VERSION 5.8 ;
BUSBITCHARS "[]" ;
DIVIDERCHAR "/" ;
UNITS
    DATABASE MICRONS 1000 ;
END UNITS

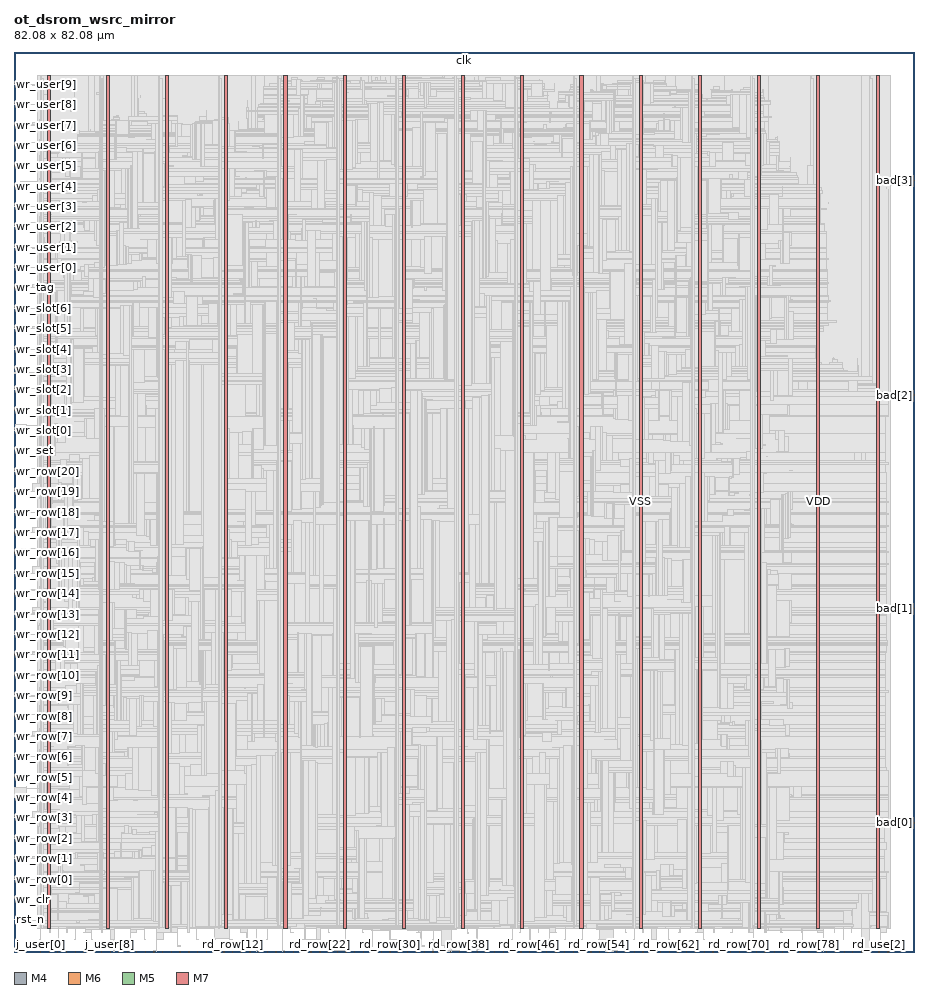
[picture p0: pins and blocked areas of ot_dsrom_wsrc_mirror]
MACRO ot_dsrom_wsrc_mirror
  FOREIGN ot_dsrom_wsrc_mirror 0 0 ;
  CLASS BLOCK ;
  SIZE 82.08 BY 82.08 ;
  PIN bad[0]
    DIRECTION OUTPUT ;
    USE SIGNAL ;
    PORT
      LAYER M4 ;
        RECT  81.996 11.76 82.08 11.784 ;
    END
  END bad[0]
  PIN bad[1]
    DIRECTION OUTPUT ;
    USE SIGNAL ;
    PORT
      LAYER M6 ;
        RECT  82.01 31.296 82.08 31.328 ;
    END
  END bad[1]
  PIN bad[2]
    DIRECTION OUTPUT ;
    USE SIGNAL ;
    PORT
      LAYER M4 ;
        RECT  81.996 50.784 82.08 50.808 ;
    END
  END bad[2]
  PIN bad[3]
    DIRECTION OUTPUT ;
    USE SIGNAL ;
    PORT
      LAYER M6 ;
        RECT  82.01 70.336 82.08 70.368 ;
    END
  END bad[3]
  PIN clk
    DIRECTION INPUT ;
    USE SIGNAL ;
    PORT
      LAYER M5 ;
        RECT  41.04 81.996 41.064 82.08 ;
    END
  END clk
  PIN j_user[0]
    DIRECTION INPUT ;
    USE SIGNAL ;
    PORT
      LAYER M5 ;
        RECT  2.4 0 2.424 0.084 ;
    END
  END j_user[0]
  PIN j_user[1]
    DIRECTION INPUT ;
    USE SIGNAL ;
    PORT
      LAYER M7 ;
        RECT  3.2 0 3.232 0.07 ;
    END
  END j_user[1]
  PIN j_user[2]
    DIRECTION INPUT ;
    USE SIGNAL ;
    PORT
      LAYER M5 ;
        RECT  3.984 0 4.008 0.084 ;
    END
  END j_user[2]
  PIN j_user[3]
    DIRECTION INPUT ;
    USE SIGNAL ;
    PORT
      LAYER M7 ;
        RECT  4.8 0 4.832 0.07 ;
    END
  END j_user[3]
  PIN j_user[4]
    DIRECTION INPUT ;
    USE SIGNAL ;
    PORT
      LAYER M5 ;
        RECT  5.568 0 5.592 0.084 ;
    END
  END j_user[4]
  PIN j_user[5]
    DIRECTION INPUT ;
    USE SIGNAL ;
    PORT
      LAYER M7 ;
        RECT  6.336 0 6.368 0.07 ;
    END
  END j_user[5]
  PIN j_user[6]
    DIRECTION INPUT ;
    USE SIGNAL ;
    PORT
      LAYER M5 ;
        RECT  7.152 0 7.176 0.084 ;
    END
  END j_user[6]
  PIN j_user[7]
    DIRECTION INPUT ;
    USE SIGNAL ;
    PORT
      LAYER M7 ;
        RECT  7.936 0 7.968 0.07 ;
    END
  END j_user[7]
  PIN j_user[8]
    DIRECTION INPUT ;
    USE SIGNAL ;
    PORT
      LAYER M5 ;
        RECT  8.784 0 8.808 0.084 ;
    END
  END j_user[8]
  PIN j_user[9]
    DIRECTION INPUT ;
    USE SIGNAL ;
    PORT
      LAYER M7 ;
        RECT  9.536 0 9.568 0.07 ;
    END
  END j_user[9]
  PIN rd_row[0]
    DIRECTION INPUT ;
    USE SIGNAL ;
    PORT
      LAYER M5 ;
        RECT  10.368 0 10.392 0.084 ;
    END
  END rd_row[0]
  PIN rd_row[10]
    DIRECTION INPUT ;
    USE SIGNAL ;
    PORT
      LAYER M5 ;
        RECT  18.336 0 18.36 0.084 ;
    END
  END rd_row[10]
  PIN rd_row[11]
    DIRECTION INPUT ;
    USE SIGNAL ;
    PORT
      LAYER M7 ;
        RECT  19.136 0 19.168 0.07 ;
    END
  END rd_row[11]
  PIN rd_row[12]
    DIRECTION INPUT ;
    USE SIGNAL ;
    PORT
      LAYER M5 ;
        RECT  19.92 0 19.944 0.084 ;
    END
  END rd_row[12]
  PIN rd_row[13]
    DIRECTION INPUT ;
    USE SIGNAL ;
    PORT
      LAYER M7 ;
        RECT  20.736 0 20.768 0.07 ;
    END
  END rd_row[13]
  PIN rd_row[14]
    DIRECTION INPUT ;
    USE SIGNAL ;
    PORT
      LAYER M5 ;
        RECT  21.504 0 21.528 0.084 ;
    END
  END rd_row[14]
  PIN rd_row[15]
    DIRECTION INPUT ;
    USE SIGNAL ;
    PORT
      LAYER M7 ;
        RECT  22.272 0 22.304 0.07 ;
    END
  END rd_row[15]
  PIN rd_row[16]
    DIRECTION INPUT ;
    USE SIGNAL ;
    PORT
      LAYER M5 ;
        RECT  23.088 0 23.112 0.084 ;
    END
  END rd_row[16]
  PIN rd_row[17]
    DIRECTION INPUT ;
    USE SIGNAL ;
    PORT
      LAYER M7 ;
        RECT  23.872 0 23.904 0.07 ;
    END
  END rd_row[17]
  PIN rd_row[18]
    DIRECTION INPUT ;
    USE SIGNAL ;
    PORT
      LAYER M5 ;
        RECT  24.672 0 24.696 0.084 ;
    END
  END rd_row[18]
  PIN rd_row[19]
    DIRECTION INPUT ;
    USE SIGNAL ;
    PORT
      LAYER M7 ;
        RECT  25.472 0 25.504 0.07 ;
    END
  END rd_row[19]
  PIN rd_row[1]
    DIRECTION INPUT ;
    USE SIGNAL ;
    PORT
      LAYER M7 ;
        RECT  11.136 0 11.168 0.07 ;
    END
  END rd_row[1]
  PIN rd_row[20]
    DIRECTION INPUT ;
    USE SIGNAL ;
    PORT
      LAYER M5 ;
        RECT  26.304 0 26.328 0.084 ;
    END
  END rd_row[20]
  PIN rd_row[21]
    DIRECTION INPUT ;
    USE SIGNAL ;
    PORT
      LAYER M7 ;
        RECT  27.072 0 27.104 0.07 ;
    END
  END rd_row[21]
  PIN rd_row[22]
    DIRECTION INPUT ;
    USE SIGNAL ;
    PORT
      LAYER M5 ;
        RECT  27.888 0 27.912 0.084 ;
    END
  END rd_row[22]
  PIN rd_row[23]
    DIRECTION INPUT ;
    USE SIGNAL ;
    PORT
      LAYER M7 ;
        RECT  28.672 0 28.704 0.07 ;
    END
  END rd_row[23]
  PIN rd_row[24]
    DIRECTION INPUT ;
    USE SIGNAL ;
    PORT
      LAYER M5 ;
        RECT  29.472 0 29.496 0.084 ;
    END
  END rd_row[24]
  PIN rd_row[25]
    DIRECTION INPUT ;
    USE SIGNAL ;
    PORT
      LAYER M7 ;
        RECT  30.272 0 30.304 0.07 ;
    END
  END rd_row[25]
  PIN rd_row[26]
    DIRECTION INPUT ;
    USE SIGNAL ;
    PORT
      LAYER M5 ;
        RECT  31.056 0 31.08 0.084 ;
    END
  END rd_row[26]
  PIN rd_row[27]
    DIRECTION INPUT ;
    USE SIGNAL ;
    PORT
      LAYER M7 ;
        RECT  31.872 0 31.904 0.07 ;
    END
  END rd_row[27]
  PIN rd_row[28]
    DIRECTION INPUT ;
    USE SIGNAL ;
    PORT
      LAYER M5 ;
        RECT  32.64 0 32.664 0.084 ;
    END
  END rd_row[28]
  PIN rd_row[29]
    DIRECTION INPUT ;
    USE SIGNAL ;
    PORT
      LAYER M7 ;
        RECT  33.472 0 33.504 0.07 ;
    END
  END rd_row[29]
  PIN rd_row[2]
    DIRECTION INPUT ;
    USE SIGNAL ;
    PORT
      LAYER M5 ;
        RECT  11.952 0 11.976 0.084 ;
    END
  END rd_row[2]
  PIN rd_row[30]
    DIRECTION INPUT ;
    USE SIGNAL ;
    PORT
      LAYER M5 ;
        RECT  34.272 0 34.296 0.084 ;
    END
  END rd_row[30]
  PIN rd_row[31]
    DIRECTION INPUT ;
    USE SIGNAL ;
    PORT
      LAYER M7 ;
        RECT  35.072 0 35.104 0.07 ;
    END
  END rd_row[31]
  PIN rd_row[32]
    DIRECTION INPUT ;
    USE SIGNAL ;
    PORT
      LAYER M5 ;
        RECT  35.856 0 35.88 0.084 ;
    END
  END rd_row[32]
  PIN rd_row[33]
    DIRECTION INPUT ;
    USE SIGNAL ;
    PORT
      LAYER M7 ;
        RECT  36.672 0 36.704 0.07 ;
    END
  END rd_row[33]
  PIN rd_row[34]
    DIRECTION INPUT ;
    USE SIGNAL ;
    PORT
      LAYER M5 ;
        RECT  37.44 0 37.464 0.084 ;
    END
  END rd_row[34]
  PIN rd_row[35]
    DIRECTION INPUT ;
    USE SIGNAL ;
    PORT
      LAYER M7 ;
        RECT  38.208 0 38.24 0.07 ;
    END
  END rd_row[35]
  PIN rd_row[36]
    DIRECTION INPUT ;
    USE SIGNAL ;
    PORT
      LAYER M5 ;
        RECT  39.024 0 39.048 0.084 ;
    END
  END rd_row[36]
  PIN rd_row[37]
    DIRECTION INPUT ;
    USE SIGNAL ;
    PORT
      LAYER M7 ;
        RECT  39.808 0 39.84 0.07 ;
    END
  END rd_row[37]
  PIN rd_row[38]
    DIRECTION INPUT ;
    USE SIGNAL ;
    PORT
      LAYER M5 ;
        RECT  40.608 0 40.632 0.084 ;
    END
  END rd_row[38]
  PIN rd_row[39]
    DIRECTION INPUT ;
    USE SIGNAL ;
    PORT
      LAYER M7 ;
        RECT  41.408 0 41.44 0.07 ;
    END
  END rd_row[39]
  PIN rd_row[3]
    DIRECTION INPUT ;
    USE SIGNAL ;
    PORT
      LAYER M7 ;
        RECT  12.736 0 12.768 0.07 ;
    END
  END rd_row[3]
  PIN rd_row[40]
    DIRECTION INPUT ;
    USE SIGNAL ;
    PORT
      LAYER M5 ;
        RECT  42.24 0 42.264 0.084 ;
    END
  END rd_row[40]
  PIN rd_row[41]
    DIRECTION INPUT ;
    USE SIGNAL ;
    PORT
      LAYER M7 ;
        RECT  43.008 0 43.04 0.07 ;
    END
  END rd_row[41]
  PIN rd_row[42]
    DIRECTION INPUT ;
    USE SIGNAL ;
    PORT
      LAYER M5 ;
        RECT  43.824 0 43.848 0.084 ;
    END
  END rd_row[42]
  PIN rd_row[43]
    DIRECTION INPUT ;
    USE SIGNAL ;
    PORT
      LAYER M7 ;
        RECT  44.608 0 44.64 0.07 ;
    END
  END rd_row[43]
  PIN rd_row[44]
    DIRECTION INPUT ;
    USE SIGNAL ;
    PORT
      LAYER M5 ;
        RECT  45.408 0 45.432 0.084 ;
    END
  END rd_row[44]
  PIN rd_row[45]
    DIRECTION INPUT ;
    USE SIGNAL ;
    PORT
      LAYER M7 ;
        RECT  46.208 0 46.24 0.07 ;
    END
  END rd_row[45]
  PIN rd_row[46]
    DIRECTION INPUT ;
    USE SIGNAL ;
    PORT
      LAYER M5 ;
        RECT  46.992 0 47.016 0.084 ;
    END
  END rd_row[46]
  PIN rd_row[47]
    DIRECTION INPUT ;
    USE SIGNAL ;
    PORT
      LAYER M7 ;
        RECT  47.808 0 47.84 0.07 ;
    END
  END rd_row[47]
  PIN rd_row[48]
    DIRECTION INPUT ;
    USE SIGNAL ;
    PORT
      LAYER M5 ;
        RECT  48.576 0 48.6 0.084 ;
    END
  END rd_row[48]
  PIN rd_row[49]
    DIRECTION INPUT ;
    USE SIGNAL ;
    PORT
      LAYER M7 ;
        RECT  49.408 0 49.44 0.07 ;
    END
  END rd_row[49]
  PIN rd_row[4]
    DIRECTION INPUT ;
    USE SIGNAL ;
    PORT
      LAYER M5 ;
        RECT  13.536 0 13.56 0.084 ;
    END
  END rd_row[4]
  PIN rd_row[50]
    DIRECTION INPUT ;
    USE SIGNAL ;
    PORT
      LAYER M5 ;
        RECT  50.208 0 50.232 0.084 ;
    END
  END rd_row[50]
  PIN rd_row[51]
    DIRECTION INPUT ;
    USE SIGNAL ;
    PORT
      LAYER M7 ;
        RECT  51.008 0 51.04 0.07 ;
    END
  END rd_row[51]
  PIN rd_row[52]
    DIRECTION INPUT ;
    USE SIGNAL ;
    PORT
      LAYER M5 ;
        RECT  51.792 0 51.816 0.084 ;
    END
  END rd_row[52]
  PIN rd_row[53]
    DIRECTION INPUT ;
    USE SIGNAL ;
    PORT
      LAYER M7 ;
        RECT  52.608 0 52.64 0.07 ;
    END
  END rd_row[53]
  PIN rd_row[54]
    DIRECTION INPUT ;
    USE SIGNAL ;
    PORT
      LAYER M5 ;
        RECT  53.376 0 53.4 0.084 ;
    END
  END rd_row[54]
  PIN rd_row[55]
    DIRECTION INPUT ;
    USE SIGNAL ;
    PORT
      LAYER M7 ;
        RECT  54.144 0 54.176 0.07 ;
    END
  END rd_row[55]
  PIN rd_row[56]
    DIRECTION INPUT ;
    USE SIGNAL ;
    PORT
      LAYER M5 ;
        RECT  54.96 0 54.984 0.084 ;
    END
  END rd_row[56]
  PIN rd_row[57]
    DIRECTION INPUT ;
    USE SIGNAL ;
    PORT
      LAYER M7 ;
        RECT  55.744 0 55.776 0.07 ;
    END
  END rd_row[57]
  PIN rd_row[58]
    DIRECTION INPUT ;
    USE SIGNAL ;
    PORT
      LAYER M5 ;
        RECT  56.544 0 56.568 0.084 ;
    END
  END rd_row[58]
  PIN rd_row[59]
    DIRECTION INPUT ;
    USE SIGNAL ;
    PORT
      LAYER M7 ;
        RECT  57.344 0 57.376 0.07 ;
    END
  END rd_row[59]
  PIN rd_row[5]
    DIRECTION INPUT ;
    USE SIGNAL ;
    PORT
      LAYER M7 ;
        RECT  14.336 0 14.368 0.07 ;
    END
  END rd_row[5]
  PIN rd_row[60]
    DIRECTION INPUT ;
    USE SIGNAL ;
    PORT
      LAYER M5 ;
        RECT  58.176 0 58.2 0.084 ;
    END
  END rd_row[60]
  PIN rd_row[61]
    DIRECTION INPUT ;
    USE SIGNAL ;
    PORT
      LAYER M7 ;
        RECT  58.944 0 58.976 0.07 ;
    END
  END rd_row[61]
  PIN rd_row[62]
    DIRECTION INPUT ;
    USE SIGNAL ;
    PORT
      LAYER M5 ;
        RECT  59.76 0 59.784 0.084 ;
    END
  END rd_row[62]
  PIN rd_row[63]
    DIRECTION INPUT ;
    USE SIGNAL ;
    PORT
      LAYER M7 ;
        RECT  60.544 0 60.576 0.07 ;
    END
  END rd_row[63]
  PIN rd_row[64]
    DIRECTION INPUT ;
    USE SIGNAL ;
    PORT
      LAYER M5 ;
        RECT  61.344 0 61.368 0.084 ;
    END
  END rd_row[64]
  PIN rd_row[65]
    DIRECTION INPUT ;
    USE SIGNAL ;
    PORT
      LAYER M7 ;
        RECT  62.144 0 62.176 0.07 ;
    END
  END rd_row[65]
  PIN rd_row[66]
    DIRECTION INPUT ;
    USE SIGNAL ;
    PORT
      LAYER M5 ;
        RECT  62.928 0 62.952 0.084 ;
    END
  END rd_row[66]
  PIN rd_row[67]
    DIRECTION INPUT ;
    USE SIGNAL ;
    PORT
      LAYER M7 ;
        RECT  63.744 0 63.776 0.07 ;
    END
  END rd_row[67]
  PIN rd_row[68]
    DIRECTION INPUT ;
    USE SIGNAL ;
    PORT
      LAYER M5 ;
        RECT  64.512 0 64.536 0.084 ;
    END
  END rd_row[68]
  PIN rd_row[69]
    DIRECTION INPUT ;
    USE SIGNAL ;
    PORT
      LAYER M7 ;
        RECT  65.344 0 65.376 0.07 ;
    END
  END rd_row[69]
  PIN rd_row[6]
    DIRECTION INPUT ;
    USE SIGNAL ;
    PORT
      LAYER M5 ;
        RECT  15.12 0 15.144 0.084 ;
    END
  END rd_row[6]
  PIN rd_row[70]
    DIRECTION INPUT ;
    USE SIGNAL ;
    PORT
      LAYER M5 ;
        RECT  66.144 0 66.168 0.084 ;
    END
  END rd_row[70]
  PIN rd_row[71]
    DIRECTION INPUT ;
    USE SIGNAL ;
    PORT
      LAYER M7 ;
        RECT  66.944 0 66.976 0.07 ;
    END
  END rd_row[71]
  PIN rd_row[72]
    DIRECTION INPUT ;
    USE SIGNAL ;
    PORT
      LAYER M5 ;
        RECT  67.728 0 67.752 0.084 ;
    END
  END rd_row[72]
  PIN rd_row[73]
    DIRECTION INPUT ;
    USE SIGNAL ;
    PORT
      LAYER M7 ;
        RECT  68.48 0 68.512 0.07 ;
    END
  END rd_row[73]
  PIN rd_row[74]
    DIRECTION INPUT ;
    USE SIGNAL ;
    PORT
      LAYER M5 ;
        RECT  69.312 0 69.336 0.084 ;
    END
  END rd_row[74]
  PIN rd_row[75]
    DIRECTION INPUT ;
    USE SIGNAL ;
    PORT
      LAYER M7 ;
        RECT  70.08 0 70.112 0.07 ;
    END
  END rd_row[75]
  PIN rd_row[76]
    DIRECTION INPUT ;
    USE SIGNAL ;
    PORT
      LAYER M5 ;
        RECT  70.896 0 70.92 0.084 ;
    END
  END rd_row[76]
  PIN rd_row[77]
    DIRECTION INPUT ;
    USE SIGNAL ;
    PORT
      LAYER M7 ;
        RECT  71.68 0 71.712 0.07 ;
    END
  END rd_row[77]
  PIN rd_row[78]
    DIRECTION INPUT ;
    USE SIGNAL ;
    PORT
      LAYER M5 ;
        RECT  72.48 0 72.504 0.084 ;
    END
  END rd_row[78]
  PIN rd_row[79]
    DIRECTION INPUT ;
    USE SIGNAL ;
    PORT
      LAYER M7 ;
        RECT  73.28 0 73.312 0.07 ;
    END
  END rd_row[79]
  PIN rd_row[7]
    DIRECTION INPUT ;
    USE SIGNAL ;
    PORT
      LAYER M7 ;
        RECT  15.936 0 15.968 0.07 ;
    END
  END rd_row[7]
  PIN rd_row[80]
    DIRECTION INPUT ;
    USE SIGNAL ;
    PORT
      LAYER M5 ;
        RECT  74.112 0 74.136 0.084 ;
    END
  END rd_row[80]
  PIN rd_row[81]
    DIRECTION INPUT ;
    USE SIGNAL ;
    PORT
      LAYER M7 ;
        RECT  74.88 0 74.912 0.07 ;
    END
  END rd_row[81]
  PIN rd_row[82]
    DIRECTION INPUT ;
    USE SIGNAL ;
    PORT
      LAYER M5 ;
        RECT  75.696 0 75.72 0.084 ;
    END
  END rd_row[82]
  PIN rd_row[83]
    DIRECTION INPUT ;
    USE SIGNAL ;
    PORT
      LAYER M7 ;
        RECT  76.48 0 76.512 0.07 ;
    END
  END rd_row[83]
  PIN rd_row[8]
    DIRECTION INPUT ;
    USE SIGNAL ;
    PORT
      LAYER M5 ;
        RECT  16.752 0 16.776 0.084 ;
    END
  END rd_row[8]
  PIN rd_row[9]
    DIRECTION INPUT ;
    USE SIGNAL ;
    PORT
      LAYER M7 ;
        RECT  17.536 0 17.568 0.07 ;
    END
  END rd_row[9]
  PIN rd_use[0]
    DIRECTION INPUT ;
    USE SIGNAL ;
    PORT
      LAYER M5 ;
        RECT  77.28 0 77.304 0.084 ;
    END
  END rd_use[0]
  PIN rd_use[1]
    DIRECTION INPUT ;
    USE SIGNAL ;
    PORT
      LAYER M7 ;
        RECT  78.08 0 78.112 0.07 ;
    END
  END rd_use[1]
  PIN rd_use[2]
    DIRECTION INPUT ;
    USE SIGNAL ;
    PORT
      LAYER M5 ;
        RECT  78.864 0 78.888 0.084 ;
    END
  END rd_use[2]
  PIN rd_use[3]
    DIRECTION INPUT ;
    USE SIGNAL ;
    PORT
      LAYER M7 ;
        RECT  79.68 0 79.712 0.07 ;
    END
  END rd_use[3]
  PIN rst_n
    DIRECTION INPUT ;
    USE SIGNAL ;
    PORT
      LAYER M4 ;
        RECT  0 2.928 0.084 2.952 ;
    END
  END rst_n
  PIN wr_clr
    DIRECTION INPUT ;
    USE SIGNAL ;
    PORT
      LAYER M6 ;
        RECT  0 4.8 0.07 4.832 ;
    END
  END wr_clr
  PIN wr_row[0]
    DIRECTION INPUT ;
    USE SIGNAL ;
    PORT
      LAYER M4 ;
        RECT  0 6.624 0.084 6.648 ;
    END
  END wr_row[0]
  PIN wr_row[10]
    DIRECTION INPUT ;
    USE SIGNAL ;
    PORT
      LAYER M4 ;
        RECT  0 25.248 0.084 25.272 ;
    END
  END wr_row[10]
  PIN wr_row[11]
    DIRECTION INPUT ;
    USE SIGNAL ;
    PORT
      LAYER M6 ;
        RECT  0 27.072 0.07 27.104 ;
    END
  END wr_row[11]
  PIN wr_row[12]
    DIRECTION INPUT ;
    USE SIGNAL ;
    PORT
      LAYER M4 ;
        RECT  0 28.944 0.084 28.968 ;
    END
  END wr_row[12]
  PIN wr_row[13]
    DIRECTION INPUT ;
    USE SIGNAL ;
    PORT
      LAYER M6 ;
        RECT  0 30.784 0.07 30.816 ;
    END
  END wr_row[13]
  PIN wr_row[14]
    DIRECTION INPUT ;
    USE SIGNAL ;
    PORT
      LAYER M4 ;
        RECT  0 32.64 0.084 32.664 ;
    END
  END wr_row[14]
  PIN wr_row[15]
    DIRECTION INPUT ;
    USE SIGNAL ;
    PORT
      LAYER M6 ;
        RECT  0 34.496 0.07 34.528 ;
    END
  END wr_row[15]
  PIN wr_row[16]
    DIRECTION INPUT ;
    USE SIGNAL ;
    PORT
      LAYER M4 ;
        RECT  0 36.384 0.084 36.408 ;
    END
  END wr_row[16]
  PIN wr_row[17]
    DIRECTION INPUT ;
    USE SIGNAL ;
    PORT
      LAYER M6 ;
        RECT  0 38.208 0.07 38.24 ;
    END
  END wr_row[17]
  PIN wr_row[18]
    DIRECTION INPUT ;
    USE SIGNAL ;
    PORT
      LAYER M4 ;
        RECT  0 40.08 0.084 40.104 ;
    END
  END wr_row[18]
  PIN wr_row[19]
    DIRECTION INPUT ;
    USE SIGNAL ;
    PORT
      LAYER M6 ;
        RECT  0 41.984 0.07 42.016 ;
    END
  END wr_row[19]
  PIN wr_row[1]
    DIRECTION INPUT ;
    USE SIGNAL ;
    PORT
      LAYER M6 ;
        RECT  0 8.512 0.07 8.544 ;
    END
  END wr_row[1]
  PIN wr_row[20]
    DIRECTION INPUT ;
    USE SIGNAL ;
    PORT
      LAYER M4 ;
        RECT  0 43.824 0.084 43.848 ;
    END
  END wr_row[20]
  PIN wr_row[2]
    DIRECTION INPUT ;
    USE SIGNAL ;
    PORT
      LAYER M4 ;
        RECT  0 10.368 0.084 10.392 ;
    END
  END wr_row[2]
  PIN wr_row[3]
    DIRECTION INPUT ;
    USE SIGNAL ;
    PORT
      LAYER M6 ;
        RECT  0 12.224 0.07 12.256 ;
    END
  END wr_row[3]
  PIN wr_row[4]
    DIRECTION INPUT ;
    USE SIGNAL ;
    PORT
      LAYER M4 ;
        RECT  0 14.064 0.084 14.088 ;
    END
  END wr_row[4]
  PIN wr_row[5]
    DIRECTION INPUT ;
    USE SIGNAL ;
    PORT
      LAYER M6 ;
        RECT  0 15.936 0.07 15.968 ;
    END
  END wr_row[5]
  PIN wr_row[6]
    DIRECTION INPUT ;
    USE SIGNAL ;
    PORT
      LAYER M4 ;
        RECT  0 17.808 0.084 17.832 ;
    END
  END wr_row[6]
  PIN wr_row[7]
    DIRECTION INPUT ;
    USE SIGNAL ;
    PORT
      LAYER M6 ;
        RECT  0 19.648 0.07 19.68 ;
    END
  END wr_row[7]
  PIN wr_row[8]
    DIRECTION INPUT ;
    USE SIGNAL ;
    PORT
      LAYER M4 ;
        RECT  0 21.504 0.084 21.528 ;
    END
  END wr_row[8]
  PIN wr_row[9]
    DIRECTION INPUT ;
    USE SIGNAL ;
    PORT
      LAYER M6 ;
        RECT  0 23.36 0.07 23.392 ;
    END
  END wr_row[9]
  PIN wr_set
    DIRECTION INPUT ;
    USE SIGNAL ;
    PORT
      LAYER M6 ;
        RECT  0 45.696 0.07 45.728 ;
    END
  END wr_set
  PIN wr_slot[0]
    DIRECTION INPUT ;
    USE SIGNAL ;
    PORT
      LAYER M4 ;
        RECT  0 47.52 0.084 47.544 ;
    END
  END wr_slot[0]
  PIN wr_slot[1]
    DIRECTION INPUT ;
    USE SIGNAL ;
    PORT
      LAYER M6 ;
        RECT  0 49.408 0.07 49.44 ;
    END
  END wr_slot[1]
  PIN wr_slot[2]
    DIRECTION INPUT ;
    USE SIGNAL ;
    PORT
      LAYER M4 ;
        RECT  0 51.264 0.084 51.288 ;
    END
  END wr_slot[2]
  PIN wr_slot[3]
    DIRECTION INPUT ;
    USE SIGNAL ;
    PORT
      LAYER M6 ;
        RECT  0 53.12 0.07 53.152 ;
    END
  END wr_slot[3]
  PIN wr_slot[4]
    DIRECTION INPUT ;
    USE SIGNAL ;
    PORT
      LAYER M4 ;
        RECT  0 54.96 0.084 54.984 ;
    END
  END wr_slot[4]
  PIN wr_slot[5]
    DIRECTION INPUT ;
    USE SIGNAL ;
    PORT
      LAYER M6 ;
        RECT  0 56.832 0.07 56.864 ;
    END
  END wr_slot[5]
  PIN wr_slot[6]
    DIRECTION INPUT ;
    USE SIGNAL ;
    PORT
      LAYER M4 ;
        RECT  0 58.704 0.084 58.728 ;
    END
  END wr_slot[6]
  PIN wr_tag
    DIRECTION INPUT ;
    USE SIGNAL ;
    PORT
      LAYER M6 ;
        RECT  0 60.544 0.07 60.576 ;
    END
  END wr_tag
  PIN wr_user[0]
    DIRECTION INPUT ;
    USE SIGNAL ;
    PORT
      LAYER M4 ;
        RECT  0 62.4 0.084 62.424 ;
    END
  END wr_user[0]
  PIN wr_user[1]
    DIRECTION INPUT ;
    USE SIGNAL ;
    PORT
      LAYER M6 ;
        RECT  0 64.256 0.07 64.288 ;
    END
  END wr_user[1]
  PIN wr_user[2]
    DIRECTION INPUT ;
    USE SIGNAL ;
    PORT
      LAYER M4 ;
        RECT  0 66.144 0.084 66.168 ;
    END
  END wr_user[2]
  PIN wr_user[3]
    DIRECTION INPUT ;
    USE SIGNAL ;
    PORT
      LAYER M6 ;
        RECT  0 67.968 0.07 68 ;
    END
  END wr_user[3]
  PIN wr_user[4]
    DIRECTION INPUT ;
    USE SIGNAL ;
    PORT
      LAYER M4 ;
        RECT  0 69.84 0.084 69.864 ;
    END
  END wr_user[4]
  PIN wr_user[5]
    DIRECTION INPUT ;
    USE SIGNAL ;
    PORT
      LAYER M6 ;
        RECT  0 71.68 0.07 71.712 ;
    END
  END wr_user[5]
  PIN wr_user[6]
    DIRECTION INPUT ;
    USE SIGNAL ;
    PORT
      LAYER M4 ;
        RECT  0 73.584 0.084 73.608 ;
    END
  END wr_user[6]
  PIN wr_user[7]
    DIRECTION INPUT ;
    USE SIGNAL ;
    PORT
      LAYER M6 ;
        RECT  0 75.392 0.07 75.424 ;
    END
  END wr_user[7]
  PIN wr_user[8]
    DIRECTION INPUT ;
    USE SIGNAL ;
    PORT
      LAYER M4 ;
        RECT  0 77.28 0.084 77.304 ;
    END
  END wr_user[8]
  PIN wr_user[9]
    DIRECTION INPUT ;
    USE SIGNAL ;
    PORT
      LAYER M6 ;
        RECT  0 79.104 0.07 79.136 ;
    END
  END wr_user[9]
  PIN VDD
    DIRECTION INOUT ;
    USE POWER ;
    PORT
      LAYER M7 ;
        RECT  73.216 2.151 73.504 79.929 ;
        RECT  62.416 2.151 62.704 79.929 ;
        RECT  51.616 2.151 51.904 79.929 ;
        RECT  40.816 2.151 41.104 79.929 ;
        RECT  30.016 2.151 30.304 79.929 ;
        RECT  19.216 2.151 19.504 79.929 ;
        RECT  8.416 2.151 8.704 79.929 ;
    END
  END VDD
  PIN VSS
    DIRECTION INOUT ;
    USE GROUND ;
    PORT
      LAYER M7 ;
        RECT  78.616 2.151 78.904 79.929 ;
        RECT  67.816 2.151 68.104 79.929 ;
        RECT  57.016 2.151 57.304 79.929 ;
        RECT  46.216 2.151 46.504 79.929 ;
        RECT  35.416 2.151 35.704 79.929 ;
        RECT  24.616 2.151 24.904 79.929 ;
        RECT  13.816 2.151 14.104 79.929 ;
        RECT  3.016 2.151 3.304 79.929 ;
    END
  END VSS
  OBS
    LAYER RVTN ;
     RECT  2.16 2.16 79.92 2.295 ;
     RECT  2.16 2.565 79.92 2.835 ;
     RECT  2.16 3.105 79.92 3.375 ;
     RECT  2.16 3.645 79.92 3.915 ;
     RECT  2.16 4.185 79.92 4.455 ;
     RECT  2.16 4.725 79.92 4.995 ;
     RECT  2.16 5.265 79.92 5.535 ;
     RECT  2.16 5.805 79.92 6.075 ;
     RECT  2.16 6.345 79.92 6.615 ;
     RECT  2.16 6.885 79.92 7.155 ;
     RECT  2.16 7.425 79.92 7.695 ;
     RECT  2.16 7.965 79.92 8.235 ;
     RECT  2.16 8.505 79.92 8.775 ;
     RECT  2.16 9.045 79.92 9.315 ;
     RECT  2.16 9.585 79.92 9.855 ;
     RECT  2.16 10.125 79.92 10.395 ;
     RECT  2.16 10.665 79.92 10.935 ;
     RECT  2.16 11.205 79.92 11.475 ;
     RECT  2.16 11.745 79.92 12.015 ;
     RECT  2.16 12.285 79.92 12.555 ;
     RECT  2.16 12.825 79.92 13.095 ;
     RECT  2.16 13.365 79.92 13.635 ;
     RECT  2.16 13.905 79.92 14.175 ;
     RECT  2.16 14.445 79.92 14.715 ;
     RECT  2.16 14.985 79.92 15.255 ;
     RECT  2.16 15.525 79.92 15.795 ;
     RECT  2.16 16.065 79.92 16.335 ;
     RECT  2.16 16.605 79.92 16.875 ;
     RECT  2.16 17.145 79.92 17.415 ;
     RECT  2.16 17.685 79.92 17.955 ;
     RECT  2.16 18.225 79.92 18.495 ;
     RECT  2.16 18.765 79.92 19.035 ;
     RECT  2.16 19.305 79.92 19.575 ;
     RECT  2.16 19.845 79.92 20.115 ;
     RECT  2.16 20.385 79.92 20.655 ;
     RECT  2.16 20.925 79.92 21.195 ;
     RECT  2.16 21.465 79.92 21.735 ;
     RECT  2.16 22.005 79.92 22.275 ;
     RECT  2.16 22.545 79.92 22.815 ;
     RECT  2.16 23.085 79.92 23.355 ;
     RECT  2.16 23.625 79.92 23.895 ;
     RECT  2.16 24.165 79.92 24.435 ;
     RECT  2.16 24.705 79.92 24.975 ;
     RECT  2.16 25.245 79.92 25.515 ;
     RECT  2.16 25.785 79.92 26.055 ;
     RECT  2.16 26.325 79.92 26.595 ;
     RECT  2.16 26.865 79.92 27.135 ;
     RECT  2.16 27.405 79.92 27.675 ;
     RECT  2.16 27.945 79.92 28.215 ;
     RECT  2.16 28.485 79.92 28.755 ;
     RECT  2.16 29.025 79.92 29.295 ;
     RECT  2.16 29.565 79.92 29.835 ;
     RECT  2.16 30.105 79.92 30.375 ;
     RECT  2.16 30.645 79.92 30.915 ;
     RECT  2.16 31.185 79.92 31.455 ;
     RECT  2.16 31.725 79.92 31.995 ;
     RECT  2.16 32.265 79.92 32.535 ;
     RECT  2.16 32.805 79.92 33.075 ;
     RECT  2.16 33.345 79.92 33.615 ;
     RECT  2.16 33.885 79.92 34.155 ;
     RECT  2.16 34.425 79.92 34.695 ;
     RECT  2.16 34.965 79.92 35.235 ;
     RECT  2.16 35.505 79.92 35.775 ;
     RECT  2.16 36.045 79.92 36.315 ;
     RECT  2.16 36.585 79.92 36.855 ;
     RECT  2.16 37.125 79.92 37.395 ;
     RECT  2.16 37.665 79.92 37.935 ;
     RECT  2.16 38.205 79.92 38.475 ;
     RECT  2.16 38.745 79.92 39.015 ;
     RECT  2.16 39.285 79.92 39.555 ;
     RECT  2.16 39.825 79.92 40.095 ;
     RECT  2.16 40.365 79.92 40.635 ;
     RECT  2.16 40.905 79.92 41.175 ;
     RECT  2.16 41.445 79.92 41.715 ;
     RECT  2.16 41.985 79.92 42.255 ;
     RECT  2.16 42.525 79.92 42.795 ;
     RECT  2.16 43.065 79.92 43.335 ;
     RECT  2.16 43.605 79.92 43.875 ;
     RECT  2.16 44.145 79.92 44.415 ;
     RECT  2.16 44.685 79.92 44.955 ;
     RECT  2.16 45.225 79.92 45.495 ;
     RECT  2.16 45.765 79.92 46.035 ;
     RECT  2.16 46.305 79.92 46.575 ;
     RECT  2.16 46.845 79.92 47.115 ;
     RECT  2.16 47.385 79.92 47.655 ;
     RECT  2.16 47.925 79.92 48.195 ;
     RECT  2.16 48.465 79.92 48.735 ;
     RECT  2.16 49.005 79.92 49.275 ;
     RECT  2.16 49.545 79.92 49.815 ;
     RECT  2.16 50.085 79.92 50.355 ;
     RECT  2.16 50.625 79.92 50.895 ;
     RECT  2.16 51.165 79.92 51.435 ;
     RECT  2.16 51.705 79.92 51.975 ;
     RECT  2.16 52.245 79.92 52.515 ;
     RECT  2.16 52.785 79.92 53.055 ;
     RECT  2.16 53.325 79.92 53.595 ;
     RECT  2.16 53.865 79.92 54.135 ;
     RECT  2.16 54.405 79.92 54.675 ;
     RECT  2.16 54.945 79.92 55.215 ;
     RECT  2.16 55.485 79.92 55.755 ;
     RECT  2.16 56.025 79.92 56.295 ;
     RECT  2.16 56.565 79.92 56.835 ;
     RECT  2.16 57.105 79.92 57.375 ;
     RECT  2.16 57.645 79.92 57.915 ;
     RECT  2.16 58.185 79.92 58.455 ;
     RECT  2.16 58.725 79.92 58.995 ;
     RECT  2.16 59.265 79.92 59.535 ;
     RECT  2.16 59.805 79.92 60.075 ;
     RECT  2.16 60.345 79.92 60.615 ;
     RECT  2.16 60.885 79.92 61.155 ;
     RECT  2.16 61.425 79.92 61.695 ;
     RECT  2.16 61.965 79.92 62.235 ;
     RECT  2.16 62.505 79.92 62.775 ;
     RECT  2.16 63.045 79.92 63.315 ;
     RECT  2.16 63.585 79.92 63.855 ;
     RECT  2.16 64.125 79.92 64.395 ;
     RECT  2.16 64.665 79.92 64.935 ;
     RECT  2.16 65.205 79.92 65.475 ;
     RECT  2.16 65.745 79.92 66.015 ;
     RECT  2.16 66.285 79.92 66.555 ;
     RECT  2.16 66.825 79.92 67.095 ;
     RECT  2.16 67.365 79.92 67.635 ;
     RECT  2.16 67.905 79.92 68.175 ;
     RECT  2.16 68.445 79.92 68.715 ;
     RECT  2.16 68.985 79.92 69.255 ;
     RECT  2.16 69.525 79.92 69.795 ;
     RECT  2.16 70.065 79.92 70.335 ;
     RECT  2.16 70.605 79.92 70.875 ;
     RECT  2.16 71.145 79.92 71.415 ;
     RECT  2.16 71.685 79.92 71.955 ;
     RECT  2.16 72.225 79.92 72.495 ;
     RECT  2.16 72.765 79.92 73.035 ;
     RECT  2.16 73.305 79.92 73.575 ;
     RECT  2.16 73.845 79.92 74.115 ;
     RECT  2.16 74.385 79.92 74.655 ;
     RECT  2.16 74.925 79.92 75.195 ;
     RECT  2.16 75.465 79.92 75.735 ;
     RECT  2.16 76.005 79.92 76.275 ;
     RECT  2.16 76.545 79.92 76.815 ;
     RECT  2.16 77.085 79.92 77.355 ;
     RECT  2.16 77.625 79.92 77.895 ;
     RECT  2.16 78.165 79.92 78.435 ;
     RECT  2.16 78.705 79.92 78.975 ;
     RECT  2.16 79.245 79.92 79.515 ;
     RECT  2.16 79.785 79.92 79.92 ;
    LAYER RVTP ;
     RECT  2.16 2.295 79.92 2.565 ;
     RECT  2.16 2.835 79.92 3.105 ;
     RECT  2.16 3.375 79.92 3.645 ;
     RECT  2.16 3.915 79.92 4.185 ;
     RECT  2.16 4.455 79.92 4.725 ;
     RECT  2.16 4.995 79.92 5.265 ;
     RECT  2.16 5.535 79.92 5.805 ;
     RECT  2.16 6.075 79.92 6.345 ;
     RECT  2.16 6.615 79.92 6.885 ;
     RECT  2.16 7.155 79.92 7.425 ;
     RECT  2.16 7.695 79.92 7.965 ;
     RECT  2.16 8.235 79.92 8.505 ;
     RECT  2.16 8.775 79.92 9.045 ;
     RECT  2.16 9.315 79.92 9.585 ;
     RECT  2.16 9.855 79.92 10.125 ;
     RECT  2.16 10.395 79.92 10.665 ;
     RECT  2.16 10.935 79.92 11.205 ;
     RECT  2.16 11.475 79.92 11.745 ;
     RECT  2.16 12.015 79.92 12.285 ;
     RECT  2.16 12.555 79.92 12.825 ;
     RECT  2.16 13.095 79.92 13.365 ;
     RECT  2.16 13.635 79.92 13.905 ;
     RECT  2.16 14.175 79.92 14.445 ;
     RECT  2.16 14.715 79.92 14.985 ;
     RECT  2.16 15.255 79.92 15.525 ;
     RECT  2.16 15.795 79.92 16.065 ;
     RECT  2.16 16.335 79.92 16.605 ;
     RECT  2.16 16.875 79.92 17.145 ;
     RECT  2.16 17.415 79.92 17.685 ;
     RECT  2.16 17.955 79.92 18.225 ;
     RECT  2.16 18.495 79.92 18.765 ;
     RECT  2.16 19.035 79.92 19.305 ;
     RECT  2.16 19.575 79.92 19.845 ;
     RECT  2.16 20.115 79.92 20.385 ;
     RECT  2.16 20.655 79.92 20.925 ;
     RECT  2.16 21.195 79.92 21.465 ;
     RECT  2.16 21.735 79.92 22.005 ;
     RECT  2.16 22.275 79.92 22.545 ;
     RECT  2.16 22.815 79.92 23.085 ;
     RECT  2.16 23.355 79.92 23.625 ;
     RECT  2.16 23.895 79.92 24.165 ;
     RECT  2.16 24.435 79.92 24.705 ;
     RECT  2.16 24.975 79.92 25.245 ;
     RECT  2.16 25.515 79.92 25.785 ;
     RECT  2.16 26.055 79.92 26.325 ;
     RECT  2.16 26.595 79.92 26.865 ;
     RECT  2.16 27.135 79.92 27.405 ;
     RECT  2.16 27.675 79.92 27.945 ;
     RECT  2.16 28.215 79.92 28.485 ;
     RECT  2.16 28.755 79.92 29.025 ;
     RECT  2.16 29.295 79.92 29.565 ;
     RECT  2.16 29.835 79.92 30.105 ;
     RECT  2.16 30.375 79.92 30.645 ;
     RECT  2.16 30.915 79.92 31.185 ;
     RECT  2.16 31.455 79.92 31.725 ;
     RECT  2.16 31.995 79.92 32.265 ;
     RECT  2.16 32.535 79.92 32.805 ;
     RECT  2.16 33.075 79.92 33.345 ;
     RECT  2.16 33.615 79.92 33.885 ;
     RECT  2.16 34.155 79.92 34.425 ;
     RECT  2.16 34.695 79.92 34.965 ;
     RECT  2.16 35.235 79.92 35.505 ;
     RECT  2.16 35.775 79.92 36.045 ;
     RECT  2.16 36.315 79.92 36.585 ;
     RECT  2.16 36.855 79.92 37.125 ;
     RECT  2.16 37.395 79.92 37.665 ;
     RECT  2.16 37.935 79.92 38.205 ;
     RECT  2.16 38.475 79.92 38.745 ;
     RECT  2.16 39.015 79.92 39.285 ;
     RECT  2.16 39.555 79.92 39.825 ;
     RECT  2.16 40.095 79.92 40.365 ;
     RECT  2.16 40.635 79.92 40.905 ;
     RECT  2.16 41.175 79.92 41.445 ;
     RECT  2.16 41.715 79.92 41.985 ;
     RECT  2.16 42.255 79.92 42.525 ;
     RECT  2.16 42.795 79.92 43.065 ;
     RECT  2.16 43.335 79.92 43.605 ;
     RECT  2.16 43.875 79.92 44.145 ;
     RECT  2.16 44.415 79.92 44.685 ;
     RECT  2.16 44.955 79.92 45.225 ;
     RECT  2.16 45.495 79.92 45.765 ;
     RECT  2.16 46.035 79.92 46.305 ;
     RECT  2.16 46.575 79.92 46.845 ;
     RECT  2.16 47.115 79.92 47.385 ;
     RECT  2.16 47.655 79.92 47.925 ;
     RECT  2.16 48.195 79.92 48.465 ;
     RECT  2.16 48.735 79.92 49.005 ;
     RECT  2.16 49.275 79.92 49.545 ;
     RECT  2.16 49.815 79.92 50.085 ;
     RECT  2.16 50.355 79.92 50.625 ;
     RECT  2.16 50.895 79.92 51.165 ;
     RECT  2.16 51.435 79.92 51.705 ;
     RECT  2.16 51.975 79.92 52.245 ;
     RECT  2.16 52.515 79.92 52.785 ;
     RECT  2.16 53.055 79.92 53.325 ;
     RECT  2.16 53.595 79.92 53.865 ;
     RECT  2.16 54.135 79.92 54.405 ;
     RECT  2.16 54.675 79.92 54.945 ;
     RECT  2.16 55.215 79.92 55.485 ;
     RECT  2.16 55.755 79.92 56.025 ;
     RECT  2.16 56.295 79.92 56.565 ;
     RECT  2.16 56.835 79.92 57.105 ;
     RECT  2.16 57.375 79.92 57.645 ;
     RECT  2.16 57.915 79.92 58.185 ;
     RECT  2.16 58.455 79.92 58.725 ;
     RECT  2.16 58.995 79.92 59.265 ;
     RECT  2.16 59.535 79.92 59.805 ;
     RECT  2.16 60.075 79.92 60.345 ;
     RECT  2.16 60.615 79.92 60.885 ;
     RECT  2.16 61.155 79.92 61.425 ;
     RECT  2.16 61.695 79.92 61.965 ;
     RECT  2.16 62.235 79.92 62.505 ;
     RECT  2.16 62.775 79.92 63.045 ;
     RECT  2.16 63.315 79.92 63.585 ;
     RECT  2.16 63.855 79.92 64.125 ;
     RECT  2.16 64.395 79.92 64.665 ;
     RECT  2.16 64.935 79.92 65.205 ;
     RECT  2.16 65.475 79.92 65.745 ;
     RECT  2.16 66.015 79.92 66.285 ;
     RECT  2.16 66.555 79.92 66.825 ;
     RECT  2.16 67.095 79.92 67.365 ;
     RECT  2.16 67.635 79.92 67.905 ;
     RECT  2.16 68.175 79.92 68.445 ;
     RECT  2.16 68.715 79.92 68.985 ;
     RECT  2.16 69.255 79.92 69.525 ;
     RECT  2.16 69.795 79.92 70.065 ;
     RECT  2.16 70.335 79.92 70.605 ;
     RECT  2.16 70.875 79.92 71.145 ;
     RECT  2.16 71.415 79.92 71.685 ;
     RECT  2.16 71.955 79.92 72.225 ;
     RECT  2.16 72.495 79.92 72.765 ;
     RECT  2.16 73.035 79.92 73.305 ;
     RECT  2.16 73.575 79.92 73.845 ;
     RECT  2.16 74.115 79.92 74.385 ;
     RECT  2.16 74.655 79.92 74.925 ;
     RECT  2.16 75.195 79.92 75.465 ;
     RECT  2.16 75.735 79.92 76.005 ;
     RECT  2.16 76.275 79.92 76.545 ;
     RECT  2.16 76.815 79.92 77.085 ;
     RECT  2.16 77.355 79.92 77.625 ;
     RECT  2.16 77.895 79.92 78.165 ;
     RECT  2.16 78.435 79.92 78.705 ;
     RECT  2.16 78.975 79.92 79.245 ;
     RECT  2.16 79.515 79.92 79.785 ;
    LAYER M1 ;
     RECT  2.16 2.151 79.92 79.929 ;
    LAYER M2 ;
     RECT  0.103 48.096 1.147 48.114 ;
     RECT  1.147 48.006 1.175 48.114 ;
     RECT  0.103 2.844 2.16 2.862 ;
     RECT  1.723 8.712 2.16 8.73 ;
     RECT  1.723 12.762 2.16 12.78 ;
     RECT  1.147 14.112 2.16 14.13 ;
     RECT  1.723 20.052 2.16 20.07 ;
     RECT  0.571 21.672 2.16 21.69 ;
     RECT  1.687 25.29 2.16 25.308 ;
     RECT  1.723 27.342 2.16 27.36 ;
     RECT  1.723 31.392 2.16 31.41 ;
     RECT  1.147 33.012 2.16 33.03 ;
     RECT  1.723 35.172 2.16 35.19 ;
     RECT  0.571 36.792 2.16 36.81 ;
     RECT  1.723 38.682 2.16 38.7 ;
     RECT  1.723 42.732 2.16 42.75 ;
     RECT  0.571 44.082 2.16 44.1 ;
     RECT  1.175 48.006 2.16 48.024 ;
     RECT  0.571 51.372 2.16 51.39 ;
     RECT  1.723 57.042 2.16 57.06 ;
     RECT  1.723 60.822 2.16 60.84 ;
     RECT  1.147 62.442 2.16 62.46 ;
     RECT  1.723 64.17 2.16 64.188 ;
     RECT  1.147 66.492 2.16 66.51 ;
     RECT  0.571 70.272 2.16 70.29 ;
     RECT  1.147 73.782 2.16 73.8 ;
     RECT  1.723 75.672 2.16 75.69 ;
     RECT  1.147 77.292 2.16 77.31 ;
     RECT  1.723 79.02 2.16 79.038 ;
     RECT  2.16 2.151 6.835 79.929 ;
     RECT  6.835 2.106 7.375 79.929 ;
     RECT  7.375 2.034 8.123 79.929 ;
     RECT  8.123 2.151 10.759 79.929 ;
     RECT  10.759 2.106 11.011 79.929 ;
     RECT  11.011 2.07 11.291 79.929 ;
     RECT  11.291 2.106 13.163 79.929 ;
     RECT  13.163 2.151 21.667 79.929 ;
     RECT  21.667 2.106 21.983 79.929 ;
     RECT  21.983 2.151 22.819 79.929 ;
     RECT  22.819 2.106 24.431 79.929 ;
     RECT  24.431 2.151 32.323 79.929 ;
     RECT  32.323 2.034 32.575 79.929 ;
     RECT  32.575 1.998 33.439 79.929 ;
     RECT  33.439 1.926 34.295 79.929 ;
     RECT  34.295 2.034 35.887 79.929 ;
     RECT  38.191 1.152 38.291 1.17 ;
     RECT  35.887 1.962 39.055 79.929 ;
     RECT  39.055 1.728 39.299 79.929 ;
     RECT  39.299 2.034 40.379 79.929 ;
     RECT  40.379 2.106 42.359 79.929 ;
     RECT  42.359 2.151 51.547 79.929 ;
     RECT  51.547 2.106 53.167 79.929 ;
     RECT  53.167 2.07 53.519 79.929 ;
     RECT  53.519 2.106 56.399 79.929 ;
     RECT  56.399 2.151 57.631 79.929 ;
     RECT  57.631 2.106 59.459 79.929 ;
     RECT  59.459 2.151 60.295 79.929 ;
     RECT  60.295 2.106 64.823 79.929 ;
     RECT  64.823 2.151 68.827 79.929 ;
     RECT  68.827 1.998 73.247 79.929 ;
     RECT  73.247 2.106 77.279 79.929 ;
     RECT  77.279 2.151 79.92 79.929 ;
     RECT  79.92 30.996 80.879 31.014 ;
     RECT  79.92 50.796 80.951 50.814 ;
     RECT  79.92 69.876 81.455 69.894 ;
    LAYER M3 ;
     RECT  42.228 0.091 42.246 0.187 ;
     RECT  39.276 0.091 39.942 0.571 ;
     RECT  9.108 0.091 9.126 1.147 ;
     RECT  12.96 0.091 12.978 1.147 ;
     RECT  34.272 0.571 34.29 1.147 ;
     RECT  38.196 0.091 38.214 1.147 ;
     RECT  53.964 0.091 54.702 1.147 ;
     RECT  58.572 0.091 58.59 1.147 ;
     RECT  38.196 1.147 38.286 1.175 ;
     RECT  18.288 1.147 18.306 1.195 ;
     RECT  19.62 1.147 19.638 1.195 ;
     RECT  7.092 1.147 7.11 1.771 ;
     RECT  10.62 1.147 10.638 1.771 ;
     RECT  12.96 1.147 13.59 1.771 ;
     RECT  14.904 0.523 14.922 1.771 ;
     RECT  21.24 1.147 21.258 1.771 ;
     RECT  37.116 0.523 37.134 1.771 ;
     RECT  48.852 1.147 48.87 1.771 ;
     RECT  62.892 1.147 62.91 1.771 ;
     RECT  67.464 1.147 67.482 1.771 ;
     RECT  71.892 1.147 71.91 1.771 ;
     RECT  73.8 0.091 73.818 1.771 ;
     RECT  79.02 1.147 79.038 1.771 ;
     RECT  36.9 1.771 37.134 1.957 ;
     RECT  38.268 1.175 38.286 1.957 ;
     RECT  32.652 0.523 32.67 1.993 ;
     RECT  33.444 1.921 33.462 1.993 ;
     RECT  34.272 1.147 34.326 1.993 ;
     RECT  68.58 1.771 68.598 1.993 ;
     RECT  73.26 1.771 73.818 1.993 ;
     RECT  6.552 1.771 7.11 2.029 ;
     RECT  7.956 1.771 7.974 2.029 ;
     RECT  8.82 1.147 9.126 2.029 ;
     RECT  31.788 1.771 31.806 2.029 ;
     RECT  32.58 1.993 32.67 2.029 ;
     RECT  33.444 1.993 34.326 2.029 ;
     RECT  35.892 1.957 35.91 2.029 ;
     RECT  36.9 1.957 38.286 2.029 ;
     RECT  39.024 0.571 39.942 2.029 ;
     RECT  10.62 1.771 11.178 2.065 ;
     RECT  11.916 1.147 11.934 2.065 ;
     RECT  53.388 1.147 54.702 2.065 ;
     RECT  20.7 1.771 21.258 2.101 ;
     RECT  22.104 0.091 22.122 2.101 ;
     RECT  23.076 1.147 23.094 2.101 ;
     RECT  24.48 0.091 24.498 2.101 ;
     RECT  31.788 2.029 32.67 2.101 ;
     RECT  33.444 2.029 34.974 2.101 ;
     RECT  35.892 2.029 40.374 2.101 ;
     RECT  41.364 1.723 41.382 2.101 ;
     RECT  42.192 0.187 42.246 2.101 ;
     RECT  51.804 1.147 51.822 2.101 ;
     RECT  53.172 2.065 54.702 2.101 ;
     RECT  55.764 1.771 55.782 2.101 ;
     RECT  56.556 1.147 56.574 2.101 ;
     RECT  57.348 1.771 57.366 2.101 ;
     RECT  58.14 1.147 58.59 2.101 ;
     RECT  59.688 1.147 59.706 2.101 ;
     RECT  60.732 1.771 60.75 2.101 ;
     RECT  65.484 1.771 65.502 2.101 ;
     RECT  73.224 1.993 73.818 2.101 ;
     RECT  77.256 0.091 77.994 2.129 ;
     RECT  2.376 1.147 2.394 2.143 ;
     RECT  20.7 2.101 23.382 2.143 ;
     RECT  24.408 2.101 24.498 2.143 ;
     RECT  28.692 1.771 28.71 2.143 ;
     RECT  45.432 1.147 45.45 2.143 ;
     RECT  46.188 1.771 46.206 2.143 ;
     RECT  51.552 2.101 52.254 2.143 ;
     RECT  62.352 1.771 62.91 2.143 ;
     RECT  71.784 1.771 71.91 2.143 ;
     RECT  73.08 2.101 73.818 2.143 ;
     RECT  77.976 2.129 77.994 2.143 ;
     RECT  5.58 1.147 5.598 2.191 ;
     RECT  6.552 2.029 9.126 2.191 ;
     RECT  10.62 2.065 11.934 2.191 ;
     RECT  15.876 1.771 15.894 2.191 ;
     RECT  18.288 1.195 19.638 2.191 ;
     RECT  20.7 2.143 24.498 2.191 ;
     RECT  25.236 1.771 25.254 2.191 ;
     RECT  28.692 2.143 29.505 2.191 ;
     RECT  30.24 0.091 30.258 2.191 ;
     RECT  31.788 2.101 40.374 2.191 ;
     RECT  45.432 2.143 46.206 2.191 ;
     RECT  47.052 1.147 47.07 2.191 ;
     RECT  47.844 1.771 47.862 2.191 ;
     RECT  48.852 1.771 49.41 2.191 ;
     RECT  57.348 2.101 58.59 2.191 ;
     RECT  61.815 2.143 62.91 2.191 ;
     RECT  63.828 1.771 63.846 2.191 ;
     RECT  64.8 2.101 65.502 2.191 ;
     RECT  66.96 1.771 67.482 2.191 ;
     RECT  68.58 1.993 68.85 2.191 ;
     RECT  71.784 2.143 73.818 2.191 ;
     RECT  79.02 1.771 79.578 2.191 ;
     RECT  4.824 1.771 4.842 2.227 ;
     RECT  5.58 2.191 5.742 2.227 ;
     RECT  6.552 2.191 9.81 2.227 ;
     RECT  10.62 2.191 12.114 2.227 ;
     RECT  12.96 1.771 14.922 2.227 ;
     RECT  15.696 2.191 15.894 2.227 ;
     RECT  16.668 1.147 16.686 2.227 ;
     RECT  18.288 2.191 25.254 2.227 ;
     RECT  27.576 1.147 27.918 2.227 ;
     RECT  28.692 2.191 40.374 2.227 ;
     RECT  64.8 2.191 66.222 2.227 ;
     RECT  66.96 2.191 68.994 2.227 ;
     RECT  69.948 1.771 69.966 2.227 ;
     RECT  71.136 2.191 73.998 2.227 ;
     RECT  74.808 1.771 74.826 2.227 ;
     RECT  27.576 2.227 40.374 2.251 ;
     RECT  41.364 2.101 42.354 2.251 ;
     RECT  2.376 2.143 2.505 2.255 ;
     RECT  77.976 2.143 78.105 2.255 ;
     RECT  2.415 2.255 2.505 2.263 ;
     RECT  3.276 1.771 3.294 2.263 ;
     RECT  4.824 2.227 9.81 2.263 ;
     RECT  10.62 2.227 14.922 2.263 ;
     RECT  15.696 2.227 17.118 2.263 ;
     RECT  18.216 2.227 25.254 2.263 ;
     RECT  43.812 2.227 43.83 2.263 ;
     RECT  53.172 2.101 54.918 2.263 ;
     RECT  55.764 2.101 56.574 2.263 ;
     RECT  57.348 2.191 58.698 2.263 ;
     RECT  61.815 2.191 63.846 2.263 ;
     RECT  64.8 2.227 70.182 2.263 ;
     RECT  70.956 2.227 74.826 2.263 ;
     RECT  76.392 1.771 76.41 2.263 ;
     RECT  79.02 2.191 79.722 2.291 ;
     RECT  4.032 1.147 4.05 2.299 ;
     RECT  4.824 2.263 14.922 2.299 ;
     RECT  43.74 2.263 43.83 2.299 ;
     RECT  46.944 2.191 49.41 2.299 ;
     RECT  50.256 1.147 50.274 2.299 ;
     RECT  26.532 1.147 26.55 2.335 ;
     RECT  27.576 2.251 42.354 2.335 ;
     RECT  59.436 2.101 60.75 2.335 ;
     RECT  61.704 2.263 63.846 2.335 ;
     RECT  64.62 2.263 74.826 2.335 ;
     RECT  75.636 1.147 75.654 2.335 ;
     RECT  76.392 2.263 76.446 2.335 ;
     RECT  2.415 2.263 3.294 2.371 ;
     RECT  4.032 2.299 14.922 2.371 ;
     RECT  15.696 2.263 25.254 2.371 ;
     RECT  26.532 2.335 42.354 2.371 ;
     RECT  43.164 2.299 43.83 2.371 ;
     RECT  45.324 2.191 46.206 2.371 ;
     RECT  46.944 2.299 50.274 2.371 ;
     RECT  51.015 2.143 52.254 2.371 ;
     RECT  53.172 2.263 58.698 2.371 ;
     RECT  59.436 2.335 75.654 2.371 ;
     RECT  76.392 2.335 76.518 2.371 ;
     RECT  78.015 2.255 78.105 2.371 ;
     RECT  78.015 2.371 78.174 2.413 ;
     RECT  78.912 2.371 78.966 2.413 ;
     RECT  26.496 2.371 44.37 2.461 ;
     RECT  45.324 2.371 52.254 2.461 ;
     RECT  53.172 2.371 76.518 2.489 ;
     RECT  26.496 2.461 52.254 2.569 ;
     RECT  53.172 2.489 76.446 2.569 ;
     RECT  26.496 2.569 76.446 2.597 ;
     RECT  2.415 2.371 25.758 2.641 ;
     RECT  26.496 2.597 75.654 2.641 ;
     RECT  2.415 2.641 75.654 2.831 ;
     RECT  0.108 2.839 0.126 2.957 ;
     RECT  78.015 2.413 78.966 3.343 ;
     RECT  79.704 2.291 79.722 3.343 ;
     RECT  76.428 2.597 76.446 3.37 ;
     RECT  2.415 2.831 20.502 3.605 ;
     RECT  78.015 3.343 79.722 3.605 ;
     RECT  3.42 3.605 20.502 3.721 ;
     RECT  21.276 2.831 75.654 3.721 ;
     RECT  78.015 3.605 79.578 3.721 ;
     RECT  77.904 3.721 79.578 3.725 ;
     RECT  3.42 3.721 75.654 3.811 ;
     RECT  76.392 3.37 76.446 3.811 ;
     RECT  3.42 3.811 76.446 3.955 ;
     RECT  3.42 3.955 76.806 3.983 ;
     RECT  3.996 3.983 76.806 4.415 ;
     RECT  28.44 4.415 76.806 4.531 ;
     RECT  28.44 4.531 76.986 4.685 ;
     RECT  4.968 4.415 27.63 5.233 ;
     RECT  3.996 4.415 4.05 5.269 ;
     RECT  3.456 5.269 4.05 5.305 ;
     RECT  4.968 5.233 27.882 5.305 ;
     RECT  28.692 4.685 76.986 5.341 ;
     RECT  77.904 3.725 78.297 5.341 ;
     RECT  28.692 5.341 78.297 5.357 ;
     RECT  41.976 5.357 78.297 5.567 ;
     RECT  3.456 5.305 27.882 5.701 ;
     RECT  28.692 5.357 41.166 5.701 ;
     RECT  2.415 3.605 2.697 5.881 ;
     RECT  3.456 5.701 41.166 5.881 ;
     RECT  2.376 5.881 41.166 6.385 ;
     RECT  42.012 5.567 78.297 6.385 ;
     RECT  2.376 6.385 78.297 6.619 ;
     RECT  2.34 6.619 78.297 6.691 ;
     RECT  79.02 3.725 79.578 6.691 ;
     RECT  2.34 6.691 79.578 6.925 ;
     RECT  2.304 6.925 79.578 7.231 ;
     RECT  2.304 7.231 79.722 7.385 ;
     RECT  2.304 7.385 79.362 8.491 ;
     RECT  1.728 8.491 79.362 8.735 ;
     RECT  2.304 8.735 79.362 9.391 ;
     RECT  2.304 9.391 79.578 9.959 ;
     RECT  2.304 9.959 79.362 10.363 ;
     RECT  2.268 10.363 79.362 11.435 ;
     RECT  2.304 11.435 79.362 11.755 ;
     RECT  2.304 11.755 79.758 12.235 ;
     RECT  1.728 12.235 79.758 12.785 ;
     RECT  2.34 12.785 79.758 13.873 ;
     RECT  2.304 13.873 79.758 14.099 ;
     RECT  1.152 14.059 1.17 14.135 ;
     RECT  71.856 14.099 79.758 14.251 ;
     RECT  71.856 14.251 79.794 14.369 ;
     RECT  1.152 14.923 1.17 15.053 ;
     RECT  2.304 14.099 71.082 15.061 ;
     RECT  71.856 14.369 79.758 15.061 ;
     RECT  2.304 15.061 79.758 16.529 ;
     RECT  2.304 16.529 79.578 16.799 ;
     RECT  2.304 16.799 79.47 17.617 ;
     RECT  2.268 17.617 79.47 17.837 ;
     RECT  2.304 17.837 79.47 18.455 ;
     RECT  2.415 18.455 79.47 19.675 ;
     RECT  1.728 19.675 79.47 20.075 ;
     RECT  2.304 20.075 79.47 20.345 ;
     RECT  2.415 20.345 79.47 20.723 ;
     RECT  2.415 20.723 64.566 21.541 ;
     RECT  65.304 20.723 79.47 21.541 ;
     RECT  0.576 21.499 0.594 21.695 ;
     RECT  2.415 21.541 79.47 21.811 ;
     RECT  2.304 21.811 79.47 22.505 ;
     RECT  2.376 22.505 79.47 23.287 ;
     RECT  2.304 23.287 79.47 23.701 ;
     RECT  2.304 23.701 79.794 23.819 ;
     RECT  2.304 23.819 79.47 24.125 ;
     RECT  2.415 24.125 79.47 25.015 ;
     RECT  2.412 25.015 79.47 25.051 ;
     RECT  2.304 25.051 79.47 25.243 ;
     RECT  1.692 25.243 79.47 25.313 ;
     RECT  2.304 25.313 79.47 25.745 ;
     RECT  2.412 25.745 79.47 26.393 ;
     RECT  2.415 26.393 79.47 26.587 ;
     RECT  2.415 26.587 79.506 27.115 ;
     RECT  1.728 27.115 79.506 27.301 ;
     RECT  1.728 27.301 79.578 27.365 ;
     RECT  2.415 27.365 79.578 27.985 ;
     RECT  2.415 27.985 79.65 28.021 ;
     RECT  2.415 28.021 79.686 28.139 ;
     RECT  2.415 28.139 79.65 28.255 ;
     RECT  2.376 28.255 79.65 28.409 ;
     RECT  2.376 28.409 79.578 28.445 ;
     RECT  2.376 28.445 79.542 28.687 ;
     RECT  2.304 28.687 79.542 28.939 ;
     RECT  2.268 28.939 79.542 29.795 ;
     RECT  2.304 29.795 79.542 29.939 ;
     RECT  2.415 29.939 79.542 30.721 ;
     RECT  2.415 30.721 79.578 30.811 ;
     RECT  1.728 30.811 79.578 30.955 ;
     RECT  1.728 30.955 79.65 31.109 ;
     RECT  80.856 30.991 80.874 31.325 ;
     RECT  1.728 31.109 79.578 31.415 ;
     RECT  2.415 31.415 79.542 32.575 ;
     RECT  2.412 32.575 79.542 32.845 ;
     RECT  1.152 32.635 1.17 33.035 ;
     RECT  2.376 32.845 79.542 33.151 ;
     RECT  2.304 33.151 79.542 33.305 ;
     RECT  2.415 33.305 79.542 33.421 ;
     RECT  2.415 33.421 79.578 33.539 ;
     RECT  2.415 33.539 79.542 34.465 ;
     RECT  2.304 34.465 79.542 34.507 ;
     RECT  1.728 34.507 79.542 35.159 ;
     RECT  1.728 35.159 48.798 35.195 ;
     RECT  49.536 35.159 79.542 35.311 ;
     RECT  49.536 35.311 79.794 35.429 ;
     RECT  2.304 35.195 48.798 35.885 ;
     RECT  2.304 35.885 48.726 35.969 ;
     RECT  49.536 35.429 79.542 36.391 ;
     RECT  49.536 36.391 79.794 36.509 ;
     RECT  49.536 36.509 79.578 36.625 ;
     RECT  0.576 36.379 0.594 36.815 ;
     RECT  2.376 35.969 48.51 36.931 ;
     RECT  49.248 36.625 79.578 36.931 ;
     RECT  2.304 36.931 79.578 37.319 ;
     RECT  2.304 37.319 79.542 38.251 ;
     RECT  1.728 38.251 79.542 38.705 ;
     RECT  2.304 38.705 79.542 38.821 ;
     RECT  2.304 38.821 79.794 38.939 ;
     RECT  2.304 38.939 79.542 39.865 ;
     RECT  2.304 39.865 79.794 40.019 ;
     RECT  2.304 40.019 79.542 40.109 ;
     RECT  2.376 40.109 79.542 40.981 ;
     RECT  2.376 40.981 79.794 41.099 ;
     RECT  2.376 41.099 79.542 41.377 ;
     RECT  2.304 41.377 79.542 41.995 ;
     RECT  1.728 41.995 79.542 42.755 ;
     RECT  2.304 42.755 79.542 43.709 ;
     RECT  0.576 43.819 0.594 44.105 ;
     RECT  2.304 43.709 79.47 44.491 ;
     RECT  2.304 44.491 79.794 44.609 ;
     RECT  2.304 44.609 79.47 44.645 ;
     RECT  2.34 44.645 79.47 44.813 ;
     RECT  2.34 44.813 76.698 45.535 ;
     RECT  77.616 44.813 79.47 45.535 ;
     RECT  2.34 45.535 79.47 47.281 ;
     RECT  0.108 47.515 0.126 48.119 ;
     RECT  1.152 48.001 1.17 48.119 ;
     RECT  2.304 47.281 79.47 48.811 ;
     RECT  2.304 48.811 79.794 48.929 ;
     RECT  2.34 48.929 48.114 49.109 ;
     RECT  2.34 49.109 48.078 49.199 ;
     RECT  2.34 49.199 48.042 49.469 ;
     RECT  42.12 49.469 48.042 49.541 ;
     RECT  42.156 49.541 48.042 49.577 ;
     RECT  42.192 49.577 48.042 49.739 ;
     RECT  48.96 48.929 79.794 49.891 ;
     RECT  2.34 49.469 41.166 50.323 ;
     RECT  42.192 49.739 47.934 50.323 ;
     RECT  2.34 50.323 47.934 50.665 ;
     RECT  48.816 49.891 79.794 50.665 ;
     RECT  80.928 50.779 80.946 50.819 ;
     RECT  2.34 50.665 79.794 51.089 ;
     RECT  76.932 51.089 79.794 51.125 ;
     RECT  2.34 51.089 76.194 51.161 ;
     RECT  2.34 51.161 76.122 51.269 ;
     RECT  76.932 51.125 78.966 51.359 ;
     RECT  0.576 51.259 0.594 51.395 ;
     RECT  76.932 51.359 78.858 51.629 ;
     RECT  76.932 51.629 78.678 51.773 ;
     RECT  76.932 51.773 78.606 51.809 ;
     RECT  58.896 51.269 71.586 52.015 ;
     RECT  72.36 51.269 76.122 52.015 ;
     RECT  2.34 51.269 58.158 52.051 ;
     RECT  58.896 52.015 76.122 52.051 ;
     RECT  2.34 52.051 76.122 52.141 ;
     RECT  76.932 51.809 78.297 52.141 ;
     RECT  2.34 52.141 78.297 52.462 ;
     RECT  2.34 52.462 76.986 52.789 ;
     RECT  2.304 52.789 76.986 52.979 ;
     RECT  2.304 52.979 75.978 53.021 ;
     RECT  2.304 53.021 75.69 53.249 ;
     RECT  76.932 52.979 76.986 53.519 ;
     RECT  2.304 53.249 75.582 53.591 ;
     RECT  2.304 53.591 73.602 53.789 ;
     RECT  74.376 53.591 75.582 53.789 ;
     RECT  74.628 53.789 75.078 54.059 ;
     RECT  74.628 54.059 74.79 54.095 ;
     RECT  2.304 53.789 73.35 54.131 ;
     RECT  76.932 53.519 76.95 54.131 ;
     RECT  74.7 54.095 74.718 54.203 ;
     RECT  2.304 54.131 73.062 54.715 ;
     RECT  2.232 54.715 73.062 55.139 ;
     RECT  2.268 55.139 73.062 55.255 ;
     RECT  2.268 55.255 73.35 55.283 ;
     RECT  2.304 55.283 73.35 55.957 ;
     RECT  2.304 55.957 73.422 56.129 ;
     RECT  2.34 56.129 73.422 56.569 ;
     RECT  2.34 56.569 73.854 56.875 ;
     RECT  1.728 56.875 73.854 57.065 ;
     RECT  2.34 57.065 73.854 57.145 ;
     RECT  2.34 57.145 73.926 57.181 ;
     RECT  2.34 57.181 74.286 57.299 ;
     RECT  2.376 57.299 74.286 57.451 ;
     RECT  75.024 57.415 75.042 57.451 ;
     RECT  2.376 57.451 75.042 57.569 ;
     RECT  2.376 57.569 74.214 58.225 ;
     RECT  2.304 58.225 74.214 58.733 ;
     RECT  2.34 58.733 74.214 59.233 ;
     RECT  2.34 59.233 74.322 59.305 ;
     RECT  2.34 59.305 74.466 59.459 ;
     RECT  2.34 59.459 74.25 59.765 ;
     RECT  2.415 59.765 74.25 59.837 ;
     RECT  2.415 59.837 74.214 60.571 ;
     RECT  1.728 60.571 74.214 60.845 ;
     RECT  2.34 60.845 74.214 60.925 ;
     RECT  2.34 60.925 74.286 61.079 ;
     RECT  2.34 61.079 74.214 61.259 ;
     RECT  6.156 61.259 74.214 61.385 ;
     RECT  2.34 61.259 5.382 62.005 ;
     RECT  2.304 62.005 5.382 62.041 ;
     RECT  6.156 61.385 41.094 62.041 ;
     RECT  2.304 62.041 41.094 62.107 ;
     RECT  41.832 61.385 74.214 62.107 ;
     RECT  2.304 62.107 74.214 62.159 ;
     RECT  2.304 62.159 74.178 62.231 ;
     RECT  1.152 62.395 1.17 62.465 ;
     RECT  2.304 62.231 74.106 63.121 ;
     RECT  2.304 63.121 74.25 63.239 ;
     RECT  2.304 63.239 74.106 63.779 ;
     RECT  2.304 63.779 74.07 64.165 ;
     RECT  1.728 64.165 74.07 64.253 ;
     RECT  2.34 64.253 74.07 65.515 ;
     RECT  2.34 65.515 74.142 65.669 ;
     RECT  2.34 65.669 73.962 66.325 ;
     RECT  2.304 66.325 73.962 66.479 ;
     RECT  1.152 66.139 1.17 66.515 ;
     RECT  2.304 66.479 73.566 66.659 ;
     RECT  2.304 66.659 73.53 66.929 ;
     RECT  2.34 66.929 73.53 67.055 ;
     RECT  2.415 67.055 73.53 67.711 ;
     RECT  2.415 67.711 74.07 67.801 ;
     RECT  2.304 67.801 74.07 67.829 ;
     RECT  2.304 67.829 73.566 67.945 ;
     RECT  2.268 67.945 73.566 67.997 ;
     RECT  74.304 68.251 74.322 68.369 ;
     RECT  2.304 67.997 73.566 68.675 ;
     RECT  2.34 68.675 73.566 69.187 ;
     RECT  2.34 69.187 73.71 69.215 ;
     RECT  2.415 69.215 73.71 69.449 ;
     RECT  79.776 51.125 79.794 69.521 ;
     RECT  2.415 69.449 73.638 69.719 ;
     RECT  79.56 69.601 79.578 69.755 ;
     RECT  2.415 69.719 73.494 70.025 ;
     RECT  2.415 70.025 71.514 70.105 ;
     RECT  0.576 69.835 0.594 70.295 ;
     RECT  81.432 69.871 81.45 70.349 ;
     RECT  2.376 70.105 71.514 70.411 ;
     RECT  2.304 70.411 71.514 70.445 ;
     RECT  2.304 70.445 66.042 70.565 ;
     RECT  66.852 70.445 71.514 70.601 ;
     RECT  66.852 70.601 71.478 70.799 ;
     RECT  66.852 70.799 71.37 71.069 ;
     RECT  2.415 70.565 66.042 71.221 ;
     RECT  66.852 71.069 70.794 71.221 ;
     RECT  2.415 71.221 70.794 71.455 ;
     RECT  72.36 70.025 72.897 71.717 ;
     RECT  2.304 71.455 70.794 72.059 ;
     RECT  2.304 72.059 69.822 72.419 ;
     RECT  70.776 72.059 70.794 72.419 ;
     RECT  2.304 72.419 3.258 72.599 ;
     RECT  3.996 72.419 69.822 72.869 ;
     RECT  2.415 72.599 3.258 72.959 ;
     RECT  3.996 72.869 4.014 72.959 ;
     RECT  2.415 72.959 2.97 72.989 ;
     RECT  2.415 72.989 2.934 73.229 ;
     RECT  4.824 72.869 69.822 73.265 ;
     RECT  2.415 73.229 2.79 73.345 ;
     RECT  5.076 73.265 69.822 73.571 ;
     RECT  2.376 73.345 2.79 73.769 ;
     RECT  5.076 73.571 53.046 73.769 ;
     RECT  1.152 73.579 1.17 73.805 ;
     RECT  2.376 73.769 2.754 73.913 ;
     RECT  2.376 73.913 2.697 73.921 ;
     RECT  54.18 73.571 69.822 73.949 ;
     RECT  2.304 73.921 2.697 74.075 ;
     RECT  54.18 73.949 69.642 74.111 ;
     RECT  54.18 74.111 68.67 74.183 ;
     RECT  69.48 74.111 69.642 74.309 ;
     RECT  69.624 74.309 69.642 74.345 ;
     RECT  5.796 73.769 53.046 74.353 ;
     RECT  5.796 74.353 53.118 74.461 ;
     RECT  5.796 74.461 53.262 74.579 ;
     RECT  5.976 74.579 53.262 74.623 ;
     RECT  54.18 74.183 68.598 74.623 ;
     RECT  5.976 74.623 68.598 74.669 ;
     RECT  5.976 74.669 68.562 74.849 ;
     RECT  5.976 74.849 5.994 74.885 ;
     RECT  7.776 74.849 68.526 74.921 ;
     RECT  7.776 74.921 68.49 74.957 ;
     RECT  6.984 74.849 7.002 75.029 ;
     RECT  20.448 74.957 68.49 75.029 ;
     RECT  3.888 75.067 3.906 75.119 ;
     RECT  4.824 75.001 4.842 75.119 ;
     RECT  7.776 74.957 19.674 75.119 ;
     RECT  21.276 75.029 68.49 75.119 ;
     RECT  2.415 74.075 2.697 75.199 ;
     RECT  4.032 75.271 4.05 75.389 ;
     RECT  7.815 75.119 19.602 75.389 ;
     RECT  2.415 75.199 3.006 75.403 ;
     RECT  1.728 75.403 3.006 75.425 ;
     RECT  7.815 75.389 15.39 75.533 ;
     RECT  16.308 75.389 19.602 75.569 ;
     RECT  7.815 75.533 15.21 75.581 ;
     RECT  16.488 75.569 19.566 75.659 ;
     RECT  1.728 75.425 2.697 75.695 ;
     RECT  16.524 75.659 19.566 75.695 ;
     RECT  16.596 75.695 19.566 75.731 ;
     RECT  20.448 75.029 20.466 75.767 ;
     RECT  22.248 75.119 68.49 75.775 ;
     RECT  7.815 75.581 14.886 75.821 ;
     RECT  16.884 75.731 19.566 75.821 ;
     RECT  18.324 75.821 19.566 75.929 ;
     RECT  2.304 75.695 2.697 75.965 ;
     RECT  8.892 75.821 9.594 75.965 ;
     RECT  21.276 75.119 21.366 76.045 ;
     RECT  22.248 75.775 68.814 76.081 ;
     RECT  9.036 75.965 9.594 76.109 ;
     RECT  18.615 75.929 19.566 76.109 ;
     RECT  9.036 76.109 9.486 76.199 ;
     RECT  10.476 75.821 14.886 76.199 ;
     RECT  16.884 75.821 17.55 76.199 ;
     RECT  22.248 76.081 69.066 76.199 ;
     RECT  10.692 76.199 14.886 76.235 ;
     RECT  22.248 76.199 68.67 76.235 ;
     RECT  9.324 76.199 9.486 76.271 ;
     RECT  13.215 76.235 14.886 76.271 ;
     RECT  22.248 76.235 68.31 76.279 ;
     RECT  13.215 76.271 14.742 76.307 ;
     RECT  22.176 76.279 68.31 76.379 ;
     RECT  11.376 76.235 12.114 76.505 ;
     RECT  11.376 76.505 11.934 76.613 ;
     RECT  33.48 76.379 68.31 76.613 ;
     RECT  21.24 76.045 21.366 76.621 ;
     RECT  22.176 76.379 32.634 76.621 ;
     RECT  17.532 76.199 17.55 76.739 ;
     RECT  21.24 76.621 32.634 76.739 ;
     RECT  4.356 76.855 4.374 76.891 ;
     RECT  5.184 76.699 5.202 76.891 ;
     RECT  33.48 76.613 52.038 76.919 ;
     RECT  4.356 76.891 5.346 77.009 ;
     RECT  21.24 76.739 21.402 77.009 ;
     RECT  4.68 77.009 4.95 77.045 ;
     RECT  22.176 76.739 32.634 77.045 ;
     RECT  4.932 77.045 4.95 77.081 ;
     RECT  2.415 75.965 2.697 77.125 ;
     RECT  22.32 77.045 32.634 77.125 ;
     RECT  33.48 76.919 48.87 77.125 ;
     RECT  52.776 76.613 68.31 77.161 ;
     RECT  52.776 77.161 68.346 77.251 ;
     RECT  2.376 77.125 2.697 77.279 ;
     RECT  22.32 77.125 48.87 77.279 ;
     RECT  52.776 77.251 68.958 77.287 ;
     RECT  1.152 77.275 1.17 77.315 ;
     RECT  22.464 77.279 26.766 77.351 ;
     RECT  49.608 76.919 52.038 77.521 ;
     RECT  52.776 77.287 68.994 77.521 ;
     RECT  27.504 77.279 48.87 77.549 ;
     RECT  49.608 77.521 68.994 77.549 ;
     RECT  27.504 77.549 48.69 77.585 ;
     RECT  21.312 77.009 21.33 77.621 ;
     RECT  49.644 77.549 68.994 77.693 ;
     RECT  13.215 76.307 13.878 77.819 ;
     RECT  22.716 77.351 26.766 77.819 ;
     RECT  27.612 77.585 48.69 77.819 ;
     RECT  11.376 76.613 11.394 77.855 ;
     RECT  49.68 77.693 68.454 77.855 ;
     RECT  63.576 77.855 68.454 77.891 ;
     RECT  11.52 77.971 11.538 78.089 ;
     RECT  22.752 77.819 26.766 78.089 ;
     RECT  63.576 77.891 68.382 78.089 ;
     RECT  49.68 77.855 62.802 78.161 ;
     RECT  2.415 77.279 2.697 78.205 ;
     RECT  7.815 75.821 8.097 78.205 ;
     RECT  22.788 78.089 26.766 78.241 ;
     RECT  7.524 78.205 8.097 78.359 ;
     RECT  49.68 78.161 62.73 78.359 ;
     RECT  63.576 78.089 68.31 78.359 ;
     RECT  5.544 78.061 5.562 78.395 ;
     RECT  49.68 78.359 51.642 78.467 ;
     RECT  52.56 78.359 62.73 78.503 ;
     RECT  63.576 78.359 67.497 78.503 ;
     RECT  36.9 77.819 48.69 78.511 ;
     RECT  52.56 78.503 52.866 78.539 ;
     RECT  53.604 78.503 62.73 78.539 ;
     RECT  63.576 78.503 65.502 78.539 ;
     RECT  63.576 78.539 64.386 78.619 ;
     RECT  2.415 78.205 3.33 78.629 ;
     RECT  36.9 78.511 49.338 78.629 ;
     RECT  53.604 78.539 62.55 78.629 ;
     RECT  65.412 78.539 65.502 78.629 ;
     RECT  68.292 78.359 68.31 78.629 ;
     RECT  22.788 78.241 26.874 78.637 ;
     RECT  27.612 77.819 36.018 78.637 ;
     RECT  36.9 78.629 48.438 78.665 ;
     RECT  50.688 78.467 51.642 78.665 ;
     RECT  52.56 78.539 52.794 78.665 ;
     RECT  61.74 78.629 62.55 78.665 ;
     RECT  63.54 78.619 64.386 78.665 ;
     RECT  66.276 78.503 67.497 78.665 ;
     RECT  52.704 78.665 52.794 78.701 ;
     RECT  36.9 78.665 48.402 78.709 ;
     RECT  2.415 78.629 2.697 78.745 ;
     RECT  22.788 78.637 36.018 78.781 ;
     RECT  36.864 78.709 48.402 78.781 ;
     RECT  50.724 78.665 51.642 78.809 ;
     RECT  66.528 78.665 67.497 78.809 ;
     RECT  53.604 78.629 60.462 78.899 ;
     RECT  22.788 78.781 48.402 78.935 ;
     RECT  53.604 78.899 59.778 78.935 ;
     RECT  63.756 78.665 64.386 78.935 ;
     RECT  50.796 78.809 51.642 78.971 ;
     RECT  63.828 78.935 64.386 78.971 ;
     RECT  49.248 78.629 49.338 79.007 ;
     RECT  2.376 78.745 2.697 79.015 ;
     RECT  50.796 78.971 51.297 79.079 ;
     RECT  53.604 78.935 59.49 79.079 ;
     RECT  61.815 78.665 62.55 79.079 ;
     RECT  1.728 79.015 2.697 79.133 ;
     RECT  23.292 78.935 48.366 79.169 ;
     RECT  49.248 79.007 49.266 79.169 ;
     RECT  53.604 79.079 53.73 79.169 ;
     RECT  54.54 79.079 59.49 79.169 ;
     RECT  53.604 79.169 53.622 79.205 ;
     RECT  55.008 79.169 59.49 79.205 ;
     RECT  23.292 79.169 33.93 79.241 ;
     RECT  31.5 79.241 33.93 79.277 ;
     RECT  55.008 79.205 59.31 79.313 ;
     RECT  24.015 79.241 30.726 79.349 ;
     RECT  24.015 79.349 26.298 79.439 ;
     RECT  27.072 79.349 30.726 79.439 ;
     RECT  31.5 79.277 31.806 79.439 ;
     RECT  32.724 79.277 33.93 79.439 ;
     RECT  34.815 79.169 48.186 79.439 ;
     RECT  55.008 79.313 57.366 79.439 ;
     RECT  58.32 79.313 59.31 79.439 ;
     RECT  27.612 79.439 30.582 79.469 ;
     RECT  43.02 79.439 44.694 79.475 ;
     RECT  55.008 79.439 55.026 79.475 ;
     RECT  27.612 79.469 30.33 79.511 ;
     RECT  34.815 79.439 42.03 79.511 ;
     RECT  47.268 79.439 48.15 79.511 ;
     RECT  56.415 79.439 57.366 79.511 ;
     RECT  27.612 79.511 28.35 79.547 ;
     RECT  47.916 79.511 47.934 79.583 ;
     RECT  25.308 79.439 26.118 79.613 ;
     RECT  34.815 79.511 41.202 79.619 ;
     RECT  45.615 79.439 46.386 79.619 ;
     RECT  56.415 79.511 57.042 79.619 ;
     RECT  2.415 79.133 2.697 79.667 ;
     RECT  7.815 78.359 8.097 79.667 ;
     RECT  13.215 77.819 13.497 79.667 ;
     RECT  18.615 76.109 18.897 79.667 ;
     RECT  24.015 79.439 24.297 79.667 ;
     RECT  29.088 79.511 30.33 79.667 ;
     RECT  34.815 79.619 37.134 79.667 ;
     RECT  39.96 79.619 41.202 79.667 ;
     RECT  51.015 79.079 51.297 79.667 ;
     RECT  56.415 79.619 56.697 79.667 ;
     RECT  61.815 79.079 62.097 79.667 ;
     RECT  67.215 78.809 67.497 79.667 ;
     RECT  72.615 71.717 72.897 79.667 ;
     RECT  78.015 52.462 78.297 79.667 ;
     RECT  25.308 79.613 25.83 79.709 ;
     RECT  27.684 79.547 28.35 79.709 ;
     RECT  29.088 79.667 29.574 79.709 ;
     RECT  30.312 79.667 30.33 79.709 ;
     RECT  31.644 79.439 31.662 79.709 ;
     RECT  32.976 79.439 33.138 79.709 ;
     RECT  33.876 79.439 33.894 79.709 ;
     RECT  35.748 79.667 37.134 79.709 ;
     RECT  37.98 79.619 39.186 79.709 ;
     RECT  39.96 79.667 40.305 79.709 ;
     RECT  41.076 79.667 41.202 79.709 ;
     RECT  42.012 79.511 42.03 79.709 ;
     RECT  43.02 79.475 44.406 79.709 ;
     RECT  25.308 79.709 25.326 79.745 ;
     RECT  27.684 79.709 27.702 79.745 ;
     RECT  32.976 79.709 32.994 79.745 ;
     RECT  41.076 79.709 41.094 79.745 ;
     RECT  43.02 79.709 43.038 79.745 ;
     RECT  44.28 79.709 44.298 79.745 ;
     RECT  37.116 79.709 37.134 79.781 ;
     RECT  38.52 79.709 38.538 79.781 ;
     RECT  45.615 79.619 46.134 79.781 ;
     RECT  2.415 79.667 2.505 79.937 ;
     RECT  7.815 79.667 7.905 79.937 ;
     RECT  13.215 79.667 13.305 79.937 ;
     RECT  18.615 79.667 18.705 79.937 ;
     RECT  24.015 79.667 24.105 79.937 ;
     RECT  29.415 79.709 29.505 79.937 ;
     RECT  34.815 79.667 34.905 79.937 ;
     RECT  40.215 79.709 40.305 79.937 ;
     RECT  45.615 79.781 45.705 79.937 ;
     RECT  51.015 79.667 51.105 79.937 ;
     RECT  56.415 79.667 56.505 79.937 ;
     RECT  61.815 79.667 61.905 79.937 ;
     RECT  67.215 79.667 67.305 79.937 ;
     RECT  72.615 79.667 72.705 79.937 ;
     RECT  78.015 79.667 78.105 79.937 ;
    LAYER M4 ;
     RECT  0.037 15.024 0.06 15.048 ;
     RECT  0.06 2.928 0.137 2.952 ;
     RECT  0.06 47.52 0.137 47.544 ;
     RECT  0.06 21.504 0.605 21.528 ;
     RECT  0.06 36.384 0.605 36.408 ;
     RECT  0.06 43.824 0.605 43.848 ;
     RECT  0.06 51.264 0.605 51.288 ;
     RECT  0.06 69.84 0.605 69.864 ;
     RECT  0.06 14.064 1.181 15.048 ;
     RECT  0.06 32.64 1.181 32.664 ;
     RECT  0.06 62.4 1.181 62.424 ;
     RECT  0.06 66.144 1.181 66.168 ;
     RECT  0.06 73.584 1.181 73.608 ;
     RECT  0.06 77.28 1.181 77.304 ;
     RECT  0.085 60.576 2.293 60.6 ;
     RECT  0.085 64.224 2.293 64.248 ;
     RECT  2.293 16.368 2.329 16.392 ;
     RECT  0.06 58.704 2.329 58.728 ;
     RECT  2.293 59.76 2.329 60.6 ;
     RECT  1.181 14.928 2.365 14.952 ;
     RECT  2.329 16.272 2.365 16.392 ;
     RECT  0.06 28.944 2.365 28.968 ;
     RECT  0.06 40.08 2.365 40.104 ;
     RECT  0.06 54.96 2.365 54.984 ;
     RECT  2.365 54.72 2.401 54.984 ;
     RECT  0.06 6.624 2.408 6.648 ;
     RECT  0.085 8.496 2.408 8.52 ;
     RECT  0.06 10.368 2.408 10.392 ;
     RECT  0.085 12.24 2.408 12.264 ;
     RECT  2.365 14.928 2.408 16.392 ;
     RECT  0.06 17.808 2.408 17.832 ;
     RECT  0.085 19.68 2.408 19.704 ;
     RECT  0.085 23.328 2.408 23.352 ;
     RECT  0.06 25.248 2.408 25.272 ;
     RECT  0.085 27.12 2.408 27.144 ;
     RECT  2.365 28.8 2.408 28.968 ;
     RECT  0.085 30.816 2.408 30.84 ;
     RECT  0.085 34.512 2.408 34.536 ;
     RECT  0.085 38.256 2.408 38.28 ;
     RECT  2.365 39.6 2.408 40.44 ;
     RECT  0.085 42 2.408 42.024 ;
     RECT  2.365 43.296 2.408 43.32 ;
     RECT  2.365 49.584 2.408 49.608 ;
     RECT  0.085 52.8 2.408 52.824 ;
     RECT  2.401 54.72 2.408 55.704 ;
     RECT  0.085 56.88 2.408 56.904 ;
     RECT  2.329 58.704 2.408 60.6 ;
     RECT  2.293 64.224 2.408 64.392 ;
     RECT  0.085 67.968 2.408 67.992 ;
     RECT  2.285 71.904 2.408 71.928 ;
     RECT  0.085 75.408 2.408 75.432 ;
     RECT  0.085 79.104 2.408 79.128 ;
     RECT  2.365 1.152 2.449 1.176 ;
     RECT  2.408 2.148 2.512 79.932 ;
     RECT  2.512 2.148 2.704 79.662 ;
     RECT  2.704 12.96 2.765 16.296 ;
     RECT  2.704 61.92 2.819 62.136 ;
     RECT  2.704 64.368 2.819 65.16 ;
     RECT  2.819 64.368 2.867 64.68 ;
     RECT  2.704 31.92 2.873 31.944 ;
     RECT  2.704 37.632 2.873 41.688 ;
     RECT  2.765 12.96 2.963 15.96 ;
     RECT  2.704 42.72 2.981 44.136 ;
     RECT  2.704 72.384 2.981 72.984 ;
     RECT  2.963 12.96 3.004 13.848 ;
     RECT  2.981 72.384 3.004 72.888 ;
     RECT  3.205 1.776 3.305 1.8 ;
     RECT  2.704 49.584 3.413 51.432 ;
     RECT  2.873 38.736 3.443 41.688 ;
     RECT  2.704 69.936 3.443 71.352 ;
     RECT  3.443 38.832 3.449 41.688 ;
     RECT  2.704 67.248 3.449 67.272 ;
     RECT  3.449 40.944 3.521 41.688 ;
     RECT  2.704 52.704 3.58 55.704 ;
     RECT  2.704 18.72 3.593 18.744 ;
     RECT  2.704 28.8 3.629 30.936 ;
     RECT  3.629 30.576 3.635 30.936 ;
     RECT  2.704 24.816 3.665 25.224 ;
     RECT  2.704 45.312 3.697 48.024 ;
     RECT  3.697 45.312 3.773 48.168 ;
     RECT  3.58 54.672 3.781 55.704 ;
     RECT  2.704 57.024 3.781 60.168 ;
     RECT  3.665 25.056 3.805 25.224 ;
     RECT  2.704 26.64 3.805 26.664 ;
     RECT  2.704 63.216 3.829 63.288 ;
     RECT  2.867 64.368 3.829 64.584 ;
     RECT  2.704 36.624 3.841 36.648 ;
     RECT  3.781 54.672 3.841 60.168 ;
     RECT  3.443 69.936 3.877 69.96 ;
     RECT  3.841 35.808 3.913 36.648 ;
     RECT  2.873 37.632 3.913 37.752 ;
     RECT  3.877 69.504 3.917 69.96 ;
     RECT  3.836 75.072 3.923 75.096 ;
     RECT  2.704 9.84 3.949 9.864 ;
     RECT  2.963 15.936 3.971 15.96 ;
     RECT  3.841 54.672 3.971 60.312 ;
     RECT  3.949 2.88 3.973 2.904 ;
     RECT  2.704 3.936 3.973 3.96 ;
     RECT  2.819 62.112 3.973 62.136 ;
     RECT  3.829 63.216 3.973 64.584 ;
     RECT  3.773 46.464 3.989 48.168 ;
     RECT  3.973 62.112 4.012 64.584 ;
     RECT  3.985 6.864 4.021 6.888 ;
     RECT  3.733 8.208 4.021 8.232 ;
     RECT  2.963 14.88 4.021 14.952 ;
     RECT  2.704 11.28 4.025 11.736 ;
     RECT  3.004 72.864 4.025 72.888 ;
     RECT  2.704 33.12 4.057 34.2 ;
     RECT  3.913 35.472 4.057 37.752 ;
     RECT  3.973 1.152 4.061 1.176 ;
     RECT  3.949 9.696 4.061 9.864 ;
     RECT  4.025 11.28 4.061 11.544 ;
     RECT  3.629 28.8 4.061 29.544 ;
     RECT  2.981 42.72 4.067 43.896 ;
     RECT  3.521 41.136 4.093 41.688 ;
     RECT  4.067 42.72 4.093 42.792 ;
     RECT  3.973 2.88 4.097 4.584 ;
     RECT  2.704 22.56 4.097 23.592 ;
     RECT  4.061 11.28 4.129 11.448 ;
     RECT  4.057 33.12 4.129 37.752 ;
     RECT  4.012 64.368 4.129 64.584 ;
     RECT  2.704 68.496 4.165 68.52 ;
     RECT  3.004 12.96 4.169 12.984 ;
     RECT  4.067 43.872 4.201 43.896 ;
     RECT  4.129 64.368 4.201 64.824 ;
     RECT  4.093 66.048 4.201 66.072 ;
     RECT  4.061 9.696 4.205 9.72 ;
     RECT  4.021 6.864 4.237 8.232 ;
     RECT  4.165 67.872 4.259 68.52 ;
     RECT  3.805 25.056 4.277 26.664 ;
     RECT  4.012 62.112 4.313 63.24 ;
     RECT  4.129 32.448 4.349 37.752 ;
     RECT  4.093 41.136 4.349 42.792 ;
     RECT  4.237 6.864 4.385 8.568 ;
     RECT  3.443 71.136 4.417 71.352 ;
     RECT  3.769 17.664 4.421 17.688 ;
     RECT  4.385 8.544 4.489 8.568 ;
     RECT  4.349 37.632 4.489 37.752 ;
     RECT  3.449 38.832 4.489 39.912 ;
     RECT  4.313 62.112 4.489 62.664 ;
     RECT  4.061 28.8 4.525 29.304 ;
     RECT  4.259 68.4 4.529 68.52 ;
     RECT  4.385 6.864 4.547 7.464 ;
     RECT  4.349 32.448 4.561 36.648 ;
     RECT  4.489 37.632 4.561 39.912 ;
     RECT  4.349 41.136 4.561 42.648 ;
     RECT  3.58 52.704 4.561 53.016 ;
     RECT  3.971 56.544 4.561 60.312 ;
     RECT  4.201 64.368 4.561 66.072 ;
     RECT  4.277 25.584 4.565 26.664 ;
     RECT  4.561 56.544 4.597 60.36 ;
     RECT  4.489 61.536 4.597 62.664 ;
     RECT  3.635 30.576 4.633 30.6 ;
     RECT  3.413 49.968 4.633 51.432 ;
     RECT  4.417 71.136 4.669 72.456 ;
     RECT  3.989 46.464 4.673 47.4 ;
     RECT  4.097 23.568 4.705 23.592 ;
     RECT  4.129 10.848 4.709 11.448 ;
     RECT  4.633 19.92 4.741 19.944 ;
     RECT  4.525 27.888 4.741 29.304 ;
     RECT  4.097 3.936 4.745 4.584 ;
     RECT  4.489 15.984 4.745 16.536 ;
     RECT  4.201 43.872 4.745 44.952 ;
     RECT  4.633 30.576 4.777 30.84 ;
     RECT  4.633 49.968 4.777 51.624 ;
     RECT  4.777 49.488 4.813 51.624 ;
     RECT  4.561 52.704 4.813 53.4 ;
     RECT  3.971 54.672 4.813 55.32 ;
     RECT  4.769 1.776 4.853 1.8 ;
     RECT  4.597 56.544 4.853 62.664 ;
     RECT  4.849 18.72 4.885 18.744 ;
     RECT  4.097 22.56 4.885 22.584 ;
     RECT  4.561 37.632 4.889 42.648 ;
     RECT  3.917 69.504 4.925 69.576 ;
     RECT  4.709 10.848 4.957 10.872 ;
     RECT  3.985 21.312 4.957 21.336 ;
     RECT  4.885 22.32 4.957 22.584 ;
     RECT  4.885 17.04 4.969 17.4 ;
     RECT  4.885 18.384 4.972 18.744 ;
     RECT  4.777 30.288 4.993 30.84 ;
     RECT  4.561 31.968 4.993 36.648 ;
     RECT  4.94 4.848 5.027 4.872 ;
     RECT  4.021 14.784 5.029 14.952 ;
     RECT  4.745 15.984 5.029 16.008 ;
     RECT  4.561 64.368 5.065 66.648 ;
     RECT  4.669 70.704 5.075 72.456 ;
     RECT  4.741 19.92 5.101 20.136 ;
     RECT  4.745 44.688 5.101 44.952 ;
     RECT  4.853 56.544 5.105 62.232 ;
     RECT  5.105 56.832 5.123 62.232 ;
     RECT  4.813 49.488 5.125 55.32 ;
     RECT  5.065 64.368 5.141 66.696 ;
     RECT  5.075 70.704 5.173 71.64 ;
     RECT  4.565 25.584 5.177 26.328 ;
     RECT  5.123 60 5.177 62.232 ;
     RECT  5.141 64.368 5.177 64.92 ;
     RECT  5.177 60 5.213 61.08 ;
     RECT  5.141 66.048 5.213 66.696 ;
     RECT  5.132 76.704 5.219 76.728 ;
     RECT  5.101 12.432 5.245 12.456 ;
     RECT  4.547 6.864 5.249 6.888 ;
     RECT  5.125 49.488 5.249 55.848 ;
     RECT  5.201 48.48 5.285 48.504 ;
     RECT  5.177 64.752 5.285 64.92 ;
     RECT  4.889 39.888 5.353 42.648 ;
     RECT  4.993 30.288 5.357 36.648 ;
     RECT  5.353 39.888 5.393 43.416 ;
     RECT  5.101 19.92 5.413 20.184 ;
     RECT  4.957 21.312 5.413 22.584 ;
     RECT  5.249 50.16 5.465 55.848 ;
     RECT  4.489 8.544 5.569 9 ;
     RECT  5.245 12.432 5.573 12.504 ;
     RECT  5.525 1.152 5.609 1.176 ;
     RECT  4.972 18.624 5.641 18.744 ;
     RECT  4.097 2.88 5.677 2.904 ;
     RECT  4.705 23.568 5.677 24.312 ;
     RECT  5.357 30.288 5.681 32.04 ;
     RECT  4.957 10.8 5.713 10.872 ;
     RECT  5.573 12.432 5.713 12.456 ;
     RECT  5.413 19.92 5.749 22.584 ;
     RECT  5.569 8.544 5.753 9.096 ;
     RECT  5.393 41.136 5.753 43.416 ;
     RECT  4.925 69.552 5.753 69.576 ;
     RECT  5.357 33.12 5.785 36.648 ;
     RECT  4.889 37.632 5.785 38.76 ;
     RECT  5.285 64.752 5.788 64.776 ;
     RECT  5.177 25.584 5.825 26.28 ;
     RECT  4.741 27.408 5.893 29.304 ;
     RECT  5.681 30.816 5.897 32.04 ;
     RECT  5.677 2.736 5.933 2.904 ;
     RECT  5.785 33.12 5.933 38.76 ;
     RECT  5.101 44.688 5.933 45.336 ;
     RECT  5.649 5.424 5.965 5.448 ;
     RECT  5.029 14.784 6.001 16.008 ;
     RECT  5.965 5.424 6.005 6.312 ;
     RECT  5.897 30.816 6.005 31.992 ;
     RECT  5.933 33.408 6.005 38.76 ;
     RECT  5.177 62.112 6.037 62.232 ;
     RECT  5.123 56.832 6.049 58.824 ;
     RECT  6.049 56.832 6.073 58.728 ;
     RECT  6.005 33.408 6.077 35.544 ;
     RECT  5.749 19.872 6.109 22.584 ;
     RECT  5.677 23.568 6.109 24.456 ;
     RECT  5.173 70.656 6.109 71.64 ;
     RECT  5.713 10.8 6.181 12.456 ;
     RECT  4.969 17.088 6.181 17.4 ;
     RECT  5.641 18.624 6.181 18.792 ;
     RECT  6.109 70.608 6.181 71.64 ;
     RECT  5.281 72.912 6.181 72.936 ;
     RECT  5.753 41.28 6.185 43.416 ;
     RECT  6.001 14.208 6.217 16.008 ;
     RECT  6.181 17.088 6.217 18.792 ;
     RECT  6.109 19.872 6.217 24.456 ;
     RECT  6.217 14.208 6.221 18.792 ;
     RECT  6.181 70.608 6.221 72.936 ;
     RECT  6.221 14.208 6.229 15.096 ;
     RECT  4.529 68.4 6.253 68.424 ;
     RECT  6.185 41.376 6.289 43.416 ;
     RECT  5.933 44.688 6.289 45.048 ;
     RECT  6.217 19.872 6.293 24.504 ;
     RECT  5.465 50.16 6.293 55.032 ;
     RECT  6.073 56.592 6.293 58.728 ;
     RECT  5.213 60 6.293 60.312 ;
     RECT  5.213 66.528 6.361 66.696 ;
     RECT  5.893 27.312 6.365 29.784 ;
     RECT  6.077 33.408 6.365 34.104 ;
     RECT  6.005 37.056 6.365 38.76 ;
     RECT  5.393 39.888 6.365 39.912 ;
     RECT  4.673 47.04 6.428 47.4 ;
     RECT  5.533 48.384 6.428 48.408 ;
     RECT  6.073 7.92 6.433 7.944 ;
     RECT  6.037 62.112 6.433 62.52 ;
     RECT  6.361 66.096 6.433 66.696 ;
     RECT  6.181 10.08 6.437 12.456 ;
     RECT  6.221 16.56 6.437 18.792 ;
     RECT  6.428 47.04 6.469 48.408 ;
     RECT  6.433 61.632 6.469 62.52 ;
     RECT  6.293 50.688 6.473 55.032 ;
     RECT  6.373 1.776 6.581 1.8 ;
     RECT  6.253 68.352 6.581 68.424 ;
     RECT  6.229 13.44 6.611 15.096 ;
     RECT  6.469 47.04 6.613 48.696 ;
     RECT  6.611 13.44 6.653 15.048 ;
     RECT  6.293 60.24 6.757 60.312 ;
     RECT  6.469 61.632 6.757 62.712 ;
     RECT  6.365 37.056 6.761 38.328 ;
     RECT  6.373 5.088 6.793 5.112 ;
     RECT  6.757 60.24 6.797 62.712 ;
     RECT  5.933 2.88 6.829 2.904 ;
     RECT  6.289 41.376 6.901 45.048 ;
     RECT  6.433 65.76 6.901 66.696 ;
     RECT  6.761 37.056 7.009 37.656 ;
     RECT  6.437 11.616 7.117 12.456 ;
     RECT  6.365 33.792 7.117 34.104 ;
     RECT  6.473 54.72 7.117 55.032 ;
     RECT  7.081 1.152 7.187 1.176 ;
     RECT  6.581 68.4 7.189 68.424 ;
     RECT  6.293 19.872 7.261 20.376 ;
     RECT  6.293 21.504 7.261 23.352 ;
     RECT  6.797 60.24 7.261 61.416 ;
     RECT  6.901 65.712 7.297 66.696 ;
     RECT  7.117 33.792 7.333 34.152 ;
     RECT  6.721 39.312 7.333 39.336 ;
     RECT  6.613 46.8 7.333 48.696 ;
     RECT  6.797 62.448 7.333 62.712 ;
     RECT  7.297 64.992 7.333 66.696 ;
     RECT  6.365 27.744 7.368 29.784 ;
     RECT  6.793 4.464 7.369 5.112 ;
     RECT  7.333 33.792 7.369 34.488 ;
     RECT  6.077 35.52 7.369 35.544 ;
     RECT  6.437 16.56 7.441 18.696 ;
     RECT  6.293 24.336 7.441 24.504 ;
     RECT  5.825 25.584 7.441 25.608 ;
     RECT  7.369 33.792 7.441 35.544 ;
     RECT  7.009 37.008 7.441 37.656 ;
     RECT  6.293 56.928 7.441 58.728 ;
     RECT  6.221 71.472 7.441 72.36 ;
     RECT  7.441 71.472 7.477 72.84 ;
     RECT  6.437 10.08 7.513 10.344 ;
     RECT  7.117 11.616 7.513 12.552 ;
     RECT  7.261 19.872 7.513 23.352 ;
     RECT  7.441 24.336 7.513 25.608 ;
     RECT  7.333 64.896 7.549 66.696 ;
     RECT  6.433 7.392 7.58 7.944 ;
     RECT  5.753 8.976 7.58 9.096 ;
     RECT  7.513 19.872 7.585 25.608 ;
     RECT  7.189 68.4 7.585 69 ;
     RECT  7.117 54.72 7.621 55.224 ;
     RECT  7.441 56.256 7.621 58.728 ;
     RECT  7.513 10.08 7.669 12.552 ;
     RECT  6.653 13.536 7.669 15.048 ;
     RECT  7.441 16.32 7.669 18.696 ;
     RECT  7.368 27.12 7.669 29.784 ;
     RECT  6.005 30.816 7.669 31.224 ;
     RECT  7.441 33.792 7.693 37.656 ;
     RECT  7.477 71.472 7.693 72.936 ;
     RECT  6.829 2.88 7.765 3 ;
     RECT  7.369 4.464 7.765 5.304 ;
     RECT  6.473 50.688 7.765 53.592 ;
     RECT  7.585 19.872 7.801 26.136 ;
     RECT  7.669 27.12 7.801 31.224 ;
     RECT  7.765 2.88 7.808 5.304 ;
     RECT  6.005 6.288 7.808 6.312 ;
     RECT  7.58 7.392 7.808 9.096 ;
     RECT  7.669 10.08 7.808 18.696 ;
     RECT  7.801 19.872 7.808 31.224 ;
     RECT  7.693 33.024 7.808 37.656 ;
     RECT  7.333 39.312 7.808 39.768 ;
     RECT  6.901 41.376 7.808 45.288 ;
     RECT  7.333 46.8 7.808 49.56 ;
     RECT  7.765 50.592 7.808 53.592 ;
     RECT  7.621 54.72 7.808 58.728 ;
     RECT  7.261 59.712 7.808 61.416 ;
     RECT  7.333 62.448 7.808 62.856 ;
     RECT  7.549 64.416 7.808 66.696 ;
     RECT  7.585 68.4 7.808 69.576 ;
     RECT  7.693 71.472 7.808 72.984 ;
     RECT  7.429 74.736 7.808 74.76 ;
     RECT  7.808 2.148 7.912 79.932 ;
     RECT  7.912 2.148 7.945 79.662 ;
     RECT  7.945 1.776 8.029 79.662 ;
     RECT  8.029 2.418 8.104 79.662 ;
     RECT  8.104 8.592 8.201 9.096 ;
     RECT  8.104 62.448 8.243 71.256 ;
     RECT  8.104 7.056 8.273 7.464 ;
     RECT  8.104 39.264 8.273 49.56 ;
     RECT  8.273 7.056 8.291 7.08 ;
     RECT  8.104 22.464 8.332 27.096 ;
     RECT  8.104 16.08 8.345 17.16 ;
     RECT  8.243 62.592 8.38 71.256 ;
     RECT  8.104 60.048 8.381 61.368 ;
     RECT  8.38 66.288 8.381 71.256 ;
     RECT  8.345 17.088 8.387 17.16 ;
     RECT  8.387 17.136 8.453 17.16 ;
     RECT  8.104 72.24 8.453 73.032 ;
     RECT  8.104 33.024 8.489 38.28 ;
     RECT  8.381 60.048 8.489 61.224 ;
     RECT  8.381 66.288 8.525 66.408 ;
     RECT  8.104 13.104 8.597 15.048 ;
     RECT  8.104 10.704 8.633 11.448 ;
     RECT  8.489 60.048 8.633 61.176 ;
     RECT  8.38 62.592 8.633 65.304 ;
     RECT  8.104 54.528 8.675 58.728 ;
     RECT  8.381 67.536 8.716 71.256 ;
     RECT  8.765 1.152 8.849 1.176 ;
     RECT  8.104 18.192 8.957 20.088 ;
     RECT  8.104 28.368 8.993 31.896 ;
     RECT  8.489 37.008 9.029 38.28 ;
     RECT  8.597 13.824 9.065 15.048 ;
     RECT  8.332 22.464 9.097 23.352 ;
     RECT  9.029 37.056 9.097 38.28 ;
     RECT  8.273 39.264 9.097 47.88 ;
     RECT  8.633 11.424 9.107 11.448 ;
     RECT  8.104 21.168 9.133 21.192 ;
     RECT  9.097 22.272 9.133 23.352 ;
     RECT  8.332 24.432 9.133 27.096 ;
     RECT  8.993 28.368 9.133 28.44 ;
     RECT  9.053 0.096 9.137 0.12 ;
     RECT  8.957 18.24 9.137 20.088 ;
     RECT  8.716 67.872 9.137 71.256 ;
     RECT  8.993 29.52 9.155 31.896 ;
     RECT  8.453 72.288 9.169 73.032 ;
     RECT  8.104 74.4 9.169 74.424 ;
     RECT  8.201 8.592 9.205 9 ;
     RECT  9.133 21.168 9.205 23.352 ;
     RECT  8.489 33.024 9.209 35.64 ;
     RECT  9.097 37.056 9.209 47.88 ;
     RECT  8.273 48.912 9.241 49.56 ;
     RECT  8.104 50.592 9.241 53.448 ;
     RECT  9.133 24.432 9.245 28.44 ;
     RECT  9.169 72.288 9.277 74.424 ;
     RECT  8.104 75.504 9.277 75.816 ;
     RECT  9.209 37.056 9.281 37.608 ;
     RECT  9.277 72.288 9.353 75.816 ;
     RECT  9.205 21.12 9.385 23.352 ;
     RECT  9.245 24.432 9.385 26.568 ;
     RECT  8.633 62.64 9.385 65.304 ;
     RECT  9.353 72.96 9.389 75.816 ;
     RECT  9.065 15.024 9.421 15.048 ;
     RECT  8.345 16.08 9.421 16.104 ;
     RECT  8.104 2.88 9.425 5.832 ;
     RECT  9.065 13.824 9.425 13.848 ;
     RECT  9.385 21.12 9.46 26.568 ;
     RECT  9.137 19.392 9.461 20.088 ;
     RECT  9.385 62.64 9.461 65.784 ;
     RECT  9.461 62.688 9.596 65.784 ;
     RECT  9.209 33.024 9.641 35.496 ;
     RECT  8.675 54.624 9.673 58.728 ;
     RECT  9.241 48.912 9.709 53.448 ;
     RECT  9.137 67.872 9.709 68.184 ;
     RECT  9.46 21.072 9.713 26.568 ;
     RECT  9.205 8.592 9.74 9.144 ;
     RECT  9.74 8.592 9.781 9.96 ;
     RECT  9.713 21.072 9.785 25.128 ;
     RECT  9.137 69.168 9.817 71.256 ;
     RECT  9.781 8.592 9.827 10.872 ;
     RECT  9.673 54.624 9.973 58.92 ;
     RECT  9.596 62.688 10.001 66.504 ;
     RECT  9.785 21.072 10.019 23.304 ;
     RECT  9.137 18.24 10.033 18.264 ;
     RECT  9.641 33.6 10.037 35.496 ;
     RECT  9.827 10.848 10.069 10.872 ;
     RECT  9.245 27.648 10.069 28.44 ;
     RECT  9.155 29.52 10.069 31.224 ;
     RECT  9.421 15.024 10.177 16.104 ;
     RECT  10.001 62.688 10.181 64.44 ;
     RECT  10.069 27.648 10.213 31.224 ;
     RECT  9.709 67.776 10.213 68.184 ;
     RECT  9.817 69.168 10.213 71.448 ;
     RECT  10.213 27.6 10.217 31.224 ;
     RECT  9.281 37.152 10.217 37.608 ;
     RECT  10.019 21.072 10.253 23.208 ;
     RECT  10.181 62.688 10.253 64.296 ;
     RECT  9.389 72.96 10.259 73.416 ;
     RECT  10.217 37.152 10.285 37.464 ;
     RECT  10.037 33.6 10.289 35.352 ;
     RECT  10.033 17.856 10.364 18.264 ;
     RECT  10.001 65.952 10.393 66.504 ;
     RECT  10.213 67.776 10.393 71.448 ;
     RECT  10.285 36.576 10.429 37.464 ;
     RECT  9.209 39.072 10.429 47.88 ;
     RECT  9.709 48.864 10.429 53.448 ;
     RECT  10.069 10.848 10.433 11.544 ;
     RECT  10.253 62.784 10.433 64.296 ;
     RECT  9.713 26.112 10.453 26.568 ;
     RECT  10.217 27.6 10.453 29.112 ;
     RECT  9.389 74.544 10.453 75.816 ;
     RECT  10.364 17.856 10.46 18.696 ;
     RECT  10.393 65.952 10.465 71.448 ;
     RECT  10.453 74.304 10.505 75.816 ;
     RECT  10.429 39.072 10.537 53.448 ;
     RECT  9.973 54.432 10.537 58.92 ;
     RECT  9.461 19.776 10.573 20.088 ;
     RECT  10.253 21.072 10.573 23.112 ;
     RECT  10.465 65.952 10.609 71.496 ;
     RECT  10.357 1.152 10.649 1.176 ;
     RECT  10.289 33.6 10.649 35.208 ;
     RECT  9.425 2.88 10.681 5.688 ;
     RECT  10.069 6.816 10.681 6.84 ;
     RECT  10.609 65.952 10.681 71.688 ;
     RECT  10.453 26.112 10.685 29.112 ;
     RECT  10.537 39.072 10.721 58.92 ;
     RECT  10.505 75.408 10.721 75.816 ;
     RECT  10.433 10.848 10.757 11.448 ;
     RECT  10.433 62.784 10.757 63.576 ;
     RECT  10.757 10.848 10.789 11.208 ;
     RECT  10.721 56.112 10.796 58.92 ;
     RECT  10.177 14.832 10.825 16.248 ;
     RECT  10.46 17.616 10.825 18.696 ;
     RECT  10.645 32.592 10.825 32.616 ;
     RECT  10.681 65.952 10.825 71.736 ;
     RECT  10.259 72.96 10.825 73.032 ;
     RECT  9.827 8.592 10.837 9.144 ;
     RECT  10.721 39.072 10.865 54.984 ;
     RECT  10.796 56.112 10.865 59.208 ;
     RECT  8.633 60.336 10.865 61.176 ;
     RECT  10.865 39.072 10.901 50.904 ;
     RECT  10.681 2.88 10.937 6.84 ;
     RECT  10.837 8.496 10.972 9.144 ;
     RECT  9.785 24.72 11.009 25.128 ;
     RECT  10.649 33.6 11.009 33.624 ;
     RECT  10.429 36.528 11.009 37.464 ;
     RECT  10.505 74.304 11.009 74.328 ;
     RECT  10.825 32.304 11.149 32.616 ;
     RECT  10.573 19.776 11.153 23.112 ;
     RECT  10.901 39.072 11.185 43.608 ;
     RECT  11.105 1.776 11.189 1.8 ;
     RECT  10.789 10.704 11.189 11.208 ;
     RECT  10.217 30.384 11.189 31.224 ;
     RECT  10.865 60.432 11.225 61.176 ;
     RECT  10.933 13.824 11.261 13.848 ;
     RECT  10.825 65.952 11.261 73.032 ;
     RECT  10.685 26.112 11.297 29.064 ;
     RECT  10.901 44.736 11.297 50.904 ;
     RECT  10.972 8.496 11.329 9.192 ;
     RECT  10.825 14.832 11.329 18.696 ;
     RECT  11.261 65.952 11.333 67.224 ;
     RECT  10.937 3.024 11.365 6.84 ;
     RECT  10.649 34.896 11.401 35.208 ;
     RECT  11.009 36.528 11.401 36.6 ;
     RECT  11.329 8.496 11.405 9.24 ;
     RECT  11.153 20.592 11.413 23.112 ;
     RECT  11.009 25.104 11.437 25.128 ;
     RECT  11.297 26.112 11.437 26.568 ;
     RECT  11.149 32.208 11.437 32.616 ;
     RECT  10.865 57.024 11.441 59.208 ;
     RECT  11.365 3.024 11.473 7.368 ;
     RECT  10.757 63.024 11.473 63.576 ;
     RECT  11.333 65.952 11.477 65.976 ;
     RECT  11.401 34.896 11.549 36.6 ;
     RECT  11.333 67.056 11.549 67.224 ;
     RECT  11.225 60.624 11.581 61.176 ;
     RECT  11.405 8.592 11.621 9.24 ;
     RECT  11.413 20.592 11.657 23.4 ;
     RECT  11.473 63.024 11.657 63.672 ;
     RECT  11.581 60.624 11.689 61.224 ;
     RECT  11.549 36.576 11.693 36.6 ;
     RECT  11.549 34.896 11.725 35.208 ;
     RECT  11.657 63.312 11.729 63.672 ;
     RECT  11.261 68.352 11.749 73.032 ;
     RECT  11.621 8.832 11.761 9.24 ;
     RECT  11.689 60.624 11.761 61.272 ;
     RECT  11.657 21.12 11.765 23.4 ;
     RECT  11.725 34.8 11.765 35.208 ;
     RECT  11.437 32.208 11.797 33.096 ;
     RECT  11.189 30.384 11.837 30.648 ;
     RECT  11.749 68.352 11.837 73.272 ;
     RECT  10.865 51.936 11.873 54.984 ;
     RECT  11.185 38.016 11.945 43.608 ;
     RECT  11.761 60.624 11.987 61.56 ;
     RECT  11.905 1.152 11.989 1.176 ;
     RECT  11.297 44.736 12.013 47.832 ;
     RECT  11.297 48.912 12.017 50.904 ;
     RECT  11.945 38.016 12.085 39.48 ;
     RECT  12.017 48.912 12.125 49.8 ;
     RECT  11.297 27.6 12.157 29.064 ;
     RECT  11.729 63.36 12.157 63.672 ;
     RECT  11.545 64.944 12.157 64.968 ;
     RECT  10.721 75.408 12.197 75.768 ;
     RECT  11.441 57.024 12.229 58.776 ;
     RECT  11.837 30.576 12.265 30.648 ;
     RECT  11.189 10.704 12.337 10.92 ;
     RECT  12.085 37.92 12.337 39.48 ;
     RECT  12.265 30.576 12.445 30.984 ;
     RECT  11.797 31.968 12.445 33.096 ;
     RECT  12.337 37.632 12.445 39.48 ;
     RECT  11.473 3.024 12.517 7.416 ;
     RECT  11.761 8.832 12.553 9.576 ;
     RECT  11.329 14.688 12.553 18.696 ;
     RECT  12.085 74.112 12.553 74.136 ;
     RECT  12.197 75.408 12.553 75.528 ;
     RECT  11.765 34.8 12.589 35.016 ;
     RECT  12.517 2.88 12.733 7.416 ;
     RECT  11.765 21.12 12.733 22.872 ;
     RECT  11.437 25.104 12.769 26.568 ;
     RECT  11.221 12.528 12.805 12.552 ;
     RECT  11.837 68.352 12.805 72.84 ;
     RECT  12.733 2.784 12.901 7.416 ;
     RECT  12.553 8.832 12.901 9.72 ;
     RECT  12.013 44.688 12.913 47.832 ;
     RECT  12.125 48.912 12.913 49.56 ;
     RECT  12.805 68.352 12.913 72.984 ;
     RECT  12.553 74.112 12.913 75.528 ;
     RECT  12.901 2.784 12.949 9.72 ;
     RECT  12.337 10.704 12.949 10.968 ;
     RECT  12.445 37.056 12.985 39.48 ;
     RECT  12.157 63.36 12.985 64.968 ;
     RECT  12.757 0.096 12.989 0.12 ;
     RECT  12.985 37.056 12.997 39.816 ;
     RECT  11.945 40.992 12.997 43.608 ;
     RECT  12.589 34.656 13.021 35.016 ;
     RECT  11.873 52.464 13.021 54.984 ;
     RECT  12.229 56.064 13.021 58.776 ;
     RECT  12.769 24.192 13.045 26.568 ;
     RECT  12.157 27.6 13.045 29.352 ;
     RECT  12.805 12.528 13.057 12.744 ;
     RECT  12.553 14.256 13.057 18.696 ;
     RECT  12.733 20.592 13.057 22.872 ;
     RECT  13.057 14.256 13.093 22.872 ;
     RECT  13.021 34.656 13.093 35.544 ;
     RECT  12.997 37.056 13.093 43.608 ;
     RECT  13.021 52.464 13.093 58.776 ;
     RECT  13.057 12.528 13.129 12.84 ;
     RECT  11.987 60.624 13.165 61.368 ;
     RECT  12.913 44.688 13.201 49.56 ;
     RECT  12.017 50.832 13.201 50.904 ;
     RECT  12.949 2.784 13.208 10.968 ;
     RECT  13.129 12.24 13.208 12.84 ;
     RECT  13.093 14.112 13.208 22.872 ;
     RECT  13.045 24.192 13.208 29.352 ;
     RECT  12.445 30.576 13.208 33.096 ;
     RECT  13.093 34.656 13.208 36.072 ;
     RECT  13.093 37.056 13.208 43.656 ;
     RECT  13.201 44.688 13.208 50.904 ;
     RECT  13.093 52.416 13.208 58.776 ;
     RECT  13.165 60.384 13.208 61.368 ;
     RECT  12.985 62.832 13.208 64.968 ;
     RECT  11.549 67.104 13.208 67.224 ;
     RECT  12.913 68.352 13.208 75.528 ;
     RECT  13.208 2.148 13.312 79.932 ;
     RECT  13.312 2.256 13.504 79.662 ;
     RECT  13.504 8.592 13.529 54.984 ;
     RECT  13.504 69.84 13.565 73.512 ;
     RECT  13.517 1.152 13.601 1.176 ;
     RECT  13.529 14.208 13.619 28.968 ;
     RECT  13.619 14.208 13.637 22.872 ;
     RECT  13.504 2.256 13.708 6.312 ;
     RECT  13.619 23.952 13.708 28.392 ;
     RECT  13.529 30.24 13.709 54.984 ;
     RECT  13.565 69.84 13.709 71.928 ;
     RECT  13.709 30.24 13.715 53.592 ;
     RECT  13.504 56.352 13.715 57.864 ;
     RECT  13.709 69.84 13.745 70.68 ;
     RECT  13.637 14.4 13.781 22.872 ;
     RECT  13.715 30.24 13.853 33.096 ;
     RECT  13.709 71.664 14.033 71.928 ;
     RECT  13.781 14.4 14.069 22.776 ;
     RECT  13.565 72.96 14.141 73.512 ;
     RECT  13.708 2.256 14.281 6.024 ;
     RECT  14.069 18.144 14.321 22.776 ;
     RECT  13.715 56.976 14.321 57.864 ;
     RECT  13.504 59.712 14.321 65.16 ;
     RECT  13.504 74.736 14.321 75.864 ;
     RECT  14.321 59.712 14.332 61.512 ;
     RECT  14.321 62.736 14.357 65.16 ;
     RECT  14.281 1.776 14.365 6.024 ;
     RECT  13.715 34.32 14.387 53.592 ;
     RECT  13.853 30.24 14.429 33.048 ;
     RECT  14.357 62.832 14.429 65.16 ;
     RECT  14.033 71.664 14.537 71.688 ;
     RECT  14.332 59.712 14.569 60.216 ;
     RECT  13.708 23.952 14.573 27.912 ;
     RECT  14.321 21.072 14.609 22.776 ;
     RECT  14.429 30.768 14.681 33.048 ;
     RECT  13.709 54.672 14.681 54.984 ;
     RECT  13.504 7.392 14.713 7.464 ;
     RECT  13.529 8.592 14.713 13.176 ;
     RECT  14.141 73.488 14.713 73.512 ;
     RECT  14.321 74.736 14.713 75.576 ;
     RECT  14.387 37.2 14.749 53.592 ;
     RECT  14.681 54.96 14.749 54.984 ;
     RECT  14.332 61.344 14.819 61.512 ;
     RECT  14.429 63.216 14.819 65.16 ;
     RECT  14.713 7.392 14.825 13.176 ;
     RECT  14.573 23.952 14.861 27.72 ;
     RECT  14.825 7.392 14.867 10.872 ;
     RECT  14.713 73.488 14.897 75.576 ;
     RECT  14.069 14.4 15.077 17.16 ;
     RECT  14.321 18.144 15.077 19.848 ;
     RECT  14.321 57.072 15.109 57.864 ;
     RECT  14.365 2.544 15.145 6.024 ;
     RECT  14.893 0.528 15.155 0.552 ;
     RECT  14.897 74.4 15.251 75.576 ;
     RECT  15.145 2.544 15.253 6.36 ;
     RECT  14.819 63.456 15.325 65.16 ;
     RECT  13.504 66.528 15.325 68.52 ;
     RECT  15.253 28.8 15.433 28.824 ;
     RECT  14.749 37.2 15.437 53.976 ;
     RECT  15.109 57.072 15.437 57.96 ;
     RECT  15.077 14.4 15.509 16.92 ;
     RECT  13.745 69.984 15.509 70.68 ;
     RECT  14.569 59.184 15.545 60.216 ;
     RECT  14.387 34.32 15.613 36.072 ;
     RECT  15.077 18.192 15.617 19.848 ;
     RECT  14.681 30.768 15.649 32.328 ;
     RECT  15.325 63.456 15.653 68.52 ;
     RECT  15.653 66.096 15.685 68.52 ;
     RECT  15.613 34.32 15.721 36.792 ;
     RECT  15.437 40.176 15.721 53.976 ;
     RECT  14.749 54.96 15.721 55.704 ;
     RECT  14.609 21.072 15.725 22.68 ;
     RECT  14.861 24.096 15.731 27.72 ;
     RECT  15.731 24.672 15.757 27.72 ;
     RECT  15.433 28.8 15.757 29.688 ;
     RECT  15.437 57.168 15.757 57.96 ;
     RECT  15.545 59.184 15.757 59.784 ;
     RECT  15.725 21.168 15.761 22.68 ;
     RECT  14.825 12.288 15.797 13.176 ;
     RECT  15.509 14.4 15.833 14.424 ;
     RECT  15.253 2.544 15.865 6.408 ;
     RECT  14.867 7.392 15.865 7.848 ;
     RECT  14.867 8.832 15.865 10.872 ;
     RECT  15.829 62.448 15.865 62.472 ;
     RECT  15.653 63.456 15.865 63.624 ;
     RECT  15.397 72.576 15.865 72.6 ;
     RECT  15.649 30.672 15.869 32.328 ;
     RECT  15.721 40.176 15.869 55.704 ;
     RECT  15.865 7.392 15.901 10.872 ;
     RECT  15.797 12.288 15.901 13.128 ;
     RECT  15.761 21.936 15.937 22.68 ;
     RECT  14.819 61.344 15.937 61.368 ;
     RECT  15.865 62.448 15.937 63.624 ;
     RECT  15.865 1.776 15.971 6.408 ;
     RECT  15.971 2.256 15.973 6.408 ;
     RECT  15.901 7.392 15.973 13.128 ;
     RECT  15.721 33.936 15.973 36.792 ;
     RECT  15.869 54.96 15.973 55.704 ;
     RECT  15.973 2.256 16.013 13.128 ;
     RECT  15.869 40.176 16.013 53.976 ;
     RECT  15.509 16.08 16.081 16.92 ;
     RECT  15.937 61.344 16.117 63.624 ;
     RECT  15.865 72.576 16.117 72.936 ;
     RECT  15.251 74.4 16.117 75.48 ;
     RECT  16.117 60.912 16.157 63.624 ;
     RECT  15.685 66.096 16.157 68.616 ;
     RECT  15.757 24.672 16.189 29.688 ;
     RECT  15.869 30.672 16.189 31.992 ;
     RECT  16.117 72.576 16.261 75.48 ;
     RECT  16.157 60.912 16.265 63.48 ;
     RECT  16.261 72.24 16.297 75.48 ;
     RECT  16.013 2.256 16.301 13.08 ;
     RECT  16.297 72.24 16.477 75.528 ;
     RECT  16.477 72.24 16.541 75.576 ;
     RECT  16.301 2.256 16.547 13.032 ;
     RECT  16.157 66.096 16.553 67.896 ;
     RECT  15.509 70.128 16.553 70.68 ;
     RECT  16.541 72.24 16.625 75.624 ;
     RECT  15.617 18.24 16.693 19.848 ;
     RECT  15.757 57.168 16.697 59.784 ;
     RECT  16.693 69.024 16.729 69.048 ;
     RECT  16.657 1.152 16.787 1.176 ;
     RECT  16.189 24.672 16.841 31.992 ;
     RECT  16.841 24.672 16.909 27.48 ;
     RECT  16.729 69.024 16.913 69.144 ;
     RECT  16.553 66.672 16.949 67.896 ;
     RECT  16.841 28.464 16.981 31.992 ;
     RECT  15.973 32.976 16.981 36.792 ;
     RECT  16.949 66.768 16.985 67.896 ;
     RECT  16.625 72.24 17.017 75.576 ;
     RECT  16.909 24.432 17.053 27.48 ;
     RECT  17.017 71.664 17.057 75.576 ;
     RECT  17.053 24.384 17.077 27.48 ;
     RECT  15.937 21.936 17.089 22.776 ;
     RECT  17.077 23.856 17.089 27.48 ;
     RECT  15.437 37.968 17.089 39 ;
     RECT  16.013 40.176 17.089 53.592 ;
     RECT  16.265 61.392 17.093 63.48 ;
     RECT  16.697 57.168 17.129 58.056 ;
     RECT  17.093 61.392 17.129 63.24 ;
     RECT  16.081 16.08 17.132 17.112 ;
     RECT  16.693 18.24 17.132 20.616 ;
     RECT  16.981 28.464 17.161 36.792 ;
     RECT  17.089 21.936 17.201 27.48 ;
     RECT  16.697 59.088 17.201 59.784 ;
     RECT  16.913 69.024 17.201 69.048 ;
     RECT  15.653 64.944 17.233 65.064 ;
     RECT  17.201 23.856 17.237 27.48 ;
     RECT  17.161 28.464 17.237 36.984 ;
     RECT  16.985 67.2 17.237 67.896 ;
     RECT  16.553 70.272 17.237 70.68 ;
     RECT  17.233 64.368 17.305 65.064 ;
     RECT  17.237 34.176 17.317 36.984 ;
     RECT  17.089 37.968 17.317 53.592 ;
     RECT  17.237 28.464 17.363 33.096 ;
     RECT  17.132 16.08 17.377 20.616 ;
     RECT  17.201 21.936 17.377 22.824 ;
     RECT  17.305 64.368 17.381 65.16 ;
     RECT  17.057 71.664 17.381 75.528 ;
     RECT  17.237 24.048 17.453 27.48 ;
     RECT  17.377 16.08 17.561 22.824 ;
     RECT  16.547 2.304 17.701 13.032 ;
     RECT  17.129 57.312 17.701 58.056 ;
     RECT  17.201 59.088 17.701 59.112 ;
     RECT  17.701 2.304 17.845 13.176 ;
     RECT  17.233 14.208 17.845 14.232 ;
     RECT  17.453 24.384 18.025 27.48 ;
     RECT  17.363 28.464 18.025 29.112 ;
     RECT  17.381 73.632 18.061 75.528 ;
     RECT  15.973 54.96 18.097 55.896 ;
     RECT  17.129 61.536 18.169 63.24 ;
     RECT  17.237 67.2 18.205 67.848 ;
     RECT  18.205 67.2 18.313 68.52 ;
     RECT  18.025 24.384 18.349 29.112 ;
     RECT  17.363 30.24 18.349 33.096 ;
     RECT  18.277 1.152 18.371 1.176 ;
     RECT  18.313 66.48 18.385 68.712 ;
     RECT  17.845 2.304 18.421 14.232 ;
     RECT  17.381 64.944 18.421 65.16 ;
     RECT  18.385 66.48 18.421 68.76 ;
     RECT  17.701 57.312 18.601 59.112 ;
     RECT  18.421 2.304 18.608 14.76 ;
     RECT  17.561 16.272 18.608 22.824 ;
     RECT  18.349 24.384 18.608 33.096 ;
     RECT  17.317 34.176 18.608 53.592 ;
     RECT  18.097 54.672 18.608 55.896 ;
     RECT  18.601 57.12 18.608 59.112 ;
     RECT  18.169 61.536 18.608 63.384 ;
     RECT  18.421 64.944 18.608 68.76 ;
     RECT  17.237 70.56 18.608 70.68 ;
     RECT  17.381 71.664 18.608 72.264 ;
     RECT  18.061 73.632 18.608 75.816 ;
     RECT  18.608 2.148 18.712 79.932 ;
     RECT  18.712 2.418 18.904 79.662 ;
     RECT  18.904 23.808 19.091 29.112 ;
     RECT  19.091 23.808 19.109 27.48 ;
     RECT  18.925 1.2 19.139 1.224 ;
     RECT  18.904 3.408 19.145 13.176 ;
     RECT  19.109 25.008 19.181 27.48 ;
     RECT  18.904 73.488 19.181 75.912 ;
     RECT  18.904 36 19.225 51.768 ;
     RECT  19.181 25.008 19.253 27.144 ;
     RECT  18.904 52.8 19.325 59.064 ;
     RECT  18.904 61.008 19.325 61.032 ;
     RECT  19.325 54.336 19.361 59.064 ;
     RECT  18.904 62.16 19.361 71.496 ;
     RECT  19.225 36 19.397 39.24 ;
     RECT  19.225 40.32 19.397 51.768 ;
     RECT  18.904 30.144 19.433 33.096 ;
     RECT  19.361 62.592 19.433 71.496 ;
     RECT  19.397 43.152 19.613 47.736 ;
     RECT  19.181 73.488 19.613 75.528 ;
     RECT  19.397 36 19.649 38.52 ;
     RECT  19.433 68.496 19.649 71.496 ;
     RECT  19.361 56.208 19.721 59.064 ;
     RECT  19.253 25.632 19.793 27.144 ;
     RECT  19.433 30.576 19.793 33.096 ;
     RECT  19.649 36 19.793 37.608 ;
     RECT  19.109 23.808 19.811 23.832 ;
     RECT  19.145 3.408 19.897 13.08 ;
     RECT  19.793 25.968 19.937 27.144 ;
     RECT  19.609 1.152 19.955 1.176 ;
     RECT  19.897 2.928 19.973 13.08 ;
     RECT  19.649 68.88 20.117 71.496 ;
     RECT  19.613 73.488 20.149 74.904 ;
     RECT  20.117 70.704 20.189 71.496 ;
     RECT  20.149 72.96 20.189 74.904 ;
     RECT  18.904 16.512 20.225 22.632 ;
     RECT  20.225 17.952 20.293 22.632 ;
     RECT  19.721 56.208 20.297 59.016 ;
     RECT  19.973 11.808 20.3 13.08 ;
     RECT  18.904 14.208 20.3 15.288 ;
     RECT  19.325 52.8 20.329 53.352 ;
     RECT  19.361 54.336 20.329 55.032 ;
     RECT  20.293 17.952 20.333 22.92 ;
     RECT  20.329 52.8 20.365 55.032 ;
     RECT  20.297 56.208 20.365 56.28 ;
     RECT  19.091 28.464 20.401 29.112 ;
     RECT  19.793 36 20.405 37.464 ;
     RECT  19.613 43.152 20.441 47.4 ;
     RECT  19.973 2.928 20.477 10.824 ;
     RECT  20.477 2.928 20.549 5.304 ;
     RECT  20.401 33.888 20.581 33.912 ;
     RECT  18.904 34.896 20.581 35.016 ;
     RECT  20.405 36 20.581 36.12 ;
     RECT  20.189 70.704 20.585 70.728 ;
     RECT  20.545 61.344 20.653 61.368 ;
     RECT  19.793 30.576 20.725 32.904 ;
     RECT  20.653 61.104 20.725 61.368 ;
     RECT  20.117 68.88 20.729 69.624 ;
     RECT  20.689 1.776 20.773 1.8 ;
     RECT  20.441 46.272 20.797 47.4 ;
     RECT  19.433 62.592 20.801 67.272 ;
     RECT  20.005 60 20.833 60.024 ;
     RECT  20.725 61.104 20.833 61.416 ;
     RECT  20.189 74.4 20.909 74.424 ;
     RECT  20.401 39.264 20.941 39.288 ;
     RECT  20.833 60 20.941 61.416 ;
     RECT  20.801 62.592 20.941 66.552 ;
     RECT  20.725 30.096 20.977 32.904 ;
     RECT  20.581 33.888 20.977 36.12 ;
     RECT  20.297 57.312 20.977 59.016 ;
     RECT  20.941 60 20.977 66.552 ;
     RECT  20.477 6.288 21.013 10.824 ;
     RECT  20.3 11.808 21.013 15.288 ;
     RECT  20.225 16.512 21.049 16.968 ;
     RECT  20.401 28.416 21.085 29.112 ;
     RECT  20.977 30.096 21.085 36.12 ;
     RECT  20.405 37.104 21.085 37.464 ;
     RECT  20.941 38.928 21.085 39.288 ;
     RECT  19.397 40.32 21.085 42.168 ;
     RECT  19.397 48.816 21.089 51.768 ;
     RECT  21.013 24.048 21.1 24.072 ;
     RECT  21.085 37.104 21.121 37.656 ;
     RECT  21.085 38.928 21.121 42.168 ;
     RECT  20.549 2.928 21.125 5.208 ;
     RECT  21.121 37.104 21.125 42.168 ;
     RECT  20.977 57.312 21.125 66.552 ;
     RECT  21.013 6.288 21.193 15.288 ;
     RECT  21.049 16.272 21.193 16.968 ;
     RECT  20.189 72.96 21.197 72.984 ;
     RECT  20.729 69.312 21.233 69.624 ;
     RECT  21.157 70.608 21.244 70.632 ;
     RECT  20.333 18.48 21.269 19.752 ;
     RECT  20.333 21.12 21.337 22.92 ;
     RECT  21.125 60.576 21.377 66.552 ;
     RECT  21.377 60.576 21.521 64.968 ;
     RECT  21.229 1.152 21.539 1.176 ;
     RECT  21.125 57.312 21.593 59.304 ;
     RECT  21.125 37.104 21.629 41.976 ;
     RECT  21.193 6.288 21.661 16.968 ;
     RECT  21.629 37.104 21.665 37.848 ;
     RECT  21.269 19.2 21.692 19.752 ;
     RECT  21.337 21.12 21.692 23.592 ;
     RECT  20.441 43.152 21.697 45.288 ;
     RECT  20.797 46.272 21.697 47.496 ;
     RECT  21.521 60.576 21.701 63 ;
     RECT  21.697 43.152 21.733 47.496 ;
     RECT  20.365 52.8 21.733 56.28 ;
     RECT  21.593 57.312 21.733 59.064 ;
     RECT  21.377 66.048 21.769 66.552 ;
     RECT  21.692 19.2 21.779 23.592 ;
     RECT  21.013 67.92 21.845 67.944 ;
     RECT  21.733 43.152 21.881 47.736 ;
     RECT  21.779 19.2 21.971 19.944 ;
     RECT  21.769 66.048 22.021 66.648 ;
     RECT  21.629 38.928 22.025 41.976 ;
     RECT  21.661 6.288 22.093 17.112 ;
     RECT  22.021 66.048 22.115 66.744 ;
     RECT  21.089 49.2 22.129 51.768 ;
     RECT  21.233 69.552 22.129 69.624 ;
     RECT  21.085 28.416 22.133 36.12 ;
     RECT  21.779 21.072 22.165 23.592 ;
     RECT  21.701 60.672 22.205 63 ;
     RECT  22.093 0.096 22.211 0.12 ;
     RECT  19.937 26.304 22.237 27.144 ;
     RECT  22.133 28.416 22.237 32.04 ;
     RECT  21.665 37.2 22.277 37.848 ;
     RECT  22.237 26.304 22.381 32.04 ;
     RECT  22.129 69.552 22.381 69.96 ;
     RECT  22.205 60.672 22.385 61.464 ;
     RECT  22.129 48.912 22.417 51.768 ;
     RECT  21.733 73.488 22.417 73.56 ;
     RECT  22.115 66.048 22.421 66.648 ;
     RECT  22.421 66.624 22.457 66.648 ;
     RECT  22.093 6.288 22.499 17.928 ;
     RECT  21.881 43.152 22.529 44.376 ;
     RECT  22.529 43.152 22.601 44.328 ;
     RECT  22.417 48.864 22.633 51.768 ;
     RECT  22.417 73.344 22.633 73.56 ;
     RECT  22.633 73.344 22.7 73.608 ;
     RECT  22.633 48.864 22.705 51.816 ;
     RECT  21.733 52.8 22.705 59.064 ;
     RECT  22.381 68.928 22.733 69.96 ;
     RECT  21.913 71.232 22.733 71.256 ;
     RECT  22.705 75.936 22.733 75.96 ;
     RECT  22.601 43.152 22.745 44.088 ;
     RECT  21.881 45.84 22.745 47.736 ;
     RECT  22.745 46.08 22.777 47.736 ;
     RECT  22.705 48.864 22.777 59.064 ;
     RECT  22.733 75.888 22.777 75.96 ;
     RECT  22.777 46.08 22.781 59.064 ;
     RECT  22.7 72.384 22.787 73.608 ;
     RECT  21.971 19.536 22.789 19.944 ;
     RECT  22.165 21.072 22.789 24.408 ;
     RECT  22.781 46.224 22.813 59.064 ;
     RECT  22.733 68.928 22.813 71.256 ;
     RECT  22.813 68.784 22.817 71.256 ;
     RECT  22.813 74.64 22.837 74.664 ;
     RECT  22.777 75.888 22.837 76.392 ;
     RECT  22.789 19.536 22.885 24.408 ;
     RECT  22.381 25.44 22.885 32.04 ;
     RECT  21.125 2.928 22.889 5.064 ;
     RECT  22.885 19.536 22.889 32.04 ;
     RECT  22.133 33.024 22.889 36.12 ;
     RECT  22.889 33.024 22.925 33.912 ;
     RECT  22.813 46.224 22.925 59.304 ;
     RECT  22.844 67.728 22.931 67.752 ;
     RECT  21.521 64.32 22.961 64.968 ;
     RECT  22.817 68.784 22.993 69.624 ;
     RECT  22.889 34.944 22.997 36.12 ;
     RECT  22.817 70.656 22.997 71.256 ;
     RECT  22.277 37.824 23.029 37.848 ;
     RECT  22.025 38.928 23.029 38.952 ;
     RECT  22.961 64.944 23.029 64.968 ;
     RECT  22.025 40.272 23.065 41.976 ;
     RECT  22.745 43.152 23.065 43.944 ;
     RECT  22.205 62.544 23.065 63 ;
     RECT  22.889 3.024 23.101 5.064 ;
     RECT  22.499 6.288 23.101 6.84 ;
     RECT  23.065 1.152 23.149 1.176 ;
     RECT  22.997 34.992 23.269 36.12 ;
     RECT  23.029 37.824 23.269 38.952 ;
     RECT  22.499 8.16 23.615 17.928 ;
     RECT  23.029 64.944 23.653 65.544 ;
     RECT  23.281 66.672 23.653 66.696 ;
     RECT  23.269 34.992 23.708 38.952 ;
     RECT  23.065 40.272 23.708 43.944 ;
     RECT  22.993 67.872 23.821 69.624 ;
     RECT  22.997 70.656 23.821 70.68 ;
     RECT  23.615 7.92 23.857 17.928 ;
     RECT  22.889 19.536 23.885 19.944 ;
     RECT  23.101 3.024 23.929 6.84 ;
     RECT  23.708 34.992 23.929 43.944 ;
     RECT  22.925 46.224 23.965 56.376 ;
     RECT  22.925 57.36 23.965 59.304 ;
     RECT  23.965 46.224 24.001 59.304 ;
     RECT  23.929 2.784 24.008 6.84 ;
     RECT  23.857 7.92 24.008 18.216 ;
     RECT  23.885 19.2 24.008 19.944 ;
     RECT  22.889 21.072 24.008 32.04 ;
     RECT  22.925 33.024 24.008 33.816 ;
     RECT  23.929 34.992 24.008 44.712 ;
     RECT  24.001 45.744 24.008 59.304 ;
     RECT  22.385 60.672 24.008 61.416 ;
     RECT  23.065 62.544 24.008 63.816 ;
     RECT  23.653 64.944 24.008 66.696 ;
     RECT  23.821 67.872 24.008 70.68 ;
     RECT  22.787 73.344 24.008 73.608 ;
     RECT  22.837 74.64 24.008 76.392 ;
     RECT  24.008 2.148 24.112 79.932 ;
     RECT  24.112 2.418 24.304 79.662 ;
     RECT  24.304 71.664 24.401 76.344 ;
     RECT  24.304 2.784 24.419 18.168 ;
     RECT  24.419 2.784 24.473 6.36 ;
     RECT  24.304 64.944 24.509 70.584 ;
     RECT  24.419 7.584 24.581 18.168 ;
     RECT  24.304 63.072 24.581 63.816 ;
     RECT  24.304 20.736 24.653 36.552 ;
     RECT  24.469 0.096 24.707 0.12 ;
     RECT  24.653 25.488 24.761 36.552 ;
     RECT  24.653 20.736 24.797 24.504 ;
     RECT  24.761 25.488 24.869 33.624 ;
     RECT  24.473 3.024 24.905 6.36 ;
     RECT  24.304 49.536 24.941 57.384 ;
     RECT  24.509 64.944 24.995 67.272 ;
     RECT  24.995 64.944 25.036 65.976 ;
     RECT  24.941 49.536 25.043 53.784 ;
     RECT  24.304 77.568 25.091 77.64 ;
     RECT  24.797 20.736 25.121 23.4 ;
     RECT  24.304 45.744 25.157 48.504 ;
     RECT  24.581 7.92 25.193 18.168 ;
     RECT  25.036 64.944 25.229 65.736 ;
     RECT  24.304 40.128 25.265 44.712 ;
     RECT  24.761 34.656 25.297 36.552 ;
     RECT  24.304 37.584 25.297 38.952 ;
     RECT  24.304 78.912 25.297 78.936 ;
     RECT  24.905 3.024 25.324 6.312 ;
     RECT  25.265 40.368 25.369 44.712 ;
     RECT  25.157 45.744 25.369 46.392 ;
     RECT  24.797 24.48 25.373 24.504 ;
     RECT  25.157 47.376 25.405 48.504 ;
     RECT  25.043 49.536 25.405 53.352 ;
     RECT  24.304 60.672 25.405 61.608 ;
     RECT  24.401 74.304 25.468 76.344 ;
     RECT  25.225 1.776 25.475 1.8 ;
     RECT  25.297 34.656 25.513 38.952 ;
     RECT  24.869 30.048 25.564 33.624 ;
     RECT  25.121 20.736 25.585 22.872 ;
     RECT  24.509 68.448 25.621 70.584 ;
     RECT  24.401 71.664 25.621 73.224 ;
     RECT  24.941 54.864 25.625 57.384 ;
     RECT  25.405 60.576 25.669 61.608 ;
     RECT  24.581 63.072 25.669 63.288 ;
     RECT  25.229 64.944 25.717 65.448 ;
     RECT  25.669 60.576 25.729 63.288 ;
     RECT  25.729 60.576 25.769 63.816 ;
     RECT  25.297 78.912 25.801 79.608 ;
     RECT  24.995 67.248 25.805 67.272 ;
     RECT  24.869 25.488 25.873 28.488 ;
     RECT  25.625 57.024 25.909 57.384 ;
     RECT  24.304 58.368 25.909 59.208 ;
     RECT  25.468 74.352 25.909 76.344 ;
     RECT  25.585 19.92 25.945 22.872 ;
     RECT  25.625 54.864 25.945 55.848 ;
     RECT  25.873 25.488 25.957 29.112 ;
     RECT  25.324 6.288 26.053 6.312 ;
     RECT  25.621 7.584 26.053 7.608 ;
     RECT  25.193 9.072 26.089 18.168 ;
     RECT  25.945 19.536 26.089 22.872 ;
     RECT  25.909 74.352 26.089 76.92 ;
     RECT  25.801 78.096 26.089 79.608 ;
     RECT  25.369 40.368 26.129 46.392 ;
     RECT  25.621 68.448 26.14 73.224 ;
     RECT  26.089 74.352 26.147 79.608 ;
     RECT  25.909 57.024 26.161 59.208 ;
     RECT  25.769 60.576 26.161 61.608 ;
     RECT  26.147 79.584 26.193 79.608 ;
     RECT  26.089 9.072 26.195 22.872 ;
     RECT  25.405 47.376 26.197 53.352 ;
     RECT  25.945 54.576 26.197 55.848 ;
     RECT  25.717 64.896 26.197 65.448 ;
     RECT  25.513 34.656 26.201 39.384 ;
     RECT  26.129 40.368 26.201 41.976 ;
     RECT  26.161 57.024 26.201 61.608 ;
     RECT  26.053 6.288 26.233 7.608 ;
     RECT  26.195 9.072 26.233 17.496 ;
     RECT  26.201 58.656 26.245 61.608 ;
     RECT  26.129 43.056 26.269 46.392 ;
     RECT  26.197 47.376 26.269 55.848 ;
     RECT  26.245 58.656 26.273 59.16 ;
     RECT  26.197 64.896 26.305 65.976 ;
     RECT  25.324 3.024 26.341 5.208 ;
     RECT  26.233 6.288 26.341 17.496 ;
     RECT  26.273 58.656 26.345 58.68 ;
     RECT  26.14 70.56 26.345 73.224 ;
     RECT  26.341 3.024 26.417 17.496 ;
     RECT  26.147 74.352 26.417 78.12 ;
     RECT  26.245 60.576 26.489 61.608 ;
     RECT  26.417 75.12 26.489 78.12 ;
     RECT  26.197 23.904 26.521 23.928 ;
     RECT  25.957 25.488 26.521 29.064 ;
     RECT  26.489 78.096 26.531 78.12 ;
     RECT  25.564 30.096 26.557 33.624 ;
     RECT  26.201 34.656 26.557 39.192 ;
     RECT  26.269 43.056 26.597 55.848 ;
     RECT  26.305 64.896 26.597 66.84 ;
     RECT  26.489 75.12 26.633 76.344 ;
     RECT  26.195 18.816 26.665 22.872 ;
     RECT  26.521 23.904 26.665 29.064 ;
     RECT  25.769 62.688 26.737 63.816 ;
     RECT  26.597 64.896 26.737 65.784 ;
     RECT  26.489 60.672 26.809 61.608 ;
     RECT  26.737 62.688 26.809 65.784 ;
     RECT  26.417 3.312 26.849 17.496 ;
     RECT  26.849 4.8 26.885 17.496 ;
     RECT  26.557 30.096 26.915 39.192 ;
     RECT  26.597 43.152 26.989 55.848 ;
     RECT  26.201 57.024 27.029 57.576 ;
     RECT  26.14 68.448 27.133 69.576 ;
     RECT  26.665 18.816 27.137 29.064 ;
     RECT  26.633 75.12 27.137 76.2 ;
     RECT  26.989 43.152 27.169 55.992 ;
     RECT  27.029 57.024 27.169 57.384 ;
     RECT  27.137 18.816 27.245 28.824 ;
     RECT  27.169 43.152 27.251 57.384 ;
     RECT  27.245 18.816 27.349 20.712 ;
     RECT  26.915 34.368 27.349 39.192 ;
     RECT  26.201 40.464 27.349 41.976 ;
     RECT  26.485 73.632 27.385 73.896 ;
     RECT  27.137 75.12 27.385 75.672 ;
     RECT  27.349 18.768 27.421 20.712 ;
     RECT  26.885 4.848 27.461 17.496 ;
     RECT  26.809 60.672 27.461 65.784 ;
     RECT  27.349 34.368 27.493 41.976 ;
     RECT  27.461 5.136 27.497 7.272 ;
     RECT  27.493 34.368 27.497 42.024 ;
     RECT  27.421 18.72 27.529 20.712 ;
     RECT  27.461 8.976 27.533 17.496 ;
     RECT  27.349 59.616 27.565 59.64 ;
     RECT  27.565 58.656 27.569 59.64 ;
     RECT  27.133 67.824 27.637 69.576 ;
     RECT  26.345 70.56 27.637 72.168 ;
     RECT  27.493 78.768 27.637 78.792 ;
     RECT  27.497 5.184 27.641 7.272 ;
     RECT  27.529 18.672 27.641 20.712 ;
     RECT  27.673 77.568 27.709 77.592 ;
     RECT  27.533 8.976 27.713 17.304 ;
     RECT  27.461 60.672 27.875 63.768 ;
     RECT  26.915 30.096 27.889 33.192 ;
     RECT  27.497 34.368 27.889 38.952 ;
     RECT  27.637 78.768 27.889 79.224 ;
     RECT  27.497 40.512 27.893 42.024 ;
     RECT  26.849 3.312 27.925 3.336 ;
     RECT  27.893 40.56 27.925 42.024 ;
     RECT  26.293 1.152 27.929 1.176 ;
     RECT  27.641 18.72 27.965 20.712 ;
     RECT  27.925 40.56 27.965 42.072 ;
     RECT  27.461 64.944 27.965 65.784 ;
     RECT  27.925 3.312 27.971 4.104 ;
     RECT  27.965 40.704 27.997 42.072 ;
     RECT  27.251 43.152 27.997 56.28 ;
     RECT  27.709 77.568 27.997 77.688 ;
     RECT  27.889 78.72 28.001 79.224 ;
     RECT  27.971 4.08 28.012 4.104 ;
     RECT  27.245 21.936 28.037 28.824 ;
     RECT  27.997 40.704 28.073 56.28 ;
     RECT  26.597 66.816 28.141 66.84 ;
     RECT  28.073 40.848 28.145 56.28 ;
     RECT  27.997 77.04 28.156 77.688 ;
     RECT  27.641 5.184 28.217 6.792 ;
     RECT  27.889 30.096 28.253 38.952 ;
     RECT  28.145 40.848 28.253 56.088 ;
     RECT  27.965 18.768 28.285 20.712 ;
     RECT  27.637 67.824 28.297 72.168 ;
     RECT  28.297 67.824 28.397 68.472 ;
     RECT  28.297 69.456 28.465 72.168 ;
     RECT  27.385 73.632 28.501 75.672 ;
     RECT  27.569 58.656 28.537 58.728 ;
     RECT  28.285 18.768 28.573 20.808 ;
     RECT  28.501 73.344 28.645 75.672 ;
     RECT  28.573 18.768 28.681 20.952 ;
     RECT  28.037 21.936 28.681 24.168 ;
     RECT  28.681 1.776 28.765 1.8 ;
     RECT  27.713 12.528 29.005 17.16 ;
     RECT  29.005 12.528 29.041 17.64 ;
     RECT  28.681 18.768 29.041 24.168 ;
     RECT  27.875 63.024 29.041 63.768 ;
     RECT  27.965 64.944 29.041 65.544 ;
     RECT  28.037 25.2 29.077 28.824 ;
     RECT  28.645 73.344 29.077 75.72 ;
     RECT  28.156 77.568 29.077 77.688 ;
     RECT  28.001 78.768 29.077 79.224 ;
     RECT  29.077 25.2 29.113 29.064 ;
     RECT  28.253 30.096 29.113 33.192 ;
     RECT  28.537 58.512 29.113 58.728 ;
     RECT  29.077 73.344 29.185 76.152 ;
     RECT  29.077 77.568 29.185 79.272 ;
     RECT  27.875 60.672 29.221 61.944 ;
     RECT  28.217 5.184 29.257 6.744 ;
     RECT  29.221 60.624 29.257 61.944 ;
     RECT  29.249 2.88 29.408 2.904 ;
     RECT  29.257 4.752 29.408 6.744 ;
     RECT  27.713 8.976 29.408 11.16 ;
     RECT  29.041 12.528 29.408 24.168 ;
     RECT  29.113 25.2 29.408 33.192 ;
     RECT  28.253 34.368 29.408 38.952 ;
     RECT  28.253 41.04 29.408 56.088 ;
     RECT  27.251 57.36 29.408 57.384 ;
     RECT  29.113 58.512 29.408 59.208 ;
     RECT  29.257 60.624 29.408 62.04 ;
     RECT  29.041 63.024 29.408 65.544 ;
     RECT  28.141 66.528 29.408 66.84 ;
     RECT  28.397 68.208 29.408 68.472 ;
     RECT  28.465 69.456 29.408 72.264 ;
     RECT  29.185 73.344 29.408 79.272 ;
     RECT  29.408 2.148 29.512 79.932 ;
     RECT  29.512 2.418 29.704 79.662 ;
     RECT  29.704 4.752 29.801 4.776 ;
     RECT  29.704 5.76 29.843 6.696 ;
     RECT  29.704 19.632 29.843 23.256 ;
     RECT  29.704 71.328 29.873 79.464 ;
     RECT  29.704 46.272 29.981 65.256 ;
     RECT  29.981 46.272 30.053 65.208 ;
     RECT  29.873 77.28 30.089 79.464 ;
     RECT  29.704 12.432 30.125 18.168 ;
     RECT  30.053 46.32 30.125 65.208 ;
     RECT  29.704 26.304 30.161 39.768 ;
     RECT  29.704 41.088 30.269 42.216 ;
     RECT  30.125 59.04 30.269 65.208 ;
     RECT  29.704 68.208 30.269 70.104 ;
     RECT  30.125 12.432 30.275 17.784 ;
     RECT  30.089 77.28 30.305 78.408 ;
     RECT  29.269 0.096 30.313 0.12 ;
     RECT  30.269 59.04 30.313 59.88 ;
     RECT  30.313 59.04 30.377 59.4 ;
     RECT  30.269 61.2 30.413 65.208 ;
     RECT  30.125 46.32 30.467 57.96 ;
     RECT  30.305 78.384 30.485 78.408 ;
     RECT  29.704 24.96 30.697 24.984 ;
     RECT  29.704 66.528 30.716 67.032 ;
     RECT  30.697 24.96 30.733 25.128 ;
     RECT  30.161 26.304 30.733 39.384 ;
     RECT  30.716 66.528 30.803 67.224 ;
     RECT  29.704 8.16 30.812 8.424 ;
     RECT  30.733 3.936 30.841 3.96 ;
     RECT  29.873 71.328 30.845 75.816 ;
     RECT  29.843 5.808 30.877 6.696 ;
     RECT  30.467 46.32 30.881 51.288 ;
     RECT  30.881 46.32 30.917 47.976 ;
     RECT  30.917 46.32 30.989 47.832 ;
     RECT  30.377 59.184 30.989 59.4 ;
     RECT  30.841 3.072 31.021 3.96 ;
     RECT  29.704 9.552 31.061 11.448 ;
     RECT  30.733 24.96 31.097 39.384 ;
     RECT  31.021 2.88 31.105 3.96 ;
     RECT  31.097 24.96 31.129 29.064 ;
     RECT  31.097 30.096 31.133 39.384 ;
     RECT  30.845 71.52 31.133 75.816 ;
     RECT  30.413 62.448 31.141 65.208 ;
     RECT  30.269 68.208 31.148 69.864 ;
     RECT  31.133 71.904 31.165 75.816 ;
     RECT  30.275 12.432 31.169 17.736 ;
     RECT  30.467 52.272 31.169 57.96 ;
     RECT  30.812 8.16 31.201 8.472 ;
     RECT  31.061 9.552 31.201 11.064 ;
     RECT  31.148 68.064 31.235 69.864 ;
     RECT  31.105 3.024 31.309 3.96 ;
     RECT  30.877 5.472 31.309 6.696 ;
     RECT  31.235 68.448 31.313 69.864 ;
     RECT  31.169 53.04 31.349 57.96 ;
     RECT  31.165 71.904 31.349 75.96 ;
     RECT  31.309 3.024 31.381 6.696 ;
     RECT  31.201 8.16 31.381 11.064 ;
     RECT  31.381 3.024 31.385 11.064 ;
     RECT  31.129 24.624 31.385 29.064 ;
     RECT  30.881 49.056 31.385 51.288 ;
     RECT  31.385 49.056 31.457 51.24 ;
     RECT  30.269 41.136 31.489 42.216 ;
     RECT  29.704 43.44 31.489 44.184 ;
     RECT  31.385 3.024 31.493 10.392 ;
     RECT  30.413 61.2 31.525 61.224 ;
     RECT  31.141 62.448 31.525 65.496 ;
     RECT  29.843 19.632 31.532 23.208 ;
     RECT  31.532 19.584 31.561 23.208 ;
     RECT  31.385 24.624 31.561 27.864 ;
     RECT  30.089 79.44 31.561 79.464 ;
     RECT  31.489 41.136 31.597 44.184 ;
     RECT  31.349 71.904 31.601 72.888 ;
     RECT  31.561 19.584 31.619 27.864 ;
     RECT  30.989 46.32 31.669 47.736 ;
     RECT  31.525 61.2 31.705 65.496 ;
     RECT  30.803 66.528 31.705 66.6 ;
     RECT  30.305 77.28 31.777 77.304 ;
     RECT  31.561 78.624 31.777 79.464 ;
     RECT  31.313 68.448 31.817 69.528 ;
     RECT  31.597 41.136 31.849 44.232 ;
     RECT  31.849 40.752 31.885 44.232 ;
     RECT  31.349 53.376 31.885 57.96 ;
     RECT  30.989 59.184 31.885 59.256 ;
     RECT  31.777 1.776 31.907 1.8 ;
     RECT  31.457 49.056 31.907 51.192 ;
     RECT  31.169 12.624 31.921 17.736 ;
     RECT  31.669 46.032 31.921 47.736 ;
     RECT  31.777 77.28 31.955 79.464 ;
     RECT  31.705 61.2 31.957 66.6 ;
     RECT  31.493 3.072 31.997 10.392 ;
     RECT  31.133 30.096 32.137 33.672 ;
     RECT  31.885 53.376 32.137 59.256 ;
     RECT  31.957 60.288 32.137 66.6 ;
     RECT  31.997 4.896 32.141 10.392 ;
     RECT  31.955 77.28 32.141 77.688 ;
     RECT  32.137 30.048 32.173 33.672 ;
     RECT  31.385 28.944 32.177 29.064 ;
     RECT  32.137 53.376 32.243 66.6 ;
     RECT  31.885 40.656 32.245 44.232 ;
     RECT  32.141 77.28 32.245 77.4 ;
     RECT  31.997 3.072 32.249 3.48 ;
     RECT  32.243 56.976 32.249 66.6 ;
     RECT  32.249 3.072 32.285 3.192 ;
     RECT  32.173 30.048 32.293 33.864 ;
     RECT  31.133 34.896 32.293 39.384 ;
     RECT  31.349 73.872 32.353 75.96 ;
     RECT  32.245 77.136 32.353 77.4 ;
     RECT  31.921 12.624 32.357 17.784 ;
     RECT  32.245 40.656 32.389 44.616 ;
     RECT  31.921 45.792 32.389 47.736 ;
     RECT  32.249 59.712 32.389 66.6 ;
     RECT  31.817 68.448 32.389 69.288 ;
     RECT  32.293 30.048 32.39 39.384 ;
     RECT  32.357 12.768 32.465 17.784 ;
     RECT  32.243 53.376 32.465 55.944 ;
     RECT  32.389 59.712 32.465 69.288 ;
     RECT  31.907 49.104 32.473 51.192 ;
     RECT  31.601 72.048 32.492 72.888 ;
     RECT  32.353 73.872 32.492 77.4 ;
     RECT  32.39 34.896 32.497 39.384 ;
     RECT  32.389 40.656 32.497 47.736 ;
     RECT  32.497 34.896 32.581 47.736 ;
     RECT  32.39 30.048 32.609 33.864 ;
     RECT  32.177 29.04 32.645 29.064 ;
     RECT  31.955 78.864 32.645 78.888 ;
     RECT  31.619 19.632 32.681 27.864 ;
     RECT  32.465 59.712 32.681 65.208 ;
     RECT  32.629 0.528 32.716 0.552 ;
     RECT  32.681 19.632 32.753 19.8 ;
     RECT  32.581 40.176 32.773 47.736 ;
     RECT  32.753 19.632 32.789 19.656 ;
     RECT  32.681 20.88 32.789 27.864 ;
     RECT  32.465 66.288 32.825 69.288 ;
     RECT  32.789 26.208 32.857 27.864 ;
     RECT  32.609 30.048 32.857 33.576 ;
     RECT  32.773 40.176 32.86 47.88 ;
     RECT  32.789 20.88 32.861 25.224 ;
     RECT  32.861 24.624 32.969 25.224 ;
     RECT  32.861 20.88 33.011 23.16 ;
     RECT  32.581 34.896 33.077 38.952 ;
     RECT  32.473 49.872 33.077 51.192 ;
     RECT  32.492 72.048 33.109 77.4 ;
     RECT  32.465 13.248 33.145 17.784 ;
     RECT  32.281 70.512 33.145 70.536 ;
     RECT  33.109 71.664 33.145 77.4 ;
     RECT  32.857 29.616 33.149 33.576 ;
     RECT  33.145 70.512 33.181 77.4 ;
     RECT  33.077 34.944 33.185 38.952 ;
     RECT  32.465 54.192 33.217 55.944 ;
     RECT  32.249 56.976 33.217 58.728 ;
     RECT  32.681 59.712 33.221 64.968 ;
     RECT  33.077 50.112 33.325 51.192 ;
     RECT  33.181 70.512 33.329 77.496 ;
     RECT  32.141 8.256 33.365 10.392 ;
     RECT  33.217 54.192 33.401 58.728 ;
     RECT  33.145 13.248 33.433 18.216 ;
     RECT  33.329 70.512 33.437 70.536 ;
     RECT  33.073 11.472 33.505 11.496 ;
     RECT  33.433 12.768 33.505 18.216 ;
     RECT  33.011 21.024 33.545 23.16 ;
     RECT  32.825 66.288 33.545 68.952 ;
     RECT  33.149 30.096 33.581 33.576 ;
     RECT  32.141 4.896 33.589 7.224 ;
     RECT  33.365 8.256 33.589 10.344 ;
     RECT  33.581 31.248 33.617 33.576 ;
     RECT  32.569 2.88 33.649 2.904 ;
     RECT  32.86 40.176 33.653 47.736 ;
     RECT  33.589 48.96 33.676 48.984 ;
     RECT  33.185 34.992 33.692 38.952 ;
     RECT  33.329 72.144 33.725 77.496 ;
     RECT  33.617 31.344 33.757 33.576 ;
     RECT  33.653 40.704 33.761 47.736 ;
     RECT  33.545 66.288 33.761 67.8 ;
     RECT  33.692 34.992 33.779 39.576 ;
     RECT  33.761 66.288 33.829 67.272 ;
     RECT  33.545 21.648 33.833 23.16 ;
     RECT  33.829 66.24 33.901 67.272 ;
     RECT  33.505 11.472 34.076 18.216 ;
     RECT  33.649 2.88 34.189 2.952 ;
     RECT  33.545 68.88 34.213 68.952 ;
     RECT  34.261 0.576 34.297 0.6 ;
     RECT  34.297 0.576 34.345 1.176 ;
     RECT  33.725 72.144 34.412 76.392 ;
     RECT  33.325 50.112 34.46 51.432 ;
     RECT  33.589 4.896 34.477 10.344 ;
     RECT  33.221 59.808 34.513 64.968 ;
     RECT  33.901 66.192 34.513 67.272 ;
     RECT  33.401 54.192 34.549 55.944 ;
     RECT  33.401 56.976 34.549 58.728 ;
     RECT  32.857 26.208 34.621 27.912 ;
     RECT  34.412 71.856 34.657 76.392 ;
     RECT  34.076 11.472 34.685 18.696 ;
     RECT  34.477 4.752 34.693 10.344 ;
     RECT  34.549 54.192 34.693 58.728 ;
     RECT  34.513 59.808 34.693 67.272 ;
     RECT  33.757 31.344 34.801 33.96 ;
     RECT  34.189 2.88 34.808 3.096 ;
     RECT  34.693 4.752 34.808 10.44 ;
     RECT  34.685 11.424 34.808 18.696 ;
     RECT  33.833 21.648 34.808 22.872 ;
     RECT  32.969 25.2 34.808 25.224 ;
     RECT  34.621 26.208 34.808 28.44 ;
     RECT  33.581 30.096 34.808 30.12 ;
     RECT  34.801 31.2 34.808 33.96 ;
     RECT  33.779 34.992 34.808 38.952 ;
     RECT  33.761 41.664 34.808 47.736 ;
     RECT  34.46 50.112 34.808 51.528 ;
     RECT  34.153 53.04 34.808 53.064 ;
     RECT  34.693 54.192 34.808 67.272 ;
     RECT  34.213 68.88 34.808 70.104 ;
     RECT  34.657 71.664 34.808 76.392 ;
     RECT  34.069 78.048 34.808 78.072 ;
     RECT  34.808 2.148 34.912 79.932 ;
     RECT  34.345 1.152 35.075 1.176 ;
     RECT  34.912 2.418 35.104 79.662 ;
     RECT  35.104 58.704 35.165 67.848 ;
     RECT  35.104 14.448 35.219 20.136 ;
     RECT  35.104 76.224 35.309 76.632 ;
     RECT  35.104 25.296 35.315 39.336 ;
     RECT  35.309 76.368 35.353 76.632 ;
     RECT  35.104 50.16 35.417 53.016 ;
     RECT  35.219 16.08 35.633 20.136 ;
     RECT  35.104 54.144 35.633 57.384 ;
     RECT  35.165 58.704 35.633 64.968 ;
     RECT  35.633 62.448 35.669 64.968 ;
     RECT  35.104 78.048 35.821 78.696 ;
     RECT  35.104 68.928 35.849 70.056 ;
     RECT  35.104 2.88 35.891 3.768 ;
     RECT  35.633 57.312 35.957 57.384 ;
     RECT  35.821 78.048 35.957 78.072 ;
     RECT  35.104 4.752 36.029 13.464 ;
     RECT  35.219 14.448 36.065 15 ;
     RECT  35.315 29.808 36.085 39.336 ;
     RECT  35.104 40.416 36.085 49.128 ;
     RECT  35.104 21.744 36.133 23.976 ;
     RECT  35.165 66.288 36.133 67.848 ;
     RECT  35.417 52.32 36.169 53.016 ;
     RECT  35.633 54.144 36.169 55.512 ;
     RECT  36.085 29.808 36.173 49.128 ;
     RECT  36.173 34.992 36.205 49.128 ;
     RECT  35.417 50.16 36.205 51.24 ;
     RECT  36.133 66.288 36.229 68.52 ;
     RECT  35.633 18.864 36.277 20.136 ;
     RECT  35.669 62.544 36.277 64.968 ;
     RECT  36.173 29.808 36.278 34.008 ;
     RECT  36.029 13.44 36.313 13.464 ;
     RECT  35.957 57.36 36.313 57.384 ;
     RECT  35.633 58.704 36.313 61.368 ;
     RECT  36.229 66.048 36.316 68.52 ;
     RECT  36.313 57.36 36.323 61.368 ;
     RECT  35.315 25.296 36.349 28.584 ;
     RECT  35.104 71.664 36.349 74.904 ;
     RECT  36.277 18.864 36.353 20.376 ;
     RECT  36.323 57.36 36.364 59.496 ;
     RECT  36.353 20.064 36.385 20.376 ;
     RECT  35.891 3.024 36.421 3.768 ;
     RECT  36.029 4.752 36.421 12.36 ;
     RECT  36.323 60.528 36.461 61.368 ;
     RECT  36.461 60.672 36.497 61.368 ;
     RECT  36.133 21.504 36.569 23.976 ;
     RECT  36.349 25.248 36.601 28.584 ;
     RECT  36.169 52.32 36.601 55.512 ;
     RECT  36.601 52.272 36.677 55.752 ;
     RECT  36.601 25.248 36.709 29.064 ;
     RECT  36.065 14.832 36.781 15 ;
     RECT  35.633 16.08 36.781 17.64 ;
     RECT  36.205 34.992 36.785 51.24 ;
     RECT  35.849 69.552 36.821 70.056 ;
     RECT  36.421 3.024 36.853 12.36 ;
     RECT  36.781 14.832 36.889 17.64 ;
     RECT  36.353 18.864 36.889 18.888 ;
     RECT  36.853 79.248 36.889 79.272 ;
     RECT  36.709 1.776 36.929 1.8 ;
     RECT  36.677 54.192 36.961 55.752 ;
     RECT  36.364 57.36 36.961 58.296 ;
     RECT  36.364 59.472 37.001 59.496 ;
     RECT  36.853 2.976 37.033 12.36 ;
     RECT  36.313 13.44 37.033 13.608 ;
     RECT  36.349 71.664 37.033 75.192 ;
     RECT  35.353 76.608 37.033 76.632 ;
     RECT  36.889 78.624 37.033 79.272 ;
     RECT  36.785 34.992 37.043 40.632 ;
     RECT  36.277 62.544 37.061 65.016 ;
     RECT  36.316 66.288 37.073 68.52 ;
     RECT  37.043 34.992 37.091 39.768 ;
     RECT  36.889 14.832 37.109 18.888 ;
     RECT  36.785 41.712 37.181 51.24 ;
     RECT  37.033 70.656 37.213 70.68 ;
     RECT  37.033 71.664 37.213 76.632 ;
     RECT  37.181 41.712 37.253 50.952 ;
     RECT  37.213 70.656 37.289 76.632 ;
     RECT  37.033 78.096 37.321 79.272 ;
     RECT  37.289 70.656 37.325 75.672 ;
     RECT  37.073 66.48 37.357 68.52 ;
     RECT  36.821 69.552 37.357 69.576 ;
     RECT  36.278 30.096 37.381 34.008 ;
     RECT  37.091 34.992 37.381 39.432 ;
     RECT  36.709 25.152 37.393 29.064 ;
     RECT  37.061 62.448 37.393 65.016 ;
     RECT  37.253 41.712 37.397 50.52 ;
     RECT  37.033 2.976 37.465 13.608 ;
     RECT  37.109 14.832 37.465 18.792 ;
     RECT  36.497 60.672 37.465 60.696 ;
     RECT  37.393 62.448 37.465 65.256 ;
     RECT  37.321 77.904 37.465 79.272 ;
     RECT  37.105 0.528 37.475 0.552 ;
     RECT  37.393 25.104 37.501 29.064 ;
     RECT  37.397 42.048 37.541 50.52 ;
     RECT  37.325 70.8 37.571 75.672 ;
     RECT  37.465 2.976 37.577 18.792 ;
     RECT  36.385 20.064 37.577 20.52 ;
     RECT  36.569 21.504 37.577 23.352 ;
     RECT  37.465 76.992 37.577 79.272 ;
     RECT  37.465 60.288 37.619 60.696 ;
     RECT  37.577 6.384 37.649 18.792 ;
     RECT  37.541 42.048 37.649 50.376 ;
     RECT  37.649 42.048 37.721 49.224 ;
     RECT  37.577 77.328 37.829 79.272 ;
     RECT  37.577 20.112 37.901 20.52 ;
     RECT  37.577 2.976 37.933 5.16 ;
     RECT  36.677 52.272 37.933 53.208 ;
     RECT  36.961 54.192 37.933 58.296 ;
     RECT  37.829 78 38.009 79.272 ;
     RECT  37.577 21.504 38.077 23.16 ;
     RECT  37.381 30.096 38.081 39.432 ;
     RECT  37.465 61.92 38.081 65.256 ;
     RECT  37.933 52.272 38.113 58.296 ;
     RECT  38.081 30.096 38.149 39.384 ;
     RECT  37.501 25.056 38.156 29.064 ;
     RECT  38.149 30.048 38.156 39.384 ;
     RECT  37.721 42.048 38.189 49.128 ;
     RECT  37.649 50.352 38.189 50.376 ;
     RECT  38.077 20.976 38.195 23.16 ;
     RECT  38.156 25.056 38.243 39.384 ;
     RECT  38.113 52.272 38.257 58.728 ;
     RECT  37.649 6.384 38.261 11.64 ;
     RECT  38.185 0.096 38.269 0.12 ;
     RECT  38.243 28.704 38.477 39.384 ;
     RECT  37.571 71.184 38.477 75.672 ;
     RECT  37.649 12.912 38.509 18.792 ;
     RECT  37.933 2.736 38.513 5.16 ;
     RECT  38.009 78 38.524 78.648 ;
     RECT  38.509 12.912 38.545 18.84 ;
     RECT  38.477 71.184 38.581 74.664 ;
     RECT  37.357 66.48 38.617 69.576 ;
     RECT  38.581 70.656 38.617 74.664 ;
     RECT  38.545 12.912 38.621 19.656 ;
     RECT  38.195 21.024 38.725 23.16 ;
     RECT  38.243 25.056 38.725 27.432 ;
     RECT  38.653 40.416 38.761 40.44 ;
     RECT  37.619 60.672 38.761 60.696 ;
     RECT  38.513 3.12 38.797 5.16 ;
     RECT  38.477 31.392 38.837 39.384 ;
     RECT  38.189 43.152 38.869 49.128 ;
     RECT  38.761 60.576 39.049 60.696 ;
     RECT  38.081 62.352 39.049 65.256 ;
     RECT  38.621 13.056 39.053 19.656 ;
     RECT  39.013 0.576 39.097 0.6 ;
     RECT  39.049 60.576 39.109 65.256 ;
     RECT  38.257 52.272 39.157 58.824 ;
     RECT  38.797 3.12 39.265 5.256 ;
     RECT  39.157 52.272 39.265 58.968 ;
     RECT  38.477 75.648 39.265 75.672 ;
     RECT  39.265 3.12 39.301 5.592 ;
     RECT  38.261 7.2 39.301 11.64 ;
     RECT  39.265 52.176 39.337 59.064 ;
     RECT  39.109 60.288 39.337 65.256 ;
     RECT  38.725 21.024 39.409 27.432 ;
     RECT  38.477 28.704 39.409 30.216 ;
     RECT  38.189 42.048 39.409 42.072 ;
     RECT  38.869 43.152 39.409 49.608 ;
     RECT  39.337 52.176 39.481 65.256 ;
     RECT  38.617 66.48 39.481 74.664 ;
     RECT  38.761 40.416 39.517 40.68 ;
     RECT  39.409 42.048 39.517 49.608 ;
     RECT  39.481 52.176 39.517 74.664 ;
     RECT  39.265 75.648 39.517 76.056 ;
     RECT  39.301 3.12 39.769 11.64 ;
     RECT  39.409 21.024 39.913 30.216 ;
     RECT  39.769 2.64 40.069 11.64 ;
     RECT  39.053 13.056 40.069 17.304 ;
     RECT  40.069 2.64 40.208 17.304 ;
     RECT  39.053 18.432 40.208 19.656 ;
     RECT  39.913 21.024 40.208 30.36 ;
     RECT  38.837 31.392 40.208 39.288 ;
     RECT  39.517 40.416 40.208 49.608 ;
     RECT  39.517 52.176 40.208 76.056 ;
     RECT  38.524 78.432 40.208 78.648 ;
     RECT  40.208 2.148 40.312 79.932 ;
     RECT  40.312 2.256 40.504 79.662 ;
     RECT  39.265 0.096 40.643 0.12 ;
     RECT  40.504 2.256 40.643 5.352 ;
     RECT  40.504 26.304 40.643 33.672 ;
     RECT  40.504 66.288 40.745 69.048 ;
     RECT  40.504 6.384 40.781 11.496 ;
     RECT  40.504 70.128 40.889 74.664 ;
     RECT  40.643 2.256 40.925 2.28 ;
     RECT  40.504 13.104 40.997 17.4 ;
     RECT  40.745 67.68 41.033 69.048 ;
     RECT  40.504 20.304 41.219 25.32 ;
     RECT  40.643 3.36 41.285 5.352 ;
     RECT  41.033 68.4 41.285 69.048 ;
     RECT  40.504 18.72 41.357 18.744 ;
     RECT  40.504 34.656 41.429 49.608 ;
     RECT  41.353 1.728 41.437 1.752 ;
     RECT  40.643 31.44 41.497 33.672 ;
     RECT  41.429 34.656 41.497 38.952 ;
     RECT  40.889 71.232 41.603 74.664 ;
     RECT  40.504 77.76 41.603 77.928 ;
     RECT  40.504 75.792 41.605 76.056 ;
     RECT  41.603 77.904 41.645 77.928 ;
     RECT  40.504 51.696 41.749 65.256 ;
     RECT  40.745 66.288 41.749 66.6 ;
     RECT  41.749 51.696 41.753 66.6 ;
     RECT  40.781 6.624 41.785 11.496 ;
     RECT  41.429 39.936 41.785 49.608 ;
     RECT  41.753 51.888 41.857 66.6 ;
     RECT  40.889 70.128 41.857 70.152 ;
     RECT  41.603 71.232 41.857 73.944 ;
     RECT  41.219 20.304 41.893 24.168 ;
     RECT  41.785 6.624 41.929 12.072 ;
     RECT  41.285 3.888 41.965 5.352 ;
     RECT  41.219 25.152 41.965 25.32 ;
     RECT  40.643 26.304 41.965 30.12 ;
     RECT  41.857 51.888 41.969 66.744 ;
     RECT  41.965 3.888 42.001 5.544 ;
     RECT  41.929 6.624 42.001 12.312 ;
     RECT  42.001 3.888 42.073 12.312 ;
     RECT  40.997 13.344 42.073 17.4 ;
     RECT  41.497 31.44 42.077 38.952 ;
     RECT  41.285 68.4 42.145 68.904 ;
     RECT  42.181 0.192 42.217 0.216 ;
     RECT  41.893 19.344 42.229 24.168 ;
     RECT  41.965 25.152 42.229 30.12 ;
     RECT  41.605 75.792 42.253 76.776 ;
     RECT  41.749 2.832 42.284 2.856 ;
     RECT  42.073 3.888 42.284 18.216 ;
     RECT  42.229 19.344 42.293 30.12 ;
     RECT  42.217 0.096 42.301 0.216 ;
     RECT  42.293 20.64 42.365 30.12 ;
     RECT  41.969 58.896 42.437 66.744 ;
     RECT  42.077 33.6 42.469 38.952 ;
     RECT  41.785 39.936 42.469 50.568 ;
     RECT  40.504 79.392 42.469 79.416 ;
     RECT  42.284 2.832 42.509 18.216 ;
     RECT  42.469 33.6 42.649 50.568 ;
     RECT  41.857 70.128 42.685 73.944 ;
     RECT  42.365 20.64 42.689 28.968 ;
     RECT  42.365 30.096 42.721 30.12 ;
     RECT  42.437 61.44 42.721 66.744 ;
     RECT  42.145 67.872 42.721 68.904 ;
     RECT  42.301 0.192 42.755 0.216 ;
     RECT  42.721 61.44 42.757 68.904 ;
     RECT  42.685 70.08 42.757 73.944 ;
     RECT  42.469 79.008 42.757 79.416 ;
     RECT  42.757 61.44 42.793 73.944 ;
     RECT  42.253 74.928 42.793 76.776 ;
     RECT  42.437 58.896 42.941 60.072 ;
     RECT  42.077 31.44 42.973 32.376 ;
     RECT  42.689 20.64 42.977 27.336 ;
     RECT  42.793 61.44 43.013 76.776 ;
     RECT  43.013 69.696 43.049 76.776 ;
     RECT  42.757 77.808 43.049 79.416 ;
     RECT  42.973 31.392 43.081 32.376 ;
     RECT  42.509 5.136 43.085 18.216 ;
     RECT  43.013 61.44 43.085 68.424 ;
     RECT  43.049 75.84 43.085 76.776 ;
     RECT  43.085 12.48 43.117 18.216 ;
     RECT  42.293 19.344 43.117 19.368 ;
     RECT  41.969 51.888 43.117 57.864 ;
     RECT  42.941 58.896 43.117 59.832 ;
     RECT  43.049 69.696 43.121 72.6 ;
     RECT  42.689 28.464 43.193 28.968 ;
     RECT  43.085 5.136 43.229 11.496 ;
     RECT  42.721 30.096 43.229 30.168 ;
     RECT  43.085 61.584 43.229 68.424 ;
     RECT  43.117 12.48 43.276 19.368 ;
     RECT  42.649 33.6 43.297 50.76 ;
     RECT  43.229 61.968 43.301 68.424 ;
     RECT  43.229 6 43.331 11.496 ;
     RECT  43.297 33.6 43.337 50.808 ;
     RECT  43.121 69.696 43.372 72.216 ;
     RECT  43.276 14.928 43.373 19.368 ;
     RECT  43.117 51.888 43.373 59.832 ;
     RECT  42.977 20.64 43.397 24.264 ;
     RECT  43.331 6.384 43.409 11.496 ;
     RECT  43.373 51.888 43.409 55.752 ;
     RECT  43.301 61.968 43.409 67.128 ;
     RECT  43.409 51.888 43.427 55.704 ;
     RECT  43.397 19.92 43.481 24.264 ;
     RECT  42.509 2.832 43.513 3.672 ;
     RECT  43.337 42.048 43.513 50.808 ;
     RECT  43.427 51.888 43.513 54.216 ;
     RECT  43.373 56.736 43.517 59.832 ;
     RECT  43.513 2.832 43.549 3.864 ;
     RECT  43.081 31.392 43.693 32.472 ;
     RECT  43.049 73.584 43.697 74.424 ;
     RECT  43.229 30.096 43.765 30.12 ;
     RECT  43.049 77.808 43.765 79.176 ;
     RECT  43.513 42.048 43.805 54.216 ;
     RECT  42.977 25.248 43.837 27.336 ;
     RECT  43.693 31.152 43.837 32.472 ;
     RECT  43.337 33.6 43.837 41.016 ;
     RECT  43.409 61.968 43.877 66.888 ;
     RECT  43.877 65.856 43.913 66.888 ;
     RECT  43.085 75.84 43.949 76.392 ;
     RECT  43.193 28.944 43.981 28.968 ;
     RECT  43.765 30.048 43.981 30.12 ;
     RECT  43.481 20.16 44.017 24.264 ;
     RECT  43.837 25.248 44.017 27.432 ;
     RECT  43.837 31.152 44.021 41.016 ;
     RECT  43.877 61.968 44.057 64.872 ;
     RECT  43.372 69.696 44.093 70.872 ;
     RECT  43.301 68.352 44.197 68.424 ;
     RECT  43.697 73.776 44.269 74.424 ;
     RECT  43.549 2.832 44.305 4.68 ;
     RECT  43.805 42.048 44.345 45.96 ;
     RECT  44.017 20.16 44.377 27.432 ;
     RECT  44.269 73.776 44.377 74.712 ;
     RECT  43.949 75.84 44.377 76.056 ;
     RECT  44.3 5.712 44.387 5.736 ;
     RECT  43.805 47.088 44.413 54.216 ;
     RECT  43.427 55.392 44.413 55.704 ;
     RECT  43.517 56.736 44.417 59.4 ;
     RECT  43.409 6.72 44.485 11.496 ;
     RECT  43.276 12.48 44.485 13.944 ;
     RECT  43.913 66.24 44.485 66.888 ;
     RECT  44.377 73.776 44.489 76.056 ;
     RECT  44.485 66.24 44.521 67.32 ;
     RECT  44.197 68.352 44.521 69.432 ;
     RECT  44.377 20.16 44.525 27.672 ;
     RECT  43.372 72.192 44.525 72.216 ;
     RECT  44.485 6.72 44.557 13.944 ;
     RECT  44.521 66.24 44.572 69.432 ;
     RECT  43.765 77.616 44.593 79.176 ;
     RECT  44.489 73.776 44.633 75.144 ;
     RECT  43.373 14.928 44.665 18.792 ;
     RECT  44.525 20.16 44.665 27.432 ;
     RECT  43.981 28.944 44.665 30.12 ;
     RECT  44.021 31.344 44.845 41.016 ;
     RECT  44.345 42.048 44.845 45.768 ;
     RECT  44.593 77.568 44.845 79.176 ;
     RECT  44.557 6.048 44.924 13.944 ;
     RECT  44.665 14.928 44.924 27.432 ;
     RECT  44.305 2.544 45.025 4.68 ;
     RECT  44.057 61.968 45.025 64.632 ;
     RECT  44.093 70.656 45.205 70.872 ;
     RECT  44.572 68.208 45.241 69.432 ;
     RECT  45.205 70.656 45.241 71.208 ;
     RECT  45.025 61.008 45.277 64.632 ;
     RECT  44.633 73.776 45.421 74.712 ;
     RECT  45.377 1.152 45.461 1.176 ;
     RECT  44.413 47.088 45.493 55.704 ;
     RECT  44.417 56.736 45.493 59.256 ;
     RECT  44.924 6.048 45.565 27.432 ;
     RECT  45.493 47.088 45.565 59.256 ;
     RECT  44.665 28.944 45.601 30.168 ;
     RECT  44.845 31.344 45.601 45.768 ;
     RECT  45.025 2.544 45.608 4.968 ;
     RECT  45.565 6 45.608 27.432 ;
     RECT  45.601 28.944 45.608 45.768 ;
     RECT  45.565 47.04 45.608 59.256 ;
     RECT  45.277 61.008 45.608 64.968 ;
     RECT  44.572 66.24 45.608 66.36 ;
     RECT  45.241 68.208 45.608 71.208 ;
     RECT  45.421 73.248 45.608 74.712 ;
     RECT  44.845 77.04 45.608 79.176 ;
     RECT  45.608 2.148 45.712 79.932 ;
     RECT  45.712 2.148 45.904 79.662 ;
     RECT  45.904 72.336 45.965 75.672 ;
     RECT  45.904 2.784 46.001 27.576 ;
     RECT  46.001 18.72 46.019 27.576 ;
     RECT  46.019 19.536 46.115 27.576 ;
     RECT  46.115 25.488 46.181 27.576 ;
     RECT  46.133 1.776 46.217 1.8 ;
     RECT  45.904 28.56 46.217 33.096 ;
     RECT  45.904 34.08 46.217 48.216 ;
     RECT  45.904 67.632 46.253 71.208 ;
     RECT  46.181 25.488 46.289 27.432 ;
     RECT  45.965 72.336 46.289 74.328 ;
     RECT  46.115 19.536 46.325 24.456 ;
     RECT  45.904 77.04 46.361 78.648 ;
     RECT  46.289 73.872 46.397 74.328 ;
     RECT  46.001 2.784 46.433 17.64 ;
     RECT  46.217 28.56 46.433 31.944 ;
     RECT  46.289 25.488 46.469 27.384 ;
     RECT  46.217 46.704 46.469 48.216 ;
     RECT  46.325 19.776 46.613 24.456 ;
     RECT  46.469 46.704 46.613 47.064 ;
     RECT  46.613 19.968 46.649 24.456 ;
     RECT  46.217 32.928 46.685 33.096 ;
     RECT  45.904 60.96 46.739 66.408 ;
     RECT  45.965 75.648 46.739 75.672 ;
     RECT  46.433 12.624 46.757 17.64 ;
     RECT  46.361 77.568 46.793 78.648 ;
     RECT  46.649 21.12 46.865 24.456 ;
     RECT  46.739 60.96 46.885 61.128 ;
     RECT  45.904 58.512 47.005 59.256 ;
     RECT  46.885 60.912 47.005 61.128 ;
     RECT  46.253 69.552 47.005 71.208 ;
     RECT  46.289 72.336 47.005 72.36 ;
     RECT  45.904 49.248 47.029 57.048 ;
     RECT  47.005 58.128 47.029 59.256 ;
     RECT  47.005 69.552 47.045 72.36 ;
     RECT  46.981 1.152 47.081 1.176 ;
     RECT  46.469 48.048 47.149 48.216 ;
     RECT  47.029 49.248 47.149 59.256 ;
     RECT  46.397 74.304 47.153 74.328 ;
     RECT  46.613 46.704 47.225 46.776 ;
     RECT  46.793 78.048 47.231 78.648 ;
     RECT  46.739 62.208 47.257 66.408 ;
     RECT  46.253 67.632 47.257 68.568 ;
     RECT  47.257 62.208 47.261 68.568 ;
     RECT  47.149 48.048 47.267 59.256 ;
     RECT  46.757 16.32 47.293 17.64 ;
     RECT  46.217 34.08 47.333 45.576 ;
     RECT  47.267 56.112 47.333 59.256 ;
     RECT  46.469 26.208 47.365 27.384 ;
     RECT  46.433 28.56 47.365 31.512 ;
     RECT  47.333 58.128 47.365 59.256 ;
     RECT  47.005 60.24 47.365 61.128 ;
     RECT  47.045 69.552 47.369 71.832 ;
     RECT  47.333 38.592 47.405 45.576 ;
     RECT  47.372 73.92 47.459 73.944 ;
     RECT  46.757 12.624 47.473 15.288 ;
     RECT  47.405 40.992 47.477 45.576 ;
     RECT  46.433 2.784 47.5 11.544 ;
     RECT  47.5 3.12 47.509 11.544 ;
     RECT  47.473 12.528 47.509 15.288 ;
     RECT  47.267 48.048 47.513 54.648 ;
     RECT  47.365 26.208 47.545 31.512 ;
     RECT  47.477 40.992 47.549 43.896 ;
     RECT  47.369 71.184 47.549 71.832 ;
     RECT  47.513 50.832 47.585 54.648 ;
     RECT  47.405 38.592 47.621 39.864 ;
     RECT  47.513 48.048 47.621 49.848 ;
     RECT  47.225 46.752 47.653 46.776 ;
     RECT  46.649 19.968 47.657 20.04 ;
     RECT  47.653 46.752 47.657 47.304 ;
     RECT  47.369 69.552 47.749 70.104 ;
     RECT  46.685 32.928 47.761 32.952 ;
     RECT  47.333 34.08 47.761 37.416 ;
     RECT  47.749 69.504 47.836 70.104 ;
     RECT  47.545 26.208 47.869 31.704 ;
     RECT  47.761 32.928 47.869 37.416 ;
     RECT  47.789 1.776 47.873 1.8 ;
     RECT  47.549 71.184 47.909 71.208 ;
     RECT  47.293 16.32 47.941 17.832 ;
     RECT  47.621 48.96 48.017 49.848 ;
     RECT  47.585 50.832 48.017 54.552 ;
     RECT  47.365 58.128 48.049 61.128 ;
     RECT  47.261 62.208 48.049 68.52 ;
     RECT  48.049 58.128 48.053 68.52 ;
     RECT  47.657 19.968 48.157 19.992 ;
     RECT  47.231 78.048 48.161 79.224 ;
     RECT  47.869 26.208 48.197 37.416 ;
     RECT  46.865 21.456 48.229 24.456 ;
     RECT  48.229 21.168 48.269 24.456 ;
     RECT  48.197 28.8 48.301 37.416 ;
     RECT  47.621 38.592 48.301 39.24 ;
     RECT  47.977 74.976 48.301 75 ;
     RECT  48.161 78.048 48.305 78.504 ;
     RECT  47.549 40.992 48.341 42.072 ;
     RECT  48.017 51.168 48.377 54.552 ;
     RECT  47.333 56.112 48.38 57.144 ;
     RECT  48.053 58.128 48.38 59.304 ;
     RECT  47.509 3.12 48.412 15.288 ;
     RECT  47.941 16.32 48.449 18.216 ;
     RECT  48.38 56.112 48.467 59.304 ;
     RECT  48.269 21.168 48.485 23.64 ;
     RECT  48.301 28.8 48.485 39.24 ;
     RECT  48.341 41.952 48.553 42.072 ;
     RECT  47.549 43.392 48.553 43.896 ;
     RECT  48.377 51.456 48.553 54.552 ;
     RECT  48.467 56.112 48.553 57.144 ;
     RECT  47.836 69.6 48.553 70.104 ;
     RECT  48.485 28.896 48.557 31.464 ;
     RECT  47.473 73.584 48.557 73.608 ;
     RECT  48.412 3.12 48.593 5.592 ;
     RECT  48.412 6.576 48.593 15.288 ;
     RECT  48.301 74.976 48.593 75.432 ;
     RECT  48.485 21.168 48.629 21.192 ;
     RECT  48.305 78.096 48.629 78.504 ;
     RECT  48.553 41.952 48.661 43.896 ;
     RECT  47.477 44.88 48.661 45.576 ;
     RECT  48.485 22.224 48.701 23.64 ;
     RECT  48.629 78.096 48.701 78.12 ;
     RECT  48.197 26.208 48.709 27.336 ;
     RECT  48.485 32.448 48.733 39.24 ;
     RECT  48.709 25.68 48.796 27.336 ;
     RECT  48.593 14.928 48.805 15.288 ;
     RECT  48.449 16.32 48.805 17.688 ;
     RECT  48.796 26.256 48.809 27.336 ;
     RECT  48.733 32.448 48.809 39.624 ;
     RECT  48.517 76.608 48.812 76.632 ;
     RECT  48.565 1.152 48.881 1.176 ;
     RECT  48.553 69.6 48.881 70.296 ;
     RECT  48.812 75.648 48.899 76.632 ;
     RECT  48.053 60.336 48.917 68.52 ;
     RECT  48.899 76.224 48.995 76.632 ;
     RECT  48.985 73.824 48.997 73.848 ;
     RECT  48.157 19.2 49.061 19.992 ;
     RECT  48.917 60.336 49.061 61.32 ;
     RECT  48.949 25.056 49.105 25.224 ;
     RECT  48.593 3.36 49.133 5.592 ;
     RECT  47.657 47.28 49.169 47.304 ;
     RECT  48.997 73.824 49.201 73.944 ;
     RECT  48.593 6.576 49.235 13.752 ;
     RECT  48.661 41.952 49.381 45.576 ;
     RECT  48.557 29.088 49.385 31.464 ;
     RECT  48.809 32.448 49.385 35.016 ;
     RECT  49.133 5.28 49.417 5.592 ;
     RECT  49.235 6.576 49.417 6.888 ;
     RECT  49.105 25.056 49.457 25.08 ;
     RECT  49.381 1.776 49.465 1.8 ;
     RECT  49.235 8.112 49.561 13.752 ;
     RECT  48.805 14.928 49.561 17.688 ;
     RECT  49.061 19.824 49.561 19.992 ;
     RECT  49.381 21.12 49.561 21.144 ;
     RECT  48.553 51.456 49.561 57.144 ;
     RECT  48.467 58.128 49.561 59.304 ;
     RECT  48.917 62.448 49.561 68.52 ;
     RECT  49.561 62.448 49.565 68.952 ;
     RECT  48.995 76.608 49.565 76.632 ;
     RECT  48.017 49.584 49.597 49.848 ;
     RECT  49.385 32.928 49.601 35.016 ;
     RECT  48.809 36.048 49.601 39.624 ;
     RECT  49.385 29.088 49.669 30.168 ;
     RECT  48.881 70.272 49.673 70.296 ;
     RECT  49.601 39.6 49.705 39.624 ;
     RECT  49.381 41.232 49.705 45.576 ;
     RECT  48.809 26.304 49.709 27.336 ;
     RECT  49.561 8.112 49.741 17.688 ;
     RECT  49.141 18.672 49.741 18.696 ;
     RECT  49.741 8.112 49.745 18.696 ;
     RECT  49.201 73.824 49.765 74.568 ;
     RECT  49.705 39.6 49.781 45.576 ;
     RECT  49.765 72.912 49.921 74.568 ;
     RECT  49.561 19.824 49.925 21.144 ;
     RECT  49.921 72.432 49.925 74.568 ;
     RECT  48.701 22.368 49.993 23.64 ;
     RECT  49.925 72.432 50.005 74.184 ;
     RECT  49.597 49.584 50.029 50.232 ;
     RECT  49.561 51.456 50.029 59.304 ;
     RECT  49.669 28.32 50.033 30.168 ;
     RECT  49.133 3.36 50.137 4.2 ;
     RECT  49.745 8.16 50.137 18.696 ;
     RECT  49.565 63.6 50.137 68.952 ;
     RECT  49.565 62.448 50.173 62.616 ;
     RECT  50.029 49.584 50.281 59.304 ;
     RECT  50.137 75.216 50.281 75.24 ;
     RECT  50.197 1.152 50.285 1.176 ;
     RECT  50.137 63.6 50.293 69 ;
     RECT  49.993 22.272 50.317 23.64 ;
     RECT  49.633 77.472 50.317 77.496 ;
     RECT  50.137 3.12 50.353 4.2 ;
     RECT  50.281 75.216 50.353 75.432 ;
     RECT  50.317 22.272 50.425 24.072 ;
     RECT  49.385 31.44 50.497 31.464 ;
     RECT  49.601 32.928 50.497 32.952 ;
     RECT  49.781 44.976 50.533 45.576 ;
     RECT  50.461 46.8 50.533 46.824 ;
     RECT  50.317 77.472 50.569 78.072 ;
     RECT  49.525 48.336 50.581 48.36 ;
     RECT  50.281 49.584 50.581 59.352 ;
     RECT  49.709 26.352 50.588 27.336 ;
     RECT  50.033 28.32 50.588 30.12 ;
     RECT  50.533 44.976 50.636 46.824 ;
     RECT  50.581 48.336 50.636 59.352 ;
     RECT  50.569 77.088 50.641 78.072 ;
     RECT  49.601 34.224 50.677 35.016 ;
     RECT  50.636 44.976 50.713 59.352 ;
     RECT  49.061 60.336 50.713 60.696 ;
     RECT  50.173 62.4 50.713 62.616 ;
     RECT  50.293 63.6 50.713 70.152 ;
     RECT  50.713 62.4 50.749 70.152 ;
     RECT  50.497 31.44 50.773 32.952 ;
     RECT  50.677 34.176 50.773 35.016 ;
     RECT  50.749 62.208 50.785 70.152 ;
     RECT  50.713 71.616 50.785 71.64 ;
     RECT  50.353 2.784 50.849 4.2 ;
     RECT  49.417 5.28 50.849 6.888 ;
     RECT  50.137 8.16 50.869 18.792 ;
     RECT  50.849 2.784 50.893 6.888 ;
     RECT  50.869 7.968 50.893 18.792 ;
     RECT  50.785 62.208 50.893 71.64 ;
     RECT  50.893 2.784 51.008 18.792 ;
     RECT  49.925 20.304 51.008 21.144 ;
     RECT  50.425 22.272 51.008 24.168 ;
     RECT  50.588 26.352 51.008 30.12 ;
     RECT  50.773 31.44 51.008 35.016 ;
     RECT  49.601 36.048 51.008 38.424 ;
     RECT  49.781 39.6 51.008 43.848 ;
     RECT  50.713 44.976 51.008 60.696 ;
     RECT  50.893 61.728 51.008 71.64 ;
     RECT  50.005 72.912 51.008 74.184 ;
     RECT  50.353 75.216 51.008 75.528 ;
     RECT  50.641 76.992 51.008 78.072 ;
     RECT  51.008 2.148 51.112 79.932 ;
     RECT  51.112 2.418 51.304 79.662 ;
     RECT  51.304 20.88 51.365 21.528 ;
     RECT  51.304 61.728 51.365 64.392 ;
     RECT  51.304 77.088 51.365 77.112 ;
     RECT  51.304 39.6 51.401 39.864 ;
     RECT  51.304 28.176 51.437 38.424 ;
     RECT  51.304 41.52 51.443 47.928 ;
     RECT  51.401 39.696 51.473 39.864 ;
     RECT  51.443 43.008 51.473 47.928 ;
     RECT  51.437 34.176 51.509 38.424 ;
     RECT  51.473 46.752 51.545 47.928 ;
     RECT  51.437 28.176 51.581 33.096 ;
     RECT  51.545 46.848 51.653 47.928 ;
     RECT  51.304 14.928 51.689 18.792 ;
     RECT  51.304 23.616 51.689 25.272 ;
     RECT  51.581 28.512 51.689 33.096 ;
     RECT  51.509 34.176 51.689 37.752 ;
     RECT  51.365 62.016 51.689 64.392 ;
     RECT  51.304 5.28 51.725 13.896 ;
     RECT  51.473 43.008 51.731 45.48 ;
     RECT  51.304 73.824 51.797 75.528 ;
     RECT  51.749 1.152 51.833 1.176 ;
     RECT  51.304 49.584 51.941 60.696 ;
     RECT  51.941 50.832 52.067 60.696 ;
     RECT  51.689 34.176 52.157 37.704 ;
     RECT  52.157 34.176 52.229 34.776 ;
     RECT  51.473 39.792 52.333 39.864 ;
     RECT  51.443 41.52 52.333 41.976 ;
     RECT  51.689 64.368 52.333 64.392 ;
     RECT  51.304 65.52 52.333 71.64 ;
     RECT  51.725 5.28 52.337 13.656 ;
     RECT  51.689 14.928 52.337 18.504 ;
     RECT  52.067 50.832 52.373 60.168 ;
     RECT  52.157 36.24 52.445 37.704 ;
     RECT  51.689 28.512 52.451 32.76 ;
     RECT  51.365 21.024 52.513 21.528 ;
     RECT  52.369 22.512 52.513 22.536 ;
     RECT  51.653 46.848 52.513 47.352 ;
     RECT  52.333 64.368 52.513 71.64 ;
     RECT  51.304 72.72 52.513 72.744 ;
     RECT  51.797 74.064 52.513 75.528 ;
     RECT  51.304 2.88 52.549 4.2 ;
     RECT  52.337 5.28 52.549 6.84 ;
     RECT  52.513 21.024 52.549 22.536 ;
     RECT  51.689 23.616 52.549 24.264 ;
     RECT  52.333 39.792 52.549 41.976 ;
     RECT  51.731 43.008 52.549 45.192 ;
     RECT  52.373 50.976 52.553 60.168 ;
     RECT  52.513 74.064 52.588 75.864 ;
     RECT  52.337 8.16 52.589 13.656 ;
     RECT  51.304 27.072 52.621 27.144 ;
     RECT  52.451 28.512 52.621 30.696 ;
     RECT  52.513 46.704 52.621 47.352 ;
     RECT  51.689 25.248 52.657 25.272 ;
     RECT  52.549 39.792 52.657 45.192 ;
     RECT  52.337 16.32 52.697 18.504 ;
     RECT  52.588 74.064 52.733 74.856 ;
     RECT  52.657 39.696 52.765 45.192 ;
     RECT  52.588 75.84 52.765 75.864 ;
     RECT  52.553 52.032 52.769 60.168 ;
     RECT  52.621 27.072 52.801 30.696 ;
     RECT  52.765 75.84 52.801 76.632 ;
     RECT  52.451 32.208 52.837 32.76 ;
     RECT  51.689 62.016 52.837 63.24 ;
     RECT  52.513 64.368 52.837 72.744 ;
     RECT  52.765 39.696 52.841 45.72 ;
     RECT  52.837 32.208 52.901 33.048 ;
     RECT  52.229 34.176 52.901 34.2 ;
     RECT  52.589 12.816 52.909 13.656 ;
     RECT  52.445 36.24 52.913 37.608 ;
     RECT  52.901 32.208 52.985 34.2 ;
     RECT  52.981 20.016 53.017 20.04 ;
     RECT  52.549 21.024 53.017 24.264 ;
     RECT  52.841 42 53.017 45.72 ;
     RECT  52.621 46.704 53.017 47.88 ;
     RECT  53.017 42 53.021 47.88 ;
     RECT  52.733 74.496 53.021 74.856 ;
     RECT  53.021 42 53.027 42.744 ;
     RECT  52.697 16.32 53.057 17.64 ;
     RECT  52.769 52.224 53.089 60.168 ;
     RECT  53.057 16.32 53.093 17.544 ;
     RECT  53.089 52.224 53.116 60.312 ;
     RECT  52.589 8.16 53.201 11.544 ;
     RECT  52.909 12.816 53.233 13.896 ;
     RECT  52.837 62.016 53.269 72.744 ;
     RECT  53.116 52.224 53.273 57.672 ;
     RECT  53.017 20.016 53.305 24.264 ;
     RECT  52.657 25.248 53.305 25.608 ;
     RECT  53.021 74.496 53.308 74.712 ;
     RECT  52.337 14.928 53.341 15.24 ;
     RECT  53.093 16.32 53.341 17.496 ;
     RECT  52.549 2.88 53.381 6.84 ;
     RECT  53.333 1.152 53.417 1.176 ;
     RECT  53.381 6.336 53.417 6.84 ;
     RECT  53.269 61.872 53.417 72.744 ;
     RECT  53.021 43.92 53.452 47.88 ;
     RECT  53.381 2.88 53.453 5.352 ;
     RECT  53.233 12.816 53.485 13.944 ;
     RECT  53.341 14.928 53.485 17.496 ;
     RECT  53.452 44.4 53.489 47.88 ;
     RECT  52.801 26.736 53.519 30.696 ;
     RECT  52.985 32.208 53.519 33.048 ;
     RECT  53.305 20.016 53.525 25.608 ;
     RECT  53.417 68.064 53.557 72.744 ;
     RECT  52.801 75.84 53.557 77.352 ;
     RECT  51.941 49.584 53.593 49.848 ;
     RECT  52.553 50.976 53.593 51 ;
     RECT  53.557 68.064 53.603 72.984 ;
     RECT  53.201 9.072 53.605 11.544 ;
     RECT  53.485 12.816 53.605 17.496 ;
     RECT  53.525 20.4 53.629 25.608 ;
     RECT  53.519 26.736 53.629 33.048 ;
     RECT  53.593 78.672 53.629 78.696 ;
     RECT  53.417 6.672 53.633 6.744 ;
     RECT  53.489 44.784 53.633 47.88 ;
     RECT  53.417 61.872 53.633 66.888 ;
     RECT  53.593 49.584 53.665 51 ;
     RECT  53.605 9.072 53.669 17.496 ;
     RECT  52.913 36.24 53.701 37.464 ;
     RECT  53.629 20.4 53.705 33.048 ;
     RECT  53.633 63.072 53.705 66.888 ;
     RECT  53.665 49.056 53.741 51 ;
     RECT  52.841 39.696 53.809 41.016 ;
     RECT  53.453 2.88 53.813 4.2 ;
     RECT  53.603 68.064 53.813 71.256 ;
     RECT  53.813 2.928 53.885 4.2 ;
     RECT  53.557 75.84 53.953 77.64 ;
     RECT  53.273 53.04 53.993 57.672 ;
     RECT  53.705 63.072 53.993 66.84 ;
     RECT  53.629 78.672 53.993 79.032 ;
     RECT  53.308 74.688 53.996 74.712 ;
     RECT  53.953 75.696 53.996 77.64 ;
     RECT  53.705 32.784 54.025 33.048 ;
     RECT  52.985 34.176 54.025 34.2 ;
     RECT  53.809 39.552 54.065 41.016 ;
     RECT  53.633 44.784 54.065 47.352 ;
     RECT  53.993 55.92 54.065 57.672 ;
     RECT  53.701 35.712 54.097 37.464 ;
     RECT  53.633 6.672 54.101 6.696 ;
     RECT  53.705 20.4 54.137 31.32 ;
     RECT  53.885 2.976 54.173 4.2 ;
     RECT  53.669 9.072 54.173 17.448 ;
     RECT  54.065 55.92 54.209 56.664 ;
     RECT  53.996 74.688 54.277 77.64 ;
     RECT  53.116 58.656 54.349 60.312 ;
     RECT  53.633 61.872 54.349 62.088 ;
     RECT  53.453 5.232 54.385 5.352 ;
     RECT  54.065 57.648 54.385 57.672 ;
     RECT  54.349 58.656 54.385 62.088 ;
     RECT  53.603 72.288 54.385 72.984 ;
     RECT  54.173 3.072 54.46 4.2 ;
     RECT  54.385 5.232 54.46 5.448 ;
     RECT  54.46 3.072 54.461 5.448 ;
     RECT  54.277 74.64 54.461 77.64 ;
     RECT  54.461 3.216 54.533 5.448 ;
     RECT  54.065 39.552 54.565 40.92 ;
     RECT  54.065 44.784 54.605 47.064 ;
     RECT  53.741 49.056 54.637 49.608 ;
     RECT  54.173 9.072 54.641 16.344 ;
     RECT  54.565 38.976 54.649 40.92 ;
     RECT  53.027 42 54.673 42.552 ;
     RECT  53.741 50.784 54.709 51 ;
     RECT  54.461 74.832 54.709 77.64 ;
     RECT  53.993 78.672 54.709 78.696 ;
     RECT  53.993 53.04 54.745 54.648 ;
     RECT  54.533 3.744 54.749 5.448 ;
     RECT  54.641 12.816 54.749 16.344 ;
     RECT  54.709 74.832 54.749 78.696 ;
     RECT  54.025 32.784 54.781 34.2 ;
     RECT  54.781 31.968 54.785 34.2 ;
     RECT  54.649 39.552 54.785 40.92 ;
     RECT  54.745 52.368 54.805 54.648 ;
     RECT  53.845 19.344 54.817 19.368 ;
     RECT  54.137 20.4 54.817 30.696 ;
     RECT  54.817 19.344 54.821 30.696 ;
     RECT  53.993 63.84 54.821 66.84 ;
     RECT  54.749 13.632 54.829 16.344 ;
     RECT  54.637 48.672 54.853 49.608 ;
     RECT  54.385 72.288 54.857 73.56 ;
     RECT  54.749 76.992 54.857 78.696 ;
     RECT  54.709 50.688 54.889 51.24 ;
     RECT  54.805 52.32 54.889 54.648 ;
     RECT  54.785 32.976 54.925 34.2 ;
     RECT  54.857 76.992 54.929 77.112 ;
     RECT  54.889 50.688 54.965 54.648 ;
     RECT  53.953 0.096 54.995 0.12 ;
     RECT  54.821 19.344 54.997 27.144 ;
     RECT  54.857 78.144 54.997 78.696 ;
     RECT  54.997 18.576 55.001 27.144 ;
     RECT  54.853 48.528 55.033 49.608 ;
     RECT  54.965 50.688 55.033 50.712 ;
     RECT  53.813 68.064 55.033 71.208 ;
     RECT  54.857 72.288 55.033 73.224 ;
     RECT  54.965 52.176 55.037 54.648 ;
     RECT  54.997 78.144 55.081 79.272 ;
     RECT  54.821 28.416 55.105 30.696 ;
     RECT  54.925 32.976 55.105 34.488 ;
     RECT  54.097 35.712 55.105 37.992 ;
     RECT  54.821 63.984 55.141 66.84 ;
     RECT  54.605 44.784 55.145 45.528 ;
     RECT  54.209 55.92 55.177 56.136 ;
     RECT  55.105 28.416 55.235 30.84 ;
     RECT  54.749 74.832 55.253 75.72 ;
     RECT  54.173 17.424 55.285 17.448 ;
     RECT  55.001 18.576 55.285 20.424 ;
     RECT  55.145 44.784 55.285 44.904 ;
     RECT  55.001 21.408 55.289 27.144 ;
     RECT  55.235 28.416 55.289 30.696 ;
     RECT  54.749 5.136 55.325 5.448 ;
     RECT  53.881 7.728 55.325 7.992 ;
     RECT  54.785 31.968 55.331 31.992 ;
     RECT  55.105 32.976 55.331 37.992 ;
     RECT  55.331 35.712 55.357 37.992 ;
     RECT  54.673 41.904 55.357 42.552 ;
     RECT  55.325 5.136 55.361 5.352 ;
     RECT  55.357 35.712 55.361 38.424 ;
     RECT  55.361 35.904 55.397 38.424 ;
     RECT  55.253 74.832 55.397 74.856 ;
     RECT  55.141 63.984 55.429 67.08 ;
     RECT  55.033 68.064 55.429 73.224 ;
     RECT  55.325 7.728 55.58 7.752 ;
     RECT  55.177 55.44 55.645 56.136 ;
     RECT  54.385 57.648 55.645 62.088 ;
     RECT  55.397 36.624 55.717 38.424 ;
     RECT  54.785 39.552 55.717 40.824 ;
     RECT  55.58 7.344 55.789 7.752 ;
     RECT  55.289 26.352 55.82 27.144 ;
     RECT  55.289 28.416 55.82 30.6 ;
     RECT  54.829 14.976 55.825 16.344 ;
     RECT  55.429 63.984 55.825 73.224 ;
     RECT  55.753 1.776 55.837 1.8 ;
     RECT  55.331 32.976 55.964 34.488 ;
     RECT  55.081 78.144 56.005 78.648 ;
     RECT  55.825 14.976 56.041 16.392 ;
     RECT  55.037 52.176 56.041 54.456 ;
     RECT  55.033 48.528 56.053 50.712 ;
     RECT  55.357 41.904 56.113 42.6 ;
     RECT  55.285 44.304 56.113 44.904 ;
     RECT  55.825 63.984 56.113 73.704 ;
     RECT  54.829 13.632 56.149 13.944 ;
     RECT  56.041 14.928 56.149 16.392 ;
     RECT  56.113 41.904 56.149 44.904 ;
     RECT  55.285 17.424 56.257 20.424 ;
     RECT  55.289 21.408 56.257 25.128 ;
     RECT  56.005 78.096 56.257 78.648 ;
     RECT  55.789 6.672 56.329 7.752 ;
     RECT  55.897 3.408 56.408 3.432 ;
     RECT  55.897 4.656 56.408 4.68 ;
     RECT  56.329 6.576 56.408 7.752 ;
     RECT  54.641 9.072 56.408 11.736 ;
     RECT  56.149 13.104 56.408 16.392 ;
     RECT  56.257 17.424 56.408 25.128 ;
     RECT  55.82 26.352 56.408 30.6 ;
     RECT  55.964 32.448 56.408 34.488 ;
     RECT  55.717 36.624 56.408 40.824 ;
     RECT  56.149 41.904 56.408 45 ;
     RECT  54.605 46.848 56.408 47.064 ;
     RECT  56.053 48.432 56.408 50.712 ;
     RECT  56.041 52.032 56.408 54.456 ;
     RECT  55.645 55.44 56.408 62.808 ;
     RECT  56.113 63.888 56.408 73.704 ;
     RECT  54.929 77.04 56.408 77.112 ;
     RECT  56.257 78.096 56.408 79.224 ;
     RECT  56.408 2.148 56.512 79.932 ;
     RECT  56.501 1.152 56.585 1.176 ;
     RECT  56.512 2.148 56.704 79.662 ;
     RECT  56.704 61.152 56.765 61.368 ;
     RECT  56.704 14.976 56.819 27.72 ;
     RECT  56.704 52.032 56.837 59.88 ;
     RECT  56.704 72.528 56.909 73.608 ;
     RECT  56.837 52.272 57.011 59.88 ;
     RECT  56.704 62.736 57.017 71.352 ;
     RECT  56.819 14.976 57.053 18.792 ;
     RECT  56.704 35.52 57.053 39.816 ;
     RECT  57.011 57.6 57.053 59.832 ;
     RECT  57.011 52.272 57.089 56.568 ;
     RECT  56.704 3.168 57.125 12.024 ;
     RECT  56.704 46.752 57.148 50.712 ;
     RECT  57.053 14.976 57.197 18.744 ;
     RECT  56.819 19.824 57.233 27.72 ;
     RECT  56.704 74.592 57.233 79.272 ;
     RECT  56.909 72.528 57.269 72.552 ;
     RECT  57.125 3.408 57.395 12.024 ;
     RECT  57.233 74.592 57.413 76.344 ;
     RECT  57.337 1.776 57.421 1.8 ;
     RECT  57.233 77.328 57.449 79.272 ;
     RECT  57.148 46.752 57.485 50.616 ;
     RECT  57.089 54.432 57.521 56.568 ;
     RECT  57.053 35.52 57.557 39.24 ;
     RECT  57.395 3.408 57.629 7.224 ;
     RECT  57.629 3.696 57.635 7.224 ;
     RECT  57.395 8.448 57.665 12.024 ;
     RECT  57.017 68.208 57.665 71.352 ;
     RECT  57.197 14.976 57.685 18.264 ;
     RECT  56.704 44.64 57.697 45 ;
     RECT  57.665 68.208 57.701 70.152 ;
     RECT  57.413 76.32 57.737 76.344 ;
     RECT  57.485 46.752 57.845 49.608 ;
     RECT  57.521 54.432 57.845 55.512 ;
     RECT  57.697 44.64 57.877 45.576 ;
     RECT  56.704 32.496 57.884 34.44 ;
     RECT  56.704 41.472 57.917 43.368 ;
     RECT  56.704 13.104 57.949 13.656 ;
     RECT  57.845 54.432 57.953 55.464 ;
     RECT  57.884 32.448 57.971 34.44 ;
     RECT  57.521 56.496 58.021 56.568 ;
     RECT  57.053 57.6 58.021 59.784 ;
     RECT  57.449 77.328 58.061 79.224 ;
     RECT  57.233 19.824 58.093 25.704 ;
     RECT  57.635 3.696 58.097 6.984 ;
     RECT  57.233 26.88 58.117 27.72 ;
     RECT  56.704 28.8 58.117 31.368 ;
     RECT  57.485 50.592 58.129 50.616 ;
     RECT  57.089 52.272 58.129 53.4 ;
     RECT  57.953 54.432 58.129 55.272 ;
     RECT  57.017 62.736 58.165 67.176 ;
     RECT  57.701 68.208 58.165 68.76 ;
     RECT  57.949 13.056 58.201 13.656 ;
     RECT  57.845 46.752 58.201 47.208 ;
     RECT  58.129 1.152 58.213 1.176 ;
     RECT  57.971 32.496 58.237 34.44 ;
     RECT  58.021 56.496 58.237 59.784 ;
     RECT  56.765 61.344 58.237 61.368 ;
     RECT  58.117 26.88 58.277 31.368 ;
     RECT  58.061 77.52 58.307 79.224 ;
     RECT  58.201 12.528 58.309 13.656 ;
     RECT  57.685 14.784 58.309 18.264 ;
     RECT  58.093 19.296 58.309 25.704 ;
     RECT  56.909 73.584 58.309 73.608 ;
     RECT  57.877 44.592 58.313 45.576 ;
     RECT  58.309 73.488 58.349 73.608 ;
     RECT  58.307 78.144 58.349 79.224 ;
     RECT  57.665 8.448 58.457 11.496 ;
     RECT  58.309 12.528 58.457 25.704 ;
     RECT  57.413 74.592 58.457 74.712 ;
     RECT  58.237 32.496 58.489 34.488 ;
     RECT  57.557 35.52 58.489 36.024 ;
     RECT  57.557 37.152 58.489 39.24 ;
     RECT  57.917 41.568 58.489 43.368 ;
     RECT  58.313 44.592 58.489 44.856 ;
     RECT  58.129 50.592 58.489 50.76 ;
     RECT  58.093 72.432 58.489 72.456 ;
     RECT  58.349 73.488 58.489 73.512 ;
     RECT  58.237 56.496 58.493 61.368 ;
     RECT  58.493 57.84 58.525 61.368 ;
     RECT  58.165 62.736 58.525 68.76 ;
     RECT  58.097 5.712 58.597 6.984 ;
     RECT  58.493 56.496 58.601 56.52 ;
     RECT  58.597 74.88 58.604 75.144 ;
     RECT  58.489 32.496 58.633 36.024 ;
     RECT  58.489 37.152 58.633 39.288 ;
     RECT  58.525 57.84 58.645 68.76 ;
     RECT  58.457 9.072 58.669 11.496 ;
     RECT  57.665 71.328 58.673 71.352 ;
     RECT  58.561 0.096 58.691 0.12 ;
     RECT  58.097 3.696 58.691 4.728 ;
     RECT  58.457 19.488 58.709 25.704 ;
     RECT  58.645 57.84 58.709 66.552 ;
     RECT  57.845 48.48 58.741 49.608 ;
     RECT  58.489 50.592 58.741 51.24 ;
     RECT  58.645 67.536 58.741 68.76 ;
     RECT  57.701 69.792 58.741 70.152 ;
     RECT  58.604 74.88 58.741 75.528 ;
     RECT  58.129 52.272 58.745 55.272 ;
     RECT  58.277 26.88 58.773 30.792 ;
     RECT  58.633 32.496 58.777 39.288 ;
     RECT  58.489 41.568 58.817 44.856 ;
     RECT  58.597 5.712 58.837 7.416 ;
     RECT  58.741 48.48 58.853 51.24 ;
     RECT  58.773 26.88 58.885 30.744 ;
     RECT  58.709 19.488 58.925 25.608 ;
     RECT  58.837 5.712 58.993 7.464 ;
     RECT  58.741 67.536 58.993 70.152 ;
     RECT  58.993 5.712 58.997 7.944 ;
     RECT  58.709 60.384 59.033 66.552 ;
     RECT  58.997 5.712 59.069 5.928 ;
     RECT  58.777 32.496 59.105 39.48 ;
     RECT  58.925 19.488 59.141 25.56 ;
     RECT  58.691 3.696 59.173 4.488 ;
     RECT  59.033 63.84 59.177 66.552 ;
     RECT  58.201 46.704 59.209 47.208 ;
     RECT  59.033 60.384 59.213 62.856 ;
     RECT  58.457 12.528 59.249 18.456 ;
     RECT  58.489 72.432 59.249 73.512 ;
     RECT  58.741 74.88 59.269 75.864 ;
     RECT  59.249 13.104 59.321 18.456 ;
     RECT  58.745 52.272 59.321 54.744 ;
     RECT  58.885 26.64 59.357 30.744 ;
     RECT  59.105 32.496 59.357 36.024 ;
     RECT  59.213 60.384 59.357 61.176 ;
     RECT  59.269 74.88 59.357 76.488 ;
     RECT  58.817 43.632 59.389 44.856 ;
     RECT  59.209 46.608 59.429 47.208 ;
     RECT  59.321 52.56 59.465 54.744 ;
     RECT  59.357 32.496 59.573 35.88 ;
     RECT  59.177 63.984 59.641 66.552 ;
     RECT  58.993 67.536 59.641 70.344 ;
     RECT  58.817 41.568 59.651 42.6 ;
     RECT  59.465 52.56 59.681 54.456 ;
     RECT  58.709 57.84 59.713 59.256 ;
     RECT  58.349 78.144 59.749 78.504 ;
     RECT  58.997 6.912 59.753 7.944 ;
     RECT  59.357 74.88 59.789 75.96 ;
     RECT  59.677 1.152 59.795 1.176 ;
     RECT  59.105 37.056 59.807 39.48 ;
     RECT  58.853 48.96 59.821 51.24 ;
     RECT  59.749 78.144 59.843 78.696 ;
     RECT  59.173 3.264 59.845 4.488 ;
     RECT  59.321 18.432 59.845 18.456 ;
     RECT  59.141 19.488 59.845 21.624 ;
     RECT  59.807 37.056 59.845 39.912 ;
     RECT  59.429 46.608 59.857 47.16 ;
     RECT  59.321 14.352 59.861 17.448 ;
     RECT  59.843 78.144 59.861 78.6 ;
     RECT  59.845 18.432 59.891 21.624 ;
     RECT  59.357 28.656 59.893 30.744 ;
     RECT  59.789 74.88 59.893 75.864 ;
     RECT  59.389 43.632 59.897 45.576 ;
     RECT  59.845 3.264 59.933 4.68 ;
     RECT  59.573 33.312 59.933 35.88 ;
     RECT  59.897 43.872 59.933 45.576 ;
     RECT  59.821 48.48 59.933 51.24 ;
     RECT  59.845 37.056 59.965 40.488 ;
     RECT  59.651 41.568 59.965 42.36 ;
     RECT  59.249 72.432 59.965 72.744 ;
     RECT  59.965 71.616 60.077 72.744 ;
     RECT  59.753 6.96 60.113 7.944 ;
     RECT  59.933 44.496 60.113 45.576 ;
     RECT  59.893 74.832 60.209 75.864 ;
     RECT  60.209 74.736 60.229 75.864 ;
     RECT  59.141 22.608 60.253 25.56 ;
     RECT  59.357 26.64 60.253 27.624 ;
     RECT  59.173 55.92 60.253 56.088 ;
     RECT  59.713 57.072 60.253 59.256 ;
     RECT  59.357 61.104 60.253 61.176 ;
     RECT  59.213 62.304 60.253 62.856 ;
     RECT  59.933 3.264 60.257 4.248 ;
     RECT  59.641 63.984 60.257 70.344 ;
     RECT  60.073 77.04 60.277 77.064 ;
     RECT  60.253 55.92 60.293 59.736 ;
     RECT  60.293 56.544 60.353 59.736 ;
     RECT  60.253 61.104 60.353 62.856 ;
     RECT  60.277 77.04 60.365 77.304 ;
     RECT  59.891 18.912 60.373 21.624 ;
     RECT  60.253 22.608 60.373 27.624 ;
     RECT  60.353 56.544 60.373 62.856 ;
     RECT  59.681 52.704 60.401 54.456 ;
     RECT  60.373 56.544 60.419 63.528 ;
     RECT  60.257 64.704 60.421 70.344 ;
     RECT  59.321 13.104 60.433 13.176 ;
     RECT  59.861 14.352 60.433 15 ;
     RECT  60.419 56.544 60.437 61.176 ;
     RECT  59.861 78.336 60.437 78.6 ;
     RECT  59.857 46.56 60.469 47.16 ;
     RECT  59.933 48.48 60.469 50.664 ;
     RECT  58.669 9.072 60.505 11.544 ;
     RECT  60.421 64.704 60.509 70.632 ;
     RECT  60.077 71.616 60.509 72.6 ;
     RECT  60.437 78.432 60.515 78.6 ;
     RECT  59.965 37.056 60.541 42.36 ;
     RECT  60.509 65.76 60.541 70.632 ;
     RECT  60.509 71.616 60.541 72.456 ;
     RECT  60.113 44.496 60.689 45.24 ;
     RECT  60.541 36.864 60.709 42.36 ;
     RECT  60.373 18.912 60.721 27.624 ;
     RECT  59.893 28.656 60.721 30.888 ;
     RECT  60.229 74.064 60.757 75.864 ;
     RECT  60.365 77.04 60.757 77.064 ;
     RECT  60.565 1.776 60.761 1.8 ;
     RECT  60.541 65.76 60.797 72.456 ;
     RECT  60.401 53.04 60.833 54.456 ;
     RECT  59.605 32.16 60.901 32.184 ;
     RECT  60.257 3.84 60.937 4.248 ;
     RECT  59.069 5.904 60.937 5.928 ;
     RECT  60.757 74.064 60.937 77.064 ;
     RECT  59.933 33.312 60.949 35.736 ;
     RECT  60.937 5.808 60.973 5.928 ;
     RECT  60.113 6.96 60.973 7.512 ;
     RECT  60.721 18.912 61.009 30.888 ;
     RECT  60.469 46.56 61.009 50.664 ;
     RECT  60.973 51.936 61.009 51.96 ;
     RECT  60.901 31.92 61.045 32.184 ;
     RECT  60.949 33.312 61.045 35.784 ;
     RECT  60.689 44.496 61.045 44.856 ;
     RECT  60.709 36.864 61.225 42.744 ;
     RECT  60.833 53.28 61.244 54.456 ;
     RECT  60.419 62.496 61.261 63.528 ;
     RECT  60.437 56.544 61.297 59.736 ;
     RECT  61.261 62.496 61.297 63.624 ;
     RECT  60.509 64.704 61.297 64.728 ;
     RECT  60.937 3.84 61.333 4.44 ;
     RECT  60.973 5.808 61.34 7.512 ;
     RECT  60.505 9.072 61.34 12.12 ;
     RECT  61.297 56.496 61.369 59.736 ;
     RECT  61.333 2.88 61.388 4.44 ;
     RECT  61.34 5.808 61.388 12.12 ;
     RECT  61.388 2.88 61.441 12.12 ;
     RECT  60.433 13.104 61.441 15 ;
     RECT  60.937 73.824 61.525 77.064 ;
     RECT  60.515 78.432 61.525 78.456 ;
     RECT  59.861 16.32 61.549 17.448 ;
     RECT  61.009 18.816 61.549 30.888 ;
     RECT  61.369 56.16 61.549 59.736 ;
     RECT  60.437 60.816 61.549 61.176 ;
     RECT  61.009 46.56 61.573 51.96 ;
     RECT  61.549 56.16 61.585 61.176 ;
     RECT  61.585 56.16 61.657 61.464 ;
     RECT  61.045 31.92 61.669 35.784 ;
     RECT  61.225 36.864 61.669 43.32 ;
     RECT  61.244 53.28 61.669 54.984 ;
     RECT  61.657 56.16 61.669 61.512 ;
     RECT  61.525 73.824 61.669 78.456 ;
     RECT  60.797 66.048 61.765 72.456 ;
     RECT  61.669 73.824 61.765 78.648 ;
     RECT  61.441 2.88 61.808 15 ;
     RECT  61.549 16.32 61.808 30.888 ;
     RECT  61.669 31.92 61.808 43.32 ;
     RECT  61.045 44.448 61.808 44.856 ;
     RECT  61.573 46.176 61.808 51.96 ;
     RECT  61.669 53.28 61.808 61.512 ;
     RECT  61.297 62.496 61.808 64.728 ;
     RECT  61.765 66.048 61.808 78.648 ;
     RECT  61.808 2.148 61.912 79.932 ;
     RECT  61.912 2.148 62.104 79.662 ;
     RECT  62.104 26.832 62.165 31.512 ;
     RECT  62.104 45.024 62.201 49.608 ;
     RECT  62.104 78.432 62.201 78.456 ;
     RECT  62.104 72.816 62.237 74.664 ;
     RECT  62.104 19.008 62.243 25.752 ;
     RECT  62.237 74.304 62.243 74.664 ;
     RECT  62.104 6.24 62.245 11.496 ;
     RECT  62.243 19.008 62.309 25.656 ;
     RECT  62.104 67.296 62.332 71.64 ;
     RECT  62.149 1.776 62.381 1.8 ;
     RECT  62.245 6.336 62.476 11.496 ;
     RECT  62.104 75.648 62.524 77.064 ;
     RECT  62.104 15.984 62.525 17.64 ;
     RECT  62.104 53.28 62.525 56.904 ;
     RECT  62.525 53.28 62.561 56.616 ;
     RECT  62.525 15.984 62.633 16.632 ;
     RECT  62.524 76.224 62.669 77.064 ;
     RECT  62.476 6.336 62.705 7.896 ;
     RECT  62.104 3.696 62.741 4.488 ;
     RECT  62.309 19.344 62.777 25.656 ;
     RECT  62.165 26.88 62.849 31.512 ;
     RECT  62.669 76.224 62.956 76.632 ;
     RECT  62.881 1.152 62.965 1.176 ;
     RECT  62.104 39.264 63.011 43.704 ;
     RECT  62.201 45.024 63.011 49.08 ;
     RECT  62.104 50.592 63.065 51.24 ;
     RECT  62.104 58.128 63.101 59.256 ;
     RECT  62.243 74.4 63.137 74.664 ;
     RECT  62.104 65.952 63.164 66.312 ;
     RECT  62.332 67.296 63.164 70.344 ;
     RECT  62.104 61.152 63.205 64.92 ;
     RECT  63.164 65.952 63.205 70.344 ;
     RECT  62.237 72.816 63.205 73.032 ;
     RECT  62.104 13.008 63.241 15 ;
     RECT  63.157 77.712 63.244 77.736 ;
     RECT  63.205 60.96 63.251 70.344 ;
     RECT  63.101 58.512 63.253 59.256 ;
     RECT  63.251 60.96 63.253 66.312 ;
     RECT  63.011 39.264 63.281 43.32 ;
     RECT  63.253 58.512 63.299 66.312 ;
     RECT  63.065 51.12 63.313 51.24 ;
     RECT  62.104 52.224 63.313 52.248 ;
     RECT  63.251 67.392 63.313 70.344 ;
     RECT  62.741 3.696 63.317 4.392 ;
     RECT  63.299 62.16 63.353 66.312 ;
     RECT  63.281 41.184 63.389 43.32 ;
     RECT  63.137 74.592 63.389 74.664 ;
     RECT  62.332 71.616 63.421 71.64 ;
     RECT  63.205 72.624 63.421 73.032 ;
     RECT  63.421 71.616 63.425 73.032 ;
     RECT  62.476 9.024 63.497 11.496 ;
     RECT  62.956 76.224 63.497 76.248 ;
     RECT  63.011 45.552 63.529 49.08 ;
     RECT  63.353 62.88 63.569 66.312 ;
     RECT  63.493 78.624 63.58 78.648 ;
     RECT  63.529 45.552 63.605 50.04 ;
     RECT  63.299 58.512 63.677 60.984 ;
     RECT  63.497 9.072 63.709 11.496 ;
     RECT  63.241 12.48 63.709 15 ;
     RECT  62.849 29.04 63.709 31.512 ;
     RECT  62.104 32.496 63.709 37.992 ;
     RECT  62.561 53.376 63.853 56.616 ;
     RECT  63.773 1.776 63.857 1.8 ;
     RECT  63.389 41.712 63.857 43.32 ;
     RECT  63.857 41.712 63.965 43.272 ;
     RECT  63.853 53.376 63.965 57.48 ;
     RECT  63.605 46.32 64.001 50.04 ;
     RECT  63.425 71.616 64.001 72.936 ;
     RECT  62.849 26.88 64.021 27.336 ;
     RECT  63.709 29.04 64.021 37.992 ;
     RECT  63.709 9.072 64.037 15 ;
     RECT  62.777 19.344 64.163 21.144 ;
     RECT  62.777 22.272 64.177 25.656 ;
     RECT  64.021 26.88 64.177 37.992 ;
     RECT  64.105 44.928 64.177 45.048 ;
     RECT  62.525 17.616 64.217 17.64 ;
     RECT  63.965 53.376 64.217 54.888 ;
     RECT  63.317 4.368 64.249 4.392 ;
     RECT  64.001 47.424 64.249 50.04 ;
     RECT  63.313 51.12 64.249 52.248 ;
     RECT  64.217 53.376 64.249 54.696 ;
     RECT  63.965 56.256 64.261 57.48 ;
     RECT  63.677 58.512 64.261 58.728 ;
     RECT  64.261 56.256 64.307 58.728 ;
     RECT  64.307 56.256 64.348 58.68 ;
     RECT  64.177 22.272 64.357 37.992 ;
     RECT  63.389 74.592 64.361 74.616 ;
     RECT  64.163 20.832 64.397 21.144 ;
     RECT  64.348 56.256 64.397 57.48 ;
     RECT  63.313 67.392 64.403 70.536 ;
     RECT  64.357 22.224 64.433 38.232 ;
     RECT  62.633 16.32 64.465 16.632 ;
     RECT  64.163 19.344 64.465 19.848 ;
     RECT  63.677 59.856 64.465 60.984 ;
     RECT  64.433 22.224 64.469 35.832 ;
     RECT  64.001 46.32 64.477 46.44 ;
     RECT  64.393 3.024 64.493 3.048 ;
     RECT  64.249 4.368 64.493 5.16 ;
     RECT  64.465 18.864 64.501 19.848 ;
     RECT  64.403 68.688 64.505 70.536 ;
     RECT  62.705 6.336 64.537 7.752 ;
     RECT  64.177 44.832 64.537 45.048 ;
     RECT  64.465 59.856 64.573 61.032 ;
     RECT  63.569 62.88 64.573 62.904 ;
     RECT  63.569 63.984 64.573 66.312 ;
     RECT  64.493 3.024 64.577 5.16 ;
     RECT  64.433 37.056 64.609 38.232 ;
     RECT  64.001 72.144 64.609 72.936 ;
     RECT  63.281 39.264 64.613 39.912 ;
     RECT  64.477 46.32 64.613 46.344 ;
     RECT  64.249 47.424 64.649 54.696 ;
     RECT  64.573 62.88 64.685 66.312 ;
     RECT  64.037 11.952 64.721 15 ;
     RECT  64.649 47.424 64.721 51.24 ;
     RECT  64.609 37.056 64.753 38.28 ;
     RECT  64.469 26.352 64.793 35.832 ;
     RECT  64.685 66.288 64.793 66.312 ;
     RECT  64.573 59.856 64.865 61.512 ;
     RECT  64.721 47.616 64.901 51.24 ;
     RECT  64.577 4.368 64.937 5.16 ;
     RECT  64.501 18.768 64.969 19.848 ;
     RECT  64.505 68.688 64.973 69.48 ;
     RECT  63.817 77.28 64.981 77.304 ;
     RECT  64.649 52.224 65.009 54.696 ;
     RECT  64.865 59.856 65.009 59.88 ;
     RECT  64.937 4.512 65.029 5.16 ;
     RECT  64.537 6.336 65.029 8.04 ;
     RECT  65.029 4.512 65.041 8.04 ;
     RECT  64.037 9.072 65.041 10.92 ;
     RECT  65.041 4.512 65.075 10.92 ;
     RECT  64.613 39.792 65.077 39.912 ;
     RECT  64.537 44.736 65.077 45.048 ;
     RECT  64.969 18.432 65.081 19.848 ;
     RECT  64.469 22.224 65.081 25.032 ;
     RECT  64.901 47.616 65.081 49.992 ;
     RECT  65.075 5.712 65.113 10.92 ;
     RECT  64.465 16.32 65.113 17.352 ;
     RECT  64.865 60.96 65.117 61.512 ;
     RECT  63.965 42.096 65.149 43.272 ;
     RECT  64.397 56.256 65.153 57.144 ;
     RECT  64.403 67.392 65.185 67.416 ;
     RECT  65.113 5.712 65.189 11.544 ;
     RECT  65.081 18.432 65.219 19.512 ;
     RECT  64.397 20.832 65.221 20.952 ;
     RECT  65.081 47.616 65.225 49.8 ;
     RECT  65.149 41.616 65.257 43.272 ;
     RECT  64.505 70.512 65.293 70.536 ;
     RECT  64.753 37.056 65.297 38.808 ;
     RECT  65.257 41.616 65.297 43.32 ;
     RECT  64.973 68.736 65.315 69.48 ;
     RECT  64.537 76.08 65.329 76.104 ;
     RECT  64.981 77.28 65.329 78.12 ;
     RECT  65.297 37.104 65.333 38.808 ;
     RECT  65.077 44.688 65.437 45.048 ;
     RECT  65.153 56.592 65.437 57.144 ;
     RECT  64.348 58.656 65.437 58.68 ;
     RECT  65.315 68.736 65.441 69.192 ;
     RECT  65.297 43.152 65.477 43.32 ;
     RECT  65.009 52.464 65.477 54.696 ;
     RECT  65.365 1.776 65.513 1.8 ;
     RECT  65.293 70.512 65.513 70.872 ;
     RECT  65.221 20.688 65.545 20.952 ;
     RECT  65.329 76.08 65.545 78.168 ;
     RECT  65.477 43.296 65.557 43.32 ;
     RECT  65.437 44.592 65.557 45.048 ;
     RECT  65.113 16.032 65.585 17.352 ;
     RECT  65.441 68.88 65.585 69.192 ;
     RECT  65.557 43.296 65.603 45.048 ;
     RECT  65.081 22.224 65.621 24.504 ;
     RECT  65.077 39.792 65.621 40.344 ;
     RECT  64.609 72.144 65.621 73.8 ;
     RECT  65.621 22.512 65.644 24.504 ;
     RECT  65.621 39.888 65.657 40.344 ;
     RECT  65.545 20.688 65.699 21.048 ;
     RECT  65.699 20.688 65.729 20.952 ;
     RECT  65.297 41.616 65.729 41.88 ;
     RECT  65.729 20.688 65.74 20.856 ;
     RECT  65.585 16.032 65.761 16.968 ;
     RECT  65.761 15.984 65.765 16.968 ;
     RECT  65.477 53.376 65.797 54.696 ;
     RECT  65.117 61.488 65.837 61.512 ;
     RECT  65.513 70.512 65.905 70.536 ;
     RECT  64.685 62.88 65.941 65.064 ;
     RECT  64.721 12.864 65.977 15 ;
     RECT  65.905 70.416 66.017 70.536 ;
     RECT  65.729 41.856 66.035 41.88 ;
     RECT  64.577 3.024 66.085 3.048 ;
     RECT  65.941 62.592 66.085 65.064 ;
     RECT  65.185 66.816 66.089 67.416 ;
     RECT  65.225 48.432 66.121 49.8 ;
     RECT  64.901 50.976 66.121 51.24 ;
     RECT  65.797 53.376 66.133 55.272 ;
     RECT  65.437 56.592 66.157 58.68 ;
     RECT  65.545 75.216 66.157 78.168 ;
     RECT  65.603 43.536 66.161 45.048 ;
     RECT  66.085 62.16 66.169 65.4 ;
     RECT  65.189 6.576 66.229 11.544 ;
     RECT  65.977 12.576 66.229 15 ;
     RECT  66.161 44.928 66.265 45.048 ;
     RECT  66.085 2.88 66.301 3.048 ;
     RECT  65.075 4.512 66.301 4.536 ;
     RECT  66.301 2.88 66.401 4.536 ;
     RECT  66.133 53.376 66.469 55.416 ;
     RECT  66.157 56.592 66.469 59.496 ;
     RECT  66.229 6.576 66.476 15 ;
     RECT  65.765 15.984 66.476 16.824 ;
     RECT  64.793 29.088 66.589 35.832 ;
     RECT  65.333 37.104 66.589 38.232 ;
     RECT  65.585 69.168 66.62 69.192 ;
     RECT  66.017 70.416 66.62 70.44 ;
     RECT  65.644 24.192 66.661 24.504 ;
     RECT  65.657 40.32 66.661 40.344 ;
     RECT  66.62 69.168 66.661 70.44 ;
     RECT  65.74 20.688 66.725 20.712 ;
     RECT  66.476 6.576 66.733 16.824 ;
     RECT  66.469 53.376 66.733 59.496 ;
     RECT  66.193 60.672 66.733 60.696 ;
     RECT  65.621 72.144 66.733 72.84 ;
     RECT  65.219 18.816 66.757 19.512 ;
     RECT  66.725 20.688 66.757 21.144 ;
     RECT  66.661 23.952 66.769 24.504 ;
     RECT  66.157 74.64 66.769 78.168 ;
     RECT  66.265 44.928 66.812 45.144 ;
     RECT  66.733 53.376 66.913 60.696 ;
     RECT  66.401 2.256 66.949 4.536 ;
     RECT  66.589 29.088 66.985 38.232 ;
     RECT  66.757 18.816 67.013 21.144 ;
     RECT  66.949 1.776 67.033 4.536 ;
     RECT  66.661 40.272 67.093 40.344 ;
     RECT  66.121 48.432 67.129 51.24 ;
     RECT  66.913 52.224 67.129 60.696 ;
     RECT  67.033 2.148 67.208 4.536 ;
     RECT  66.733 6.384 67.208 16.824 ;
     RECT  67.013 17.856 67.208 21.144 ;
     RECT  65.644 22.512 67.208 22.776 ;
     RECT  66.769 23.952 67.208 25.224 ;
     RECT  64.793 26.352 67.208 27.96 ;
     RECT  66.985 29.088 67.208 38.808 ;
     RECT  67.093 40.272 67.208 40.44 ;
     RECT  67.093 41.664 67.208 41.688 ;
     RECT  66.812 44.928 67.208 45.672 ;
     RECT  65.869 46.8 67.208 46.824 ;
     RECT  67.129 48.432 67.208 60.696 ;
     RECT  66.169 62.16 67.208 65.208 ;
     RECT  66.089 66.816 67.208 66.888 ;
     RECT  66.661 68.928 67.208 70.44 ;
     RECT  66.733 71.712 67.208 72.84 ;
     RECT  66.769 74.304 67.208 78.168 ;
     RECT  67.208 2.148 67.312 79.932 ;
     RECT  67.312 2.418 67.504 79.662 ;
     RECT  67.504 6.288 67.529 20.184 ;
     RECT  67.529 6.288 67.565 10.632 ;
     RECT  67.504 70.752 67.565 76.488 ;
     RECT  67.504 45.936 67.619 59.784 ;
     RECT  67.619 51.12 67.745 59.784 ;
     RECT  67.453 1.152 67.763 1.176 ;
     RECT  67.504 21.168 67.763 25.08 ;
     RECT  67.745 51.12 67.781 56.568 ;
     RECT  67.504 61.584 67.853 67.8 ;
     RECT  67.619 45.936 67.889 49.8 ;
     RECT  67.565 70.752 67.961 74.664 ;
     RECT  67.745 57.552 68.033 59.784 ;
     RECT  67.853 63.12 68.033 67.8 ;
     RECT  67.529 11.664 68.099 20.184 ;
     RECT  67.781 51.12 68.105 55.8 ;
     RECT  68.099 11.664 68.14 19.32 ;
     RECT  67.763 21.168 68.14 22.824 ;
     RECT  68.14 22.56 68.141 22.824 ;
     RECT  67.504 26.304 68.141 40.44 ;
     RECT  67.961 70.848 68.141 74.664 ;
     RECT  68.14 19.296 68.177 19.32 ;
     RECT  67.889 45.936 68.243 48.984 ;
     RECT  67.504 41.904 68.321 43.704 ;
     RECT  68.141 71.712 68.321 74.664 ;
     RECT  67.565 76.08 68.321 76.488 ;
     RECT  68.321 41.904 68.332 41.928 ;
     RECT  67.763 23.952 68.357 25.08 ;
     RECT  68.141 36.48 68.429 40.44 ;
     RECT  68.357 24.096 68.465 25.08 ;
     RECT  67.504 2.592 68.485 3.672 ;
     RECT  68.243 46.224 68.501 46.248 ;
     RECT  68.105 54.336 68.501 55.8 ;
     RECT  68.033 63.12 68.537 64.632 ;
     RECT  68.485 1.776 68.573 3.672 ;
     RECT  67.504 77.568 68.573 77.592 ;
     RECT  67.504 4.848 68.581 5.016 ;
     RECT  67.565 6.288 68.581 10.44 ;
     RECT  68.573 1.776 68.609 3.432 ;
     RECT  68.141 26.304 68.609 35.496 ;
     RECT  68.429 38.976 68.609 40.44 ;
     RECT  68.321 71.808 68.609 74.664 ;
     RECT  68.14 11.664 68.627 18.168 ;
     RECT  68.581 4.848 68.641 10.44 ;
     RECT  68.627 11.664 68.641 16.344 ;
     RECT  68.321 43.68 68.645 43.704 ;
     RECT  68.588 45.168 68.675 45.192 ;
     RECT  68.321 76.08 68.681 76.104 ;
     RECT  67.853 61.584 68.713 61.608 ;
     RECT  68.033 65.904 68.716 67.8 ;
     RECT  68.609 26.304 68.753 34.92 ;
     RECT  68.641 4.848 68.761 16.344 ;
     RECT  68.753 26.304 68.764 33.384 ;
     RECT  68.465 24.24 68.821 25.08 ;
     RECT  68.764 26.304 68.821 27.624 ;
     RECT  68.033 57.552 68.861 59.736 ;
     RECT  68.243 47.328 68.867 48.984 ;
     RECT  68.713 60.816 68.876 61.608 ;
     RECT  68.716 66.336 68.893 67.8 ;
     RECT  67.504 68.88 68.893 69.048 ;
     RECT  68.761 4.848 68.897 15 ;
     RECT  68.867 48.768 68.897 48.984 ;
     RECT  68.876 60.816 68.917 62.136 ;
     RECT  68.14 21.168 68.929 21.192 ;
     RECT  68.609 2.592 68.933 3.432 ;
     RECT  68.867 47.328 68.933 47.736 ;
     RECT  68.609 71.808 68.933 73.896 ;
     RECT  68.105 51.12 68.965 53.016 ;
     RECT  68.501 55.488 68.965 55.8 ;
     RECT  68.753 34.416 68.969 34.92 ;
     RECT  68.609 39.024 69.037 40.44 ;
     RECT  68.861 57.744 69.077 59.736 ;
     RECT  68.917 60.816 69.149 62.568 ;
     RECT  68.141 22.704 69.293 22.824 ;
     RECT  68.965 50.304 69.293 53.016 ;
     RECT  68.627 17.76 69.433 18.168 ;
     RECT  69.149 62.544 69.437 62.568 ;
     RECT  68.821 24.24 69.443 27.624 ;
     RECT  68.933 47.328 69.469 47.592 ;
     RECT  68.933 71.808 69.505 72.6 ;
     RECT  68.933 2.88 69.509 3.432 ;
     RECT  68.897 8.448 69.509 15 ;
     RECT  69.443 24.24 69.577 24.936 ;
     RECT  68.764 28.8 69.581 33.384 ;
     RECT  68.965 55.488 69.581 56.76 ;
     RECT  69.293 50.736 69.617 53.016 ;
     RECT  68.761 16.32 69.649 16.344 ;
     RECT  69.433 17.76 69.649 18.6 ;
     RECT  68.969 34.416 69.653 34.824 ;
     RECT  69.505 71.232 69.683 72.6 ;
     RECT  68.537 64.128 69.685 64.632 ;
     RECT  68.893 66.336 69.689 69.048 ;
     RECT  68.933 73.872 69.689 73.896 ;
     RECT  69.541 45.648 69.721 45.672 ;
     RECT  69.469 46.752 69.721 47.592 ;
     RECT  69.683 72.576 69.725 72.6 ;
     RECT  69.509 3.024 69.757 3.432 ;
     RECT  68.897 4.848 69.757 7.368 ;
     RECT  69.581 33.072 69.757 33.384 ;
     RECT  69.653 34.416 69.757 34.488 ;
     RECT  69.689 68.88 69.757 69.048 ;
     RECT  68.429 36.576 69.829 37.848 ;
     RECT  69.037 39.024 69.829 41.256 ;
     RECT  69.757 3.024 69.833 7.368 ;
     RECT  69.149 60.816 69.869 60.84 ;
     RECT  69.833 3.024 69.875 3.336 ;
     RECT  69.649 16.32 69.875 18.6 ;
     RECT  69.685 64.128 69.901 64.92 ;
     RECT  69.829 36.576 69.973 41.256 ;
     RECT  69.901 62.784 70.045 64.92 ;
     RECT  69.689 66.336 70.045 67.8 ;
     RECT  69.833 4.368 70.085 7.368 ;
     RECT  69.937 1.776 70.115 1.8 ;
     RECT  70.081 35.52 70.117 35.544 ;
     RECT  69.973 36.576 70.117 41.736 ;
     RECT  69.757 68.88 70.117 69.192 ;
     RECT  70.117 68.88 70.121 69.768 ;
     RECT  70.085 4.368 70.157 5.88 ;
     RECT  69.509 8.448 70.157 10.872 ;
     RECT  68.929 20.688 70.157 21.192 ;
     RECT  70.117 35.52 70.157 41.736 ;
     RECT  70.045 62.784 70.157 67.8 ;
     RECT  69.683 71.232 70.157 71.256 ;
     RECT  69.577 23.712 70.193 24.936 ;
     RECT  69.581 55.824 70.225 56.76 ;
     RECT  69.077 57.84 70.225 59.736 ;
     RECT  69.721 45.648 70.265 47.592 ;
     RECT  70.153 61.008 70.265 61.032 ;
     RECT  69.443 25.968 70.297 27.624 ;
     RECT  70.157 10.032 70.3 10.872 ;
     RECT  69.875 3.024 70.307 3.048 ;
     RECT  70.157 37.68 70.333 41.736 ;
     RECT  70.157 20.688 70.344 20.712 ;
     RECT  70.297 25.968 70.373 27.72 ;
     RECT  70.225 55.824 70.441 59.736 ;
     RECT  69.937 22.56 70.477 22.584 ;
     RECT  70.193 23.712 70.477 24.888 ;
     RECT  70.333 37.68 70.549 41.784 ;
     RECT  68.897 48.912 70.549 48.984 ;
     RECT  68.501 54.336 70.553 54.36 ;
     RECT  70.477 22.56 70.585 24.888 ;
     RECT  70.3 10.704 70.589 10.872 ;
     RECT  69.617 50.784 70.621 53.016 ;
     RECT  70.441 55.824 70.625 59.88 ;
     RECT  70.265 45.648 70.657 46.968 ;
     RECT  69.875 17.76 70.661 18.6 ;
     RECT  70.549 37.68 70.661 42.024 ;
     RECT  69.509 12 70.691 15 ;
     RECT  70.691 14.208 70.697 15 ;
     RECT  70.373 26.064 70.697 27.72 ;
     RECT  70.157 62.784 70.697 65.592 ;
     RECT  70.661 17.76 70.733 18.072 ;
     RECT  70.344 19.728 70.733 20.712 ;
     RECT  70.585 22.176 70.733 24.888 ;
     RECT  69.581 28.8 70.733 32.04 ;
     RECT  70.549 48.912 70.733 49.8 ;
     RECT  70.697 26.784 70.765 27.72 ;
     RECT  70.733 28.8 70.765 29.112 ;
     RECT  70.661 37.824 70.805 42.024 ;
     RECT  70.157 67.056 70.805 67.8 ;
     RECT  70.721 71.616 70.805 71.64 ;
     RECT  70.625 59.424 70.835 59.88 ;
     RECT  70.805 67.44 70.841 67.8 ;
     RECT  70.157 35.52 70.877 36.456 ;
     RECT  70.697 64.416 70.877 65.592 ;
     RECT  70.697 14.208 70.931 14.376 ;
     RECT  70.733 30.096 70.945 32.04 ;
     RECT  69.757 33.072 70.945 34.488 ;
     RECT  70.805 38.784 70.949 39.048 ;
     RECT  70.621 50.784 70.957 54.12 ;
     RECT  70.949 38.784 70.985 38.952 ;
     RECT  70.931 14.208 71.021 14.232 ;
     RECT  70.733 22.176 71.021 22.776 ;
     RECT  70.835 59.424 71.027 59.496 ;
     RECT  70.805 40.368 71.036 42.024 ;
     RECT  70.765 43.872 71.036 43.896 ;
     RECT  70.985 38.928 71.057 38.952 ;
     RECT  70.625 55.824 71.068 58.44 ;
     RECT  70.121 69.168 71.089 69.768 ;
     RECT  71.036 40.368 71.123 43.896 ;
     RECT  69.875 16.32 71.125 16.776 ;
     RECT  70.697 62.784 71.161 63.288 ;
     RECT  70.085 6.912 71.197 7.368 ;
     RECT  70.157 8.448 71.197 9.048 ;
     RECT  70.945 30.096 71.197 34.488 ;
     RECT  70.877 35.52 71.197 35.976 ;
     RECT  70.657 45.024 71.237 46.968 ;
     RECT  70.733 49.632 71.269 49.8 ;
     RECT  70.957 50.784 71.269 52.632 ;
     RECT  71.068 55.824 71.305 57.912 ;
     RECT  70.733 23.904 71.309 24.888 ;
     RECT  71.305 55.296 71.345 57.912 ;
     RECT  71.197 30.096 71.363 35.976 ;
     RECT  71.345 56.352 71.363 57.912 ;
     RECT  70.157 4.368 71.377 5.688 ;
     RECT  71.197 6.912 71.377 9.048 ;
     RECT  71.363 30.096 71.404 35.832 ;
     RECT  71.125 16.32 71.449 17.64 ;
     RECT  70.549 61.584 71.521 61.608 ;
     RECT  71.161 62.688 71.521 63.288 ;
     RECT  71.089 69.168 71.521 69.864 ;
     RECT  71.237 45.024 71.561 45.72 ;
     RECT  70.837 3.264 71.612 3.288 ;
     RECT  71.377 4.368 71.612 9.048 ;
     RECT  71.521 68.928 71.633 69.864 ;
     RECT  71.612 3.264 71.637 9.048 ;
     RECT  71.521 61.584 71.665 63.288 ;
     RECT  71.637 2.64 71.701 9.048 ;
     RECT  71.237 46.896 71.737 46.968 ;
     RECT  71.413 48.48 71.737 48.504 ;
     RECT  71.449 15.36 71.773 17.64 ;
     RECT  71.665 61.44 71.773 63.288 ;
     RECT  70.877 64.416 71.773 64.44 ;
     RECT  71.123 40.368 71.804 42.744 ;
     RECT  71.701 1.776 71.813 9.048 ;
     RECT  70.691 12 71.845 13.176 ;
     RECT  70.733 19.728 71.845 19.752 ;
     RECT  71.309 24.144 71.845 24.888 ;
     RECT  71.021 22.752 71.881 22.776 ;
     RECT  71.773 15.36 71.893 18.072 ;
     RECT  71.269 49.632 71.953 52.632 ;
     RECT  70.957 53.76 71.953 54.12 ;
     RECT  70.589 10.704 72.025 10.728 ;
     RECT  71.893 15.36 72.025 18.12 ;
     RECT  71.773 61.44 72.044 64.44 ;
     RECT  72.044 60.672 72.061 64.44 ;
     RECT  70.877 65.568 72.061 65.592 ;
     RECT  71.123 43.872 72.097 43.896 ;
     RECT  71.561 45.024 72.097 45.672 ;
     RECT  72.061 60.672 72.097 65.592 ;
     RECT  72.097 43.872 72.14 45.672 ;
     RECT  71.027 59.472 72.205 59.496 ;
     RECT  71.881 22.752 72.236 22.824 ;
     RECT  71.845 19.632 72.277 19.752 ;
     RECT  72.236 22.08 72.313 22.824 ;
     RECT  72.313 22.032 72.385 22.824 ;
     RECT  71.845 24.144 72.385 25.224 ;
     RECT  71.404 35.28 72.385 35.832 ;
     RECT  71.363 56.976 72.421 57.912 ;
     RECT  72.205 58.944 72.421 59.496 ;
     RECT  71.953 49.632 72.457 54.12 ;
     RECT  71.404 30.096 72.469 33.912 ;
     RECT  72.385 34.896 72.469 35.832 ;
     RECT  72.469 30.096 72.493 35.832 ;
     RECT  71.881 1.152 72.515 1.176 ;
     RECT  71.813 2.148 72.608 9.048 ;
     RECT  72.025 10.704 72.608 10.92 ;
     RECT  71.845 12 72.608 13.656 ;
     RECT  72.025 14.736 72.608 18.12 ;
     RECT  72.277 19.632 72.608 20.04 ;
     RECT  72.385 22.032 72.608 25.224 ;
     RECT  70.765 26.784 72.608 29.112 ;
     RECT  72.493 30.096 72.608 36.12 ;
     RECT  72.025 37.584 72.608 37.608 ;
     RECT  72.349 39.072 72.608 39.096 ;
     RECT  71.804 40.224 72.608 42.744 ;
     RECT  72.14 43.824 72.608 45.672 ;
     RECT  71.737 46.896 72.608 48.504 ;
     RECT  72.457 49.584 72.608 54.12 ;
     RECT  71.345 55.296 72.608 55.32 ;
     RECT  72.421 56.976 72.608 59.496 ;
     RECT  72.097 60.672 72.608 65.976 ;
     RECT  70.841 67.44 72.608 67.704 ;
     RECT  71.633 69.84 72.608 69.864 ;
     RECT  72.608 2.148 72.712 79.932 ;
     RECT  72.712 2.148 72.904 79.662 ;
     RECT  72.904 57.312 72.965 58.248 ;
     RECT  72.904 4.224 73.037 9.24 ;
     RECT  72.904 20.976 73.037 27.72 ;
     RECT  72.904 30.096 73.037 36.552 ;
     RECT  72.904 37.584 73.037 37.896 ;
     RECT  72.904 10.848 73.073 19.656 ;
     RECT  73.037 21.168 73.073 27.72 ;
     RECT  72.904 39.072 73.073 39.096 ;
     RECT  73.073 14.4 73.109 15.576 ;
     RECT  73.073 16.656 73.109 19.656 ;
     RECT  72.904 56.256 73.109 56.28 ;
     RECT  73.109 17.664 73.181 19.656 ;
     RECT  73.037 33.072 73.181 36.552 ;
     RECT  73.073 21.744 73.217 27.72 ;
     RECT  72.904 65.904 73.217 66.216 ;
     RECT  72.904 2.88 73.253 2.904 ;
     RECT  73.205 1.776 73.289 1.8 ;
     RECT  72.904 59.568 73.289 59.592 ;
     RECT  72.904 28.992 73.325 29.016 ;
     RECT  72.904 44.736 73.325 44.76 ;
     RECT  73.037 4.224 73.361 7.224 ;
     RECT  73.181 33.072 73.361 33.096 ;
     RECT  73.037 37.632 73.361 37.896 ;
     RECT  72.904 45.744 73.427 48.504 ;
     RECT  73.217 22.08 73.505 27.72 ;
     RECT  73.037 30.096 73.541 32.04 ;
     RECT  72.904 68.928 73.541 68.952 ;
     RECT  73.181 34.368 73.577 35.304 ;
     RECT  73.427 45.744 73.577 45.864 ;
     RECT  73.217 65.952 73.577 66.216 ;
     RECT  73.505 22.08 73.685 27.096 ;
     RECT  73.109 15.216 73.721 15.576 ;
     RECT  72.904 41.184 73.721 43.176 ;
     RECT  72.904 61.44 73.721 61.464 ;
     RECT  73.721 42.576 73.756 43.176 ;
     RECT  73.577 66.192 73.793 66.216 ;
     RECT  73.361 37.632 73.901 37.656 ;
     RECT  72.965 57.312 73.937 57.912 ;
     RECT  73.361 4.848 73.948 7.224 ;
     RECT  73.868 39.984 73.955 40.008 ;
     RECT  73.937 57.888 73.969 57.912 ;
     RECT  73.181 17.664 73.973 18.84 ;
     RECT  72.904 49.584 74.009 53.304 ;
     RECT  73.948 5.184 74.041 7.224 ;
     RECT  73.037 8.208 74.041 9.24 ;
     RECT  73.721 15.552 74.045 15.576 ;
     RECT  73.969 57.888 74.045 58.152 ;
     RECT  73.541 30.096 74.085 31.464 ;
     RECT  74.041 5.184 74.113 9.24 ;
     RECT  74.045 58.128 74.113 58.152 ;
     RECT  74.009 49.584 74.117 53.016 ;
     RECT  73.789 0.096 74.147 0.12 ;
     RECT  73.577 34.608 74.149 35.304 ;
     RECT  73.685 24.144 74.153 27.096 ;
     RECT  74.113 58.128 74.153 59.304 ;
     RECT  74.069 60.72 74.153 60.744 ;
     RECT  74.113 5.184 74.189 9.288 ;
     RECT  73.756 42.576 74.189 42.6 ;
     RECT  74.149 34.608 74.197 35.64 ;
     RECT  73.073 10.848 74.225 13.08 ;
     RECT  74.117 49.728 74.225 53.016 ;
     RECT  73.685 22.08 74.257 22.92 ;
     RECT  74.225 10.848 74.261 11.88 ;
     RECT  73.721 41.184 74.291 41.4 ;
     RECT  74.153 58.656 74.291 59.304 ;
     RECT  74.291 59.28 74.305 59.304 ;
     RECT  74.225 12.864 74.365 13.08 ;
     RECT  74.3 39.072 74.387 39.096 ;
     RECT  74.189 8.208 74.401 9.288 ;
     RECT  74.261 10.848 74.401 10.92 ;
     RECT  74.365 12.864 74.437 13.656 ;
     RECT  73.109 16.656 74.437 16.68 ;
     RECT  74.189 5.184 74.441 6.84 ;
     RECT  74.085 30 74.473 31.464 ;
     RECT  74.473 29.664 74.509 31.464 ;
     RECT  74.509 29.232 74.533 31.464 ;
     RECT  74.401 8.208 74.549 10.92 ;
     RECT  74.437 12.864 74.549 14.232 ;
     RECT  73.577 45.84 74.581 45.864 ;
     RECT  74.441 6.816 74.585 6.84 ;
     RECT  73.973 18.816 74.585 18.84 ;
     RECT  74.153 25.344 74.617 27.096 ;
     RECT  74.077 28.176 74.617 28.2 ;
     RECT  74.533 29.232 74.617 33.096 ;
     RECT  74.197 34.608 74.617 35.688 ;
     RECT  74.617 25.344 74.645 28.2 ;
     RECT  74.617 29.232 74.645 35.688 ;
     RECT  74.291 41.184 74.653 41.208 ;
     RECT  74.581 45.84 74.653 46.344 ;
     RECT  74.653 40.56 74.657 41.208 ;
     RECT  74.225 50.064 74.675 53.016 ;
     RECT  73.973 17.664 74.693 17.688 ;
     RECT  74.645 25.344 74.723 35.688 ;
     RECT  74.723 30.096 74.729 35.688 ;
     RECT  74.653 45.84 74.761 46.392 ;
     RECT  73.427 47.424 74.761 48.504 ;
     RECT  74.549 8.208 74.765 10.584 ;
     RECT  74.761 45.84 74.765 48.504 ;
     RECT  74.437 15.984 74.869 16.68 ;
     RECT  74.617 19.296 74.869 19.32 ;
     RECT  74.723 25.344 74.873 28.824 ;
     RECT  74.675 50.064 74.909 51.624 ;
     RECT  74.797 1.776 74.915 1.8 ;
     RECT  74.441 5.184 74.945 5.832 ;
     RECT  74.869 19.296 74.945 20.184 ;
     RECT  74.257 21.792 75.013 22.92 ;
     RECT  74.675 52.704 75.017 53.016 ;
     RECT  74.945 19.632 75.049 20.184 ;
     RECT  74.869 15.984 75.089 17.64 ;
     RECT  74.765 46.32 75.089 48.504 ;
     RECT  74.657 40.56 75.109 40.584 ;
     RECT  74.729 31.104 75.161 35.688 ;
     RECT  75.089 15.984 75.205 16.008 ;
     RECT  75.161 31.152 75.233 35.688 ;
     RECT  75.205 15.696 75.251 16.008 ;
     RECT  74.873 25.344 75.269 28.2 ;
     RECT  75.089 17.616 75.341 17.64 ;
     RECT  75.269 25.344 75.341 28.056 ;
     RECT  75.233 31.68 75.341 35.688 ;
     RECT  75.26 42.192 75.347 42.216 ;
     RECT  74.977 4.56 75.409 4.584 ;
     RECT  74.153 24.144 75.409 24.168 ;
     RECT  75.341 25.344 75.409 27.096 ;
     RECT  75.013 21.648 75.481 22.92 ;
     RECT  74.909 50.064 75.485 51.144 ;
     RECT  75.481 21.408 75.517 22.92 ;
     RECT  75.409 24.144 75.557 27.096 ;
     RECT  75.109 39.984 75.589 40.584 ;
     RECT  75.251 15.696 75.637 15.72 ;
     RECT  74.689 37.728 75.637 38.808 ;
     RECT  75.589 39.936 75.637 40.584 ;
     RECT  74.945 5.568 75.665 5.832 ;
     RECT  75.637 37.728 75.665 40.584 ;
     RECT  74.549 13.008 75.701 13.656 ;
     RECT  75.625 1.152 75.731 1.176 ;
     RECT  75.517 21.408 75.737 22.968 ;
     RECT  75.557 25.104 75.737 27.096 ;
     RECT  75.637 15.648 75.779 15.72 ;
     RECT  75.049 19.632 75.781 20.328 ;
     RECT  75.737 21.408 75.781 22.92 ;
     RECT  75.409 3.696 75.827 4.584 ;
     RECT  75.781 19.632 75.827 22.92 ;
     RECT  75.701 13.008 75.829 13.128 ;
     RECT  75.485 50.064 75.829 50.664 ;
     RECT  75.829 12.528 75.841 13.128 ;
     RECT  75.827 4.56 75.845 4.584 ;
     RECT  74.765 8.304 75.845 10.584 ;
     RECT  75.737 25.104 75.845 26.808 ;
     RECT  75.845 8.304 75.877 8.328 ;
     RECT  75.845 9.648 75.881 10.584 ;
     RECT  75.481 45.12 75.913 45.144 ;
     RECT  75.829 50.016 75.917 50.664 ;
     RECT  74.729 30.096 75.925 30.12 ;
     RECT  75.665 38.064 75.949 40.584 ;
     RECT  75.827 20.688 75.989 22.92 ;
     RECT  75.017 52.944 75.989 53.016 ;
     RECT  75.925 29.328 76.012 30.12 ;
     RECT  75.877 7.344 76.025 8.328 ;
     RECT  75.845 25.2 76.025 26.808 ;
     RECT  75.877 17.712 76.061 17.736 ;
     RECT  75.989 52.944 76.067 52.968 ;
     RECT  75.949 38.064 76.108 41.4 ;
     RECT  75.089 48.48 76.133 48.504 ;
     RECT  75.341 34.608 76.169 35.688 ;
     RECT  76.025 25.344 76.205 26.808 ;
     RECT  75.913 45.12 76.237 45.336 ;
     RECT  75.089 46.32 76.237 47.448 ;
     RECT  75.341 31.68 76.241 33.096 ;
     RECT  76.025 7.344 76.345 7.464 ;
     RECT  76.237 45.12 76.357 47.448 ;
     RECT  76.345 7.296 76.403 7.464 ;
     RECT  76.108 38.064 76.403 40.488 ;
     RECT  75.881 9.744 76.421 10.584 ;
     RECT  76.169 34.608 76.421 35.64 ;
     RECT  76.403 38.064 76.421 39.96 ;
     RECT  76.357 44.784 76.421 47.448 ;
     RECT  76.421 38.64 76.493 39.96 ;
     RECT  76.381 1.776 76.499 1.8 ;
     RECT  76.241 31.68 76.601 32.232 ;
     RECT  76.421 34.608 76.601 35.064 ;
     RECT  75.665 5.808 76.645 5.832 ;
     RECT  76.601 32.208 76.709 32.232 ;
     RECT  76.601 34.656 76.709 35.064 ;
     RECT  76.645 5.808 76.745 6.264 ;
     RECT  76.403 7.296 76.745 7.416 ;
     RECT  75.989 22.08 76.745 22.92 ;
     RECT  76.421 44.784 76.781 46.728 ;
     RECT  76.781 44.784 76.853 46.344 ;
     RECT  76.493 39.936 76.889 39.96 ;
     RECT  76.205 26.208 76.921 26.808 ;
     RECT  76.012 30.096 76.921 30.12 ;
     RECT  76.853 44.784 76.925 46.296 ;
     RECT  76.745 22.08 76.931 22.488 ;
     RECT  75.827 19.632 76.933 19.656 ;
     RECT  76.421 9.744 76.961 9.816 ;
     RECT  76.525 17.088 77.029 17.64 ;
     RECT  75.917 50.544 77.029 50.664 ;
     RECT  75.841 11.904 77.033 13.128 ;
     RECT  76.921 26.208 77.101 26.856 ;
     RECT  76.633 14.832 77.132 14.952 ;
     RECT  77.029 16.512 77.132 17.64 ;
     RECT  75.989 20.688 77.173 20.76 ;
     RECT  77.029 50.544 77.317 51.432 ;
     RECT  76.933 52.416 77.317 52.44 ;
     RECT  76.933 19.2 77.461 19.656 ;
     RECT  77.173 20.688 77.461 21 ;
     RECT  77.101 26.208 77.461 26.904 ;
     RECT  77.461 25.728 77.489 26.904 ;
     RECT  77.029 27.888 77.489 27.912 ;
     RECT  77.132 14.832 77.497 17.64 ;
     RECT  76.777 49.248 77.497 49.272 ;
     RECT  76.237 37.056 77.509 37.08 ;
     RECT  76.493 38.64 77.509 38.808 ;
     RECT  77.461 19.2 77.569 21 ;
     RECT  76.961 9.792 77.605 9.816 ;
     RECT  76.777 10.848 77.605 10.872 ;
     RECT  77.497 49.248 77.605 49.464 ;
     RECT  77.516 28.944 77.677 28.968 ;
     RECT  76.921 30.096 77.677 30.216 ;
     RECT  76.709 34.656 77.677 34.68 ;
     RECT  77.509 37.056 77.677 38.808 ;
     RECT  76.931 22.464 77.749 22.488 ;
     RECT  77.461 23.664 77.749 23.688 ;
     RECT  76.745 6.24 77.965 6.264 ;
     RECT  77.509 7.584 77.965 7.608 ;
     RECT  77.497 14.832 77.965 18.168 ;
     RECT  77.965 6.24 78.008 7.608 ;
     RECT  77.605 9.792 78.008 10.872 ;
     RECT  77.033 12.528 78.008 13.128 ;
     RECT  77.965 14.832 78.008 18.216 ;
     RECT  77.569 19.2 78.008 21.096 ;
     RECT  77.749 22.464 78.008 23.688 ;
     RECT  77.489 25.728 78.008 27.912 ;
     RECT  77.677 28.944 78.008 30.216 ;
     RECT  77.317 32.496 78.008 32.808 ;
     RECT  77.677 34.656 78.008 35.448 ;
     RECT  77.677 36.816 78.008 39.624 ;
     RECT  76.705 42.576 78.008 42.6 ;
     RECT  76.925 44.88 78.008 46.296 ;
     RECT  77.641 47.712 78.008 47.736 ;
     RECT  77.605 48.912 78.008 49.464 ;
     RECT  77.317 50.544 78.008 52.44 ;
     RECT  77.245 0.096 78.083 0.12 ;
     RECT  78.008 2.148 78.112 79.932 ;
     RECT  78.112 2.418 78.304 79.662 ;
     RECT  78.304 15.216 78.365 15.768 ;
     RECT  78.304 18.192 78.365 18.216 ;
     RECT  78.304 45.696 78.365 46.296 ;
     RECT  78.304 12.528 78.401 12.552 ;
     RECT  78.304 47.712 78.401 48.264 ;
     RECT  78.304 43.728 78.419 43.8 ;
     RECT  78.304 42.576 78.437 42.6 ;
     RECT  78.401 47.712 78.437 47.88 ;
     RECT  78.304 3.696 78.508 3.72 ;
     RECT  78.304 23.856 78.545 24.504 ;
     RECT  78.304 20.4 78.581 20.424 ;
     RECT  78.304 10.272 78.611 10.296 ;
     RECT  78.545 23.856 78.617 23.88 ;
     RECT  78.304 9.12 78.652 9.144 ;
     RECT  78.365 45.696 78.653 45.768 ;
     RECT  78.419 43.728 78.659 43.752 ;
     RECT  78.304 50.016 78.659 50.04 ;
     RECT  78.304 51.744 78.689 51.768 ;
     RECT  78.304 28.272 78.733 29.208 ;
     RECT  78.733 28.272 78.748 28.296 ;
     RECT  78.304 34.656 78.761 35.448 ;
     RECT  78.365 15.744 78.797 15.768 ;
     RECT  78.761 34.656 78.805 34.728 ;
     RECT  78.304 6.816 78.833 6.84 ;
     RECT  78.304 22.08 78.844 22.104 ;
     RECT  78.304 33.6 78.844 33.624 ;
     RECT  78.304 39.888 78.869 39.912 ;
     RECT  78.653 45.696 78.869 45.72 ;
     RECT  78.437 47.712 78.869 47.736 ;
     RECT  78.304 37.584 78.899 38.808 ;
     RECT  78.899 38.016 78.913 38.808 ;
     RECT  78.805 34.656 78.941 34.68 ;
     RECT  78.853 1.152 79.049 1.176 ;
     RECT  78.913 38.016 79.265 38.04 ;
     RECT  78.304 26.592 79.517 26.616 ;
     RECT  79.549 1.776 79.715 1.8 ;
     RECT  80.845 31.296 80.929 31.32 ;
     RECT  81.421 70.32 81.505 70.344 ;
     RECT  79.729 11.76 82.044 11.784 ;
     RECT  80.917 50.784 82.044 50.808 ;
    LAYER M5 ;
     RECT  8.784 0.016 8.808 0.047 ;
     RECT  11.952 0.016 11.976 0.047 ;
     RECT  13.536 0.016 13.56 0.047 ;
     RECT  21.504 0.016 21.528 0.047 ;
     RECT  23.088 0.016 23.112 0.047 ;
     RECT  29.472 0.016 29.496 0.047 ;
     RECT  31.056 0.016 31.08 0.047 ;
     RECT  37.44 0.016 37.464 0.047 ;
     RECT  39.024 0.016 39.048 0.047 ;
     RECT  53.376 0.016 53.4 0.047 ;
     RECT  54.96 0.016 54.984 0.047 ;
     RECT  58.176 0.016 58.2 0.047 ;
     RECT  77.28 0.016 77.304 0.047 ;
     RECT  78.864 0.016 78.888 0.047 ;
     RECT  34.272 0.016 34.296 0.053 ;
     RECT  42.24 0.016 42.264 0.053 ;
     RECT  29.472 0.047 31.08 0.085 ;
     RECT  8.784 0.047 9.096 0.131 ;
     RECT  11.952 0.047 13.56 0.131 ;
     RECT  21.504 0.047 23.112 0.131 ;
     RECT  24.672 0.016 24.696 0.131 ;
     RECT  29.28 0.085 31.08 0.131 ;
     RECT  37.44 0.047 39.336 0.131 ;
     RECT  40.608 0.016 40.632 0.131 ;
     RECT  42.24 0.053 42.744 0.131 ;
     RECT  53.376 0.047 54.984 0.131 ;
     RECT  58.176 0.047 58.68 0.131 ;
     RECT  74.112 0.016 74.136 0.131 ;
     RECT  77.28 0.047 78.888 0.131 ;
     RECT  43.824 0.016 43.848 0.171 ;
     RECT  42.72 0.131 42.744 0.227 ;
     RECT  15.12 0.016 15.144 0.563 ;
     RECT  32.64 0.016 32.664 0.563 ;
     RECT  37.44 0.131 37.464 0.563 ;
     RECT  26.304 0.016 26.328 0.565 ;
     RECT  27.888 0.016 27.912 0.565 ;
     RECT  33.648 0.053 34.296 0.565 ;
     RECT  35.856 0.016 35.88 0.565 ;
     RECT  33.648 0.565 35.88 0.611 ;
     RECT  39.024 0.131 39.048 0.611 ;
     RECT  18.336 0.016 18.36 1.141 ;
     RECT  19.92 0.016 19.944 1.141 ;
     RECT  3.984 0.016 4.008 1.187 ;
     RECT  5.568 0.016 5.592 1.187 ;
     RECT  7.152 0.016 7.176 1.187 ;
     RECT  8.784 0.131 8.808 1.187 ;
     RECT  10.368 0.016 10.392 1.187 ;
     RECT  11.952 0.131 11.976 1.187 ;
     RECT  13.536 0.131 13.56 1.187 ;
     RECT  16.752 0.016 16.776 1.187 ;
     RECT  18.336 1.141 19.944 1.187 ;
     RECT  21.504 0.131 21.528 1.187 ;
     RECT  23.088 0.131 23.112 1.187 ;
     RECT  26.304 0.565 27.912 1.187 ;
     RECT  45.408 0.016 45.432 1.187 ;
     RECT  46.992 0.016 47.016 1.187 ;
     RECT  48.576 0.016 48.6 1.187 ;
     RECT  50.208 0.016 50.232 1.187 ;
     RECT  51.792 0.016 51.816 1.187 ;
     RECT  53.376 0.131 53.4 1.187 ;
     RECT  58.176 0.131 58.2 1.187 ;
     RECT  59.76 0.016 59.784 1.187 ;
     RECT  62.928 0.016 62.952 1.187 ;
     RECT  67.728 0.016 67.752 1.187 ;
     RECT  75.696 0.016 75.72 1.187 ;
     RECT  78.864 0.131 78.888 1.187 ;
     RECT  18.6 1.187 19.128 1.235 ;
     RECT  2.4 0.016 2.424 1.717 ;
     RECT  29.28 0.131 29.304 1.717 ;
     RECT  31.056 0.131 31.08 1.717 ;
     RECT  35.04 0.611 35.88 1.717 ;
     RECT  56.544 0.016 56.568 1.717 ;
     RECT  61.344 0.016 61.368 1.717 ;
     RECT  64.512 0.016 64.536 1.717 ;
     RECT  66.144 0.016 66.168 1.717 ;
     RECT  69.312 0.016 69.336 1.717 ;
     RECT  70.896 0.016 70.92 1.717 ;
     RECT  72.48 0.016 72.504 1.717 ;
     RECT  41.376 1.141 41.4 1.763 ;
     RECT  2.4 1.717 3.24 1.811 ;
     RECT  4.8 1.717 4.824 1.811 ;
     RECT  6.384 1.717 6.408 1.811 ;
     RECT  11.136 1.717 11.16 1.811 ;
     RECT  14.304 1.717 14.328 1.811 ;
     RECT  15.936 1.717 15.96 1.811 ;
     RECT  20.736 1.717 20.76 1.811 ;
     RECT  25.44 1.717 25.464 1.811 ;
     RECT  28.704 1.717 29.304 1.811 ;
     RECT  31.056 1.717 31.896 1.811 ;
     RECT  35.04 1.717 36.744 1.811 ;
     RECT  45.6 1.717 46.2 1.811 ;
     RECT  47.808 1.717 47.832 1.811 ;
     RECT  49.392 1.717 49.416 1.811 ;
     RECT  55.776 1.717 57.384 1.811 ;
     RECT  60.576 1.717 62.184 1.811 ;
     RECT  63.792 1.717 67.32 1.811 ;
     RECT  68.496 1.717 73.272 1.811 ;
     RECT  74.88 1.717 74.904 1.811 ;
     RECT  76.464 1.717 76.488 1.811 ;
     RECT  79.68 1.717 79.704 1.811 ;
     RECT  29.28 1.811 29.304 2.137 ;
     RECT  35.04 1.811 35.88 2.137 ;
     RECT  18.6 1.235 18.72 2.229 ;
     RECT  13.2 2.137 13.32 2.245 ;
     RECT  40.2 2.137 40.32 2.245 ;
     RECT  16.512 2.207 16.536 2.291 ;
     RECT  7.8 1.717 7.992 2.407 ;
     RECT  17.76 2.229 18.72 2.407 ;
     RECT  24 2.137 24.12 2.407 ;
     RECT  29.28 2.137 29.52 2.407 ;
     RECT  51 2.137 51.12 2.407 ;
     RECT  66.144 1.811 67.32 2.407 ;
     RECT  78 2.137 78.12 2.407 ;
     RECT  13.2 2.245 13.848 2.485 ;
     RECT  40.2 2.245 40.632 2.629 ;
     RECT  51 2.407 51.312 2.773 ;
     RECT  13.056 2.485 13.848 2.915 ;
     RECT  29.28 2.407 29.712 2.915 ;
     RECT  31.056 1.811 31.08 2.915 ;
     RECT  33.648 0.611 33.672 2.915 ;
     RECT  34.8 2.137 35.88 2.915 ;
     RECT  61.344 1.811 62.112 2.915 ;
     RECT  66.144 2.407 67.512 2.963 ;
     RECT  50.88 2.773 51.312 2.997 ;
     RECT  69.312 1.811 69.336 2.997 ;
     RECT  70.896 1.811 72.912 2.997 ;
     RECT  50.88 2.997 52.296 3.051 ;
     RECT  39.888 2.629 40.632 3.059 ;
     RECT  51 3.051 52.296 3.085 ;
     RECT  69.312 2.997 72.912 3.085 ;
     RECT  47.424 2.773 47.448 3.155 ;
     RECT  69.312 3.085 69.864 3.155 ;
     RECT  56.4 1.811 56.712 3.157 ;
     RECT  24 2.407 24.312 3.349 ;
     RECT  42.336 2.821 42.36 3.539 ;
     RECT  23.232 3.349 24.312 3.551 ;
     RECT  70.896 3.085 72.912 3.587 ;
     RECT  22.752 3.551 24.312 3.635 ;
     RECT  78 2.407 78.312 3.667 ;
     RECT  43.92 3.573 43.944 3.701 ;
     RECT  45.6 1.811 45.912 3.701 ;
     RECT  17.76 2.407 18.912 3.731 ;
     RECT  47.184 3.667 47.208 3.755 ;
     RECT  78 3.667 78.456 3.755 ;
     RECT  75.792 3.685 75.816 3.769 ;
     RECT  66.432 2.963 67.512 3.827 ;
     RECT  43.872 3.701 43.944 3.875 ;
     RECT  45.408 3.701 45.912 3.875 ;
     RECT  25.536 3.397 25.56 3.877 ;
     RECT  47.088 3.795 47.112 3.883 ;
     RECT  25.536 3.877 26.52 4.011 ;
     RECT  64.512 1.811 64.536 4.019 ;
     RECT  17.568 4.021 17.592 4.115 ;
     RECT  27.936 3.301 27.96 4.115 ;
     RECT  40.2 3.059 40.632 4.115 ;
     RECT  20.544 3.973 20.568 4.163 ;
     RECT  18.6 3.731 18.912 4.165 ;
     RECT  13.2 2.915 13.848 4.341 ;
     RECT  25.536 4.011 26.424 4.355 ;
     RECT  9.888 4.341 9.912 4.429 ;
     RECT  13.2 4.341 14.184 4.429 ;
     RECT  72.48 3.587 72.912 4.451 ;
     RECT  18.6 4.165 19.416 4.501 ;
     RECT  51 3.085 51.312 4.511 ;
     RECT  23.232 3.635 24.312 4.549 ;
     RECT  38.928 4.501 38.952 4.587 ;
     RECT  3.984 3.349 4.008 4.595 ;
     RECT  50.88 4.511 51.312 4.595 ;
     RECT  52.608 4.511 52.632 4.595 ;
     RECT  70.896 3.587 70.92 4.595 ;
     RECT  45.6 3.875 45.912 4.645 ;
     RECT  56.4 3.157 56.904 4.645 ;
     RECT  59.856 4.627 59.88 4.715 ;
     RECT  58.656 3.829 58.68 4.739 ;
     RECT  72.6 4.451 72.912 4.819 ;
     RECT  4.992 4.819 5.016 4.853 ;
     RECT  4.992 4.853 5.736 4.907 ;
     RECT  72.6 4.819 73.896 4.907 ;
     RECT  0.144 4.789 0.168 4.917 ;
     RECT  0.048 4.917 0.168 4.971 ;
     RECT  5.712 4.907 5.736 5.045 ;
     RECT  23.232 4.549 25.272 5.075 ;
     RECT  61.68 2.915 62.112 5.125 ;
     RECT  5.712 5.045 6.408 5.133 ;
     RECT  15.936 4.309 15.96 5.171 ;
     RECT  26.4 4.355 26.424 5.171 ;
     RECT  13.2 4.429 13.512 5.173 ;
     RECT  18.6 4.501 19.608 5.173 ;
     RECT  56.4 4.645 57.048 5.173 ;
     RECT  56.4 5.173 57.624 5.257 ;
     RECT  40.2 4.115 40.512 5.317 ;
     RECT  40.2 5.317 41.448 5.419 ;
     RECT  5.712 5.133 5.736 5.459 ;
     RECT  13.008 5.173 13.512 5.459 ;
     RECT  24 5.075 25.272 5.459 ;
     RECT  36.816 5.423 36.84 5.507 ;
     RECT  33.072 5.429 33.096 5.517 ;
     RECT  13.104 5.459 13.512 5.653 ;
     RECT  70.944 5.125 70.968 5.699 ;
     RECT  29.4 2.915 29.712 5.715 ;
     RECT  16.992 4.981 17.016 5.747 ;
     RECT  44.352 3.925 44.376 5.747 ;
     RECT  65.04 5.125 65.064 5.747 ;
     RECT  29.4 5.715 29.832 5.803 ;
     RECT  61.44 5.125 62.112 5.891 ;
     RECT  45.6 4.645 46.92 5.941 ;
     RECT  61.632 5.891 62.112 6.229 ;
     RECT  33.36 6.197 33.384 6.285 ;
     RECT  76.656 5.685 76.68 6.285 ;
     RECT  13.104 5.653 13.656 6.323 ;
     RECT  44.592 6.239 44.616 6.323 ;
     RECT  68.592 5.605 68.616 6.323 ;
     RECT  26.352 5.317 26.376 6.371 ;
     RECT  53.328 6.197 53.352 6.379 ;
     RECT  45.6 5.941 46.968 6.645 ;
     RECT  48.336 5.845 48.36 6.645 ;
     RECT  48.336 6.645 48.792 6.699 ;
     RECT  48.768 6.699 48.792 6.733 ;
     RECT  24 5.459 24.312 6.739 ;
     RECT  43.296 5.989 43.32 6.739 ;
     RECT  34.8 2.915 35.112 6.757 ;
     RECT  34.704 6.757 35.112 6.773 ;
     RECT  23.616 6.739 24.312 6.827 ;
     RECT  43.104 6.739 43.32 6.827 ;
     RECT  41.616 6.767 41.64 6.851 ;
     RECT  61.632 6.229 62.232 6.851 ;
     RECT  13.104 6.323 13.512 6.899 ;
     RECT  7.8 2.407 8.112 7.029 ;
     RECT  24 6.827 24.312 7.045 ;
     RECT  10.08 6.805 10.104 7.083 ;
     RECT  34.704 6.773 35.736 7.091 ;
     RECT  7.8 7.029 8.28 7.117 ;
     RECT  24 7.045 24.408 7.147 ;
     RECT  18.6 5.173 19.896 7.189 ;
     RECT  56.4 5.257 57.048 7.189 ;
     RECT  56.4 7.189 57.624 7.315 ;
     RECT  51 4.595 51.312 7.333 ;
     RECT  15.984 6.805 16.008 7.381 ;
     RECT  34.704 7.091 35.112 7.381 ;
     RECT  67.2 3.827 67.512 7.381 ;
     RECT  55.632 7.315 57.624 7.403 ;
     RECT  43.92 6.901 43.944 7.413 ;
     RECT  14.832 7.381 16.008 7.467 ;
     RECT  4.512 7.391 4.536 7.475 ;
     RECT  58.848 7.349 58.872 7.475 ;
     RECT  76.368 7.391 76.392 7.475 ;
     RECT  43.92 7.413 44.376 7.523 ;
     RECT  78 3.755 78.312 7.573 ;
     RECT  49.2 6.805 49.224 7.619 ;
     RECT  66.576 7.381 67.512 7.621 ;
     RECT  68.544 7.605 68.568 7.621 ;
     RECT  77.52 7.573 78.312 7.659 ;
     RECT  66.576 7.621 68.568 7.693 ;
     RECT  71.424 7.605 71.448 7.693 ;
     RECT  15.984 7.467 16.008 7.859 ;
     RECT  13.2 6.899 13.512 7.861 ;
     RECT  24 7.147 24.312 7.861 ;
     RECT  61.632 6.851 62.112 7.861 ;
     RECT  33.936 7.381 35.112 7.909 ;
     RECT  45.6 6.645 47.112 7.915 ;
     RECT  23.664 7.861 24.312 7.955 ;
     RECT  45.6 7.915 46.104 7.955 ;
     RECT  51 7.333 51.96 7.957 ;
     RECT  50.88 7.957 51.96 8.147 ;
     RECT  40.2 5.419 40.512 8.293 ;
     RECT  61.632 7.861 62.424 8.293 ;
     RECT  22.464 7.237 22.488 8.339 ;
     RECT  7.8 7.117 8.112 8.341 ;
     RECT  13.104 7.861 13.608 8.341 ;
     RECT  40.2 8.293 41.352 8.427 ;
     RECT  61.392 8.293 62.424 8.427 ;
     RECT  14.832 7.467 14.856 8.435 ;
     RECT  18.6 7.189 20.568 8.435 ;
     RECT  33.6 7.909 35.112 8.437 ;
     RECT  0.048 4.971 0.072 8.485 ;
     RECT  30.864 8.403 30.888 8.491 ;
     RECT  74.352 8.403 74.376 8.491 ;
     RECT  66.576 7.693 68.28 8.531 ;
     RECT  0.048 8.485 0.12 8.569 ;
     RECT  43.584 7.909 43.608 8.579 ;
     RECT  61.632 8.427 62.424 8.675 ;
     RECT  56.4 7.403 57.384 8.723 ;
     RECT  32.832 8.437 35.88 8.963 ;
     RECT  45.6 7.955 45.912 8.979 ;
     RECT  47.376 8.149 47.4 8.979 ;
     RECT  31.632 8.869 31.656 9.003 ;
     RECT  12.912 8.341 13.608 9.024 ;
     RECT  7.632 8.341 8.112 9.061 ;
     RECT  16.944 8.917 16.968 9.061 ;
     RECT  29.4 5.803 29.712 9.061 ;
     RECT  50.88 8.147 51.432 9.061 ;
     RECT  45.6 8.979 47.4 9.067 ;
     RECT  24 7.955 24.312 9.109 ;
     RECT  78 7.659 78.312 9.109 ;
     RECT  32.832 8.963 32.856 9.131 ;
     RECT  69.84 3.155 69.864 9.141 ;
     RECT  10.848 8.485 10.872 9.155 ;
     RECT  66.768 8.531 67.512 9.155 ;
     RECT  64.56 9.061 64.584 9.157 ;
     RECT  50.832 9.061 51.432 9.171 ;
     RECT  16.944 9.061 17.112 9.195 ;
     RECT  39.12 9.077 39.144 9.203 ;
     RECT  15.696 9.141 15.72 9.229 ;
     RECT  12.912 9.024 13.512 9.395 ;
     RECT  16.944 9.195 16.968 9.445 ;
     RECT  41.616 9.461 41.64 9.549 ;
     RECT  49.296 9.205 49.32 9.643 ;
     RECT  67.056 9.155 67.512 9.717 ;
     RECT  13.056 9.395 13.512 9.731 ;
     RECT  63.504 9.717 63.528 9.733 ;
     RECT  64.56 9.157 64.68 9.733 ;
     RECT  25.68 9.695 25.704 9.779 ;
     RECT  24 9.109 24.648 9.781 ;
     RECT  63.504 9.733 64.68 9.805 ;
     RECT  63.552 9.805 64.68 9.835 ;
     RECT  67.056 9.717 68.232 9.925 ;
     RECT  69.312 9.141 69.864 9.925 ;
     RECT  67.056 9.925 69.864 9.973 ;
     RECT  50.832 9.171 52.056 10.003 ;
     RECT  56.4 8.723 56.904 10.021 ;
     RECT  67.056 9.973 70.248 10.027 ;
     RECT  50.832 10.003 52.152 10.091 ;
     RECT  53.328 9.909 53.352 10.091 ;
     RECT  56.4 10.021 57.048 10.105 ;
     RECT  67.056 10.027 68.184 10.115 ;
     RECT  24 9.781 25.224 10.163 ;
     RECT  42.288 10.021 42.312 10.163 ;
     RECT  16.896 9.445 16.968 10.213 ;
     RECT  18.6 8.435 19.848 10.213 ;
     RECT  60.432 10.131 60.456 10.219 ;
     RECT  67.056 10.115 67.944 10.219 ;
     RECT  74.592 10.131 74.616 10.219 ;
     RECT  78 9.109 78.6 10.307 ;
     RECT  6.864 9.061 8.112 10.355 ;
     RECT  33.936 8.963 35.88 10.595 ;
     RECT  75.792 9.637 75.816 10.595 ;
     RECT  13.104 9.731 13.512 10.741 ;
     RECT  40.2 8.427 40.512 10.789 ;
     RECT  13.104 10.741 14.232 10.799 ;
     RECT  45.6 9.067 45.912 10.799 ;
     RECT  72.6 4.907 72.912 10.799 ;
     RECT  13.104 10.799 14.904 10.883 ;
     RECT  45.6 10.799 46.152 10.883 ;
     RECT  69.84 10.027 70.248 10.883 ;
     RECT  72.6 10.799 73.128 10.883 ;
     RECT  5.616 10.805 5.64 10.893 ;
     RECT  28.464 9.061 29.712 11.171 ;
     RECT  7.632 10.355 8.112 11.375 ;
     RECT  9.792 9.925 9.816 11.375 ;
     RECT  38.784 11.029 38.808 11.375 ;
     RECT  39.936 10.789 40.512 11.411 ;
     RECT  63.552 9.835 63.576 11.411 ;
     RECT  7.632 11.375 9.816 11.435 ;
     RECT  38.16 11.375 38.808 11.435 ;
     RECT  7.632 11.435 9.096 11.459 ;
     RECT  13.104 10.883 14.232 11.459 ;
     RECT  38.16 11.435 38.184 11.459 ;
     RECT  60.384 11.375 60.408 11.459 ;
     RECT  61.632 8.675 62.112 11.459 ;
     RECT  6.288 11.029 6.312 11.699 ;
     RECT  45.6 10.883 45.912 11.845 ;
     RECT  24 10.163 24.312 11.941 ;
     RECT  44.688 11.845 45.912 11.947 ;
     RECT  0.048 8.569 0.072 12.191 ;
     RECT  45.6 11.947 45.912 12.243 ;
     RECT  0.048 12.191 0.12 12.275 ;
     RECT  53.616 12.243 53.64 12.331 ;
     RECT  45.6 12.243 46.008 12.469 ;
     RECT  7.632 11.459 8.112 12.517 ;
     RECT  16.896 10.213 19.848 12.517 ;
     RECT  72.6 10.883 72.912 12.517 ;
     RECT  52.416 10.213 52.44 12.563 ;
     RECT  16.896 12.517 20.232 12.853 ;
     RECT  67.056 10.219 67.704 12.901 ;
     RECT  45.6 12.469 46.248 12.947 ;
     RECT  2.4 1.811 2.712 12.949 ;
     RECT  61.68 11.459 62.112 12.995 ;
     RECT  61.8 12.995 62.112 12.997 ;
     RECT  16.896 12.853 20.808 13.043 ;
     RECT  40.08 11.411 40.512 13.045 ;
     RECT  30.768 12.853 30.792 13.091 ;
     RECT  61.8 12.997 62.328 13.099 ;
     RECT  67.056 12.901 68.616 13.139 ;
     RECT  75.84 12.517 75.864 13.139 ;
     RECT  54.048 13.103 54.072 13.187 ;
     RECT  71.856 12.517 72.912 13.235 ;
     RECT  7.536 12.517 8.112 13.285 ;
     RECT  24 11.941 24.408 13.285 ;
     RECT  29.4 11.171 29.712 13.285 ;
     RECT  26.352 13.267 26.376 13.355 ;
     RECT  7.536 13.285 8.28 13.369 ;
     RECT  24 13.285 25.08 13.369 ;
     RECT  28.992 13.285 29.712 13.369 ;
     RECT  47.376 9.067 47.4 13.381 ;
     RECT  69.84 10.883 69.864 13.429 ;
     RECT  47.328 13.381 47.4 13.715 ;
     RECT  7.536 13.369 8.112 14.101 ;
     RECT  64.656 9.835 64.68 14.197 ;
     RECT  16.896 13.043 20.376 14.243 ;
     RECT  45.6 12.947 45.912 14.245 ;
     RECT  69.84 13.429 70.68 14.341 ;
     RECT  68.736 13.573 68.76 14.387 ;
     RECT  22.8 12.949 22.824 14.389 ;
     RECT  69.84 14.341 70.92 14.443 ;
     RECT  42.144 14.389 42.168 14.473 ;
     RECT  44.976 14.245 45.912 14.533 ;
     RECT  44.976 14.533 46.008 14.635 ;
     RECT  24 13.369 24.312 14.716 ;
     RECT  56.4 10.105 56.904 14.773 ;
     RECT  64.656 14.197 65.544 14.819 ;
     RECT  69.84 14.443 70.68 14.819 ;
     RECT  22.176 14.389 22.824 14.827 ;
     RECT  64.656 14.819 65.16 14.831 ;
     RECT  69.84 14.819 69.864 14.831 ;
     RECT  56.4 14.773 57.72 14.837 ;
     RECT  6.24 13.429 6.264 14.867 ;
     RECT  54.768 14.725 54.792 14.891 ;
     RECT  63.792 14.831 65.16 14.891 ;
     RECT  63.792 14.891 64.68 14.915 ;
     RECT  69.504 14.831 69.864 14.915 ;
     RECT  13.104 11.459 13.512 14.917 ;
     RECT  56.16 14.837 57.72 14.917 ;
     RECT  67.056 13.139 67.704 15.013 ;
     RECT  67.056 15.013 67.848 15.029 ;
     RECT  0.048 12.275 0.072 15.059 ;
     RECT  50.832 10.091 51.312 15.059 ;
     RECT  56.064 14.917 57.72 15.059 ;
     RECT  7.44 14.101 8.112 15.061 ;
     RECT  38.208 14.995 38.232 15.083 ;
     RECT  66.528 15.029 67.848 15.117 ;
     RECT  39.264 13.045 40.512 15.205 ;
     RECT  29.28 13.369 29.712 15.251 ;
     RECT  33.936 10.595 35.112 15.253 ;
     RECT  39.264 15.205 40.776 15.339 ;
     RECT  67.056 15.117 67.848 15.379 ;
     RECT  43.2 13.957 43.224 15.397 ;
     RECT  44.976 14.635 45.912 15.443 ;
     RECT  56.4 15.059 57.72 15.443 ;
     RECT  78 10.307 78.312 15.541 ;
     RECT  23.904 14.716 24.312 15.571 ;
     RECT  2.4 12.949 2.952 15.587 ;
     RECT  23.904 15.571 24.888 15.637 ;
     RECT  67.056 15.379 68.424 15.647 ;
     RECT  39.264 15.339 40.512 15.683 ;
     RECT  75.648 15.637 75.672 15.685 ;
     RECT  77.184 15.541 78.312 15.699 ;
     RECT  23.904 15.637 25.08 15.723 ;
     RECT  23.904 15.723 24.888 15.731 ;
     RECT  67.056 15.647 68.712 15.731 ;
     RECT  75.216 15.685 75.768 15.787 ;
     RECT  77.184 15.699 78.744 15.787 ;
     RECT  30.816 15.407 30.84 15.817 ;
     RECT  33.936 15.253 35.208 15.877 ;
     RECT  2.4 15.587 2.712 15.925 ;
     RECT  33.12 15.877 35.208 15.979 ;
     RECT  50.88 15.059 51.312 15.989 ;
     RECT  3.936 15.925 3.96 16.009 ;
     RECT  27.888 15.157 27.912 16.019 ;
     RECT  75.216 15.787 75.24 16.019 ;
     RECT  49.632 15.699 49.656 16.043 ;
     RECT  13.104 14.917 13.656 16.213 ;
     RECT  50.88 15.989 51.432 16.245 ;
     RECT  22.176 14.827 22.2 16.259 ;
     RECT  50.832 16.245 51.432 16.333 ;
     RECT  12.912 16.213 13.656 16.363 ;
     RECT  2.304 15.925 2.712 16.403 ;
     RECT  43.2 15.397 43.416 16.499 ;
     RECT  33.936 15.979 35.208 16.501 ;
     RECT  77.232 15.787 78.312 16.547 ;
     RECT  50.88 16.333 51.432 16.555 ;
     RECT  47.376 13.715 47.4 16.565 ;
     RECT  67.056 15.731 68.424 16.595 ;
     RECT  33.936 16.501 35.784 16.619 ;
     RECT  37.104 16.565 37.128 16.787 ;
     RECT  24 15.731 24.888 16.835 ;
     RECT  47.376 16.565 47.736 16.835 ;
     RECT  29.4 15.251 29.712 16.837 ;
     RECT  24 16.835 24.312 16.981 ;
     RECT  43.296 16.499 43.416 17.027 ;
     RECT  64.656 14.915 64.68 17.029 ;
     RECT  6.576 15.061 8.112 17.077 ;
     RECT  13.104 16.363 13.656 17.077 ;
     RECT  33.936 16.619 35.304 17.077 ;
     RECT  40.2 15.683 40.512 17.077 ;
     RECT  64.56 17.029 64.68 17.077 ;
     RECT  37.056 16.981 37.08 17.123 ;
     RECT  69.84 14.915 69.864 17.123 ;
     RECT  33.024 17.077 35.304 17.161 ;
     RECT  29.136 16.837 29.712 17.173 ;
     RECT  13.104 17.077 14.04 17.219 ;
     RECT  23.376 16.981 24.312 17.219 ;
     RECT  31.872 17.077 31.896 17.219 ;
     RECT  52.704 16.501 52.728 17.363 ;
     RECT  13.104 17.219 13.656 17.387 ;
     RECT  10.752 16.213 10.776 17.589 ;
     RECT  76.944 17.077 76.968 17.651 ;
     RECT  29.136 17.173 30.264 17.795 ;
     RECT  72.6 13.235 72.912 17.797 ;
     RECT  47.376 16.835 47.688 17.843 ;
     RECT  10.512 17.589 10.776 17.845 ;
     RECT  10.416 17.845 10.776 17.891 ;
     RECT  67.056 16.595 67.512 17.891 ;
     RECT  50.88 16.555 51.312 18.037 ;
     RECT  68.592 16.981 68.616 18.131 ;
     RECT  71.904 17.797 72.912 18.131 ;
     RECT  78 16.547 78.312 18.133 ;
     RECT  56.4 15.443 56.904 18.181 ;
     RECT  45.6 15.443 45.912 18.229 ;
     RECT  4.896 17.029 4.92 18.419 ;
     RECT  39.888 17.077 40.512 18.467 ;
     RECT  64.56 17.077 65.208 18.467 ;
     RECT  16.896 14.243 19.848 18.485 ;
     RECT  52.656 18.229 52.68 18.515 ;
     RECT  21.12 18.469 21.144 18.553 ;
     RECT  55.872 18.181 56.904 18.565 ;
     RECT  13.104 17.387 13.608 18.643 ;
     RECT  67.2 17.891 67.512 18.643 ;
     RECT  13.104 18.643 14.52 18.661 ;
     RECT  55.008 18.565 56.904 18.667 ;
     RECT  43.392 17.027 43.416 18.671 ;
     RECT  45.504 18.229 45.912 18.677 ;
     RECT  10.416 17.891 10.44 18.707 ;
     RECT  6.576 17.077 8.376 18.709 ;
     RECT  16.416 18.485 19.848 18.709 ;
     RECT  13.056 18.661 14.52 18.731 ;
     RECT  38.544 18.643 38.568 18.731 ;
     RECT  49.152 18.643 49.176 18.731 ;
     RECT  13.056 18.731 14.232 18.745 ;
     RECT  43.296 18.671 43.416 18.755 ;
     RECT  45.504 18.677 46.008 18.765 ;
     RECT  50.88 18.037 51.432 18.803 ;
     RECT  61.8 13.099 62.112 18.805 ;
     RECT  67.2 18.643 67.752 19.093 ;
     RECT  24 17.219 24.312 19.189 ;
     RECT  77.76 18.133 78.312 19.189 ;
     RECT  21.936 19.155 21.96 19.243 ;
     RECT  76.944 19.189 78.312 19.273 ;
     RECT  61.632 18.805 62.112 19.333 ;
     RECT  29.136 17.795 29.712 19.379 ;
     RECT  6.576 18.709 9.096 19.427 ;
     RECT  26.16 17.509 26.184 19.427 ;
     RECT  45.504 18.765 45.912 19.427 ;
     RECT  65.952 18.805 65.976 19.523 ;
     RECT  40.08 18.467 40.512 19.571 ;
     RECT  0.096 19.631 0.12 19.715 ;
     RECT  16.176 18.709 19.848 19.763 ;
     RECT  70.416 18.565 70.44 19.763 ;
     RECT  61.632 19.333 62.664 19.765 ;
     RECT  64.56 18.467 64.584 19.765 ;
     RECT  59.856 18.421 59.88 19.811 ;
     RECT  48.96 19.765 49.704 19.849 ;
     RECT  61.536 19.765 62.664 19.849 ;
     RECT  31.584 19.573 31.608 19.859 ;
     RECT  49.68 19.849 49.704 19.859 ;
     RECT  43.392 18.755 43.416 19.871 ;
     RECT  22.8 19.525 22.824 19.909 ;
     RECT  23.904 19.189 24.312 19.909 ;
     RECT  72.6 18.131 72.912 19.957 ;
     RECT  55.2 18.667 56.904 20.003 ;
     RECT  25.632 19.957 25.656 20.051 ;
     RECT  72.288 19.957 72.912 20.051 ;
     RECT  43.392 19.871 43.464 20.149 ;
     RECT  55.872 20.003 56.904 20.149 ;
     RECT  67.2 19.093 68.088 20.149 ;
     RECT  66.768 20.149 68.088 20.195 ;
     RECT  31.536 20.149 31.56 20.291 ;
     RECT  64.128 19.765 64.584 20.291 ;
     RECT  22.8 19.909 24.312 20.339 ;
     RECT  55.872 20.149 57.336 20.339 ;
     RECT  45.6 19.427 45.912 20.533 ;
     RECT  13.104 18.745 14.232 20.579 ;
     RECT  45.6 20.533 46.2 20.617 ;
     RECT  5.424 20.533 5.448 20.627 ;
     RECT  21.744 20.533 21.768 20.627 ;
     RECT  45.6 20.617 45.912 20.629 ;
     RECT  75.792 19.621 75.816 20.819 ;
     RECT  33.936 17.161 35.304 20.869 ;
     RECT  23.664 20.339 24.312 20.883 ;
     RECT  23.664 20.883 24.888 20.971 ;
     RECT  65.664 20.821 65.688 21.059 ;
     RECT  43.392 20.149 43.608 21.075 ;
     RECT  23.664 20.971 24.312 21.107 ;
     RECT  32.976 20.869 35.304 21.107 ;
     RECT  40.2 19.571 40.512 21.109 ;
     RECT  44.976 20.629 45.912 21.11 ;
     RECT  66.768 20.195 67.512 21.155 ;
     RECT  38.16 20.965 38.184 21.163 ;
     RECT  42.912 21.075 43.608 21.163 ;
     RECT  39.36 21.109 40.512 21.193 ;
     RECT  45.024 21.11 45.912 21.203 ;
     RECT  56.304 20.339 57.336 21.683 ;
     RECT  56.4 21.683 57.336 21.685 ;
     RECT  56.4 21.685 57.432 21.779 ;
     RECT  45.6 21.203 45.912 21.973 ;
     RECT  47.376 17.843 47.4 21.973 ;
     RECT  72.6 20.051 72.912 22.035 ;
     RECT  77.76 19.273 78.312 22.035 ;
     RECT  45.6 21.973 47.4 22.059 ;
     RECT  67.2 21.155 67.512 22.069 ;
     RECT  72.288 22.035 72.912 22.069 ;
     RECT  45.6 22.059 46.008 22.093 ;
     RECT  72.288 22.069 73.56 22.123 ;
     RECT  76.896 22.035 78.792 22.123 ;
     RECT  72.6 22.123 73.56 22.153 ;
     RECT  29.4 19.379 29.712 22.165 ;
     RECT  40.2 21.193 40.512 22.165 ;
     RECT  54.624 22.261 54.648 22.355 ;
     RECT  54.672 22.389 54.792 22.499 ;
     RECT  61.632 19.849 62.664 22.549 ;
     RECT  39.312 22.165 40.512 22.581 ;
     RECT  13.104 20.579 13.512 22.645 ;
     RECT  61.632 22.549 62.808 22.645 ;
     RECT  39.312 22.581 41.112 22.691 ;
     RECT  14.832 22.611 14.856 22.699 ;
     RECT  61.632 22.645 63.24 22.739 ;
     RECT  75.36 22.069 75.384 22.741 ;
     RECT  54.672 22.499 54.696 22.763 ;
     RECT  27.312 22.453 27.336 22.777 ;
     RECT  53.568 22.693 53.592 22.777 ;
     RECT  74.688 22.741 75.384 22.827 ;
     RECT  13.104 22.645 13.656 22.835 ;
     RECT  67.2 22.069 68.088 22.835 ;
     RECT  77.76 22.123 78.312 22.835 ;
     RECT  29.4 22.165 29.832 22.837 ;
     RECT  75.36 22.827 75.384 22.931 ;
     RECT  67.2 22.835 67.752 23.123 ;
     RECT  28.848 22.837 29.832 23.157 ;
     RECT  63.216 22.739 63.24 23.219 ;
     RECT  28.848 23.157 30.696 23.245 ;
     RECT  28.848 23.245 29.832 23.267 ;
     RECT  33.936 21.107 35.304 23.269 ;
     RECT  6.576 19.427 8.376 23.285 ;
     RECT  9.984 23.251 10.008 23.285 ;
     RECT  43.392 21.163 43.608 23.317 ;
     RECT  45.6 22.093 45.912 23.317 ;
     RECT  6.576 23.285 10.008 23.339 ;
     RECT  33.936 23.269 35.88 23.353 ;
     RECT  39.312 22.691 40.512 23.363 ;
     RECT  6.576 23.339 9.144 23.373 ;
     RECT  0.096 23.317 0.12 23.403 ;
     RECT  11.424 23.285 11.448 23.411 ;
     RECT  60.384 21.781 60.408 23.459 ;
     RECT  43.392 23.317 45.912 23.555 ;
     RECT  28.848 23.267 29.712 23.795 ;
     RECT  44.976 23.555 45.912 23.797 ;
     RECT  44.976 23.797 46.056 23.845 ;
     RECT  47.376 22.059 47.4 23.845 ;
     RECT  56.4 21.779 56.904 23.845 ;
     RECT  59.136 23.701 59.16 23.915 ;
     RECT  60.192 23.827 60.216 23.915 ;
     RECT  65.568 23.701 65.592 23.915 ;
     RECT  44.976 23.845 47.4 23.929 ;
     RECT  53.04 23.845 53.064 23.929 ;
     RECT  40.08 23.363 40.512 24.053 ;
     RECT  21.024 22.741 21.048 24.083 ;
     RECT  15.696 23.925 15.72 24.131 ;
     RECT  13.104 22.835 13.608 24.227 ;
     RECT  24 21.107 24.312 24.325 ;
     RECT  40.08 24.053 41.208 24.371 ;
     RECT  42.24 24.053 42.264 24.371 ;
     RECT  44.976 23.929 46.104 24.371 ;
     RECT  32.256 23.125 32.28 24.515 ;
     RECT  56.304 23.845 56.904 24.515 ;
     RECT  61.632 22.739 62.112 24.565 ;
     RECT  69.984 23.701 70.008 24.611 ;
     RECT  61.008 24.565 62.112 24.659 ;
     RECT  45.6 24.371 46.104 24.707 ;
     RECT  2.4 16.403 2.712 25.045 ;
     RECT  40.08 24.371 40.512 25.045 ;
     RECT  24 24.325 24.504 25.139 ;
     RECT  72.6 22.153 72.912 25.141 ;
     RECT  2.4 25.045 3.288 25.187 ;
     RECT  39.264 25.045 40.512 25.195 ;
     RECT  13.104 24.227 13.512 25.205 ;
     RECT  49.056 25.093 49.08 25.235 ;
     RECT  72.336 25.141 72.912 25.235 ;
     RECT  24 25.139 24.312 25.439 ;
     RECT  27.36 25.045 27.384 25.515 ;
     RECT  23.904 25.439 24.312 25.523 ;
     RECT  45.6 24.707 46.056 25.571 ;
     RECT  43.392 23.555 43.608 25.631 ;
     RECT  16.896 19.763 19.848 25.653 ;
     RECT  61.488 24.659 62.112 25.717 ;
     RECT  69.504 24.853 69.528 25.717 ;
     RECT  16.56 25.653 19.848 25.741 ;
     RECT  48.72 25.653 48.744 25.741 ;
     RECT  61.488 25.717 62.232 25.801 ;
     RECT  13.104 25.205 13.608 25.939 ;
     RECT  13.104 25.939 14.232 26.027 ;
     RECT  69.408 25.717 69.528 26.099 ;
     RECT  45.6 25.571 46.008 26.207 ;
     RECT  3.936 26.149 3.96 26.233 ;
     RECT  10.272 25.045 10.296 26.243 ;
     RECT  37.728 25.093 37.752 26.243 ;
     RECT  43.296 25.631 43.608 26.291 ;
     RECT  45.024 26.207 46.008 26.291 ;
     RECT  54.624 26.207 54.648 26.291 ;
     RECT  69.504 26.099 69.528 26.483 ;
     RECT  6.576 23.373 8.376 26.591 ;
     RECT  50.88 18.803 51.312 26.591 ;
     RECT  6.576 26.591 8.52 26.613 ;
     RECT  45.6 26.291 46.008 26.629 ;
     RECT  61.488 25.801 62.112 26.629 ;
     RECT  29.4 23.795 29.712 26.677 ;
     RECT  67.2 23.123 67.512 26.725 ;
     RECT  67.104 26.725 67.512 26.741 ;
     RECT  29.088 26.677 29.712 26.748 ;
     RECT  26.016 26.341 26.04 26.795 ;
     RECT  67.104 26.741 68.184 26.809 ;
     RECT  6.576 26.613 9.144 26.819 ;
     RECT  67.2 26.809 68.184 26.829 ;
     RECT  29.088 26.748 30.648 26.859 ;
     RECT  27.36 26.741 27.384 27.059 ;
     RECT  75.6 26.197 75.624 27.059 ;
     RECT  0.096 27.061 0.12 27.155 ;
     RECT  6.576 26.819 8.376 27.155 ;
     RECT  61.008 26.629 62.112 27.205 ;
     RECT  29.4 26.859 30.648 27.299 ;
     RECT  50.688 26.591 51.312 27.301 ;
     RECT  13.104 26.027 13.512 27.317 ;
     RECT  43.392 26.291 43.608 27.347 ;
     RECT  13.056 27.317 13.512 27.349 ;
     RECT  33.936 23.353 35.304 27.349 ;
     RECT  10.464 27.283 10.488 27.371 ;
     RECT  64.56 20.291 64.584 27.395 ;
     RECT  77.856 22.835 78.312 27.551 ;
     RECT  68.688 27.509 68.808 27.589 ;
     RECT  77.52 27.551 78.312 27.635 ;
     RECT  68.688 27.589 69.528 27.691 ;
     RECT  13.056 27.349 13.608 27.836 ;
     RECT  32.736 26.725 32.76 27.875 ;
     RECT  68.688 27.691 68.712 27.875 ;
     RECT  56.4 24.515 56.904 27.877 ;
     RECT  60.912 27.205 62.112 27.971 ;
     RECT  52.8 27.301 52.824 28.115 ;
     RECT  31.296 28.127 31.32 28.211 ;
     RECT  38.208 28.149 38.232 28.237 ;
     RECT  36.432 27.301 36.456 28.261 ;
     RECT  61.488 27.971 62.112 28.261 ;
     RECT  77.856 27.635 78.312 28.261 ;
     RECT  36.432 28.261 36.984 28.307 ;
     RECT  16.896 25.741 19.848 28.309 ;
     RECT  50.544 27.301 51.312 28.355 ;
     RECT  13.056 27.836 13.656 28.403 ;
     RECT  29.4 27.299 29.832 28.405 ;
     RECT  43.392 27.347 43.416 28.453 ;
     RECT  13.056 28.403 13.608 28.459 ;
     RECT  29.4 28.405 30.36 28.499 ;
     RECT  29.4 28.499 30.264 28.537 ;
     RECT  42.528 28.453 43.416 28.537 ;
     RECT  58.128 28.453 58.152 28.537 ;
     RECT  22.944 27.877 22.968 28.547 ;
     RECT  50.832 28.355 51.312 28.627 ;
     RECT  4.656 28.533 4.68 28.643 ;
     RECT  50.832 28.627 51.864 28.715 ;
     RECT  29.4 28.537 29.928 28.789 ;
     RECT  55.872 27.877 56.904 28.835 ;
     RECT  77.856 28.261 78.696 28.917 ;
     RECT  13.104 28.459 13.608 28.979 ;
     RECT  29.28 28.789 29.928 28.979 ;
     RECT  77.568 28.917 78.696 29.005 ;
     RECT  5.136 28.837 5.304 29.027 ;
     RECT  64.032 27.877 64.056 29.045 ;
     RECT  36.96 28.307 36.984 29.075 ;
     RECT  61.488 28.261 62.76 29.077 ;
     RECT  64.032 29.045 64.776 29.077 ;
     RECT  64.032 29.077 65.064 29.099 ;
     RECT  25.92 29.039 25.944 29.123 ;
     RECT  64.752 29.099 65.064 29.133 ;
     RECT  50.832 28.715 51.312 29.171 ;
     RECT  61.008 29.077 62.76 29.171 ;
     RECT  56.304 28.835 56.904 29.173 ;
     RECT  61.008 29.171 62.112 29.219 ;
     RECT  77.856 29.005 78.696 29.219 ;
     RECT  77.856 29.219 78.312 29.267 ;
     RECT  52.992 29.231 53.016 29.315 ;
     RECT  7.8 27.155 8.376 29.317 ;
     RECT  75.936 29.301 75.96 29.389 ;
     RECT  65.04 29.133 65.064 29.411 ;
     RECT  54.768 29.237 54.792 29.507 ;
     RECT  24 25.523 24.312 29.509 ;
     RECT  40.2 25.195 40.512 29.605 ;
     RECT  67.2 26.829 67.512 29.605 ;
     RECT  15.936 28.309 19.848 29.699 ;
     RECT  74.688 28.789 74.712 29.699 ;
     RECT  9.408 29.509 9.432 29.893 ;
     RECT  43.392 28.537 43.416 29.893 ;
     RECT  9.408 29.893 9.672 29.939 ;
     RECT  42.24 29.971 42.264 30.059 ;
     RECT  43.392 29.893 44.04 30.059 ;
     RECT  74.112 29.989 74.232 30.073 ;
     RECT  56.304 29.173 56.952 30.083 ;
     RECT  25.488 30.037 25.512 30.123 ;
     RECT  74.112 30.073 74.136 30.123 ;
     RECT  38.208 29.605 38.232 30.179 ;
     RECT  13.104 28.979 13.512 30.229 ;
     RECT  7.68 29.317 8.376 30.419 ;
     RECT  45.6 26.629 46.104 30.565 ;
     RECT  47.376 23.929 47.4 30.565 ;
     RECT  53.712 30.037 53.736 30.645 ;
     RECT  45.6 30.565 47.4 30.649 ;
     RECT  28.272 30.181 28.296 30.661 ;
     RECT  29.4 28.979 29.928 30.661 ;
     RECT  2.4 25.187 2.712 30.757 ;
     RECT  61.584 29.219 62.112 30.773 ;
     RECT  40.2 29.605 40.632 30.803 ;
     RECT  58.704 30.421 58.728 30.803 ;
     RECT  55.2 30.767 55.224 30.851 ;
     RECT  0.096 30.773 0.12 30.861 ;
     RECT  60.912 30.773 62.112 30.861 ;
     RECT  63.456 30.773 63.48 30.861 ;
     RECT  28.272 30.661 29.928 30.899 ;
     RECT  2.4 30.757 3.624 30.947 ;
     RECT  23.856 29.509 24.312 30.949 ;
     RECT  29.088 30.899 29.928 30.949 ;
     RECT  53.568 30.645 53.736 30.995 ;
     RECT  23.808 30.949 24.312 31.029 ;
     RECT  29.088 30.949 30.84 31.033 ;
     RECT  9.648 29.939 9.672 31.043 ;
     RECT  21.984 30.949 22.008 31.083 ;
     RECT  23.808 31.029 24.888 31.117 ;
     RECT  26.784 30.757 26.808 31.139 ;
     RECT  7.8 30.419 8.376 31.189 ;
     RECT  53.568 30.995 53.592 31.331 ;
     RECT  80.88 31.285 80.904 31.369 ;
     RECT  29.088 31.033 29.928 31.379 ;
     RECT  33.936 27.349 35.352 31.379 ;
     RECT  34.704 31.379 35.352 31.427 ;
     RECT  43.392 30.059 43.416 31.525 ;
     RECT  66.864 29.605 67.512 31.525 ;
     RECT  72.6 25.235 72.912 31.765 ;
     RECT  34.704 31.427 35.304 31.811 ;
     RECT  23.808 31.117 24.312 31.813 ;
     RECT  7.8 31.189 9.144 31.907 ;
     RECT  52.416 30.645 52.44 31.907 ;
     RECT  23.328 31.813 24.312 31.915 ;
     RECT  72.6 31.765 73.512 31.915 ;
     RECT  34.704 31.811 35.256 31.945 ;
     RECT  5.136 29.027 5.16 32.003 ;
     RECT  38.16 31.525 38.184 32.147 ;
     RECT  55.296 31.957 55.32 32.403 ;
     RECT  56.4 30.083 56.952 32.403 ;
     RECT  55.296 32.403 56.952 32.437 ;
     RECT  57.936 32.403 57.96 32.437 ;
     RECT  43.392 31.525 43.512 32.483 ;
     RECT  55.296 32.437 58.728 32.491 ;
     RECT  29.4 31.379 29.928 32.495 ;
     RECT  56.4 32.491 58.728 32.531 ;
     RECT  29.4 32.495 29.976 32.579 ;
     RECT  78 29.267 78.312 32.773 ;
     RECT  16.896 29.699 19.848 32.851 ;
     RECT  16.896 32.851 20.28 32.939 ;
     RECT  13.104 30.229 14.28 32.963 ;
     RECT  77.328 32.773 78.312 33.003 ;
     RECT  75.744 32.949 75.768 33.037 ;
     RECT  61.632 30.861 62.112 33.061 ;
     RECT  56.4 32.531 57.96 33.107 ;
     RECT  74.544 31.804 74.568 33.107 ;
     RECT  45.6 30.649 46.104 33.109 ;
     RECT  45.024 33.109 46.104 33.251 ;
     RECT  50.88 29.171 51.312 33.253 ;
     RECT  64.992 32.965 65.016 33.397 ;
     RECT  7.8 31.907 8.376 33.493 ;
     RECT  7.8 33.493 8.808 33.579 ;
     RECT  13.104 32.963 13.704 33.579 ;
     RECT  78 33.003 78.312 33.589 ;
     RECT  43.392 32.483 43.416 33.635 ;
     RECT  61.536 33.061 62.112 33.637 ;
     RECT  66.672 31.525 67.512 33.683 ;
     RECT  24 31.915 24.312 33.717 ;
     RECT  49.536 33.647 49.56 33.731 ;
     RECT  23.328 33.717 24.312 33.781 ;
     RECT  22.8 33.781 24.312 33.827 ;
     RECT  26.88 33.829 26.904 33.963 ;
     RECT  32.448 33.751 32.472 33.963 ;
     RECT  36.672 33.589 36.696 33.973 ;
     RECT  67.2 33.683 67.512 34.069 ;
     RECT  63.408 33.013 63.432 34.115 ;
     RECT  47.376 30.649 47.4 34.117 ;
     RECT  64.992 33.397 65.256 34.155 ;
     RECT  47.184 34.117 47.4 34.165 ;
     RECT  4.512 34.131 4.536 34.219 ;
     RECT  38.592 33.925 38.616 34.219 ;
     RECT  43.584 34.131 43.608 34.219 ;
     RECT  47.184 34.165 48.12 34.219 ;
     RECT  74.688 34.165 74.712 34.249 ;
     RECT  50.784 33.253 51.312 34.259 ;
     RECT  47.376 34.219 48.12 34.355 ;
     RECT  0.096 34.463 0.12 34.547 ;
     RECT  78 33.589 78.792 34.739 ;
     RECT  50.832 34.259 51.312 34.741 ;
     RECT  67.2 34.069 67.992 34.741 ;
     RECT  72.6 31.915 72.912 34.789 ;
     RECT  32.304 34.707 32.328 34.795 ;
     RECT  13.104 33.579 13.512 34.799 ;
     RECT  64.992 34.155 65.016 34.835 ;
     RECT  12.528 34.799 13.512 34.837 ;
     RECT  16.896 32.939 19.848 34.847 ;
     RECT  31.104 33.541 31.128 34.869 ;
     RECT  12.432 34.837 13.512 34.923 ;
     RECT  43.92 34.789 44.04 34.923 ;
     RECT  16.896 34.847 19.992 34.931 ;
     RECT  67.104 34.741 68.952 34.931 ;
     RECT  22.8 33.827 22.824 34.979 ;
     RECT  40.2 30.803 40.512 34.981 ;
     RECT  31.104 34.869 31.704 35.171 ;
     RECT  40.2 34.981 41.208 35.171 ;
     RECT  72.48 34.789 72.912 35.267 ;
     RECT  72.6 35.267 72.912 35.269 ;
     RECT  31.104 35.171 31.128 35.315 ;
     RECT  42.72 34.869 42.744 35.363 ;
     RECT  45.168 33.251 46.104 35.363 ;
     RECT  63.168 34.741 63.192 35.363 ;
     RECT  24 33.827 24.312 35.423 ;
     RECT  74.976 34.597 75 35.445 ;
     RECT  34.8 31.945 35.256 35.459 ;
     RECT  38.928 34.741 38.952 35.459 ;
     RECT  74.208 35.445 75 35.459 ;
     RECT  40.2 35.171 40.512 35.461 ;
     RECT  43.728 35.413 43.752 35.499 ;
     RECT  50.832 34.741 51.912 35.499 ;
     RECT  23.904 35.423 24.312 35.507 ;
     RECT  29.4 32.579 29.928 35.605 ;
     RECT  21.12 34.741 21.144 35.699 ;
     RECT  74.208 35.459 74.232 35.699 ;
     RECT  14.832 34.741 14.856 35.747 ;
     RECT  60.96 33.637 62.112 35.795 ;
     RECT  67.104 34.931 67.512 35.923 ;
     RECT  36.672 33.973 37.416 35.939 ;
     RECT  55.296 32.491 55.32 35.939 ;
     RECT  67.104 35.923 68.088 35.957 ;
     RECT  71.328 34.501 71.352 35.987 ;
     RECT  66.672 35.957 68.088 36.011 ;
     RECT  13.104 34.923 13.512 36.083 ;
     RECT  16.896 34.931 19.848 36.085 ;
     RECT  16.416 36.085 19.848 36.131 ;
     RECT  29.4 35.605 30.84 36.515 ;
     RECT  47.376 34.355 47.4 36.515 ;
     RECT  54.144 35.845 54.168 36.515 ;
     RECT  66.672 36.011 67.848 36.515 ;
     RECT  40.08 35.461 40.512 36.563 ;
     RECT  58.704 36.469 58.728 36.563 ;
     RECT  72.6 35.269 73.032 36.563 ;
     RECT  13.2 36.083 13.512 36.661 ;
     RECT  13.2 36.661 14.376 36.755 ;
     RECT  24 35.507 24.312 36.901 ;
     RECT  50.832 35.499 51.312 36.949 ;
     RECT  45.6 35.363 46.104 36.997 ;
     RECT  56.4 33.107 57 37.043 ;
     RECT  29.4 36.515 29.928 37.045 ;
     RECT  48.336 36.901 48.36 37.091 ;
     RECT  61.584 35.795 62.112 37.093 ;
     RECT  67.2 36.515 67.848 37.267 ;
     RECT  67.2 37.267 68.088 37.355 ;
     RECT  60.288 37.285 60.312 37.427 ;
     RECT  50.736 36.949 51.672 37.429 ;
     RECT  61.584 37.093 62.328 37.475 ;
     RECT  49.008 37.395 49.032 37.483 ;
     RECT  29.28 37.045 29.928 37.535 ;
     RECT  50.16 37.429 51.672 37.571 ;
     RECT  78 34.739 78.312 37.573 ;
     RECT  72.6 36.563 72.912 37.749 ;
     RECT  50.736 37.571 51.672 37.763 ;
     RECT  23.28 36.901 24.312 37.859 ;
     RECT  29.088 37.535 29.928 37.861 ;
     RECT  78 37.573 78.888 37.861 ;
     RECT  72.6 37.749 73.176 37.931 ;
     RECT  34.8 35.459 35.208 37.941 ;
     RECT  36.672 35.939 36.696 37.941 ;
     RECT  41.568 37.861 42.168 37.945 ;
     RECT  77.52 37.861 78.888 37.945 ;
     RECT  38.64 37.045 38.664 38.003 ;
     RECT  34.464 37.941 36.696 38.029 ;
     RECT  28.992 37.861 29.928 38.051 ;
     RECT  74.976 37.971 75 38.059 ;
     RECT  76.368 38.005 76.392 38.099 ;
     RECT  16.416 36.131 19.32 38.101 ;
     RECT  42.144 37.945 42.168 38.133 ;
     RECT  43.152 37.573 43.176 38.133 ;
     RECT  15.936 38.101 19.32 38.187 ;
     RECT  42.144 38.133 43.176 38.187 ;
     RECT  0.096 38.197 0.12 38.291 ;
     RECT  48.96 38.197 48.984 38.291 ;
     RECT  64.704 38.197 64.728 38.291 ;
     RECT  29.28 38.051 29.928 38.387 ;
     RECT  6.576 27.155 6.6 38.581 ;
     RECT  45.6 36.997 46.632 38.581 ;
     RECT  7.8 33.579 8.376 38.629 ;
     RECT  43.872 38.581 43.896 38.665 ;
     RECT  45.024 38.581 46.632 38.665 ;
     RECT  7.8 38.629 9.144 38.713 ;
     RECT  2.4 30.947 2.712 38.725 ;
     RECT  34.8 38.029 36.696 38.725 ;
     RECT  13.2 36.755 13.512 38.773 ;
     RECT  42.816 38.187 42.84 38.819 ;
     RECT  78 37.945 78.888 38.819 ;
     RECT  4.464 38.773 4.488 38.867 ;
     RECT  34.8 38.725 37.08 38.917 ;
     RECT  45.6 38.665 46.632 39.011 ;
     RECT  54.576 38.773 54.6 39.011 ;
     RECT  13.2 38.773 13.656 39.061 ;
     RECT  74.352 39.061 74.376 39.147 ;
     RECT  75.648 39.061 75.672 39.147 ;
     RECT  34.8 38.917 37.272 39.155 ;
     RECT  2.4 38.725 3.432 39.413 ;
     RECT  56.4 37.043 56.904 39.541 ;
     RECT  33.744 39.349 33.768 39.587 ;
     RECT  50.736 37.763 51.312 39.589 ;
     RECT  78 38.819 78.312 39.589 ;
     RECT  2.4 39.413 4.008 39.635 ;
     RECT  48.96 39.589 48.984 39.673 ;
     RECT  50.16 39.589 51.312 39.673 ;
     RECT  29.4 38.387 29.928 39.779 ;
     RECT  34.8 39.155 37.08 39.787 ;
     RECT  24 37.859 24.312 39.829 ;
     RECT  77.904 39.589 78.312 39.839 ;
     RECT  77.904 39.839 78.696 39.915 ;
     RECT  3.984 39.635 4.008 39.923 ;
     RECT  5.808 38.581 6.6 39.923 ;
     RECT  32.544 38.725 32.568 39.923 ;
     RECT  78 39.915 78.696 39.923 ;
     RECT  72.6 37.931 72.912 39.925 ;
     RECT  73.92 39.925 73.944 40.019 ;
     RECT  75.12 39.925 75.144 40.019 ;
     RECT  45.6 39.011 46.2 40.067 ;
     RECT  44.208 39.877 44.232 40.165 ;
     RECT  71.856 39.925 72.912 40.259 ;
     RECT  23.76 39.829 24.312 40.355 ;
     RECT  27.36 38.197 27.384 40.499 ;
     RECT  43.344 40.165 44.232 40.499 ;
     RECT  59.856 39.877 59.88 40.499 ;
     RECT  76.368 39.861 76.392 40.499 ;
     RECT  13.104 39.061 13.656 40.597 ;
     RECT  7.8 38.713 8.376 40.837 ;
     RECT  34.8 39.787 37.032 40.875 ;
     RECT  25.632 40.799 25.656 40.883 ;
     RECT  7.8 40.837 9.144 40.979 ;
     RECT  43.344 40.499 43.368 41.027 ;
     RECT  40.2 36.563 40.512 41.077 ;
     RECT  24 40.355 24.312 41.365 ;
     RECT  76.032 41.365 76.056 41.397 ;
     RECT  7.8 40.979 8.376 41.411 ;
     RECT  29.4 39.779 29.712 41.413 ;
     RECT  40.2 41.077 41.304 41.451 ;
     RECT  74.256 41.365 74.28 41.451 ;
     RECT  75.312 41.397 76.056 41.451 ;
     RECT  45.6 40.067 46.104 41.567 ;
     RECT  67.2 37.355 67.512 41.619 ;
     RECT  44.88 41.567 46.104 41.651 ;
     RECT  47.856 41.221 47.88 41.651 ;
     RECT  67.104 41.619 67.512 41.653 ;
     RECT  67.104 41.653 68.28 41.707 ;
     RECT  61.584 37.475 62.112 41.749 ;
     RECT  66 41.653 66.024 41.891 ;
     RECT  24 41.365 24.504 41.893 ;
     RECT  23.904 41.893 25.128 41.977 ;
     RECT  28.464 41.413 29.712 41.989 ;
     RECT  56.064 39.541 56.904 41.989 ;
     RECT  0.096 41.951 0.12 42.035 ;
     RECT  10.176 37.573 10.2 42.037 ;
     RECT  47.76 41.941 47.784 42.083 ;
     RECT  56.064 41.989 57 42.227 ;
     RECT  75.312 41.451 75.336 42.227 ;
     RECT  50.352 39.673 51.312 42.277 ;
     RECT  33.072 41.461 33.096 42.421 ;
     RECT  34.8 40.875 35.208 42.565 ;
     RECT  36.576 40.875 37.032 42.565 ;
     RECT  7.8 41.411 8.112 42.677 ;
     RECT  61.536 41.749 62.112 42.677 ;
     RECT  10.08 42.037 10.2 42.709 ;
     RECT  52.944 33.589 52.968 42.709 ;
     RECT  72.6 40.259 72.912 42.709 ;
     RECT  59.616 42.565 59.64 42.731 ;
     RECT  28.416 41.989 29.712 42.739 ;
     RECT  13.008 40.597 13.656 42.755 ;
     RECT  34.8 42.565 37.032 42.757 ;
     RECT  7.8 42.677 8.232 42.765 ;
     RECT  60.72 42.677 62.112 42.765 ;
     RECT  52.56 42.709 53.016 42.795 ;
     RECT  33.072 42.421 33.672 42.805 ;
     RECT  40.2 41.451 40.512 42.805 ;
     RECT  28.464 42.739 29.712 42.851 ;
     RECT  32.448 42.805 33.672 42.889 ;
     RECT  32.88 42.889 33.672 42.899 ;
     RECT  61.536 42.765 62.112 42.899 ;
     RECT  67.2 41.707 68.28 42.899 ;
     RECT  71.856 42.709 72.912 42.933 ;
     RECT  71.088 42.933 72.912 42.987 ;
     RECT  71.088 42.987 71.112 43.021 ;
     RECT  13.056 42.755 13.656 43.043 ;
     RECT  72.192 42.987 72.912 43.141 ;
     RECT  24 41.977 24.504 43.237 ;
     RECT  56.064 42.227 56.904 43.237 ;
     RECT  26.16 43.155 26.184 43.243 ;
     RECT  27.36 43.189 27.384 43.283 ;
     RECT  64.944 42.709 64.968 43.285 ;
     RECT  28.896 42.851 29.712 43.307 ;
     RECT  64.944 43.285 65.592 43.307 ;
     RECT  67.2 42.899 68.136 43.307 ;
     RECT  72.192 43.141 73.704 43.307 ;
     RECT  23.904 43.237 24.504 43.321 ;
     RECT  56.064 43.237 57.624 43.321 ;
     RECT  34.8 42.757 37.512 43.347 ;
     RECT  6.576 39.923 6.6 43.379 ;
     RECT  34.8 43.347 37.656 43.435 ;
     RECT  16.416 38.187 19.32 43.571 ;
     RECT  32.88 42.899 32.904 43.571 ;
     RECT  34.8 43.435 37.032 43.571 ;
     RECT  61.584 42.899 62.112 43.669 ;
     RECT  50.352 42.277 51.432 43.717 ;
     RECT  52.56 42.795 52.968 43.717 ;
     RECT  78 39.923 78.312 43.717 ;
     RECT  48.096 43.573 48.12 43.763 ;
     RECT  17.856 43.571 19.32 43.859 ;
     RECT  4.032 43.285 4.056 43.907 ;
     RECT  24 43.321 24.504 43.907 ;
     RECT  7.8 42.765 8.112 43.909 ;
     RECT  10.08 42.709 10.248 43.909 ;
     RECT  11.424 38.005 11.448 43.909 ;
     RECT  43.344 43.381 43.368 43.909 ;
     RECT  50.352 43.717 52.968 43.909 ;
     RECT  40.08 42.805 40.512 43.955 ;
     RECT  40.2 43.955 40.512 44.005 ;
     RECT  22.416 43.333 22.44 44.099 ;
     RECT  26.352 44.053 26.376 44.101 ;
     RECT  45.6 41.651 46.104 44.149 ;
     RECT  39.12 44.053 39.144 44.195 ;
     RECT  40.2 44.005 41.4 44.195 ;
     RECT  13.104 43.043 13.656 44.245 ;
     RECT  26.352 44.101 26.808 44.291 ;
     RECT  13.104 44.245 13.944 44.331 ;
     RECT  10.08 43.909 11.448 44.389 ;
     RECT  65.568 43.307 65.592 44.469 ;
     RECT  64.704 44.469 65.592 44.523 ;
     RECT  7.152 43.909 8.112 44.629 ;
     RECT  24 43.907 24.456 44.723 ;
     RECT  64.704 44.523 64.728 44.867 ;
     RECT  7.152 44.629 8.376 44.915 ;
     RECT  40.2 44.195 41.016 44.915 ;
     RECT  48.288 44.853 48.312 44.941 ;
     RECT  42.72 43.909 43.368 44.963 ;
     RECT  50.352 43.909 53.4 44.965 ;
     RECT  45.6 44.149 46.44 45.011 ;
     RECT  36.576 43.571 37.032 45.013 ;
     RECT  42.72 44.963 42.744 45.107 ;
     RECT  2.4 39.635 2.712 45.301 ;
     RECT  45.6 45.011 46.104 45.301 ;
     RECT  9.696 44.389 11.448 45.347 ;
     RECT  43.776 45.253 43.8 45.355 ;
     RECT  45.024 45.301 46.104 45.395 ;
     RECT  50.352 44.965 53.592 45.491 ;
     RECT  18.6 43.859 19.32 45.599 ;
     RECT  68.64 45.157 68.664 45.599 ;
     RECT  72.192 43.307 72.912 45.599 ;
     RECT  2.4 45.301 3.48 45.611 ;
     RECT  67.2 43.307 67.512 45.621 ;
     RECT  68.64 45.599 69.576 45.621 ;
     RECT  39.024 44.485 39.048 45.635 ;
     RECT  66.864 45.621 69.576 45.675 ;
     RECT  18.6 45.599 19.416 45.683 ;
     RECT  52.656 45.491 53.592 45.683 ;
     RECT  69.552 45.675 69.576 45.683 ;
     RECT  71.808 45.599 72.912 45.683 ;
     RECT  7.8 44.915 8.376 45.685 ;
     RECT  76.368 44.773 76.392 45.685 ;
     RECT  78 43.717 78.648 45.685 ;
     RECT  66.864 45.675 68.232 45.709 ;
     RECT  76.368 45.685 78.696 45.739 ;
     RECT  7.8 45.685 8.568 45.769 ;
     RECT  77.232 45.739 78.696 45.769 ;
     RECT  24 44.723 24.312 45.781 ;
     RECT  77.232 45.769 78.648 45.923 ;
     RECT  26.784 44.291 26.808 46.069 ;
     RECT  28.272 45.013 28.296 46.069 ;
     RECT  32.784 43.909 32.808 46.069 ;
     RECT  24 45.781 24.408 46.197 ;
     RECT  61.584 43.669 63 46.211 ;
     RECT  72.6 45.683 72.912 46.261 ;
     RECT  23.04 46.197 24.408 46.285 ;
     RECT  74.688 46.117 74.712 46.315 ;
     RECT  26.784 46.069 28.296 46.355 ;
     RECT  36.576 45.013 37.56 46.355 ;
     RECT  29.4 43.307 29.712 46.357 ;
     RECT  64.416 46.261 64.44 46.451 ;
     RECT  72.6 46.261 73.416 46.499 ;
     RECT  26.784 46.355 28.2 46.547 ;
     RECT  52.656 45.683 53.4 46.645 ;
     RECT  40.2 44.915 40.512 46.728 ;
     RECT  24 46.285 24.408 46.835 ;
     RECT  34.8 43.571 35.208 46.835 ;
     RECT  36.576 46.355 37.224 46.861 ;
     RECT  16.416 43.571 16.44 46.933 ;
     RECT  29.4 46.357 29.832 47.029 ;
     RECT  52.656 46.645 53.592 47.075 ;
     RECT  27.408 46.547 28.2 47.083 ;
     RECT  10.08 45.347 11.448 47.221 ;
     RECT  13.104 44.331 13.656 47.221 ;
     RECT  10.08 47.221 11.592 47.315 ;
     RECT  10.08 47.315 10.248 47.317 ;
     RECT  29.28 47.029 29.832 47.339 ;
     RECT  52.944 47.075 53.592 47.363 ;
     RECT  30.816 47.285 30.84 47.373 ;
     RECT  29.28 47.339 29.712 47.443 ;
     RECT  67.2 45.709 68.232 47.555 ;
     RECT  13.104 47.221 13.944 47.659 ;
     RECT  32.064 46.069 32.808 47.747 ;
     RECT  13.104 47.659 13.704 47.749 ;
     RECT  39.312 46.728 40.512 47.795 ;
     RECT  74.064 47.733 74.952 47.821 ;
     RECT  74.928 47.821 74.952 47.843 ;
     RECT  12.768 47.749 13.704 47.851 ;
     RECT  43.92 47.461 43.944 47.855 ;
     RECT  61.632 46.211 63 47.855 ;
     RECT  29.04 47.443 29.712 47.881 ;
     RECT  9.36 47.317 10.248 47.891 ;
     RECT  32.784 47.747 32.808 47.891 ;
     RECT  7.8 45.769 8.112 47.893 ;
     RECT  30.912 47.477 30.936 47.904 ;
     RECT  43.92 47.855 44.184 47.939 ;
     RECT  61.632 47.855 63.288 47.939 ;
     RECT  36.576 46.861 36.936 47.989 ;
     RECT  7.68 47.893 8.112 48.083 ;
     RECT  56.064 43.321 56.904 48.085 ;
     RECT  24 46.835 24.312 48.095 ;
     RECT  45.6 45.395 46.104 48.095 ;
     RECT  18.6 45.683 19.32 48.131 ;
     RECT  56.064 48.085 57.624 48.171 ;
     RECT  24 48.095 24.504 48.179 ;
     RECT  45.024 48.095 46.776 48.179 ;
     RECT  40.2 47.795 40.512 48.339 ;
     RECT  43.92 47.939 43.944 48.371 ;
     RECT  40.2 48.339 41.352 48.427 ;
     RECT  56.064 48.171 56.904 48.467 ;
     RECT  36.576 47.989 37.032 48.469 ;
     RECT  5.232 48.431 5.256 48.515 ;
     RECT  42.72 48.373 42.744 48.515 ;
     RECT  67.2 47.555 67.512 48.629 ;
     RECT  68.832 48.595 68.856 48.683 ;
     RECT  13.104 47.851 13.704 48.707 ;
     RECT  61.632 47.939 62.712 48.755 ;
     RECT  66.384 48.629 67.512 48.787 ;
     RECT  61.632 48.755 62.568 48.803 ;
     RECT  66.384 48.787 68.424 48.875 ;
     RECT  13.104 48.707 13.656 48.901 ;
     RECT  29.4 47.881 29.712 48.901 ;
     RECT  10.08 47.891 10.248 48.949 ;
     RECT  40.2 48.427 40.872 48.949 ;
     RECT  16.08 46.933 16.44 48.997 ;
     RECT  39.84 48.949 40.872 49.003 ;
     RECT  16.08 48.997 17.064 49.013 ;
     RECT  13.056 48.901 13.656 49.043 ;
     RECT  28.944 48.901 29.712 49.043 ;
     RECT  39.84 49.003 40.512 49.043 ;
     RECT  27.36 47.845 27.384 49.091 ;
     RECT  31.872 48.949 32.424 49.091 ;
     RECT  66.384 48.875 67.512 49.091 ;
     RECT  16.08 49.013 17.544 49.101 ;
     RECT  16.08 49.101 17.064 49.139 ;
     RECT  32.4 49.091 32.424 49.139 ;
     RECT  36.576 48.469 37.08 49.141 ;
     RECT  56.4 48.467 56.904 49.171 ;
     RECT  36.576 49.141 37.656 49.259 ;
     RECT  56.4 49.171 57.816 49.259 ;
     RECT  7.8 48.083 8.112 49.391 ;
     RECT  7.8 49.391 8.232 49.475 ;
     RECT  45.024 48.179 46.104 49.525 ;
     RECT  45.024 49.525 46.248 49.571 ;
     RECT  25.68 48.949 25.704 49.619 ;
     RECT  47.904 48.997 47.928 49.763 ;
     RECT  24 48.179 24.312 49.765 ;
     RECT  36.576 49.259 36.84 50.003 ;
     RECT  29.4 49.043 29.712 50.005 ;
     RECT  64.992 48.901 65.016 50.041 ;
     RECT  63.792 49.967 63.816 50.051 ;
     RECT  75.84 49.967 75.864 50.051 ;
     RECT  78 45.923 78.648 50.051 ;
     RECT  29.4 50.005 30.696 50.147 ;
     RECT  33.6 48.949 33.624 50.165 ;
     RECT  45.6 49.571 46.248 50.195 ;
     RECT  32.592 50.101 32.616 50.219 ;
     RECT  33.6 50.165 33.816 50.219 ;
     RECT  31.296 50.159 31.32 50.243 ;
     RECT  18.6 48.131 19.224 50.293 ;
     RECT  33.792 50.219 33.816 50.293 ;
     RECT  34.8 46.835 35.112 50.293 ;
     RECT  67.2 49.091 67.512 50.293 ;
     RECT  68.976 50.293 69 50.377 ;
     RECT  38.112 50.293 38.136 50.387 ;
     RECT  9.744 48.949 10.248 50.389 ;
     RECT  24 49.765 24.456 50.483 ;
     RECT  33.792 50.293 35.112 50.531 ;
     RECT  56.4 49.259 56.904 50.643 ;
     RECT  50.352 45.491 51.672 50.677 ;
     RECT  55.824 50.643 57.096 50.731 ;
     RECT  6.48 47.893 6.504 50.771 ;
     RECT  36.576 50.003 36.6 50.771 ;
     RECT  45.6 50.195 46.104 50.771 ;
     RECT  53.952 50.735 53.976 50.819 ;
     RECT  7.8 49.475 8.112 50.965 ;
     RECT  18.336 50.293 19.224 50.965 ;
     RECT  72.6 46.499 72.912 50.965 ;
     RECT  7.68 50.965 8.112 51.051 ;
     RECT  29.4 50.147 29.712 51.253 ;
     RECT  50.352 50.677 51.864 51.253 ;
     RECT  52.944 47.363 52.968 51.253 ;
     RECT  67.2 50.293 67.608 51.347 ;
     RECT  34.8 50.531 35.112 51.493 ;
     RECT  18.336 50.965 19.992 51.627 ;
     RECT  34.512 51.493 35.112 51.627 ;
     RECT  47.808 51.637 47.832 51.721 ;
     RECT  9.504 50.389 10.248 51.779 ;
     RECT  24 50.483 24.312 51.877 ;
     RECT  7.8 51.051 8.112 51.925 ;
     RECT  72.048 50.965 72.912 52.067 ;
     RECT  50.352 51.253 52.968 52.069 ;
     RECT  74.64 52.069 74.664 52.117 ;
     RECT  74.16 52.117 74.664 52.203 ;
     RECT  34.8 51.627 35.112 52.309 ;
     RECT  37.056 52.357 37.08 52.371 ;
     RECT  29.4 51.253 30.456 52.403 ;
     RECT  13.2 49.043 13.656 52.405 ;
     RECT  18.336 51.627 19.224 52.405 ;
     RECT  37.056 52.371 37.848 52.405 ;
     RECT  34.8 52.309 35.928 52.459 ;
     RECT  37.056 52.405 38.808 52.459 ;
     RECT  17.472 52.405 19.224 52.489 ;
     RECT  37.872 52.459 38.808 52.499 ;
     RECT  44.208 51.493 44.232 52.499 ;
     RECT  17.76 52.489 19.224 52.523 ;
     RECT  26.976 52.463 27 52.547 ;
     RECT  50.304 52.069 52.968 52.597 ;
     RECT  49.776 52.597 52.968 52.691 ;
     RECT  7.8 51.925 8.28 52.739 ;
     RECT  13.104 52.405 13.656 52.883 ;
     RECT  76.944 52.405 76.968 52.917 ;
     RECT  76.032 52.917 76.968 52.971 ;
     RECT  74.64 52.203 74.664 52.979 ;
     RECT  34.8 52.459 35.208 52.981 ;
     RECT  67.2 51.347 67.512 52.981 ;
     RECT  76.032 52.971 76.056 53.005 ;
     RECT  29.4 52.403 29.832 53.027 ;
     RECT  37.872 52.499 37.896 53.027 ;
     RECT  34.176 52.981 35.208 53.035 ;
     RECT  70.896 52.981 70.92 53.065 ;
     RECT  34.176 53.035 35.112 53.075 ;
     RECT  48.048 52.453 48.072 53.075 ;
     RECT  0.096 52.789 0.12 53.163 ;
     RECT  23.568 51.877 24.312 53.267 ;
     RECT  2.4 45.611 2.712 53.365 ;
     RECT  56.4 50.731 56.904 53.365 ;
     RECT  54.816 51.205 54.84 53.493 ;
     RECT  56.256 53.365 56.904 53.507 ;
     RECT  13.2 52.883 13.656 53.557 ;
     RECT  14.928 37.429 14.952 53.557 ;
     RECT  53.952 53.493 54.84 53.581 ;
     RECT  36.24 52.933 36.264 53.603 ;
     RECT  67.008 52.981 67.512 53.603 ;
     RECT  24 53.267 24.312 53.685 ;
     RECT  24 53.685 25.032 53.795 ;
     RECT  54.816 53.581 54.84 53.795 ;
     RECT  2.4 53.365 2.856 53.941 ;
     RECT  50.304 52.691 52.968 54.069 ;
     RECT  67.2 53.603 67.512 54.085 ;
     RECT  64.368 54.037 64.392 54.123 ;
     RECT  2.4 53.941 3.528 54.275 ;
     RECT  10.08 51.779 10.248 54.421 ;
     RECT  50.112 54.069 52.968 54.469 ;
     RECT  7.8 52.739 8.112 54.517 ;
     RECT  47.808 54.469 47.832 54.517 ;
     RECT  49.584 54.469 52.968 54.517 ;
     RECT  29.4 53.027 29.712 54.547 ;
     RECT  32.112 54.133 32.136 54.547 ;
     RECT  56.4 53.507 56.904 54.565 ;
     RECT  47.232 54.517 47.832 54.571 ;
     RECT  48.96 54.517 52.968 54.571 ;
     RECT  26.208 53.509 26.232 54.611 ;
     RECT  29.4 54.547 30.552 54.635 ;
     RECT  31.632 54.547 32.808 54.635 ;
     RECT  11.424 47.315 11.592 54.645 ;
     RECT  13.2 53.557 14.952 54.645 ;
     RECT  56.4 54.565 57.624 54.649 ;
     RECT  50.064 54.571 52.968 54.661 ;
     RECT  11.424 54.645 14.952 54.707 ;
     RECT  11.424 54.707 13.656 54.733 ;
     RECT  61.632 48.803 62.112 54.853 ;
     RECT  67.2 54.085 67.656 54.867 ;
     RECT  48.96 54.571 48.984 54.899 ;
     RECT  9.984 54.421 10.248 54.901 ;
     RECT  61.632 54.853 62.76 54.931 ;
     RECT  32.112 54.635 32.232 54.947 ;
     RECT  61.296 54.931 62.76 55.019 ;
     RECT  43.392 55.045 43.416 55.147 ;
     RECT  34.8 53.075 35.112 55.237 ;
     RECT  66.432 54.867 67.656 55.237 ;
     RECT  66.144 55.237 67.656 55.275 ;
     RECT  2.4 54.275 2.856 55.333 ;
     RECT  34.8 55.237 35.4 55.339 ;
     RECT  47.232 54.571 47.256 55.379 ;
     RECT  9.744 54.901 10.248 55.381 ;
     RECT  66.144 55.275 67.512 55.427 ;
     RECT  2.4 55.333 3.816 55.535 ;
     RECT  50.064 54.661 53.592 55.595 ;
     RECT  2.4 55.535 3.96 55.619 ;
     RECT  13.2 54.733 13.656 55.765 ;
     RECT  56.4 54.649 56.904 55.813 ;
     RECT  13.056 55.765 13.656 55.851 ;
     RECT  5.136 55.775 5.16 55.859 ;
     RECT  29.4 54.635 29.712 55.861 ;
     RECT  30.72 55.525 30.744 55.861 ;
     RECT  7.8 54.517 8.664 55.907 ;
     RECT  29.4 55.861 30.744 55.907 ;
     RECT  61.632 55.019 62.616 55.907 ;
     RECT  33.648 55.237 33.672 55.955 ;
     RECT  66.48 55.427 67.512 55.955 ;
     RECT  40.2 49.043 40.512 55.957 ;
     RECT  66.672 55.955 67.512 56.051 ;
     RECT  9.744 55.381 10.344 56.099 ;
     RECT  61.632 55.907 62.112 56.111 ;
     RECT  50.304 55.595 53.592 56.149 ;
     RECT  38.688 56.083 38.712 56.171 ;
     RECT  61.536 56.111 62.112 56.195 ;
     RECT  13.2 55.851 13.656 56.341 ;
     RECT  24 53.795 24.312 56.341 ;
     RECT  56.4 55.813 57 56.389 ;
     RECT  23.904 56.341 24.312 56.427 ;
     RECT  32.208 54.947 32.232 56.483 ;
     RECT  45.6 50.771 45.912 56.485 ;
     RECT  18.6 52.523 19.224 56.495 ;
     RECT  47.76 56.467 47.784 56.501 ;
     RECT  9.984 56.099 10.344 56.531 ;
     RECT  47.04 56.501 47.784 56.555 ;
     RECT  45.504 56.485 45.912 56.569 ;
     RECT  18.6 56.495 19.992 56.579 ;
     RECT  56.064 56.389 57 56.723 ;
     RECT  67.2 56.051 67.512 56.869 ;
     RECT  0.096 56.821 0.12 56.915 ;
     RECT  50.304 56.149 53.784 56.915 ;
     RECT  13.2 56.341 13.704 57.011 ;
     RECT  56.064 56.723 56.904 57.011 ;
     RECT  71.328 56.341 71.352 57.011 ;
     RECT  67.2 56.869 67.608 57.013 ;
     RECT  2.4 55.619 3.816 57.059 ;
     RECT  9.984 56.531 10.248 57.059 ;
     RECT  26.208 57.013 26.232 57.097 ;
     RECT  67.2 57.013 67.704 57.097 ;
     RECT  61.584 56.195 62.112 57.155 ;
     RECT  67.2 57.097 67.608 57.539 ;
     RECT  67.2 57.539 67.512 57.589 ;
     RECT  27.216 57.205 27.24 57.643 ;
     RECT  47.04 56.555 47.064 57.827 ;
     RECT  18.6 56.579 19.368 57.875 ;
     RECT  7.8 55.907 8.112 57.973 ;
     RECT  7.44 57.973 8.112 58.057 ;
     RECT  50.304 56.915 52.872 58.069 ;
     RECT  9.984 57.059 10.2 58.117 ;
     RECT  11.424 54.733 11.592 58.117 ;
     RECT  56.4 57.011 56.904 58.117 ;
     RECT  48.432 58.069 48.456 58.155 ;
     RECT  50.304 58.069 53.064 58.155 ;
     RECT  72.6 52.067 72.912 58.165 ;
     RECT  18.6 57.875 19.224 58.259 ;
     RECT  72.432 58.165 72.912 58.259 ;
     RECT  40.08 55.957 40.512 58.501 ;
     RECT  2.4 57.059 2.856 58.645 ;
     RECT  6 57.939 6.024 58.645 ;
     RECT  40.032 58.501 40.512 58.667 ;
     RECT  41.616 58.597 41.64 58.681 ;
     RECT  64.272 58.117 64.296 58.739 ;
     RECT  24 56.427 24.312 58.741 ;
     RECT  5.088 58.645 6.024 58.835 ;
     RECT  24 58.741 25.128 58.835 ;
     RECT  9.984 58.117 11.592 58.931 ;
     RECT  40.08 58.667 40.512 59.029 ;
     RECT  56.4 58.117 57.096 59.123 ;
     RECT  44.544 59.077 44.568 59.173 ;
     RECT  2.4 58.645 3.288 59.219 ;
     RECT  5.088 58.835 5.112 59.219 ;
     RECT  10.08 58.931 11.592 59.219 ;
     RECT  44.448 59.173 44.568 59.221 ;
     RECT  45.6 56.569 45.912 59.221 ;
     RECT  16.08 49.139 16.44 59.231 ;
     RECT  44.448 59.221 45.912 59.231 ;
     RECT  40.08 59.029 40.632 59.267 ;
     RECT  43.488 59.231 45.912 59.307 ;
     RECT  16.08 59.231 16.68 59.315 ;
     RECT  21.168 58.021 21.192 59.315 ;
     RECT  43.488 59.307 43.512 59.315 ;
     RECT  50.304 58.155 52.968 59.315 ;
     RECT  74.256 58.645 74.28 59.315 ;
     RECT  70.992 57.493 71.016 59.459 ;
     RECT  16.08 59.315 16.44 59.605 ;
     RECT  56.4 59.123 57 59.605 ;
     RECT  27.36 59.605 27.384 59.691 ;
     RECT  26.208 59.615 26.232 59.699 ;
     RECT  15.984 59.605 16.44 59.747 ;
     RECT  67.008 57.589 67.512 59.747 ;
     RECT  2.4 59.219 2.856 59.749 ;
     RECT  29.4 55.907 30.552 59.819 ;
     RECT  14.928 54.707 14.952 59.891 ;
     RECT  29.4 59.819 30.264 59.891 ;
     RECT  36.288 59.029 36.312 59.891 ;
     RECT  55.824 59.605 57 59.891 ;
     RECT  70.8 59.461 70.824 59.891 ;
     RECT  33.168 59.701 33.192 60.085 ;
     RECT  34.8 55.339 35.256 60.085 ;
     RECT  33.024 60.085 35.256 60.169 ;
     RECT  60.384 60.133 60.408 60.217 ;
     RECT  63.264 60.133 63.288 60.217 ;
     RECT  40.08 59.267 40.512 60.243 ;
     RECT  33.888 60.169 35.256 60.275 ;
     RECT  39.12 60.243 40.512 60.331 ;
     RECT  37.584 60.277 37.608 60.361 ;
     RECT  58.944 59.221 58.968 60.419 ;
     RECT  63.696 60.383 63.72 60.467 ;
     RECT  0.096 60.527 0.12 60.611 ;
     RECT  72.6 58.259 72.912 60.627 ;
     RECT  72.096 60.627 72.912 60.715 ;
     RECT  74.112 60.661 74.136 60.755 ;
     RECT  11.424 59.219 11.592 60.767 ;
     RECT  13.2 57.011 13.656 60.767 ;
     RECT  4.8 60.373 4.824 60.805 ;
     RECT  11.424 60.767 14.28 60.851 ;
     RECT  45.6 59.307 45.912 60.949 ;
     RECT  46.896 60.883 46.92 60.949 ;
     RECT  45.6 60.949 46.92 60.971 ;
     RECT  18.6 58.259 19.128 61.043 ;
     RECT  29.4 59.891 29.712 61.189 ;
     RECT  34.8 60.275 35.256 61.295 ;
     RECT  34.704 61.295 35.256 61.301 ;
     RECT  7.8 58.057 8.112 61.333 ;
     RECT  34.704 61.301 36.024 61.379 ;
     RECT  16.08 59.747 16.44 61.381 ;
     RECT  34.8 61.379 36.024 61.389 ;
     RECT  7.8 61.333 8.328 61.419 ;
     RECT  39.936 60.331 40.512 61.459 ;
     RECT  13.2 60.851 14.28 61.477 ;
     RECT  16.08 61.381 17.016 61.547 ;
     RECT  39.312 61.459 40.512 61.547 ;
     RECT  13.2 61.477 14.808 61.561 ;
     RECT  11.424 60.851 11.976 61.571 ;
     RECT  32.352 60.517 32.376 61.571 ;
     RECT  13.2 61.561 14.28 61.619 ;
     RECT  45.6 60.971 46.728 61.619 ;
     RECT  55.824 59.891 56.856 61.619 ;
     RECT  13.2 61.619 13.656 61.811 ;
     RECT  18.6 61.043 18.912 61.861 ;
     RECT  33.648 61.237 33.672 61.931 ;
     RECT  17.664 61.861 18.912 61.945 ;
     RECT  29.4 61.189 30.072 62.051 ;
     RECT  16.08 61.547 16.44 62.195 ;
     RECT  63.264 61.525 63.288 62.195 ;
     RECT  32.496 61.813 32.52 62.293 ;
     RECT  32.496 62.293 32.856 62.339 ;
     RECT  39.936 61.547 40.512 62.389 ;
     RECT  7.8 61.419 8.112 62.437 ;
     RECT  27.744 62.341 27.768 62.437 ;
     RECT  38.784 62.341 38.808 62.443 ;
     RECT  24 58.835 24.312 62.453 ;
     RECT  39.936 62.389 40.632 62.483 ;
     RECT  27.744 62.437 27.864 62.521 ;
     RECT  37.104 62.437 37.128 62.521 ;
     RECT  23.04 62.453 24.312 62.579 ;
     RECT  68.928 62.101 68.952 62.579 ;
     RECT  4.8 60.805 5.064 62.629 ;
     RECT  44.112 62.453 44.136 62.675 ;
     RECT  27.744 62.521 27.768 62.677 ;
     RECT  10.08 59.219 10.2 62.723 ;
     RECT  34.8 61.389 35.256 62.773 ;
     RECT  7.8 62.437 8.232 62.819 ;
     RECT  22.032 62.101 22.056 63.011 ;
     RECT  26.832 62.677 27.768 63.019 ;
     RECT  25.68 62.437 25.704 63.109 ;
     RECT  60.384 61.525 60.408 63.251 ;
     RECT  2.304 59.749 2.856 63.253 ;
     RECT  45.6 61.619 46.104 63.253 ;
     RECT  48.624 62.453 48.648 63.275 ;
     RECT  25.68 63.109 26.232 63.299 ;
     RECT  58.656 63.253 58.68 63.339 ;
     RECT  14.784 63.205 14.808 63.413 ;
     RECT  16.08 62.195 16.104 63.413 ;
     RECT  50.304 59.315 52.632 63.443 ;
     RECT  14.784 63.413 16.104 63.467 ;
     RECT  15.504 63.467 16.104 63.501 ;
     RECT  52.464 63.443 52.632 63.589 ;
     RECT  2.304 63.253 2.952 63.685 ;
     RECT  3.984 62.629 5.064 63.685 ;
     RECT  13.2 61.811 13.512 63.685 ;
     RECT  32.832 62.339 32.856 63.763 ;
     RECT  67.2 59.747 67.512 63.763 ;
     RECT  13.2 63.685 13.8 63.787 ;
     RECT  32.832 63.763 33.432 63.829 ;
     RECT  2.304 63.685 5.064 63.851 ;
     RECT  32.016 63.829 33.432 63.851 ;
     RECT  37.536 63.763 37.56 63.851 ;
     RECT  67.104 63.763 67.512 63.851 ;
     RECT  38.784 63.781 38.808 63.865 ;
     RECT  32.016 63.851 33.192 63.875 ;
     RECT  45.6 63.253 47.064 63.923 ;
     RECT  64.176 63.925 64.2 63.989 ;
     RECT  18.6 61.945 18.912 64.165 ;
     RECT  65.52 64.083 65.544 64.171 ;
     RECT  20.304 62.581 20.328 64.211 ;
     RECT  0.096 64.213 0.12 64.299 ;
     RECT  52.464 63.589 53.112 64.309 ;
     RECT  67.2 63.851 67.512 64.357 ;
     RECT  52.464 64.309 53.592 64.393 ;
     RECT  2.304 63.851 2.952 64.403 ;
     RECT  52.464 64.393 52.728 64.403 ;
     RECT  7.8 62.819 8.112 64.405 ;
     RECT  13.2 63.787 13.512 64.437 ;
     RECT  2.4 64.403 2.952 64.595 ;
     RECT  67.2 64.357 68.424 64.595 ;
     RECT  67.2 64.595 68.328 64.643 ;
     RECT  2.4 64.595 2.856 64.691 ;
     RECT  4.512 63.851 5.064 64.723 ;
     RECT  58.752 64.693 58.776 64.787 ;
     RECT  4.512 64.723 5.736 64.811 ;
     RECT  4.512 64.811 5.064 64.835 ;
     RECT  11.424 61.571 11.592 64.851 ;
     RECT  13.056 64.437 13.512 64.851 ;
     RECT  42.144 63.493 42.168 64.883 ;
     RECT  38.4 64.821 38.424 64.909 ;
     RECT  18.6 64.165 19.176 64.915 ;
     RECT  33.168 63.875 33.192 64.931 ;
     RECT  18.192 64.915 19.176 64.933 ;
     RECT  64.176 63.989 64.44 64.933 ;
     RECT  72.6 60.715 72.912 64.933 ;
     RECT  11.424 64.851 13.512 64.939 ;
     RECT  25.728 64.851 25.752 64.939 ;
     RECT  39.936 62.483 40.512 64.981 ;
     RECT  16.08 63.501 16.104 65.027 ;
     RECT  56.4 61.619 56.856 65.027 ;
     RECT  32.016 63.875 32.04 65.075 ;
     RECT  64.176 64.933 64.632 65.107 ;
     RECT  63.792 65.107 64.632 65.125 ;
     RECT  21.12 65.077 21.144 65.161 ;
     RECT  2.4 64.691 2.808 65.171 ;
     RECT  17.616 64.933 19.176 65.171 ;
     RECT  54.192 65.077 54.216 65.171 ;
     RECT  63.216 65.125 64.632 65.195 ;
     RECT  7.8 64.405 8.328 65.269 ;
     RECT  10.08 62.723 10.152 65.269 ;
     RECT  4.8 64.835 5.064 65.363 ;
     RECT  31.392 65.269 31.416 65.363 ;
     RECT  66.096 65.365 66.12 65.451 ;
     RECT  67.2 64.643 67.656 65.485 ;
     RECT  24 62.579 24.312 65.509 ;
     RECT  31.152 65.427 31.176 65.515 ;
     RECT  7.8 65.269 10.152 65.579 ;
     RECT  72.096 64.933 72.912 65.603 ;
     RECT  50.304 63.443 51.312 65.619 ;
     RECT  7.8 65.579 8.328 65.651 ;
     RECT  64.608 65.195 64.632 65.699 ;
     RECT  49.536 65.619 51.312 65.707 ;
     RECT  52.464 64.403 52.632 65.797 ;
     RECT  72.6 65.603 72.912 65.893 ;
     RECT  23.04 65.509 24.312 65.941 ;
     RECT  68.64 65.875 68.664 65.963 ;
     RECT  23.04 65.941 24.984 65.973 ;
     RECT  72.6 65.893 73.032 65.977 ;
     RECT  34.8 62.773 35.304 66.003 ;
     RECT  22.08 65.973 24.984 66.027 ;
     RECT  26.208 65.941 26.232 66.027 ;
     RECT  39.504 64.981 40.512 66.035 ;
     RECT  7.8 65.651 8.112 66.037 ;
     RECT  52.464 65.797 52.68 66.037 ;
     RECT  52.464 66.037 53.64 66.091 ;
     RECT  54.768 65.461 55.176 66.091 ;
     RECT  6.576 66.037 8.112 66.121 ;
     RECT  6.576 66.121 6.6 66.131 ;
     RECT  53.616 66.091 53.64 66.227 ;
     RECT  54.768 66.091 55.032 66.229 ;
     RECT  45.6 63.923 46.104 66.323 ;
     RECT  54.72 66.229 55.032 66.371 ;
     RECT  63.216 65.195 63.24 66.467 ;
     RECT  9.648 65.579 10.152 66.515 ;
     RECT  44.352 66.325 44.376 66.667 ;
     RECT  54.768 66.371 55.032 66.707 ;
     RECT  34.8 66.003 36.264 66.719 ;
     RECT  22.08 66.027 22.104 66.755 ;
     RECT  38.784 66.671 38.808 66.755 ;
     RECT  54.768 66.707 54.792 66.755 ;
     RECT  58.608 66.671 58.632 66.755 ;
     RECT  34.8 66.719 37.08 66.803 ;
     RECT  24 66.027 24.984 66.899 ;
     RECT  29.4 62.051 29.712 66.933 ;
     RECT  34.8 66.803 36.744 67.043 ;
     RECT  29.4 66.933 30.12 67.051 ;
     RECT  24 66.899 24.504 67.081 ;
     RECT  61.632 57.155 62.112 67.237 ;
     RECT  10.128 66.515 10.152 67.247 ;
     RECT  11.424 64.939 11.592 67.247 ;
     RECT  7.8 66.121 8.112 67.253 ;
     RECT  18.6 65.171 18.912 67.253 ;
     RECT  39.936 66.035 40.512 67.283 ;
     RECT  30.768 67.189 30.792 67.307 ;
     RECT  44.496 67.253 44.52 67.341 ;
     RECT  18.6 67.253 19.032 67.523 ;
     RECT  36.72 67.043 36.744 67.523 ;
     RECT  7.8 67.253 8.664 67.571 ;
     RECT  56.4 65.027 56.808 67.715 ;
     RECT  50.304 65.707 51.312 67.717 ;
     RECT  45.6 66.323 45.912 67.765 ;
     RECT  47.424 67.333 47.448 67.819 ;
     RECT  50.304 67.717 51.48 67.819 ;
     RECT  4.8 65.363 4.824 67.823 ;
     RECT  33.648 67.765 33.672 67.849 ;
     RECT  64.368 67.765 64.392 67.849 ;
     RECT  15.936 66.661 15.96 67.859 ;
     RECT  4.224 67.823 4.824 67.907 ;
     RECT  43.248 67.823 43.272 67.907 ;
     RECT  52.464 66.091 52.632 67.955 ;
     RECT  0.096 67.957 0.12 68.041 ;
     RECT  31.2 67.829 31.224 68.099 ;
     RECT  60.96 67.237 62.112 68.099 ;
     RECT  43.344 68.341 43.368 68.425 ;
     RECT  4.8 67.907 4.824 68.435 ;
     RECT  42.144 68.341 42.168 68.435 ;
     RECT  32.112 68.533 32.136 68.627 ;
     RECT  45.6 67.765 46.104 68.639 ;
     RECT  45.6 68.639 46.2 68.661 ;
     RECT  10.128 67.247 11.592 68.675 ;
     RECT  54.72 68.629 54.744 68.715 ;
     RECT  22.896 67.717 22.92 68.819 ;
     RECT  18.6 67.523 18.912 68.821 ;
     RECT  18.6 68.821 19.272 68.853 ;
     RECT  18.6 68.853 19.992 68.907 ;
     RECT  61.632 68.099 62.112 68.915 ;
     RECT  7.8 67.571 8.112 68.917 ;
     RECT  34.8 67.043 35.304 68.917 ;
     RECT  67.2 65.485 67.512 68.917 ;
     RECT  28.224 68.883 28.248 68.971 ;
     RECT  7.8 68.917 9.096 69.001 ;
     RECT  34.8 68.917 35.352 69.299 ;
     RECT  19.968 68.907 19.992 69.347 ;
     RECT  63.792 69.301 64.152 69.483 ;
     RECT  45.6 68.661 46.824 69.493 ;
     RECT  65.28 69.429 65.304 69.517 ;
     RECT  30.816 68.917 30.84 69.539 ;
     RECT  34.8 69.299 35.304 69.551 ;
     RECT  22.8 68.917 22.824 69.557 ;
     RECT  45.6 69.493 47.784 69.587 ;
     RECT  50.304 67.819 51.312 69.587 ;
     RECT  66.672 68.917 67.512 69.587 ;
     RECT  22.176 69.557 22.824 69.611 ;
     RECT  34.224 69.551 35.304 69.635 ;
     RECT  24 67.081 24.312 69.941 ;
     RECT  22.176 69.611 22.776 69.971 ;
     RECT  26.064 69.829 26.088 69.995 ;
     RECT  24 69.941 24.408 70.029 ;
     RECT  47.76 69.587 47.784 70.115 ;
     RECT  10.128 68.675 10.152 70.259 ;
     RECT  40.2 67.283 40.512 70.261 ;
     RECT  81.456 70.309 81.48 70.393 ;
     RECT  18.6 68.907 18.912 70.549 ;
     RECT  18.192 70.549 18.912 70.581 ;
     RECT  56.4 67.715 56.712 70.597 ;
     RECT  61.8 68.915 62.112 70.611 ;
     RECT  18.192 70.581 19.704 70.635 ;
     RECT  2.4 65.171 2.712 70.645 ;
     RECT  18.6 70.635 19.704 70.669 ;
     RECT  21.168 70.581 21.192 70.669 ;
     RECT  66.816 69.587 67.512 70.703 ;
     RECT  55.824 70.597 56.712 70.739 ;
     RECT  66.816 70.703 67.848 70.763 ;
     RECT  67.2 70.763 67.848 70.787 ;
     RECT  37.536 70.773 37.56 70.861 ;
     RECT  65.376 70.709 65.4 70.891 ;
     RECT  13.2 64.939 13.512 70.933 ;
     RECT  7.8 69.001 8.52 70.979 ;
     RECT  11.424 68.675 11.592 71.221 ;
     RECT  52.608 67.955 52.632 71.221 ;
     RECT  41.856 71.187 41.88 71.275 ;
     RECT  43.296 71.187 43.32 71.275 ;
     RECT  46.944 70.837 46.968 71.275 ;
     RECT  61.8 70.611 62.28 71.279 ;
     RECT  61.536 71.279 62.28 71.285 ;
     RECT  38.592 70.261 40.512 71.315 ;
     RECT  2.4 70.645 3.432 71.363 ;
     RECT  61.536 71.285 62.904 71.363 ;
     RECT  7.8 70.979 8.232 71.443 ;
     RECT  39.552 71.315 40.512 71.459 ;
     RECT  7.2 71.443 8.232 71.531 ;
     RECT  61.8 71.363 62.904 71.651 ;
     RECT  2.4 71.363 2.952 71.669 ;
     RECT  70.752 71.605 70.776 71.689 ;
     RECT  11.424 71.221 11.928 71.701 ;
     RECT  10.848 71.701 11.928 71.797 ;
     RECT  13.056 70.933 13.512 71.797 ;
     RECT  34.8 69.635 35.304 71.797 ;
     RECT  24 70.029 24.312 71.845 ;
     RECT  10.848 71.797 13.512 71.891 ;
     RECT  34.464 71.797 35.352 71.891 ;
     RECT  2.304 71.669 2.952 71.939 ;
     RECT  56.4 70.739 56.712 72.037 ;
     RECT  5.04 72.095 5.064 72.179 ;
     RECT  60.432 70.597 60.456 72.179 ;
     RECT  55.776 72.037 56.712 72.363 ;
     RECT  24 71.845 24.504 72.373 ;
     RECT  50.352 69.587 51.312 72.373 ;
     RECT  2.4 71.939 2.952 72.419 ;
     RECT  22.752 69.971 22.776 72.419 ;
     RECT  52.608 71.221 53.592 72.419 ;
     RECT  12.768 71.891 13.512 72.467 ;
     RECT  64.464 72.373 64.488 72.517 ;
     RECT  34.8 71.891 35.352 72.563 ;
     RECT  37.008 72.421 37.032 72.563 ;
     RECT  64.464 72.517 64.632 72.636 ;
     RECT  15.408 72.565 15.432 72.649 ;
     RECT  64.128 72.636 64.632 72.659 ;
     RECT  32.784 72.661 32.808 72.693 ;
     RECT  49.968 72.373 51.312 72.693 ;
     RECT  37.632 72.661 37.656 72.747 ;
     RECT  69.648 71.571 69.672 72.747 ;
     RECT  30.72 72.693 30.744 72.901 ;
     RECT  67.2 70.787 67.512 72.901 ;
     RECT  32.544 72.693 32.808 72.947 ;
     RECT  49.776 72.693 51.312 72.947 ;
     RECT  64.128 72.659 64.152 72.947 ;
     RECT  7.8 71.531 8.232 72.995 ;
     RECT  32.784 72.947 32.808 73.139 ;
     RECT  24 72.373 25.176 73.189 ;
     RECT  29.4 67.051 29.712 73.189 ;
     RECT  30.72 72.901 31.128 73.189 ;
     RECT  10.848 71.891 11.592 73.205 ;
     RECT  24 73.189 25.416 73.235 ;
     RECT  10.224 73.205 11.784 73.259 ;
     RECT  29.4 73.189 31.128 73.273 ;
     RECT  11.568 73.259 11.784 73.293 ;
     RECT  10.224 73.259 10.248 73.427 ;
     RECT  47.424 73.875 47.448 73.963 ;
     RECT  49.008 73.909 49.032 73.993 ;
     RECT  31.104 73.273 31.128 74.003 ;
     RECT  52.608 72.419 52.632 74.053 ;
     RECT  61.8 71.651 62.112 74.259 ;
     RECT  45.6 69.587 45.912 74.293 ;
     RECT  25.392 73.235 25.416 74.339 ;
     RECT  61.8 74.259 62.232 74.347 ;
     RECT  7.8 72.995 8.112 74.389 ;
     RECT  10.464 74.293 10.488 74.421 ;
     RECT  7.8 74.389 8.472 74.475 ;
     RECT  43.296 74.389 43.32 74.475 ;
     RECT  52.512 74.053 52.632 74.485 ;
     RECT  9.6 74.421 10.488 74.579 ;
     RECT  67.2 72.901 68.328 74.579 ;
     RECT  18.6 70.669 18.912 74.581 ;
     RECT  51 72.947 51.312 74.591 ;
     RECT  52.512 74.485 53.256 74.613 ;
     RECT  18.48 74.581 18.912 74.667 ;
     RECT  41.568 73.525 41.592 74.675 ;
     RECT  7.8 74.475 8.112 74.677 ;
     RECT  13.2 72.467 13.512 74.677 ;
     RECT  29.4 73.273 29.712 74.677 ;
     RECT  7.68 74.677 8.112 74.725 ;
     RECT  9.696 74.579 10.488 74.771 ;
     RECT  60.24 74.053 60.264 74.771 ;
     RECT  52.512 74.613 53.592 74.805 ;
     RECT  7.44 74.725 8.112 74.809 ;
     RECT  13.2 74.677 14.232 74.821 ;
     RECT  52.512 74.805 54.072 74.859 ;
     RECT  52.512 74.859 52.632 74.867 ;
     RECT  55.296 74.783 55.32 74.867 ;
     RECT  61.8 74.347 62.112 74.869 ;
     RECT  54.048 74.859 54.072 74.893 ;
     RECT  19.968 74.869 19.992 74.953 ;
     RECT  56.4 72.363 56.712 74.965 ;
     RECT  3.888 74.741 3.912 75.107 ;
     RECT  27.648 75.091 27.672 75.109 ;
     RECT  26.736 75.109 27.672 75.179 ;
     RECT  26.736 75.179 26.76 75.193 ;
     RECT  67.2 74.579 67.512 75.205 ;
     RECT  22.848 75.157 22.872 75.243 ;
     RECT  9.696 74.771 9.72 75.347 ;
     RECT  51 74.591 51.432 75.381 ;
     RECT  52.512 74.867 52.536 75.381 ;
     RECT  0.096 75.359 0.12 75.443 ;
     RECT  51 75.381 52.536 75.469 ;
     RECT  58.656 75.253 58.68 75.509 ;
     RECT  13.2 74.821 14.28 75.541 ;
     RECT  58.656 75.509 59.304 75.563 ;
     RECT  61.584 74.869 62.112 75.573 ;
     RECT  13.2 75.541 15.24 75.627 ;
     RECT  16.56 75.551 16.584 75.635 ;
     RECT  56.4 74.965 57 75.635 ;
     RECT  11.568 73.293 11.592 75.683 ;
     RECT  37.92 72.949 37.944 75.683 ;
     RECT  45.6 74.293 46.728 75.683 ;
     RECT  18.6 74.667 18.912 75.781 ;
     RECT  18.24 75.781 18.912 75.829 ;
     RECT  29.28 74.677 29.712 75.829 ;
     RECT  13.2 75.627 14.28 75.875 ;
     RECT  18.24 75.829 19.032 75.883 ;
     RECT  18.6 75.883 19.032 75.923 ;
     RECT  22.752 75.829 22.776 75.923 ;
     RECT  66.624 75.205 67.512 75.947 ;
     RECT  66.72 75.947 67.512 76.021 ;
     RECT  66.72 76.021 68.424 76.075 ;
     RECT  67.2 76.075 68.424 76.115 ;
     RECT  61.584 75.573 62.472 76.117 ;
     RECT  29.088 75.829 29.712 76.203 ;
     RECT  61.152 76.117 62.472 76.203 ;
     RECT  48.864 75.637 48.888 76.213 ;
     RECT  48.864 76.213 48.984 76.297 ;
     RECT  52.896 75.829 52.92 76.451 ;
     RECT  61.8 76.203 62.472 76.563 ;
     RECT  34.8 72.563 35.304 76.597 ;
     RECT  48.864 76.297 48.888 76.643 ;
     RECT  61.8 76.563 62.904 76.651 ;
     RECT  5.184 76.661 5.208 76.749 ;
     RECT  45.6 75.683 45.912 76.981 ;
     RECT  59.28 75.563 59.304 77.035 ;
     RECT  25.92 76.885 25.944 77.045 ;
     RECT  44.88 76.981 45.912 77.075 ;
     RECT  25.92 77.045 26.52 77.099 ;
     RECT  28.08 77.011 28.104 77.099 ;
     RECT  60.288 76.981 60.312 77.315 ;
     RECT  52.992 77.279 53.016 77.363 ;
     RECT  54.336 76.309 54.36 77.389 ;
     RECT  61.8 76.651 62.112 77.493 ;
     RECT  58.272 76.981 58.296 77.555 ;
     RECT  24 73.235 24.312 77.557 ;
     RECT  61.536 77.493 62.112 77.581 ;
     RECT  24 77.557 25.08 77.641 ;
     RECT  42.864 77.749 42.888 77.797 ;
     RECT  41.568 77.749 41.592 77.833 ;
     RECT  42.768 77.797 42.888 77.843 ;
     RECT  34.8 76.597 35.928 78.005 ;
     RECT  38.448 77.971 38.472 78.059 ;
     RECT  34.08 78.005 35.928 78.083 ;
     RECT  34.08 78.083 35.784 78.093 ;
     RECT  26.496 77.099 26.52 78.131 ;
     RECT  64.992 78.047 65.016 78.131 ;
     RECT  54.72 77.471 54.744 78.373 ;
     RECT  61.8 77.581 62.112 78.575 ;
     RECT  63.168 77.701 63.192 78.575 ;
     RECT  60.48 78.547 60.504 78.581 ;
     RECT  29.4 76.203 29.712 78.613 ;
     RECT  59.808 78.581 60.504 78.635 ;
     RECT  63.168 78.575 63.528 78.635 ;
     RECT  54.72 78.373 55.032 78.645 ;
     RECT  61.68 78.575 62.112 78.659 ;
     RECT  63.504 78.635 63.528 78.659 ;
     RECT  34.8 78.093 35.784 78.707 ;
     RECT  59.808 78.635 59.832 78.707 ;
     RECT  54.096 78.645 55.032 78.733 ;
     RECT  0.096 79.093 0.12 79.177 ;
     RECT  47.28 78.325 47.304 79.235 ;
     RECT  29.088 78.613 29.712 79.283 ;
     RECT  55.008 78.733 55.032 79.283 ;
     RECT  42.768 77.843 42.792 79.427 ;
     RECT  31.92 78.613 31.944 79.475 ;
     RECT  26.112 78.613 26.136 79.619 ;
     RECT  2.4 72.419 2.712 79.673 ;
     RECT  7.8 74.809 8.112 79.673 ;
     RECT  13.2 75.875 13.512 79.673 ;
     RECT  18.6 75.923 18.912 79.673 ;
     RECT  24 77.641 24.312 79.673 ;
     RECT  29.4 79.283 29.712 79.673 ;
     RECT  34.8 78.707 35.112 79.673 ;
     RECT  40.2 71.459 40.512 79.673 ;
     RECT  45.6 77.075 45.912 79.673 ;
     RECT  51 75.469 51.312 79.673 ;
     RECT  56.4 75.635 56.712 79.673 ;
     RECT  61.8 78.659 62.112 79.673 ;
     RECT  67.2 76.115 67.512 79.673 ;
     RECT  72.6 65.977 72.912 79.673 ;
     RECT  78 50.051 78.312 79.673 ;
     RECT  2.4 79.673 2.52 79.943 ;
     RECT  7.8 79.673 7.92 79.943 ;
     RECT  13.2 79.673 13.32 79.943 ;
     RECT  18.6 79.673 18.72 79.943 ;
     RECT  24 79.673 24.12 79.943 ;
     RECT  29.4 79.673 29.52 79.943 ;
     RECT  34.8 79.673 34.92 79.943 ;
     RECT  40.2 79.673 40.32 79.943 ;
     RECT  45.6 79.673 45.72 79.943 ;
     RECT  51 79.673 51.12 79.943 ;
     RECT  56.4 79.673 56.52 79.943 ;
     RECT  61.8 79.673 61.92 79.943 ;
     RECT  67.2 79.673 67.32 79.943 ;
     RECT  72.6 79.673 72.72 79.943 ;
     RECT  78 79.673 78.12 79.943 ;
     RECT  41.04 81.909 41.064 82.064 ;
    LAYER M6 ;
     RECT  0.016 4.8 0.037 4.832 ;
     RECT  0.016 8.512 0.131 8.544 ;
     RECT  0.016 12.224 0.131 12.256 ;
     RECT  0.016 19.648 0.131 19.68 ;
     RECT  0.016 23.36 0.131 23.392 ;
     RECT  0.016 27.072 0.131 27.104 ;
     RECT  0.016 30.784 0.131 30.816 ;
     RECT  0.016 34.496 0.131 34.528 ;
     RECT  0.016 38.208 0.131 38.24 ;
     RECT  0.016 41.984 0.131 42.016 ;
     RECT  0.016 53.12 0.131 53.152 ;
     RECT  0.016 56.832 0.131 56.864 ;
     RECT  0.016 60.544 0.131 60.576 ;
     RECT  0.016 64.256 0.131 64.288 ;
     RECT  0.016 67.968 0.131 68 ;
     RECT  0.016 75.392 0.131 75.424 ;
     RECT  0.016 79.104 0.131 79.136 ;
     RECT  0.037 4.8 0.179 4.96 ;
     RECT  0.016 15.936 2.339 15.968 ;
     RECT  0.016 71.68 2.339 71.712 ;
     RECT  0.016 45.696 2.4 45.728 ;
     RECT  2.4 2.616 2.592 2.904 ;
     RECT  2.4 8.016 2.592 8.304 ;
     RECT  2.4 13.416 2.592 13.704 ;
     RECT  2.4 18.816 2.592 19.104 ;
     RECT  2.4 24.216 2.592 24.504 ;
     RECT  2.4 29.616 2.592 29.904 ;
     RECT  2.4 35.016 2.592 35.304 ;
     RECT  2.4 40.416 2.592 40.704 ;
     RECT  2.4 45.696 2.592 46.104 ;
     RECT  2.4 51.216 2.592 51.504 ;
     RECT  2.4 56.616 2.592 56.904 ;
     RECT  2.4 62.016 2.592 62.304 ;
     RECT  2.4 67.416 2.592 67.704 ;
     RECT  2.4 72.816 2.592 73.104 ;
     RECT  2.4 78.216 2.592 78.504 ;
     RECT  2.592 2.616 3.182 3.48 ;
     RECT  3.182 1.728 3.251 3.48 ;
     RECT  2.592 40.416 3.397 41.28 ;
     RECT  2.592 45.696 3.445 46.68 ;
     RECT  2.592 56.616 3.781 57.48 ;
     RECT  2.592 62.016 3.829 62.88 ;
     RECT  2.592 72.816 3.877 73.68 ;
     RECT  2.592 24.216 3.925 25.08 ;
     RECT  3.781 55.808 3.925 57.48 ;
     RECT  3.397 39.424 4.019 41.28 ;
     RECT  2.592 35.016 4.469 35.88 ;
     RECT  4.453 38.784 4.469 38.816 ;
     RECT  2.592 8.016 4.501 8.88 ;
     RECT  3.829 62.016 4.501 63.84 ;
     RECT  4.469 38.656 4.523 38.816 ;
     RECT  3.925 24.216 4.533 26.208 ;
     RECT  2.592 29.616 4.533 30.48 ;
     RECT  4.469 33.536 4.547 35.88 ;
     RECT  4.533 24.216 4.587 26.848 ;
     RECT  4.533 28.544 4.691 30.48 ;
     RECT  3.251 2.616 4.789 3.48 ;
     RECT  4.789 1.728 4.858 3.48 ;
     RECT  3.877 72.816 5.029 74.784 ;
     RECT  0.016 49.408 5.173 49.44 ;
     RECT  5.154 76.672 5.227 76.704 ;
     RECT  5.173 48.448 5.267 49.44 ;
     RECT  3.925 15.936 5.365 15.968 ;
     RECT  2.592 18.816 5.365 19.68 ;
     RECT  5.365 15.936 5.419 17.12 ;
     RECT  5.365 18.816 5.459 20.576 ;
     RECT  5.605 10.816 5.675 10.848 ;
     RECT  4.501 62.016 5.747 64.8 ;
     RECT  3.925 55.552 5.989 57.48 ;
     RECT  5.989 55.552 6.059 58.784 ;
     RECT  4.858 2.616 6.261 3.48 ;
     RECT  4.981 4.864 6.261 4.896 ;
     RECT  4.501 7.424 6.315 8.88 ;
     RECT  6.261 2.616 6.325 5.088 ;
     RECT  6.325 1.728 6.419 5.088 ;
     RECT  4.587 24.216 6.805 25.08 ;
     RECT  5.029 72.128 7.189 74.784 ;
     RECT  6.059 55.552 7.475 58.016 ;
     RECT  7.189 71.488 7.475 74.784 ;
     RECT  6.565 66.048 7.477 66.08 ;
     RECT  2.592 67.416 7.477 68.28 ;
     RECT  7.477 66.048 7.531 68.28 ;
     RECT  2.592 51.216 7.669 52.08 ;
     RECT  6.805 23.36 7.715 25.08 ;
     RECT  7.475 71.488 7.738 74.72 ;
     RECT  6.419 2.616 7.925 4.384 ;
     RECT  7.669 51.008 7.979 52.08 ;
     RECT  7.475 55.552 7.979 57.48 ;
     RECT  7.925 1.728 8.003 4.384 ;
     RECT  3.445 45.568 8.053 46.68 ;
     RECT  8.053 45.568 8.107 47.264 ;
     RECT  4.587 26.816 8.181 26.848 ;
     RECT  8.053 42.688 8.243 42.72 ;
     RECT  5.267 49.408 8.243 49.44 ;
     RECT  7.738 71.488 8.243 74.464 ;
     RECT  6.315 8.016 8.245 8.88 ;
     RECT  2.592 13.416 8.245 14.28 ;
     RECT  5.419 17.088 8.245 17.12 ;
     RECT  5.459 18.816 8.245 19.68 ;
     RECT  5.747 62.016 8.245 63.84 ;
     RECT  8.245 17.088 8.299 19.68 ;
     RECT  8.245 61.376 8.299 65.568 ;
     RECT  8.245 13.312 8.314 14.28 ;
     RECT  8.299 61.376 8.339 62.88 ;
     RECT  8.181 26.816 8.485 27.36 ;
     RECT  8.107 45.696 8.579 47.264 ;
     RECT  7.531 67.264 8.675 68.28 ;
     RECT  8.675 67.416 9.061 68.28 ;
     RECT  7.715 24.064 9.109 25.08 ;
     RECT  9.061 67.416 9.131 68.96 ;
     RECT  8.485 26.624 9.155 27.36 ;
     RECT  4.523 38.656 9.155 38.688 ;
     RECT  8.299 64.832 9.203 65.568 ;
     RECT  9.061 0.064 9.579 0.096 ;
     RECT  8.243 72.128 9.635 74.464 ;
     RECT  9.685 75.264 9.771 75.296 ;
     RECT  9.061 11.392 9.827 11.424 ;
     RECT  7.979 55.808 10.091 57.48 ;
     RECT  8.245 7.04 10.115 8.88 ;
     RECT  9.131 67.416 10.597 68.28 ;
     RECT  9.203 64.832 10.613 64.864 ;
     RECT  10.613 64.576 10.667 64.864 ;
     RECT  10.597 67.264 10.667 68.28 ;
     RECT  8.003 2.616 11.125 4.384 ;
     RECT  11.125 1.728 11.194 4.384 ;
     RECT  9.109 23.296 11.459 25.08 ;
     RECT  9.635 72.128 11.893 73.68 ;
     RECT  11.893 71.232 11.962 73.68 ;
     RECT  10.667 64.576 12.373 64.608 ;
     RECT  12.373 64.576 12.405 64.928 ;
     RECT  4.547 35.016 12.421 35.88 ;
     RECT  12.405 64.448 12.459 64.928 ;
     RECT  4.547 33.536 12.517 33.568 ;
     RECT  12.421 34.88 12.517 35.88 ;
     RECT  8.339 62.016 12.517 62.88 ;
     RECT  11.962 71.808 12.563 73.68 ;
     RECT  8.579 45.816 12.757 47.264 ;
     RECT  12.725 0.064 12.803 0.096 ;
     RECT  12.757 45.816 12.843 47.84 ;
     RECT  12.373 54.656 12.843 54.688 ;
     RECT  8.299 17.6 12.901 19.68 ;
     RECT  12.901 16.32 12.997 19.68 ;
     RECT  10.091 56.512 13.026 57.48 ;
     RECT  11.194 2.616 13.045 4.384 ;
     RECT  9.155 27.328 13.045 27.36 ;
     RECT  4.691 29.616 13.045 30.48 ;
     RECT  13.045 27.328 13.091 30.48 ;
     RECT  12.459 64.448 13.091 64.608 ;
     RECT  12.563 72.128 13.091 73.68 ;
     RECT  10.115 8.016 13.093 8.88 ;
     RECT  8.314 13.416 13.093 14.28 ;
     RECT  12.997 16.256 13.093 19.68 ;
     RECT  13.026 55.808 13.099 57.48 ;
     RECT  13.093 13.416 13.163 19.68 ;
     RECT  12.517 33.536 13.173 35.88 ;
     RECT  13.093 7.872 13.291 9.12 ;
     RECT  13.163 16.256 13.291 19.68 ;
     RECT  13.291 17.344 13.573 19.68 ;
     RECT  11.459 24.216 13.573 25.08 ;
     RECT  13.173 33.088 13.619 35.88 ;
     RECT  13.573 24.216 13.621 25.248 ;
     RECT  13.291 7.872 13.653 8.992 ;
     RECT  13.091 27.904 13.675 30.48 ;
     RECT  12.517 60.8 13.685 62.88 ;
     RECT  13.091 64.448 13.685 64.48 ;
     RECT  13.573 17.344 13.739 20.32 ;
     RECT  13.685 44.288 13.955 44.32 ;
     RECT  13.045 2.496 14.195 4.384 ;
     RECT  13.091 72.32 14.197 73.68 ;
     RECT  13.739 18.496 14.243 20.32 ;
     RECT  13.619 33.536 14.251 35.88 ;
     RECT  14.197 72.32 14.251 74.912 ;
     RECT  13.685 60.8 14.291 64.48 ;
     RECT  14.195 2.496 14.293 3.48 ;
     RECT  14.251 34.88 14.325 35.88 ;
     RECT  14.293 1.728 14.379 3.48 ;
     RECT  14.325 34.88 14.398 36.704 ;
     RECT  13.621 22.656 14.867 22.688 ;
     RECT  14.837 10.816 14.915 10.848 ;
     RECT  14.251 72.576 15.205 74.912 ;
     RECT  13.653 8.016 15.253 8.992 ;
     RECT  15.205 72.576 15.443 75.616 ;
     RECT  14.291 61.504 15.539 64.48 ;
     RECT  15.253 7.424 15.685 8.992 ;
     RECT  13.621 24.216 15.685 26.016 ;
     RECT  14.379 2.616 15.925 3.48 ;
     RECT  15.925 1.728 15.994 3.48 ;
     RECT  15.685 7.424 16.019 9.184 ;
     RECT  15.443 72.816 16.595 75.616 ;
     RECT  16.622 59.264 16.691 59.296 ;
     RECT  15.539 61.504 17.027 62.88 ;
     RECT  16.019 8.016 17.123 9.184 ;
     RECT  15.685 23.936 17.123 26.016 ;
     RECT  4.019 40.416 17.125 41.28 ;
     RECT  12.843 45.816 17.141 47.648 ;
     RECT  17.125 40.416 17.195 42.592 ;
     RECT  15.925 38.144 17.363 38.176 ;
     RECT  7.979 51.216 17.461 52.08 ;
     RECT  15.994 2.24 17.525 3.48 ;
     RECT  17.141 45.632 17.579 47.648 ;
     RECT  17.509 49.024 17.579 49.056 ;
     RECT  17.525 2.24 17.603 4.064 ;
     RECT  17.027 61.888 17.722 62.88 ;
     RECT  17.461 51.216 17.749 52.448 ;
     RECT  17.603 2.24 17.795 3.48 ;
     RECT  17.826 22.784 17.899 22.816 ;
     RECT  15.539 64.448 18.181 64.48 ;
     RECT  16.595 72.816 18.229 74.912 ;
     RECT  17.749 51.216 18.283 52.512 ;
     RECT  17.195 40.416 18.469 41.28 ;
     RECT  18.469 39.936 18.731 41.28 ;
     RECT  18.181 64.448 18.805 64.992 ;
     RECT  18.805 64.448 18.859 65.12 ;
     RECT  10.667 67.416 18.997 68.28 ;
     RECT  18.229 72.816 19.043 75.872 ;
     RECT  13.163 13.416 19.045 14.28 ;
     RECT  18.469 32.896 19.061 32.928 ;
     RECT  18.997 67.264 19.066 68.28 ;
     RECT  19.045 13.056 19.115 14.28 ;
     RECT  19.093 1.152 19.179 1.184 ;
     RECT  18.859 64.96 19.187 65.12 ;
     RECT  19.066 67.416 19.237 68.28 ;
     RECT  19.061 31.808 19.283 32.928 ;
     RECT  17.123 24.216 19.427 26.016 ;
     RECT  17.579 45.632 19.427 46.68 ;
     RECT  17.795 2.616 19.573 3.48 ;
     RECT  17.123 8.016 19.627 8.992 ;
     RECT  19.573 2.616 19.642 4.576 ;
     RECT  19.427 24.216 19.765 25.08 ;
     RECT  14.398 34.88 20.003 35.88 ;
     RECT  13.099 56.512 20.003 57.48 ;
     RECT  19.237 67.416 20.003 68.896 ;
     RECT  19.043 72.816 20.003 74.912 ;
     RECT  19.283 32.896 20.291 32.928 ;
     RECT  19.642 2.616 20.725 3.48 ;
     RECT  20.725 1.728 20.794 3.48 ;
     RECT  19.765 23.808 21.059 25.08 ;
     RECT  14.243 18.496 21.155 19.68 ;
     RECT  19.187 65.088 21.155 65.12 ;
     RECT  18.181 70.592 21.203 70.624 ;
     RECT  21.155 18.816 21.733 19.68 ;
     RECT  13.675 28.416 21.973 30.48 ;
     RECT  19.115 13.416 22.165 14.28 ;
     RECT  21.733 18.816 22.251 20.576 ;
     RECT  22.165 0.064 22.315 0.096 ;
     RECT  20.794 2.616 22.741 3.48 ;
     RECT  22.709 75.2 22.787 75.872 ;
     RECT  22.165 13.416 22.789 14.432 ;
     RECT  22.165 69.568 22.835 69.6 ;
     RECT  22.787 75.2 22.883 75.232 ;
     RECT  21.973 28.416 23.285 31.072 ;
     RECT  20.003 35.016 23.285 35.88 ;
     RECT  23.285 28.416 23.363 31.904 ;
     RECT  23.285 33.728 23.363 35.88 ;
     RECT  19.627 8.016 23.605 8.88 ;
     RECT  22.251 18.816 23.653 20.32 ;
     RECT  23.605 6.784 23.674 8.88 ;
     RECT  22.741 2.616 23.845 3.616 ;
     RECT  22.789 13.416 23.893 14.816 ;
     RECT  21.059 24.216 23.893 25.08 ;
     RECT  18.731 40.416 23.893 41.28 ;
     RECT  20.003 56.616 23.893 57.48 ;
     RECT  23.845 2.616 23.915 3.68 ;
     RECT  23.915 2.616 23.939 3.616 ;
     RECT  23.893 13.416 23.939 15.648 ;
     RECT  22.069 65.984 24.469 66.016 ;
     RECT  20.003 67.416 24.469 68.28 ;
     RECT  20.003 72.816 24.469 73.68 ;
     RECT  23.939 15.616 24.899 15.648 ;
     RECT  23.653 18.816 24.899 20.96 ;
     RECT  23.939 13.416 25.045 14.28 ;
     RECT  2.592 78.216 25.045 79.08 ;
     RECT  23.893 56.384 25.07 57.48 ;
     RECT  23.893 40.416 25.139 41.952 ;
     RECT  25.07 56.384 25.139 58.784 ;
     RECT  23.939 2.616 25.429 3.48 ;
     RECT  25.429 1.728 25.515 3.48 ;
     RECT  23.363 28.416 25.515 31.072 ;
     RECT  23.674 7.104 25.646 8.88 ;
     RECT  24.469 65.984 25.653 68.28 ;
     RECT  24.899 18.816 25.667 20 ;
     RECT  25.646 7.104 25.715 9.76 ;
     RECT  25.653 64.896 25.763 68.28 ;
     RECT  25.045 77.568 25.909 79.08 ;
     RECT  23.893 24.216 26.005 25.504 ;
     RECT  24.373 69.952 26.099 69.984 ;
     RECT  23.893 43.264 26.149 43.296 ;
     RECT  24.997 53.696 26.243 53.728 ;
     RECT  25.763 65.984 26.243 68.28 ;
     RECT  25.045 13.312 26.387 14.28 ;
     RECT  25.515 2.616 26.485 3.48 ;
     RECT  25.715 7.104 26.539 8.88 ;
     RECT  26.485 2.616 26.554 4 ;
     RECT  23.363 35.016 26.805 35.88 ;
     RECT  17.722 62.016 26.821 62.88 ;
     RECT  18.283 51.216 26.965 52.08 ;
     RECT  26.965 51.216 27.051 52.512 ;
     RECT  27.061 0.576 27.155 0.608 ;
     RECT  25.045 15.68 27.317 15.712 ;
     RECT  27.301 22.464 27.371 22.752 ;
     RECT  26.005 24.216 27.395 26.784 ;
     RECT  26.197 59.648 27.395 59.68 ;
     RECT  26.821 62.016 27.779 63.008 ;
     RECT  25.909 77.056 28.115 79.08 ;
     RECT  19.427 45.816 28.165 46.68 ;
     RECT  24.469 48.128 28.165 48.16 ;
     RECT  26.243 67.008 28.213 68.28 ;
     RECT  28.213 67.008 28.282 68.96 ;
     RECT  26.149 43.2 28.405 43.296 ;
     RECT  26.554 2.616 28.661 3.48 ;
     RECT  28.661 1.728 28.739 3.48 ;
     RECT  26.387 13.416 28.981 14.28 ;
     RECT  27.317 15.68 28.981 15.776 ;
     RECT  27.395 24.216 29.045 25.504 ;
     RECT  26.725 75.136 29.045 75.168 ;
     RECT  28.981 13.312 29.05 15.776 ;
     RECT  29.045 24.216 29.077 26.72 ;
     RECT  25.515 28.416 29.077 30.48 ;
     RECT  29.077 24.216 29.099 26.848 ;
     RECT  28.115 77.568 29.099 79.08 ;
     RECT  29.099 26.688 29.123 26.848 ;
     RECT  27.061 37.568 29.123 37.6 ;
     RECT  29.045 75.136 29.123 76.192 ;
     RECT  28.165 45.816 29.163 48.16 ;
     RECT  24.469 71.872 29.163 73.68 ;
     RECT  29.123 75.136 29.163 75.872 ;
     RECT  29.163 75.136 29.315 75.168 ;
     RECT  25.139 40.416 29.557 41.28 ;
     RECT  28.405 42.688 29.557 43.296 ;
     RECT  29.557 40.416 29.611 43.296 ;
     RECT  25.667 18.816 29.797 19.68 ;
     RECT  26.805 33.92 29.813 35.88 ;
     RECT  29.797 17.664 29.867 19.68 ;
     RECT  29.813 33.6 29.877 35.88 ;
     RECT  29.877 32.512 29.987 35.88 ;
     RECT  28.282 67.008 30.085 68.28 ;
     RECT  30.229 0.064 30.315 0.096 ;
     RECT  29.077 28.416 30.371 31.008 ;
     RECT  25.139 56.384 30.373 57.632 ;
     RECT  30.389 54.464 30.498 54.496 ;
     RECT  30.373 55.872 30.498 57.632 ;
     RECT  30.498 54.464 30.563 57.632 ;
     RECT  30.453 59.776 30.563 59.808 ;
     RECT  30.563 54.464 30.586 57.48 ;
     RECT  29.123 26.816 30.659 26.848 ;
     RECT  27.371 22.464 30.661 22.496 ;
     RECT  29.099 24.216 30.661 25.08 ;
     RECT  30.586 54.464 30.699 54.624 ;
     RECT  26.539 8.016 30.837 8.88 ;
     RECT  29.05 13.416 30.851 15.776 ;
     RECT  30.371 29.616 30.851 31.008 ;
     RECT  30.851 15.744 30.897 15.776 ;
     RECT  30.453 65.472 31.187 65.504 ;
     RECT  27.051 51.216 31.285 52.08 ;
     RECT  29.163 45.816 31.339 47.84 ;
     RECT  27.779 62.016 31.349 62.88 ;
     RECT  30.085 66.944 31.403 68.28 ;
     RECT  31.349 65.28 31.427 65.312 ;
     RECT  28.739 2.616 31.861 3.48 ;
     RECT  31.285 49.216 31.861 52.08 ;
     RECT  31.861 1.728 31.93 3.48 ;
     RECT  31.403 67.264 32.101 68.28 ;
     RECT  31.349 69.568 32.101 69.6 ;
     RECT  32.101 67.264 32.171 69.6 ;
     RECT  30.699 54.592 32.197 54.624 ;
     RECT  30.586 56.616 32.197 57.48 ;
     RECT  30.661 22.464 32.291 25.08 ;
     RECT  31.861 48.96 32.435 52.08 ;
     RECT  29.611 40.416 32.437 42.464 ;
     RECT  29.987 33.792 32.483 35.88 ;
     RECT  31.349 62.016 32.485 63.84 ;
     RECT  30.837 8.016 32.821 8.992 ;
     RECT  31.861 17.088 33.059 17.12 ;
     RECT  26.485 5.76 33.061 5.792 ;
     RECT  33.061 5.44 33.077 5.792 ;
     RECT  33.077 5.44 33.395 6.24 ;
     RECT  29.867 18.816 33.653 19.68 ;
     RECT  33.461 0.064 33.683 0.096 ;
     RECT  32.437 40.416 33.683 42.848 ;
     RECT  32.197 54.592 33.683 57.48 ;
     RECT  33.109 15.936 33.707 15.968 ;
     RECT  33.683 40.416 33.733 41.28 ;
     RECT  33.013 60.096 33.923 60.128 ;
     RECT  32.435 49.216 34.165 52.08 ;
     RECT  32.171 69.568 34.259 69.6 ;
     RECT  29.163 72.704 34.453 73.68 ;
     RECT  32.821 8.016 34.693 9.12 ;
     RECT  32.485 61.888 34.693 63.84 ;
     RECT  34.693 11.392 34.795 11.424 ;
     RECT  34.693 31.872 34.795 31.904 ;
     RECT  32.483 33.92 34.795 35.88 ;
     RECT  33.683 54.592 34.997 55.328 ;
     RECT  33.683 56.616 34.997 57.48 ;
     RECT  35.029 0.576 35.115 0.608 ;
     RECT  34.165 49.216 35.219 53.024 ;
     RECT  34.997 59.264 35.219 59.296 ;
     RECT  34.997 54.592 35.307 57.48 ;
     RECT  32.171 67.416 35.317 68.28 ;
     RECT  34.453 71.808 35.363 73.68 ;
     RECT  35.307 55.296 35.411 57.48 ;
     RECT  34.693 6.784 35.747 9.12 ;
     RECT  34.453 37.952 35.797 37.984 ;
     RECT  33.733 39.36 35.797 41.28 ;
     RECT  35.797 37.952 35.843 41.28 ;
     RECT  32.291 22.464 35.845 22.496 ;
     RECT  32.291 24.216 35.845 25.08 ;
     RECT  34.693 61.312 36.035 63.84 ;
     RECT  35.843 38.144 36.131 41.28 ;
     RECT  35.317 66.752 36.213 68.28 ;
     RECT  36.213 66.048 36.286 68.28 ;
     RECT  36.131 38.144 36.515 38.176 ;
     RECT  31.93 2.616 36.661 3.48 ;
     RECT  36.661 1.728 36.755 3.48 ;
     RECT  33.395 5.44 36.851 5.472 ;
     RECT  36.131 39.744 37.091 41.28 ;
     RECT  35.749 16.576 37.139 16.608 ;
     RECT  31.339 45.816 37.189 46.68 ;
     RECT  35.845 43.392 37.667 43.424 ;
     RECT  35.219 49.216 37.667 52.448 ;
     RECT  35.363 72.704 37.667 73.68 ;
     RECT  37.667 50.304 38.147 52.448 ;
     RECT  30.851 13.416 38.178 14.28 ;
     RECT  38.178 13.416 38.251 15.072 ;
     RECT  36.035 62.016 38.37 63.84 ;
     RECT  38.37 62.016 38.443 64.864 ;
     RECT  29.099 78.016 38.483 79.08 ;
     RECT  33.653 18.688 38.579 19.68 ;
     RECT  37.525 70.784 38.581 70.816 ;
     RECT  34.795 34.176 38.627 35.88 ;
     RECT  38.581 70.272 38.627 70.816 ;
     RECT  35.411 56.128 38.723 57.48 ;
     RECT  38.149 11.392 38.819 11.424 ;
     RECT  38.147 51.216 38.819 52.448 ;
     RECT  38.443 62.016 38.819 63.84 ;
     RECT  36.286 66.688 38.819 68.28 ;
     RECT  36.755 2.616 38.894 3.48 ;
     RECT  38.894 2.616 38.963 4.576 ;
     RECT  35.747 8.016 39.155 9.12 ;
     RECT  37.573 60.288 39.155 60.32 ;
     RECT  35.845 22.464 39.253 25.08 ;
     RECT  38.819 62.016 39.285 62.88 ;
     RECT  39.253 22.464 39.339 25.184 ;
     RECT  31.285 28.16 39.339 28.192 ;
     RECT  37.189 45.816 39.347 46.816 ;
     RECT  39.285 61.504 39.358 62.88 ;
     RECT  38.149 21.12 39.395 21.152 ;
     RECT  38.627 70.272 39.587 70.304 ;
     RECT  38.197 0.064 39.851 0.096 ;
     RECT  38.251 13.416 39.973 14.28 ;
     RECT  38.723 56.616 40.021 57.48 ;
     RECT  37.091 40.416 40.629 41.28 ;
     RECT  39.973 13.416 40.787 15.328 ;
     RECT  39.829 48.96 40.883 48.992 ;
     RECT  39.347 45.816 40.981 46.68 ;
     RECT  40.629 81.92 41.075 81.952 ;
     RECT  39.339 22.464 41.077 22.496 ;
     RECT  39.339 24.216 41.173 25.08 ;
     RECT  41.077 22.464 41.269 22.624 ;
     RECT  41.269 22.464 41.323 22.752 ;
     RECT  40.629 40.416 41.323 41.44 ;
     RECT  39.155 8.016 41.333 8.88 ;
     RECT  41.365 1.152 41.451 1.184 ;
     RECT  41.323 22.592 41.451 22.752 ;
     RECT  41.333 5.376 41.459 5.408 ;
     RECT  38.483 78.216 41.557 79.08 ;
     RECT  41.333 6.784 41.651 9.504 ;
     RECT  40.021 56.616 41.651 58.656 ;
     RECT  40.787 13.416 42.133 14.28 ;
     RECT  41.557 37.888 42.133 37.92 ;
     RECT  38.819 67.416 42.133 68.28 ;
     RECT  41.173 24.064 42.275 25.08 ;
     RECT  30.851 29.616 42.485 30.48 ;
     RECT  42.485 28.48 42.563 30.48 ;
     RECT  38.627 35.016 42.709 35.88 ;
     RECT  41.317 48.384 42.755 48.416 ;
     RECT  41.557 77.76 42.899 79.08 ;
     RECT  42.709 0.064 43.051 0.096 ;
     RECT  42.133 13.416 43.235 14.432 ;
     RECT  41.651 6.784 43.285 8.88 ;
     RECT  38.579 18.816 43.285 19.68 ;
     RECT  42.275 24.216 43.285 25.08 ;
     RECT  37.667 72.816 43.285 73.68 ;
     RECT  41.845 71.232 43.331 71.264 ;
     RECT  42.133 67.416 43.379 68.384 ;
     RECT  43.285 18.688 43.429 19.68 ;
     RECT  42.901 21.12 43.429 21.152 ;
     RECT  42.709 34.88 43.445 35.88 ;
     RECT  41.651 56.616 43.477 58.4 ;
     RECT  43.429 18.688 43.499 21.152 ;
     RECT  43.381 55.104 43.563 55.136 ;
     RECT  43.445 34.176 43.619 35.88 ;
     RECT  38.963 2.616 43.829 3.48 ;
     RECT  43.829 2.616 43.861 3.616 ;
     RECT  42.133 37.888 43.861 38.176 ;
     RECT  43.813 0.128 43.883 0.16 ;
     RECT  43.619 34.816 43.955 35.88 ;
     RECT  43.955 34.88 44.051 35.88 ;
     RECT  40.981 44.864 44.149 46.68 ;
     RECT  44.149 44.864 44.218 47.904 ;
     RECT  43.861 2.616 44.341 3.744 ;
     RECT  43.379 67.416 44.341 68.28 ;
     RECT  44.341 2.616 44.41 4 ;
     RECT  43.285 6.016 44.41 8.88 ;
     RECT  44.341 66.624 44.41 68.28 ;
     RECT  44.41 67.264 44.531 68.28 ;
     RECT  44.41 6.016 44.651 6.304 ;
     RECT  41.323 40.416 44.846 41.28 ;
     RECT  42.899 78.216 44.846 79.08 ;
     RECT  43.861 37.888 44.907 38.624 ;
     RECT  43.285 72.816 44.907 74.464 ;
     RECT  44.846 40.416 44.915 41.632 ;
     RECT  44.846 76.992 44.915 79.08 ;
     RECT  41.451 22.72 44.965 22.752 ;
     RECT  43.285 24.216 44.965 26.272 ;
     RECT  43.477 56.616 45.011 59.296 ;
     RECT  43.499 21.12 45.059 21.152 ;
     RECT  44.965 22.72 45.059 26.272 ;
     RECT  44.907 38.592 45.059 38.624 ;
     RECT  45.011 56.616 45.493 58.4 ;
     RECT  44.677 11.904 45.749 11.936 ;
     RECT  43.235 13.416 45.749 14.28 ;
     RECT  43.285 16.896 45.749 16.928 ;
     RECT  45.749 11.904 45.877 14.28 ;
     RECT  45.749 16.576 45.877 16.928 ;
     RECT  43.499 18.688 45.877 19.68 ;
     RECT  45.877 11.904 45.931 16.928 ;
     RECT  45.059 22.72 45.973 25.824 ;
     RECT  45.973 22.016 45.995 25.824 ;
     RECT  45.931 11.904 46.019 16.608 ;
     RECT  45.877 18.688 46.059 20.576 ;
     RECT  46.019 11.904 46.117 11.936 ;
     RECT  44.41 2.616 46.165 3.744 ;
     RECT  44.531 67.416 46.165 68.28 ;
     RECT  46.059 18.816 46.211 20.576 ;
     RECT  46.165 1.728 46.251 3.744 ;
     RECT  44.41 8.016 46.501 8.88 ;
     RECT  42.563 29.616 46.693 30.48 ;
     RECT  39.358 62.016 46.693 62.88 ;
     RECT  46.117 10.816 46.699 11.936 ;
     RECT  45.995 22.016 46.739 25.696 ;
     RECT  46.693 29.616 46.763 30.624 ;
     RECT  46.693 61.568 46.773 62.88 ;
     RECT  46.739 22.72 46.787 25.696 ;
     RECT  45.013 48.128 46.787 48.16 ;
     RECT  46.251 2.616 46.901 3.744 ;
     RECT  44.651 6.016 46.901 6.048 ;
     RECT  44.907 72.816 46.901 74.336 ;
     RECT  46.773 60.928 46.931 62.88 ;
     RECT  46.501 8.016 46.933 9.056 ;
     RECT  46.901 72.704 46.955 74.336 ;
     RECT  46.933 7.872 46.965 9.056 ;
     RECT  46.699 10.816 46.965 10.848 ;
     RECT  46.901 5.952 46.979 6.048 ;
     RECT  46.901 71.232 46.979 71.264 ;
     RECT  46.965 7.872 47.019 10.848 ;
     RECT  46.901 2.616 47.123 3.872 ;
     RECT  44.051 35.016 47.173 35.88 ;
     RECT  47.123 2.616 47.219 3.744 ;
     RECT  46.165 67.416 47.403 68.704 ;
     RECT  46.019 15.744 47.747 16.608 ;
     RECT  45.493 56.512 47.795 58.4 ;
     RECT  47.219 2.616 47.797 3.48 ;
     RECT  38.819 51.216 47.797 52.08 ;
     RECT  47.797 1.728 47.866 3.48 ;
     RECT  47.173 34.176 48.131 35.88 ;
     RECT  46.931 62.016 48.613 62.88 ;
     RECT  47.077 6.656 48.803 6.688 ;
     RECT  46.211 18.816 48.949 19.68 ;
     RECT  44.915 40.416 48.949 41.28 ;
     RECT  48.613 62.016 48.949 63.264 ;
     RECT  48.949 38.208 48.997 38.24 ;
     RECT  48.997 37.44 49.018 38.24 ;
     RECT  46.955 72.704 49.043 73.952 ;
     RECT  48.949 18.816 49.122 19.808 ;
     RECT  49.122 18.688 49.195 19.808 ;
     RECT  47.019 8.016 49.331 9.632 ;
     RECT  47.866 2.616 49.381 3.48 ;
     RECT  49.381 1.728 49.451 3.48 ;
     RECT  47.747 15.744 49.621 15.776 ;
     RECT  49.621 15.744 49.667 16.032 ;
     RECT  49.195 18.816 49.715 19.808 ;
     RECT  47.797 51.216 49.811 52.64 ;
     RECT  47.795 56.616 49.845 58.4 ;
     RECT  49.525 65.664 49.845 65.696 ;
     RECT  49.845 65.664 49.899 66.08 ;
     RECT  49.043 72.704 49.957 73.68 ;
     RECT  49.899 65.792 50.027 66.08 ;
     RECT  49.957 72.384 50.027 73.68 ;
     RECT  47.221 54.528 50.037 54.56 ;
     RECT  49.845 56.616 50.037 58.528 ;
     RECT  50.037 54.208 50.082 58.528 ;
     RECT  50.082 54.08 50.11 58.528 ;
     RECT  50.11 54.08 50.155 54.624 ;
     RECT  49.018 37.44 50.195 37.472 ;
     RECT  48.949 39.616 50.195 41.28 ;
     RECT  50.155 54.208 50.243 54.624 ;
     RECT  44.218 44.864 50.658 46.68 ;
     RECT  46.787 24.216 50.677 25.696 ;
     RECT  50.629 27.392 50.677 27.424 ;
     RECT  50.658 44.864 50.677 46.816 ;
     RECT  50.677 44.864 50.731 47.904 ;
     RECT  49.525 33.664 50.819 33.696 ;
     RECT  49.667 16 50.821 16.032 ;
     RECT  48.131 35.016 50.821 35.88 ;
     RECT  49.451 2.616 50.869 3.48 ;
     RECT  50.11 56.616 50.869 58.528 ;
     RECT  50.821 33.792 50.987 35.88 ;
     RECT  50.869 2.616 51.051 4.576 ;
     RECT  46.787 22.72 51.061 22.752 ;
     RECT  50.677 24.216 51.061 27.424 ;
     RECT  51.061 22.528 51.243 27.424 ;
     RECT  49.331 8.016 51.253 9.248 ;
     RECT  51.243 22.528 51.307 26.656 ;
     RECT  48.949 62.016 51.371 63.904 ;
     RECT  50.821 16 51.397 16.288 ;
     RECT  50.027 72.704 51.397 73.68 ;
     RECT  51.397 16 51.443 16.544 ;
     RECT  50.731 45.816 51.443 47.904 ;
     RECT  47.403 67.416 51.445 68.28 ;
     RECT  50.027 65.792 51.499 65.824 ;
     RECT  46.763 29.616 51.829 30.48 ;
     RECT  50.869 56.616 52.211 59.168 ;
     RECT  51.397 72.704 52.213 74.656 ;
     RECT  48.949 76.224 52.213 76.256 ;
     RECT  46.019 13.416 52.405 14.28 ;
     RECT  51.829 28.672 52.405 30.48 ;
     RECT  52.213 72.704 52.405 76.256 ;
     RECT  44.915 78.216 52.405 79.08 ;
     RECT  52.405 72.32 52.459 79.08 ;
     RECT  51.051 2.616 52.597 3.48 ;
     RECT  49.715 18.816 52.645 19.68 ;
     RECT  52.597 2.616 52.666 4.576 ;
     RECT  51.371 62.016 52.693 63.776 ;
     RECT  52.645 18.24 52.715 19.68 ;
     RECT  52.211 56.616 52.979 58.72 ;
     RECT  51.307 22.528 53.075 25.08 ;
     RECT  52.693 62.016 53.123 64.352 ;
     RECT  53.294 6.336 53.317 6.368 ;
     RECT  53.317 6.208 53.363 6.368 ;
     RECT  53.363 6.208 53.365 6.24 ;
     RECT  53.365 5.184 53.419 6.24 ;
     RECT  52.981 42.752 53.557 42.784 ;
     RECT  53.557 42.752 53.611 43.296 ;
     RECT  52.405 28.672 53.649 30.688 ;
     RECT  52.405 12.288 53.651 14.28 ;
     RECT  49.811 51.216 53.941 52.08 ;
     RECT  50.243 54.592 53.941 54.624 ;
     RECT  53.941 50.752 54.01 52.08 ;
     RECT  53.651 13.12 54.123 14.28 ;
     RECT  53.123 64.32 54.181 64.352 ;
     RECT  52.645 66.048 54.181 66.08 ;
     RECT  54.085 0.064 54.187 0.096 ;
     RECT  54.181 64.32 54.251 66.08 ;
     RECT  52.459 77.312 54.371 79.08 ;
     RECT  50.987 35.016 54.581 35.88 ;
     RECT  53.075 22.528 54.613 22.752 ;
     RECT  53.075 24.216 54.613 25.08 ;
     RECT  54.565 38.784 54.635 38.816 ;
     RECT  52.715 18.816 54.645 19.68 ;
     RECT  54.613 22.272 54.699 22.752 ;
     RECT  54.613 24.216 54.699 26.272 ;
     RECT  51.445 67.416 54.755 68.704 ;
     RECT  54.371 77.504 54.755 79.08 ;
     RECT  54.123 13.416 54.757 14.28 ;
     RECT  54.699 22.4 54.803 22.752 ;
     RECT  53.941 53.504 54.851 54.624 ;
     RECT  54.645 18.624 55.043 19.68 ;
     RECT  54.251 66.048 55.187 66.08 ;
     RECT  53.649 28.672 55.189 30.48 ;
     RECT  55.189 28.672 55.221 30.816 ;
     RECT  55.221 28.48 55.275 30.816 ;
     RECT  52.459 72.32 55.331 74.848 ;
     RECT  51.253 8.016 55.621 10.08 ;
     RECT  52.666 2.616 55.733 3.48 ;
     RECT  55.733 1.728 55.811 3.48 ;
     RECT  55.331 72.32 55.811 73.68 ;
     RECT  54.01 51.216 55.813 52.08 ;
     RECT  53.941 48.128 56.773 48.16 ;
     RECT  55.621 7.36 57.059 10.08 ;
     RECT  56.293 21.12 57.059 21.152 ;
     RECT  55.813 50.688 57.107 52.08 ;
     RECT  55.811 2.616 57.326 3.48 ;
     RECT  57.326 1.728 57.395 3.48 ;
     RECT  54.757 13.416 57.397 14.88 ;
     RECT  51.443 16.512 57.397 16.544 ;
     RECT  54.803 22.72 57.397 22.752 ;
     RECT  57.397 13.416 57.451 16.544 ;
     RECT  57.397 21.696 57.466 22.752 ;
     RECT  53.419 5.184 57.635 5.216 ;
     RECT  57.451 13.416 57.635 15.392 ;
     RECT  53.611 43.264 57.635 43.296 ;
     RECT  56.773 48.128 57.635 49.248 ;
     RECT  54.851 54.592 57.635 54.624 ;
     RECT  57.635 13.416 57.731 14.88 ;
     RECT  57.635 49.216 57.827 49.248 ;
     RECT  55.275 28.48 58.163 30.48 ;
     RECT  54.755 78.216 58.261 79.08 ;
     RECT  53.123 62.016 58.549 62.88 ;
     RECT  54.755 67.416 58.597 68.28 ;
     RECT  58.549 62.016 58.613 63.328 ;
     RECT  58.549 64.704 58.613 64.736 ;
     RECT  57.395 2.616 58.645 3.48 ;
     RECT  56.965 75.52 58.645 75.552 ;
     RECT  56.293 60.352 58.667 60.384 ;
     RECT  58.597 66.688 58.667 68.28 ;
     RECT  55.811 72.816 58.677 73.68 ;
     RECT  58.645 75.264 58.677 75.552 ;
     RECT  56.005 32.448 58.739 32.48 ;
     RECT  54.581 35.016 58.739 36.512 ;
     RECT  58.613 62.016 58.787 64.736 ;
     RECT  57.059 7.36 58.883 8.88 ;
     RECT  58.645 0.064 58.987 0.096 ;
     RECT  57.466 22.72 59.125 22.752 ;
     RECT  54.699 24.216 59.125 25.08 ;
     RECT  58.677 72.816 59.315 75.552 ;
     RECT  58.645 2.616 59.891 4.704 ;
     RECT  60.341 10.176 60.419 11.424 ;
     RECT  60.419 10.176 60.467 10.208 ;
     RECT  59.891 2.616 60.533 3.48 ;
     RECT  60.533 1.728 60.611 3.48 ;
     RECT  59.605 42.688 60.755 42.72 ;
     RECT  58.163 29.616 60.901 30.48 ;
     RECT  59.125 22.72 61.035 25.08 ;
     RECT  60.981 26.752 61.054 26.784 ;
     RECT  58.261 76.992 61.141 79.08 ;
     RECT  55.043 18.816 61.525 19.68 ;
     RECT  61.285 54.976 61.525 55.008 ;
     RECT  52.979 56.616 61.525 58.4 ;
     RECT  61.141 76.16 61.571 79.08 ;
     RECT  59.315 72.816 61.573 74.336 ;
     RECT  61.571 76.16 61.573 76.64 ;
     RECT  58.739 35.016 61.669 35.88 ;
     RECT  58.787 62.016 61.669 63.84 ;
     RECT  58.883 8.016 61.941 8.88 ;
     RECT  61.669 6.144 61.995 6.176 ;
     RECT  60.611 2.616 62.126 3.48 ;
     RECT  62.126 1.728 62.195 3.48 ;
     RECT  61.035 24.216 62.197 25.08 ;
     RECT  61.525 71.296 62.197 71.328 ;
     RECT  57.731 13.416 62.261 14.28 ;
     RECT  62.197 70.656 62.291 71.328 ;
     RECT  62.261 13.056 62.339 14.28 ;
     RECT  61.573 72.816 62.483 76.64 ;
     RECT  51.443 45.816 62.533 46.68 ;
     RECT  61.669 48.768 62.533 48.8 ;
     RECT  60.901 29.616 62.725 30.816 ;
     RECT  61.525 54.976 62.771 58.4 ;
     RECT  62.291 71.296 62.915 71.328 ;
     RECT  62.483 76.608 62.915 76.64 ;
     RECT  62.533 45.816 63.299 48.8 ;
     RECT  60.373 60.16 63.299 60.192 ;
     RECT  62.725 29.056 63.491 30.816 ;
     RECT  63.662 60.416 63.731 60.448 ;
     RECT  62.195 2.616 63.733 3.48 ;
     RECT  61.941 8.016 63.781 9.76 ;
     RECT  62.339 13.416 63.781 14.28 ;
     RECT  63.299 48.768 63.781 48.8 ;
     RECT  57.107 51.216 63.781 52.08 ;
     RECT  61.669 62.016 63.781 63.968 ;
     RECT  58.667 67.416 63.781 68.28 ;
     RECT  63.733 1.728 63.827 3.48 ;
     RECT  62.483 72.816 64.098 74.336 ;
     RECT  61.571 78.216 64.117 79.08 ;
     RECT  64.098 72.704 64.171 74.336 ;
     RECT  64.171 72.704 64.43 73.68 ;
     RECT  62.771 56.128 64.491 58.4 ;
     RECT  64.43 72.384 64.499 73.68 ;
     RECT  61.669 35.016 64.565 36.512 ;
     RECT  64.565 35.016 64.619 37.344 ;
     RECT  63.781 62.016 64.643 65.184 ;
     RECT  64.619 37.312 64.693 37.344 ;
     RECT  61.035 22.72 64.757 22.752 ;
     RECT  62.197 24.216 64.757 25.76 ;
     RECT  64.693 37.312 64.762 38.24 ;
     RECT  64.757 22.72 64.811 25.76 ;
     RECT  63.491 29.056 64.811 30.48 ;
     RECT  64.693 44.48 64.933 44.512 ;
     RECT  63.781 48.768 65.027 52.08 ;
     RECT  64.117 78.08 65.027 79.08 ;
     RECT  63.781 13.416 65.171 14.88 ;
     RECT  64.619 35.016 65.221 35.88 ;
     RECT  63.827 2.616 65.333 3.48 ;
     RECT  63.781 67.416 65.365 69.472 ;
     RECT  65.333 70.848 65.365 70.88 ;
     RECT  65.333 1.728 65.411 3.48 ;
     RECT  65.365 67.416 65.411 70.88 ;
     RECT  65.411 67.416 65.451 70.752 ;
     RECT  64.811 22.72 65.603 25.08 ;
     RECT  64.933 43.264 65.603 44.512 ;
     RECT  50.195 40.416 65.989 41.28 ;
     RECT  64.643 62.016 66.085 64.16 ;
     RECT  64.357 54.08 66.357 54.112 ;
     RECT  64.491 56.128 66.357 58.208 ;
     RECT  65.027 48.768 66.373 48.8 ;
     RECT  66.357 54.08 66.411 58.208 ;
     RECT  66.411 54.912 66.467 58.208 ;
     RECT  66.373 48.64 66.485 48.8 ;
     RECT  65.171 13.416 66.517 14.28 ;
     RECT  66.467 55.232 66.539 58.208 ;
     RECT  65.221 34.112 66.661 35.88 ;
     RECT  65.451 67.416 66.707 69.472 ;
     RECT  66.613 75.904 66.709 75.936 ;
     RECT  66.709 75.904 66.755 76.064 ;
     RECT  66.539 55.232 66.803 57.48 ;
     RECT  63.299 45.816 66.853 46.68 ;
     RECT  65.411 2.616 66.926 3.48 ;
     RECT  66.926 1.728 66.995 3.48 ;
     RECT  64.757 27.648 67.093 27.68 ;
     RECT  66.085 62.016 67.125 65.44 ;
     RECT  67.125 62.016 67.179 65.952 ;
     RECT  65.027 51.216 67.573 52.08 ;
     RECT  66.803 55.232 67.667 55.264 ;
     RECT  67.179 65.408 67.667 65.952 ;
     RECT  66.517 13.416 67.701 15.072 ;
     RECT  61.525 18.816 67.701 19.808 ;
     RECT  67.701 18.688 67.755 19.808 ;
     RECT  67.755 18.688 67.774 19.68 ;
     RECT  66.805 70.72 67.859 70.752 ;
     RECT  63.781 8.016 67.909 9.824 ;
     RECT  66.661 34.112 68.099 36 ;
     RECT  67.093 26.752 68.195 27.68 ;
     RECT  67.909 8.016 68.213 10.208 ;
     RECT  65.989 40.416 68.291 41.696 ;
     RECT  65.603 22.72 68.405 22.752 ;
     RECT  67.701 13.416 68.435 16.352 ;
     RECT  66.485 48.64 68.435 48.864 ;
     RECT  66.755 76.032 68.435 76.064 ;
     RECT  68.213 7.616 68.459 10.208 ;
     RECT  66.995 2.616 68.462 3.48 ;
     RECT  68.462 1.728 68.531 3.48 ;
     RECT  68.099 34.112 68.715 35.88 ;
     RECT  64.762 37.312 68.715 37.344 ;
     RECT  68.405 22.528 68.779 22.816 ;
     RECT  68.779 22.784 68.843 22.816 ;
     RECT  68.195 27.52 68.843 27.68 ;
     RECT  67.573 50.304 69.011 52.08 ;
     RECT  68.435 13.416 69.562 15.712 ;
     RECT  66.853 45.632 69.587 46.68 ;
     RECT  64.499 72.704 69.637 73.68 ;
     RECT  68.531 2.616 70.069 3.48 ;
     RECT  70.069 1.728 70.138 3.48 ;
     RECT  68.459 7.616 70.259 10.016 ;
     RECT  69.637 71.616 70.787 73.68 ;
     RECT  69.562 13.416 70.885 14.28 ;
     RECT  69.562 15.68 70.885 15.712 ;
     RECT  69.011 51.216 70.885 52.08 ;
     RECT  70.885 13.416 70.955 15.712 ;
     RECT  70.885 51.216 70.955 53.024 ;
     RECT  65.603 43.264 71.077 43.296 ;
     RECT  70.138 2.24 71.669 3.48 ;
     RECT  71.669 1.728 71.747 3.48 ;
     RECT  69.587 45.816 71.797 46.68 ;
     RECT  71.747 2.24 71.843 3.48 ;
     RECT  68.291 40.416 71.845 41.28 ;
     RECT  71.077 42.944 71.891 43.296 ;
     RECT  67.774 18.816 72.277 19.68 ;
     RECT  65.603 24.216 72.325 25.08 ;
     RECT  72.277 18.816 72.363 20 ;
     RECT  66.803 56.616 72.373 57.48 ;
     RECT  72.373 56.616 72.467 58.208 ;
     RECT  67.667 65.92 73.043 65.952 ;
     RECT  68.715 34.752 73.077 35.88 ;
     RECT  73.07 10.816 73.139 10.848 ;
     RECT  73.077 37.76 73.141 37.792 ;
     RECT  73.141 37.76 73.187 37.92 ;
     RECT  71.843 2.616 73.237 3.48 ;
     RECT  73.237 1.728 73.323 3.48 ;
     RECT  72.277 22.08 73.571 22.112 ;
     RECT  70.955 51.216 73.589 52.08 ;
     RECT  68.435 48.64 73.643 48.672 ;
     RECT  71.891 43.264 73.717 43.296 ;
     RECT  73.717 43.264 73.771 43.808 ;
     RECT  71.797 45.632 73.771 46.68 ;
     RECT  73.589 4.864 73.907 4.896 ;
     RECT  73.771 45.816 74.053 46.68 ;
     RECT  72.085 60.672 74.147 60.704 ;
     RECT  73.589 49.984 74.149 52.08 ;
     RECT  68.843 27.648 74.218 27.68 ;
     RECT  74.218 27.584 74.219 27.68 ;
     RECT  74.149 49.984 74.219 52.192 ;
     RECT  71.845 39.936 74.245 41.28 ;
     RECT  73.187 37.888 74.341 37.92 ;
     RECT  74.245 39.936 74.341 41.44 ;
     RECT  73.477 31.872 74.579 31.904 ;
     RECT  72.325 24.216 74.667 25.184 ;
     RECT  64.811 29.616 74.677 30.48 ;
     RECT  74.613 22.784 74.723 22.816 ;
     RECT  73.077 34.176 74.723 35.88 ;
     RECT  73.323 2.616 74.869 3.48 ;
     RECT  74.869 1.728 74.938 3.48 ;
     RECT  74.053 45.816 74.963 47.776 ;
     RECT  70.955 15.68 75.683 15.712 ;
     RECT  74.341 37.888 75.683 41.44 ;
     RECT  74.938 2.616 75.781 3.48 ;
     RECT  74.581 10.176 75.827 10.208 ;
     RECT  74.219 49.984 75.875 52.08 ;
     RECT  74.677 29.312 75.971 30.48 ;
     RECT  75.875 51.216 76.021 52.08 ;
     RECT  75.683 39.872 76.067 41.44 ;
     RECT  70.259 7.616 76.357 8.88 ;
     RECT  74.963 45.816 76.357 46.68 ;
     RECT  75.683 37.888 76.403 38.048 ;
     RECT  75.781 2.616 76.453 3.744 ;
     RECT  76.453 1.728 76.523 3.744 ;
     RECT  76.357 7.424 76.597 8.88 ;
     RECT  76.597 6.208 76.645 8.88 ;
     RECT  76.645 5.696 76.651 8.88 ;
     RECT  76.651 5.696 76.691 6.24 ;
     RECT  76.691 5.696 76.715 5.728 ;
     RECT  76.021 51.216 76.979 52.96 ;
     RECT  75.733 32.96 77.363 32.992 ;
     RECT  76.651 7.616 77.555 8.88 ;
     RECT  74.219 27.584 77.555 27.616 ;
     RECT  76.403 37.888 77.555 37.92 ;
     RECT  75.971 29.616 77.557 30.48 ;
     RECT  78.037 0.064 78.123 0.096 ;
     RECT  77.555 8.016 78.312 8.88 ;
     RECT  70.955 13.416 78.312 14.28 ;
     RECT  72.363 18.816 78.312 19.68 ;
     RECT  74.667 24.216 78.312 25.08 ;
     RECT  77.557 28.928 78.312 30.48 ;
     RECT  74.723 35.016 78.312 35.88 ;
     RECT  76.067 39.872 78.312 41.28 ;
     RECT  76.357 45.696 78.312 46.68 ;
     RECT  76.979 51.216 78.312 52.08 ;
     RECT  72.467 56.616 78.312 57.48 ;
     RECT  67.179 62.016 78.312 62.88 ;
     RECT  66.707 67.416 78.312 68.28 ;
     RECT  70.787 72.816 78.312 73.68 ;
     RECT  65.027 78.216 78.312 79.08 ;
     RECT  73.771 43.776 78.419 43.808 ;
     RECT  76.523 2.616 78.467 3.744 ;
     RECT  78.312 28.928 78.707 29.904 ;
     RECT  78.312 39.872 78.707 40.704 ;
     RECT  78.312 45.696 78.707 46.104 ;
     RECT  75.733 15.744 78.755 15.776 ;
     RECT  76.885 22.08 78.803 22.112 ;
     RECT  78.467 2.616 78.904 2.904 ;
     RECT  78.312 8.016 78.904 8.304 ;
     RECT  78.312 13.416 78.904 13.704 ;
     RECT  78.312 18.816 78.904 19.104 ;
     RECT  78.312 24.216 78.904 24.504 ;
     RECT  78.707 29.616 78.904 29.904 ;
     RECT  78.312 35.016 78.904 35.304 ;
     RECT  78.707 40.416 78.904 40.704 ;
     RECT  78.707 45.816 78.904 46.104 ;
     RECT  78.312 51.216 78.904 51.504 ;
     RECT  78.312 56.616 78.904 56.904 ;
     RECT  78.312 62.016 78.904 62.304 ;
     RECT  78.312 67.416 78.904 67.704 ;
     RECT  78.312 72.816 78.904 73.104 ;
     RECT  78.312 78.216 78.904 78.504 ;
     RECT  79.669 1.728 79.738 1.76 ;
     RECT  80.869 31.296 82.064 31.328 ;
     RECT  81.445 70.336 82.064 70.368 ;
    LAYER M7 ;
     RECT  9.536 0.035 9.568 0.107 ;
     RECT  12.736 0.035 12.768 0.107 ;
     RECT  22.272 0.035 22.304 0.107 ;
     RECT  30.272 0.035 30.304 0.107 ;
     RECT  33.472 0.035 33.504 0.107 ;
     RECT  38.208 0.035 38.24 0.107 ;
     RECT  39.808 0.035 39.84 0.107 ;
     RECT  43.008 0.035 43.04 0.107 ;
     RECT  54.144 0.035 54.176 0.107 ;
     RECT  58.944 0.035 58.976 0.107 ;
     RECT  78.08 0.035 78.112 0.107 ;
     RECT  44.608 0.035 44.64 0.117 ;
     RECT  27.072 0.035 27.104 0.619 ;
     RECT  35.072 0.035 35.104 0.619 ;
     RECT  19.136 0.035 19.168 1.195 ;
     RECT  41.408 0.035 41.44 1.195 ;
     RECT  4.8 0.035 4.832 1.771 ;
     RECT  6.336 0.035 6.368 1.771 ;
     RECT  7.936 0.035 7.968 1.771 ;
     RECT  11.136 0.035 11.168 1.771 ;
     RECT  14.336 0.035 14.368 1.771 ;
     RECT  15.936 0.035 15.968 1.771 ;
     RECT  20.736 0.035 20.768 1.771 ;
     RECT  25.472 0.035 25.504 1.771 ;
     RECT  28.672 0.035 28.704 1.771 ;
     RECT  31.872 0.035 31.904 1.771 ;
     RECT  36.672 0.035 36.704 1.771 ;
     RECT  46.208 0.035 46.24 1.771 ;
     RECT  47.808 0.035 47.84 1.771 ;
     RECT  49.408 0.035 49.44 1.771 ;
     RECT  55.744 0.035 55.776 1.771 ;
     RECT  57.344 0.035 57.376 1.771 ;
     RECT  60.544 0.035 60.576 1.771 ;
     RECT  62.144 0.035 62.176 1.771 ;
     RECT  63.744 0.035 63.776 1.771 ;
     RECT  65.344 0.035 65.376 1.771 ;
     RECT  66.944 0.035 66.976 1.771 ;
     RECT  68.48 0.035 68.512 1.771 ;
     RECT  70.08 0.035 70.112 1.771 ;
     RECT  71.68 0.035 71.712 1.771 ;
     RECT  74.88 0.035 74.912 1.771 ;
     RECT  76.48 0.035 76.512 1.771 ;
     RECT  79.68 0.035 79.712 1.771 ;
     RECT  3.2 0.035 3.232 2.151 ;
     RECT  23.872 0.035 23.904 2.151 ;
     RECT  46.216 1.771 46.24 2.151 ;
     RECT  51.008 0.035 51.04 2.151 ;
     RECT  52.608 0.035 52.64 2.151 ;
     RECT  73.28 0.035 73.312 2.151 ;
     RECT  70.272 2.229 70.304 3.051 ;
     RECT  67.816 2.151 68.104 3.061 ;
     RECT  43.84 0.117 44.64 3.627 ;
     RECT  23.872 2.151 24.904 3.691 ;
     RECT  46.216 2.151 46.504 3.701 ;
     RECT  46.216 3.701 46.688 3.829 ;
     RECT  17.536 0.035 17.568 4.075 ;
     RECT  13.816 2.151 14.104 4.341 ;
     RECT  19.216 2.151 19.504 4.533 ;
     RECT  51.008 2.151 52.64 4.587 ;
     RECT  73.216 2.151 73.504 4.853 ;
     RECT  40.816 2.151 41.104 5.365 ;
     RECT  76.672 3.701 76.704 5.739 ;
     RECT  46.216 3.829 46.944 5.995 ;
     RECT  62.416 2.151 62.704 6.133 ;
     RECT  53.376 5.173 53.408 6.251 ;
     RECT  44.352 3.627 44.64 6.315 ;
     RECT  24.616 3.691 24.904 6.773 ;
     RECT  44.352 6.315 44.384 6.773 ;
     RECT  43.52 6.773 44.384 6.955 ;
     RECT  23.616 6.773 24.904 7.093 ;
     RECT  26.496 3.957 26.528 7.093 ;
     RECT  23.616 7.093 26.528 7.147 ;
     RECT  6.272 4.341 6.304 7.413 ;
     RECT  5.632 7.413 6.304 7.467 ;
     RECT  44.352 6.955 44.384 7.467 ;
     RECT  76.608 6.197 76.64 7.467 ;
     RECT  73.216 4.853 73.632 7.605 ;
     RECT  46.216 5.995 46.688 7.861 ;
     RECT  23.616 7.147 25.696 7.915 ;
     RECT  73.088 7.605 73.632 8.437 ;
     RECT  13.568 4.341 14.104 8.949 ;
     RECT  30.016 2.151 30.304 8.949 ;
     RECT  19.216 4.533 19.616 9.003 ;
     RECT  13.568 8.949 14.88 9.077 ;
     RECT  35.416 2.151 35.704 9.077 ;
     RECT  33.088 5.749 33.12 9.131 ;
     RECT  38.912 4.533 38.944 9.131 ;
     RECT  40.816 5.365 41.376 9.515 ;
     RECT  67.816 3.061 69.344 9.653 ;
     RECT  67.816 9.653 69.536 9.717 ;
     RECT  24.616 7.915 25.696 9.771 ;
     RECT  61.952 6.133 62.704 9.771 ;
     RECT  53.312 6.325 53.344 9.963 ;
     RECT  51.616 4.587 51.904 10.037 ;
     RECT  73.088 8.437 74.656 10.219 ;
     RECT  5.632 7.467 5.664 10.859 ;
     RECT  13.248 9.077 14.88 10.859 ;
     RECT  46.216 7.861 47.008 10.859 ;
     RECT  73.088 10.219 73.504 10.859 ;
     RECT  34.752 9.077 35.704 11.435 ;
     RECT  60.352 10.165 60.384 11.435 ;
     RECT  46.216 10.859 46.688 11.893 ;
     RECT  45.76 11.893 46.688 11.947 ;
     RECT  19.216 9.003 19.504 13.045 ;
     RECT  62.416 9.771 62.704 13.045 ;
     RECT  54.08 10.037 54.112 13.163 ;
     RECT  8.416 2.151 8.704 13.301 ;
     RECT  30.016 8.949 30.88 13.301 ;
     RECT  67.328 9.717 69.536 13.867 ;
     RECT  13.248 10.859 14.104 13.877 ;
     RECT  67.816 13.867 69.536 14.891 ;
     RECT  13.12 13.877 14.104 15.083 ;
     RECT  57.016 2.151 57.304 15.349 ;
     RECT  24.616 9.771 24.904 15.669 ;
     RECT  73.216 10.859 73.504 15.669 ;
     RECT  28.992 13.301 30.88 15.723 ;
     RECT  70.912 14.389 70.944 15.723 ;
     RECT  29.824 15.723 30.88 15.787 ;
     RECT  67.816 14.891 68.448 16.309 ;
     RECT  51.264 10.037 51.904 16.501 ;
     RECT  45.76 11.947 46.504 16.619 ;
     RECT  8.256 13.301 8.704 17.643 ;
     RECT  29.824 15.787 30.304 17.707 ;
     RECT  51.264 16.501 52.704 18.283 ;
     RECT  19.072 13.045 19.504 18.539 ;
     RECT  33.664 15.925 33.696 18.731 ;
     RECT  38.208 15.029 38.24 18.731 ;
     RECT  49.152 18.677 49.184 19.819 ;
     RECT  62.272 13.045 62.704 19.819 ;
     RECT  67.712 16.309 68.448 19.819 ;
     RECT  24.616 15.669 25.632 20.011 ;
     RECT  72.32 15.669 73.504 20.011 ;
     RECT  5.376 15.925 5.408 20.587 ;
     RECT  22.208 19.189 22.24 20.587 ;
     RECT  45.888 16.619 46.504 20.587 ;
     RECT  43.456 19.893 43.488 21.163 ;
     RECT  57.016 15.349 57.44 21.739 ;
     RECT  40.816 9.515 41.104 22.453 ;
     RECT  51.264 18.283 51.904 22.517 ;
     RECT  67.816 19.819 68.448 22.517 ;
     RECT  40.816 22.453 41.312 22.581 ;
     RECT  67.816 22.517 68.768 22.762 ;
     RECT  73.216 20.011 73.504 22.773 ;
     RECT  17.856 22.773 17.888 23.925 ;
     RECT  51.072 22.517 51.904 24.043 ;
     RECT  8.416 17.643 8.704 24.053 ;
     RECT  40.816 22.581 41.44 24.107 ;
     RECT  46.216 20.587 46.504 24.565 ;
     RECT  46.016 24.565 46.504 24.629 ;
     RECT  73.216 22.773 74.656 25.195 ;
     RECT  24.616 20.011 24.904 25.461 ;
     RECT  30.016 17.707 30.304 25.461 ;
     RECT  45.952 24.629 46.504 25.653 ;
     RECT  17.024 23.925 17.888 25.707 ;
     RECT  45.632 25.653 46.752 25.835 ;
     RECT  3.016 2.151 3.304 26.165 ;
     RECT  54.656 18.613 54.688 26.283 ;
     RECT  29.056 25.461 30.304 26.731 ;
     RECT  60.992 23.861 61.024 26.795 ;
     RECT  8.192 24.053 8.704 27.371 ;
     RECT  51.2 24.043 51.904 27.381 ;
     RECT  73.216 25.195 74.208 27.573 ;
     RECT  39.296 23.285 39.328 28.203 ;
     RECT  27.328 15.733 27.36 28.459 ;
     RECT  30.016 26.731 30.304 28.469 ;
     RECT  40.816 24.107 41.312 28.469 ;
     RECT  3.016 26.165 4.576 28.587 ;
     RECT  24.616 25.461 25.952 29.099 ;
     RECT  64.768 23.861 64.8 29.099 ;
     RECT  40.816 28.469 42.528 30.059 ;
     RECT  73.216 27.573 74.272 30.059 ;
     RECT  17.856 25.707 17.888 30.123 ;
     RECT  73.216 30.059 74.208 30.123 ;
     RECT  46.216 25.835 46.752 30.635 ;
     RECT  53.568 29.237 53.6 30.699 ;
     RECT  55.232 28.469 55.264 30.827 ;
     RECT  24.616 29.099 25.504 31.083 ;
     RECT  19.216 18.539 19.504 31.797 ;
     RECT  35.416 11.435 35.704 31.861 ;
     RECT  57.016 21.739 57.304 32.437 ;
     RECT  19.072 31.797 19.504 32.939 ;
     RECT  13.184 15.083 14.104 33.131 ;
     RECT  3.016 28.587 3.304 33.525 ;
     RECT  13.816 33.131 14.104 33.525 ;
     RECT  29.888 28.469 30.304 33.589 ;
     RECT  23.296 31.861 23.328 33.771 ;
     RECT  50.944 27.381 51.904 33.835 ;
     RECT  29.824 33.589 30.304 33.963 ;
     RECT  34.752 31.861 35.704 34.165 ;
     RECT  73.216 30.123 73.504 34.165 ;
     RECT  34.752 34.165 36.064 34.219 ;
     RECT  43.456 34.165 43.488 34.859 ;
     RECT  13.816 33.525 14.24 34.869 ;
     RECT  19.216 32.939 19.504 34.869 ;
     RECT  31.808 34.741 31.84 34.923 ;
     RECT  67.816 22.762 68.832 34.923 ;
     RECT  26.816 33.909 26.848 35.445 ;
     RECT  26.816 35.445 27.104 35.499 ;
     RECT  56.32 32.437 57.304 36.523 ;
     RECT  13.816 34.869 14.368 36.715 ;
     RECT  64.576 36.469 64.608 37.301 ;
     RECT  64.576 37.301 64.736 37.355 ;
     RECT  67.816 34.923 68.704 37.355 ;
     RECT  73.088 34.165 73.504 37.803 ;
     RECT  44.48 35.445 44.512 37.877 ;
     RECT  44.48 37.877 44.896 37.931 ;
     RECT  48.96 35.445 48.992 38.251 ;
     RECT  64.704 37.355 64.736 38.251 ;
     RECT  3.016 33.525 4.512 38.827 ;
     RECT  54.592 35.445 54.624 38.827 ;
     RECT  73.216 37.803 73.504 39.093 ;
     RECT  18.688 34.869 19.504 39.979 ;
     RECT  73.216 39.093 74.72 39.979 ;
     RECT  27.072 35.499 27.104 40.875 ;
     RECT  35.416 34.219 36.064 40.875 ;
     RECT  40.816 30.059 41.312 41.397 ;
     RECT  44.864 37.931 44.896 41.643 ;
     RECT  30.016 33.963 30.304 42.421 ;
     RECT  8.416 27.371 8.704 42.677 ;
     RECT  29.568 42.421 30.304 43.253 ;
     RECT  73.216 39.979 73.504 43.253 ;
     RECT  13.816 36.715 14.104 44.277 ;
     RECT  51.616 33.835 51.904 44.853 ;
     RECT  73.216 43.253 73.76 45.675 ;
     RECT  53.568 42.741 53.6 46.197 ;
     RECT  53.568 46.197 53.984 46.251 ;
     RECT  50.688 44.853 51.904 46.261 ;
     RECT  50.112 46.261 51.904 46.827 ;
     RECT  8.064 42.677 8.704 47.275 ;
     RECT  17.152 42.549 17.184 47.605 ;
     RECT  17.152 47.605 17.568 47.659 ;
     RECT  13.696 44.277 14.104 47.797 ;
     RECT  29.12 43.253 30.304 47.797 ;
     RECT  44.16 44.853 44.192 47.915 ;
     RECT  29.12 47.797 31.328 48.171 ;
     RECT  5.184 45.557 5.216 48.491 ;
     RECT  17.536 47.659 17.568 49.067 ;
     RECT  30.016 48.171 31.328 49.259 ;
     RECT  73.216 45.675 73.632 49.973 ;
     RECT  53.952 46.251 53.984 50.795 ;
     RECT  8.416 47.275 8.704 50.997 ;
     RECT  19.216 39.979 19.504 51.573 ;
     RECT  35.416 40.875 35.704 51.573 ;
     RECT  73.216 49.973 74.208 52.203 ;
     RECT  18.24 51.573 19.504 52.405 ;
     RECT  17.472 52.405 19.504 52.523 ;
     RECT  27.008 48.117 27.04 52.523 ;
     RECT  47.808 51.637 47.84 52.651 ;
     RECT  34.496 51.573 35.704 53.035 ;
     RECT  66.496 48.821 66.528 54.069 ;
     RECT  50.112 46.827 50.144 54.197 ;
     RECT  30.016 49.259 30.56 54.453 ;
     RECT  30.016 54.453 30.688 54.635 ;
     RECT  7.936 50.997 8.704 55.851 ;
     RECT  30.016 54.635 30.56 55.915 ;
     RECT  66.368 54.069 66.528 55.925 ;
     RECT  67.816 37.355 68.104 55.925 ;
     RECT  35.264 53.035 35.704 56.117 ;
     RECT  62.416 19.819 62.704 56.117 ;
     RECT  66.368 55.925 68.104 56.171 ;
     RECT  24.616 31.083 24.904 56.373 ;
     RECT  17.472 52.523 17.504 56.501 ;
     RECT  16.64 56.501 17.504 56.555 ;
     RECT  40.64 41.397 41.312 57.013 ;
     RECT  73.216 52.203 73.504 57.013 ;
     RECT  10.048 55.797 10.08 57.067 ;
     RECT  70.912 52.981 70.944 57.067 ;
     RECT  24.616 56.373 25.12 57.077 ;
     RECT  24.616 57.077 25.696 57.643 ;
     RECT  50.048 54.197 50.144 58.037 ;
     RECT  49.856 58.037 50.144 58.091 ;
     RECT  49.856 58.091 50.08 58.155 ;
     RECT  62.416 56.117 63.712 58.165 ;
     RECT  66.496 56.171 66.528 58.219 ;
     RECT  72.384 57.013 73.504 58.219 ;
     RECT  40.64 57.013 41.568 58.411 ;
     RECT  6.016 55.541 6.048 58.795 ;
     RECT  24.616 57.643 25.12 58.795 ;
     RECT  16.64 56.555 16.672 59.307 ;
     RECT  35.008 56.117 35.704 59.307 ;
     RECT  43.52 55.093 43.552 59.307 ;
     RECT  30.016 55.915 30.304 59.765 ;
     RECT  62.416 58.165 64.48 60.459 ;
     RECT  46.216 30.635 46.504 60.917 ;
     RECT  8.416 55.851 8.704 61.365 ;
     RECT  46.216 60.917 46.816 61.611 ;
     RECT  39.296 61.493 39.328 62.443 ;
     RECT  49.856 58.155 49.888 63.221 ;
     RECT  57.016 36.523 57.304 63.285 ;
     RECT  58.624 60.341 58.656 63.285 ;
     RECT  3.016 38.827 3.304 63.733 ;
     RECT  51.616 46.827 51.904 63.733 ;
     RECT  30.016 59.765 30.496 63.797 ;
     RECT  37.056 62.453 37.088 63.797 ;
     RECT  67.816 56.171 68.104 63.797 ;
     RECT  37.056 63.797 38.432 63.851 ;
     RECT  48.96 63.221 49.888 63.915 ;
     RECT  12.8 47.797 14.104 64.437 ;
     RECT  17.664 61.877 17.696 64.437 ;
     RECT  19.216 52.523 19.504 64.437 ;
     RECT  12.416 64.437 14.104 64.491 ;
     RECT  17.664 64.437 19.504 64.491 ;
     RECT  57.016 63.285 58.656 64.747 ;
     RECT  37.312 63.851 38.432 64.875 ;
     RECT  24.616 58.795 24.904 64.885 ;
     RECT  18.816 64.491 19.504 65.131 ;
     RECT  54.208 64.309 54.24 65.131 ;
     RECT  51.328 63.733 51.904 65.835 ;
     RECT  67.136 63.797 68.104 65.963 ;
     RECT  24.616 64.885 25.696 66.027 ;
     RECT  8.256 61.365 8.704 66.037 ;
     RECT  35.416 59.307 35.704 66.037 ;
     RECT  37.312 64.875 37.344 66.037 ;
     RECT  49.856 63.915 49.888 66.037 ;
     RECT  49.856 66.037 50.016 66.091 ;
     RECT  43.264 62.453 43.296 66.613 ;
     RECT  35.416 66.037 37.344 66.731 ;
     RECT  58.624 64.747 58.656 66.731 ;
     RECT  35.416 66.731 36.256 66.795 ;
     RECT  27.84 62.453 27.872 67.051 ;
     RECT  30.016 63.797 31.392 67.253 ;
     RECT  7.488 66.037 8.704 67.307 ;
     RECT  10.624 64.565 10.656 67.307 ;
     RECT  19.008 65.131 19.504 67.307 ;
     RECT  43.264 66.613 44.384 67.307 ;
     RECT  46.216 61.611 46.504 67.765 ;
     RECT  64.448 60.459 64.48 67.765 ;
     RECT  3.016 63.733 4.256 67.883 ;
     RECT  43.264 67.307 43.296 67.883 ;
     RECT  30.016 67.253 32.16 68.587 ;
     RECT  46.216 67.765 47.392 68.715 ;
     RECT  51.456 65.835 51.904 68.715 ;
     RECT  8.416 67.307 8.704 68.917 ;
     RECT  30.016 68.587 31.392 69.611 ;
     RECT  62.416 60.459 62.704 70.645 ;
     RECT  64.448 67.765 65.44 70.763 ;
     RECT  12.416 64.491 12.448 71.221 ;
     RECT  46.216 68.715 46.504 71.221 ;
     RECT  62.208 70.645 62.704 71.339 ;
     RECT  11.904 71.221 12.448 71.851 ;
     RECT  28.224 68.917 28.256 71.861 ;
     RECT  30.016 69.611 30.496 71.861 ;
     RECT  28.224 71.861 30.496 71.915 ;
     RECT  8.416 68.917 9.12 72.117 ;
     RECT  13.816 64.491 14.104 72.309 ;
     RECT  51.616 68.715 51.904 72.309 ;
     RECT  11.904 71.851 11.936 72.427 ;
     RECT  49.984 66.091 50.016 72.427 ;
     RECT  64.448 70.763 65.376 72.693 ;
     RECT  64.128 72.693 65.376 72.747 ;
     RECT  29.12 71.915 30.496 73.259 ;
     RECT  46.216 71.221 46.944 74.347 ;
     RECT  8.416 72.117 9.76 74.421 ;
     RECT  19.216 67.307 19.504 74.613 ;
     RECT  7.68 74.421 9.76 74.731 ;
     RECT  13.816 72.309 14.24 74.731 ;
     RECT  8.416 74.731 9.76 75.307 ;
     RECT  58.688 74.293 58.72 75.307 ;
     RECT  18.496 74.613 19.504 75.883 ;
     RECT  22.72 75.189 22.752 75.883 ;
     RECT  29.12 73.259 30.304 76.149 ;
     RECT  62.416 71.339 62.704 76.149 ;
     RECT  5.184 74.741 5.216 76.715 ;
     RECT  44.864 74.293 44.896 77.035 ;
     RECT  51.616 72.309 52.448 77.547 ;
     RECT  61.504 76.149 62.704 77.547 ;
     RECT  29.056 76.149 30.304 78.059 ;
     RECT  64.128 72.747 64.16 78.123 ;
     RECT  3.016 67.883 3.304 79.929 ;
     RECT  8.416 75.307 8.704 79.929 ;
     RECT  13.816 74.731 14.104 79.929 ;
     RECT  19.216 75.883 19.504 79.929 ;
     RECT  24.616 66.027 24.904 79.929 ;
     RECT  30.016 78.059 30.304 79.929 ;
     RECT  35.416 66.795 35.704 79.929 ;
     RECT  40.64 58.411 41.104 79.929 ;
     RECT  46.216 74.347 46.504 79.929 ;
     RECT  51.616 77.547 51.904 79.929 ;
     RECT  57.016 64.747 57.304 79.929 ;
     RECT  62.416 77.547 62.704 79.929 ;
     RECT  67.816 65.963 68.104 79.929 ;
     RECT  73.216 58.219 73.504 79.929 ;
     RECT  78.616 2.151 78.904 79.929 ;
     RECT  40.64 79.929 40.672 81.963 ;
  END
END ot_dsrom_wsrc_mirror
END LIBRARY
